VERSION 5.7 ;
  NOWIREEXTENSIONATPIN ON ;
  DIVIDERCHAR "/" ;
  BUSBITCHARS "[]" ;
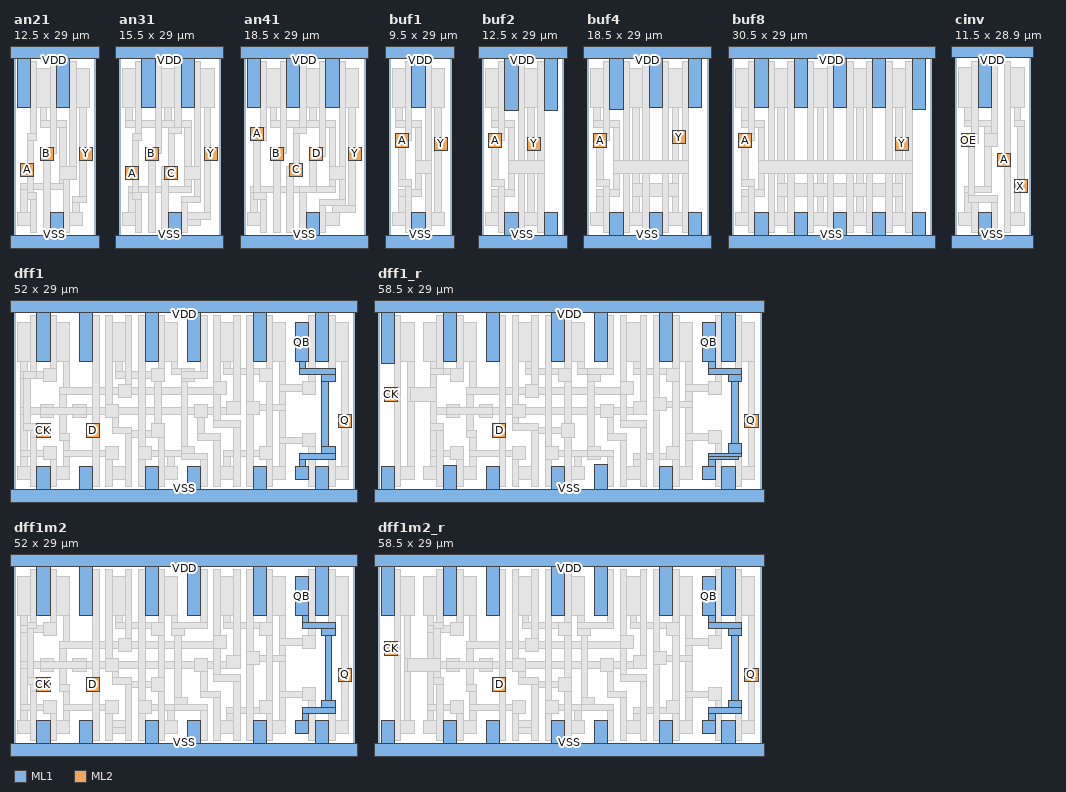
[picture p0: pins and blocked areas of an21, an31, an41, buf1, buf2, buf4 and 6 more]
MACRO an21
  CLASS CORE ;
  FOREIGN an21 ;
  ORIGIN 0.000 0.000 ;
  SIZE 12.500 BY 29.000 ;
  SYMMETRY X Y R90 ;
  SITE core ;
  PIN VSS
    DIRECTION INOUT ;
    USE GROUND ;
    SHAPE ABUTMENT ;
    PORT
      LAYER ML1 ;
        RECT 5.500 1.000 7.500 4.500 ;
        RECT -0.500 -1.000 13.000 1.000 ;
    END
  END VSS
  PIN VDD
    DIRECTION INOUT ;
    USE POWER ;
    SHAPE ABUTMENT ;
    PORT
      LAYER ML1 ;
        RECT -0.500 28.000 13.000 30.000 ;
        RECT 0.500 20.500 2.500 28.000 ;
        RECT 6.500 20.500 8.500 28.000 ;
    END
  END VDD
  PIN A
    DIRECTION INPUT ;
    USE SIGNAL ;
    PORT
      LAYER ML2 ;
        RECT 1.000 10.000 3.000 12.000 ;
    END
  END A
  PIN B
    DIRECTION INPUT ;
    USE SIGNAL ;
    PORT
      LAYER ML2 ;
        RECT 4.000 12.500 6.000 14.500 ;
    END
  END B
  PIN Y
    DIRECTION OUTPUT ;
    USE SIGNAL ;
    PORT
      LAYER ML2 ;
        RECT 10.000 12.500 12.000 14.500 ;
    END
  END Y
  OBS
      LAYER ML1 ;
        RECT 3.500 20.500 5.500 26.500 ;
        RECT 9.500 20.500 11.500 26.500 ;
        RECT 4.000 18.500 5.000 20.500 ;
        RECT 4.000 17.500 8.000 18.500 ;
        RECT 4.000 12.500 6.000 14.500 ;
        RECT 1.000 10.000 3.000 12.000 ;
        RECT 7.000 11.500 8.000 17.500 ;
        RECT 10.000 14.500 11.000 20.500 ;
        RECT 10.000 12.500 12.000 14.500 ;
        RECT 7.000 9.500 9.000 11.500 ;
        RECT 7.000 9.000 8.000 9.500 ;
        RECT 1.000 8.000 8.000 9.000 ;
        RECT 1.000 4.500 2.000 8.000 ;
        RECT 10.000 7.000 11.000 12.500 ;
        RECT 9.000 6.000 11.000 7.000 ;
        RECT 9.000 4.500 10.000 6.000 ;
        RECT 0.500 2.500 2.500 4.500 ;
        RECT 8.500 2.500 10.500 4.500 ;
      LAYER POL ;
        RECT 2.500 16.500 3.500 27.500 ;
        RECT 2.000 15.500 3.500 16.500 ;
        RECT 2.000 12.000 3.000 15.500 ;
        RECT 5.500 14.500 6.500 27.500 ;
        RECT 4.000 13.500 6.500 14.500 ;
        RECT 4.000 12.500 6.000 13.500 ;
        RECT 1.000 10.000 3.000 12.000 ;
        RECT 2.000 7.500 3.000 10.000 ;
        RECT 2.000 6.500 3.500 7.500 ;
        RECT 2.500 1.500 3.500 6.500 ;
        RECT 4.500 1.500 5.500 12.500 ;
        RECT 8.500 11.500 9.500 27.500 ;
        RECT 7.000 9.500 9.500 11.500 ;
        RECT 7.500 1.500 8.500 9.500 ;
  END
END an21

#--------EOF---------

MACRO an31
  CLASS CORE ;
  FOREIGN an31 ;
  ORIGIN 0.000 0.000 ;
  SIZE 15.500 BY 29.000 ;
  SYMMETRY X Y R90 ;
  SITE core ;
  PIN VDD
    DIRECTION INOUT ;
    USE POWER ;
    SHAPE ABUTMENT ;
    PORT
      LAYER ML1 ;
        RECT -0.500 28.000 16.000 30.000 ;
        RECT 3.500 20.500 5.500 28.000 ;
        RECT 9.500 20.500 11.500 28.000 ;
    END
  END VDD
  PIN VSS
    DIRECTION INOUT ;
    USE GROUND ;
    SHAPE ABUTMENT ;
    PORT
      LAYER ML1 ;
        RECT 7.500 1.000 9.500 4.500 ;
        RECT -0.500 -1.000 16.000 1.000 ;
    END
  END VSS
  PIN Y
    DIRECTION OUTPUT ;
    USE SIGNAL ;
    PORT
      LAYER ML2 ;
        RECT 13.000 12.500 15.000 14.500 ;
    END
  END Y
  PIN C
    DIRECTION INPUT ;
    USE SIGNAL ;
    PORT
      LAYER ML2 ;
        RECT 7.000 9.500 9.000 11.500 ;
    END
  END C
  PIN B
    DIRECTION INPUT ;
    USE SIGNAL ;
    PORT
      LAYER ML2 ;
        RECT 4.000 12.500 6.000 14.500 ;
    END
  END B
  PIN A
    DIRECTION INPUT ;
    USE SIGNAL ;
    PORT
      LAYER ML2 ;
        RECT 1.000 9.500 3.000 11.500 ;
    END
  END A
  OBS
      LAYER ML1 ;
        RECT 0.500 20.500 2.500 26.500 ;
        RECT 6.500 20.500 8.500 26.500 ;
        RECT 12.500 20.500 14.500 26.500 ;
        RECT 1.000 18.500 2.000 20.500 ;
        RECT 7.000 18.500 8.000 20.500 ;
        RECT 1.000 17.500 11.000 18.500 ;
        RECT 4.000 12.500 6.000 14.500 ;
        RECT 10.000 11.500 11.000 17.500 ;
        RECT 13.000 14.500 14.000 20.500 ;
        RECT 13.000 12.500 15.000 14.500 ;
        RECT 1.000 9.500 3.000 11.500 ;
        RECT 7.000 9.500 9.000 11.500 ;
        RECT 10.000 9.500 12.000 11.500 ;
        RECT 10.000 8.500 11.000 9.500 ;
        RECT 1.500 7.500 11.000 8.500 ;
        RECT 1.500 4.500 2.500 7.500 ;
        RECT 13.000 4.500 14.000 12.500 ;
        RECT 0.500 2.500 2.500 4.500 ;
        RECT 10.500 3.500 14.000 4.500 ;
        RECT 10.500 2.500 12.500 3.500 ;
      LAYER POL ;
        RECT 2.500 16.500 3.500 27.500 ;
        RECT 2.000 15.500 3.500 16.500 ;
        RECT 2.000 11.500 3.000 15.500 ;
        RECT 5.500 14.500 6.500 27.500 ;
        RECT 8.500 17.500 9.500 27.500 ;
        RECT 4.000 13.500 6.500 14.500 ;
        RECT 7.500 16.500 9.500 17.500 ;
        RECT 4.000 12.500 6.000 13.500 ;
        RECT 1.000 9.500 3.000 11.500 ;
        RECT 2.000 7.500 3.000 9.500 ;
        RECT 2.000 6.500 3.500 7.500 ;
        RECT 2.500 1.500 3.500 6.500 ;
        RECT 4.500 1.500 5.500 12.500 ;
        RECT 7.500 11.500 8.500 16.500 ;
        RECT 11.500 11.500 12.500 27.500 ;
        RECT 6.500 9.500 9.000 11.500 ;
        RECT 10.000 9.500 12.500 11.500 ;
        RECT 6.500 1.500 7.500 9.500 ;
        RECT 11.500 7.000 12.500 9.500 ;
        RECT 9.500 6.000 12.500 7.000 ;
        RECT 9.500 1.500 10.500 6.000 ;
  END
END an31

#--------EOF---------

MACRO an41
  CLASS CORE ;
  FOREIGN an41 ;
  ORIGIN 0.000 0.000 ;
  SIZE 18.500 BY 29.000 ;
  SYMMETRY X Y R90 ;
  SITE core ;
  PIN VSS
    DIRECTION INOUT ;
    USE GROUND ;
    SHAPE ABUTMENT ;
    PORT
      LAYER ML1 ;
        RECT 9.500 1.000 11.500 4.500 ;
        RECT -0.500 -1.000 19.000 1.000 ;
    END
  END VSS
  PIN VDD
    DIRECTION INOUT ;
    USE POWER ;
    SHAPE ABUTMENT ;
    PORT
      LAYER ML1 ;
        RECT -0.500 28.000 19.000 30.000 ;
        RECT 0.500 20.500 2.500 28.000 ;
        RECT 6.500 20.500 8.500 28.000 ;
        RECT 12.500 20.500 14.500 28.000 ;
    END
  END VDD
  PIN Y
    DIRECTION OUTPUT ;
    USE SIGNAL ;
    PORT
      LAYER ML2 ;
        RECT 16.000 12.500 18.000 14.500 ;
    END
  END Y
  PIN D
    DIRECTION INPUT ;
    USE SIGNAL ;
    PORT
      LAYER ML2 ;
        RECT 10.000 12.500 12.000 14.500 ;
    END
  END D
  PIN C
    DIRECTION INPUT ;
    USE SIGNAL ;
    PORT
      LAYER ML2 ;
        RECT 7.000 10.000 9.000 12.000 ;
    END
  END C
  PIN B
    DIRECTION INPUT ;
    USE SIGNAL ;
    PORT
      LAYER ML2 ;
        RECT 4.000 12.500 6.000 14.500 ;
    END
  END B
  PIN A
    DIRECTION INPUT ;
    USE SIGNAL ;
    PORT
      LAYER ML2 ;
        RECT 1.000 15.500 3.000 17.500 ;
    END
  END A
  OBS
      LAYER ML1 ;
        RECT 3.500 20.500 5.500 26.500 ;
        RECT 9.500 20.500 11.500 26.500 ;
        RECT 15.500 20.500 17.500 26.500 ;
        RECT 4.000 18.500 5.000 20.500 ;
        RECT 10.000 18.500 11.000 20.500 ;
        RECT 4.000 17.500 14.000 18.500 ;
        RECT 1.000 15.500 3.000 17.500 ;
        RECT 4.000 12.500 6.000 14.500 ;
        RECT 10.000 12.500 12.000 14.500 ;
        RECT 7.000 10.000 9.000 12.000 ;
        RECT 13.000 11.500 14.000 17.500 ;
        RECT 16.000 14.500 17.000 20.500 ;
        RECT 16.000 12.500 18.000 14.500 ;
        RECT 13.000 9.500 15.000 11.500 ;
        RECT 13.000 8.500 14.000 9.500 ;
        RECT 1.000 7.500 14.000 8.500 ;
        RECT 1.000 4.500 2.000 7.500 ;
        RECT 16.000 5.500 17.000 12.500 ;
        RECT 13.500 4.500 17.000 5.500 ;
        RECT 0.500 2.500 2.500 4.500 ;
        RECT 12.500 2.500 14.500 4.500 ;
      LAYER POL ;
        RECT 2.500 17.500 3.500 27.500 ;
        RECT 1.000 15.500 3.500 17.500 ;
        RECT 1.500 7.500 2.500 15.500 ;
        RECT 5.500 14.500 6.500 27.500 ;
        RECT 8.500 17.500 9.500 27.500 ;
        RECT 4.000 13.500 6.500 14.500 ;
        RECT 7.500 16.500 9.500 17.500 ;
        RECT 4.000 12.500 6.000 13.500 ;
        RECT 1.500 6.500 3.500 7.500 ;
        RECT 2.500 1.500 3.500 6.500 ;
        RECT 4.500 1.500 5.500 12.500 ;
        RECT 7.500 12.000 8.500 16.500 ;
        RECT 11.500 14.500 12.500 27.500 ;
        RECT 10.000 13.000 12.500 14.500 ;
        RECT 10.000 12.500 12.000 13.000 ;
        RECT 7.000 11.500 9.000 12.000 ;
        RECT 6.500 10.000 9.000 11.500 ;
        RECT 6.500 1.500 7.500 10.000 ;
        RECT 10.000 8.500 11.000 12.500 ;
        RECT 14.500 11.500 15.500 27.500 ;
        RECT 13.000 9.500 15.500 11.500 ;
        RECT 8.500 7.500 11.000 8.500 ;
        RECT 8.500 1.500 9.500 7.500 ;
        RECT 14.500 6.500 15.500 9.500 ;
        RECT 11.500 5.500 15.500 6.500 ;
        RECT 11.500 1.500 12.500 5.500 ;
  END
END an41

#--------EOF---------

MACRO buf1
  CLASS CORE ;
  FOREIGN buf1 ;
  ORIGIN 0.000 0.000 ;
  SIZE 9.500 BY 29.000 ;
  SYMMETRY X Y R90 ;
  SITE core ;
  PIN VDD
    DIRECTION INOUT ;
    USE POWER ;
    SHAPE ABUTMENT ;
    PORT
      LAYER ML1 ;
        RECT -0.500 28.000 10.000 30.000 ;
        RECT 3.500 20.500 5.500 28.000 ;
    END
  END VDD
  PIN VSS
    DIRECTION INOUT ;
    USE GROUND ;
    SHAPE ABUTMENT ;
    PORT
      LAYER ML1 ;
        RECT 3.500 1.000 5.500 4.500 ;
        RECT -0.500 -1.000 10.000 1.000 ;
    END
  END VSS
  PIN Y
    DIRECTION OUTPUT ;
    USE SIGNAL ;
    PORT
      LAYER ML2 ;
        RECT 7.000 14.000 9.000 16.000 ;
    END
  END Y
  PIN A
    DIRECTION INPUT ;
    USE SIGNAL ;
    PORT
      LAYER ML2 ;
        RECT 1.000 14.500 3.000 16.500 ;
    END
  END A
  OBS
      LAYER ML1 ;
        RECT 0.500 20.500 2.500 26.500 ;
        RECT 6.500 20.500 8.500 26.500 ;
        RECT 1.000 18.500 2.000 20.500 ;
        RECT 1.000 17.500 5.000 18.500 ;
        RECT 1.000 14.500 3.000 16.500 ;
        RECT 4.000 12.500 5.000 17.500 ;
        RECT 7.000 16.000 8.000 20.500 ;
        RECT 7.000 14.000 9.000 16.000 ;
        RECT 4.000 10.500 6.000 12.500 ;
        RECT 4.000 8.000 5.000 10.500 ;
        RECT 1.500 7.000 5.000 8.000 ;
        RECT 1.500 4.500 2.500 7.000 ;
        RECT 7.000 4.500 8.000 14.000 ;
        RECT 0.500 2.500 2.500 4.500 ;
        RECT 6.500 2.500 8.500 4.500 ;
      LAYER POL ;
        RECT 2.500 16.500 3.500 27.500 ;
        RECT 1.000 15.500 3.500 16.500 ;
        RECT 1.000 14.500 3.000 15.500 ;
        RECT 1.500 9.500 2.500 14.500 ;
        RECT 5.500 12.500 6.500 27.500 ;
        RECT 4.000 10.500 6.500 12.500 ;
        RECT 1.500 8.500 3.500 9.500 ;
        RECT 2.500 1.500 3.500 8.500 ;
        RECT 5.500 1.500 6.500 10.500 ;
  END
END buf1

#--------EOF---------

MACRO buf2
  CLASS CORE ;
  FOREIGN buf2 ;
  ORIGIN 0.000 0.000 ;
  SIZE 12.500 BY 29.000 ;
  SYMMETRY X Y R90 ;
  SITE core ;
  PIN VDD
    DIRECTION INOUT ;
    USE POWER ;
    SHAPE ABUTMENT ;
    PORT
      LAYER ML1 ;
        RECT -0.500 28.000 13.000 30.000 ;
        RECT 3.500 20.000 5.500 28.000 ;
        RECT 9.500 20.000 11.500 28.000 ;
    END
  END VDD
  PIN VSS
    DIRECTION INOUT ;
    USE GROUND ;
    SHAPE ABUTMENT ;
    PORT
      LAYER ML1 ;
        RECT 3.500 1.000 5.500 4.500 ;
        RECT 9.500 1.000 11.500 4.500 ;
        RECT -0.500 -1.000 13.000 1.000 ;
    END
  END VSS
  PIN A
    DIRECTION INPUT ;
    USE SIGNAL ;
    PORT
      LAYER ML2 ;
        RECT 1.000 14.500 3.000 16.500 ;
    END
  END A
  PIN Y
    DIRECTION OUTPUT ;
    USE SIGNAL ;
    PORT
      LAYER ML2 ;
        RECT 7.000 14.000 9.000 16.000 ;
    END
  END Y
  OBS
      LAYER ML1 ;
        RECT 0.500 20.500 2.500 26.500 ;
        RECT 6.500 20.500 8.500 26.500 ;
        RECT 1.500 18.500 2.500 20.500 ;
        RECT 1.500 17.500 5.000 18.500 ;
        RECT 1.000 14.500 3.000 16.500 ;
        RECT 4.000 12.500 5.000 17.500 ;
        RECT 7.000 16.000 8.000 20.500 ;
        RECT 7.000 14.000 9.000 16.000 ;
        RECT 4.000 10.500 6.000 12.500 ;
        RECT 4.000 8.000 5.000 10.500 ;
        RECT 1.500 7.000 5.000 8.000 ;
        RECT 1.500 4.500 2.500 7.000 ;
        RECT 7.000 4.500 8.000 14.000 ;
        RECT 0.500 2.500 2.500 4.500 ;
        RECT 6.500 2.500 8.500 4.500 ;
      LAYER POL ;
        RECT 2.500 16.500 3.500 27.500 ;
        RECT 1.000 15.500 3.500 16.500 ;
        RECT 1.000 14.500 3.000 15.500 ;
        RECT 1.500 9.500 2.500 14.500 ;
        RECT 5.500 12.500 6.500 27.500 ;
        RECT 8.500 12.500 9.500 27.500 ;
        RECT 4.000 10.500 9.500 12.500 ;
        RECT 1.500 8.500 3.500 9.500 ;
        RECT 2.500 1.500 3.500 8.500 ;
        RECT 5.500 1.500 6.500 10.500 ;
        RECT 8.500 1.500 9.500 10.500 ;
  END
END buf2

#--------EOF---------

MACRO buf4
  CLASS CORE ;
  FOREIGN buf4 ;
  ORIGIN 0.000 0.000 ;
  SIZE 18.500 BY 29.000 ;
  SYMMETRY X Y R90 ;
  SITE core ;
  PIN VSS
    DIRECTION INOUT ;
    USE GROUND ;
    SHAPE ABUTMENT ;
    PORT
      LAYER ML1 ;
        RECT 3.500 1.000 5.500 4.500 ;
        RECT 9.500 1.000 11.500 4.500 ;
        RECT 15.500 1.000 17.500 4.500 ;
        RECT -0.500 -1.000 19.000 1.000 ;
    END
  END VSS
  PIN VDD
    DIRECTION INOUT ;
    USE POWER ;
    SHAPE ABUTMENT ;
    PORT
      LAYER ML1 ;
        RECT -0.500 28.000 19.000 30.000 ;
        RECT 3.500 20.200 5.500 28.000 ;
        RECT 9.500 20.500 11.500 28.000 ;
        RECT 15.500 20.500 17.500 28.000 ;
    END
  END VDD
  PIN A
    DIRECTION INPUT ;
    USE SIGNAL ;
    PORT
      LAYER ML2 ;
        RECT 1.000 14.500 3.000 16.500 ;
    END
  END A
  PIN Y
    DIRECTION OUTPUT ;
    USE SIGNAL ;
    PORT
      LAYER ML2 ;
        RECT 13.000 15.000 15.000 17.000 ;
    END
  END Y
  OBS
      LAYER ML1 ;
        RECT 0.500 20.500 2.500 26.500 ;
        RECT 6.500 20.500 8.500 26.500 ;
        RECT 12.500 20.500 14.500 26.500 ;
        RECT 1.000 18.500 2.000 20.500 ;
        RECT 1.000 17.500 5.000 18.500 ;
        RECT 1.000 14.500 3.000 16.500 ;
        RECT 4.000 12.500 5.000 17.500 ;
        RECT 4.000 10.500 6.000 12.500 ;
        RECT 4.000 8.000 5.000 10.500 ;
        RECT 1.500 7.000 5.000 8.000 ;
        RECT 7.000 9.000 8.000 20.500 ;
        RECT 13.000 17.000 14.000 20.500 ;
        RECT 13.000 15.000 15.000 17.000 ;
        RECT 13.000 9.000 14.000 15.000 ;
        RECT 7.000 7.000 14.000 9.000 ;
        RECT 1.500 4.500 2.500 7.000 ;
        RECT 7.000 4.500 8.000 7.000 ;
        RECT 13.000 4.500 14.000 7.000 ;
        RECT 0.500 2.500 2.500 4.500 ;
        RECT 6.500 2.500 8.500 4.500 ;
        RECT 12.500 2.500 14.500 4.500 ;
      LAYER POL ;
        RECT 2.500 16.500 3.500 27.500 ;
        RECT 1.000 15.500 3.500 16.500 ;
        RECT 1.000 14.500 3.000 15.500 ;
        RECT 1.500 9.500 2.500 14.500 ;
        RECT 5.500 12.500 6.500 27.500 ;
        RECT 8.500 12.500 9.500 27.500 ;
        RECT 11.500 12.500 12.500 27.500 ;
        RECT 14.500 12.500 15.500 27.500 ;
        RECT 4.000 10.500 15.500 12.500 ;
        RECT 1.500 8.500 3.500 9.500 ;
        RECT 2.500 1.500 3.500 8.500 ;
        RECT 5.500 1.500 6.500 10.500 ;
        RECT 8.500 1.500 9.500 10.500 ;
        RECT 11.500 1.500 12.500 10.500 ;
        RECT 14.500 1.500 15.500 10.500 ;
  END
END buf4

#--------EOF---------

MACRO buf8
  CLASS CORE ;
  FOREIGN buf8 ;
  ORIGIN 0.000 0.000 ;
  SIZE 30.500 BY 29.000 ;
  SYMMETRY X Y R90 ;
  SITE core ;
  PIN VDD
    DIRECTION INOUT ;
    USE POWER ;
    SHAPE ABUTMENT ;
    PORT
      LAYER ML1 ;
        RECT -0.500 28.000 31.000 30.000 ;
        RECT 3.500 20.500 5.500 28.000 ;
        RECT 9.500 20.500 11.500 28.000 ;
        RECT 15.500 20.500 17.500 28.000 ;
        RECT 21.500 20.500 23.500 28.000 ;
        RECT 27.500 20.300 29.500 28.000 ;
    END
  END VDD
  PIN VSS
    DIRECTION INOUT ;
    USE GROUND ;
    SHAPE ABUTMENT ;
    PORT
      LAYER ML1 ;
        RECT 3.500 1.000 5.500 4.500 ;
        RECT 9.500 1.000 11.500 4.500 ;
        RECT 15.500 1.000 17.500 4.500 ;
        RECT 21.500 1.000 23.500 4.500 ;
        RECT 27.500 1.000 29.500 4.500 ;
        RECT -0.500 -1.000 31.000 1.000 ;
    END
  END VSS
  PIN A
    DIRECTION INPUT ;
    USE SIGNAL ;
    PORT
      LAYER ML2 ;
        RECT 1.000 14.500 3.000 16.500 ;
    END
  END A
  PIN Y
    DIRECTION OUTPUT ;
    USE SIGNAL ;
    PORT
      LAYER ML2 ;
        RECT 25.000 14.000 27.000 16.000 ;
    END
  END Y
  OBS
      LAYER ML1 ;
        RECT 0.500 20.500 2.500 26.500 ;
        RECT 6.500 20.500 8.500 26.500 ;
        RECT 12.500 20.500 14.500 26.500 ;
        RECT 18.500 20.500 20.500 26.500 ;
        RECT 24.500 20.500 26.500 26.500 ;
        RECT 1.500 18.500 2.500 20.500 ;
        RECT 1.500 17.500 5.000 18.500 ;
        RECT 1.000 14.500 3.000 16.500 ;
        RECT 4.000 12.500 5.000 17.500 ;
        RECT 4.000 10.500 6.000 12.500 ;
        RECT 4.000 8.000 5.000 10.500 ;
        RECT 1.500 7.000 5.000 8.000 ;
        RECT 7.000 9.000 8.000 20.500 ;
        RECT 13.000 9.000 14.000 20.500 ;
        RECT 19.000 9.000 20.000 20.500 ;
        RECT 25.000 16.000 26.000 20.500 ;
        RECT 25.000 14.000 27.000 16.000 ;
        RECT 25.000 9.000 26.000 14.000 ;
        RECT 7.000 7.000 26.000 9.000 ;
        RECT 1.500 4.500 2.500 7.000 ;
        RECT 7.000 4.500 8.000 7.000 ;
        RECT 13.000 4.500 14.000 7.000 ;
        RECT 19.000 4.500 20.000 7.000 ;
        RECT 25.000 4.500 26.000 7.000 ;
        RECT 0.500 2.500 2.500 4.500 ;
        RECT 6.500 2.500 8.500 4.500 ;
        RECT 12.500 2.500 14.500 4.500 ;
        RECT 18.500 2.500 20.500 4.500 ;
        RECT 24.500 2.500 26.500 4.500 ;
      LAYER POL ;
        RECT 2.500 16.500 3.500 27.500 ;
        RECT 1.000 15.500 3.500 16.500 ;
        RECT 1.000 14.500 3.000 15.500 ;
        RECT 1.500 9.500 2.500 14.500 ;
        RECT 5.500 12.500 6.500 27.500 ;
        RECT 8.500 12.500 9.500 27.500 ;
        RECT 11.500 12.500 12.500 27.500 ;
        RECT 14.500 12.500 15.500 27.500 ;
        RECT 17.500 12.500 18.500 27.500 ;
        RECT 20.500 12.500 21.500 27.500 ;
        RECT 23.500 12.500 24.500 27.500 ;
        RECT 26.500 12.500 27.500 27.500 ;
        RECT 4.000 10.500 27.500 12.500 ;
        RECT 1.500 8.500 3.500 9.500 ;
        RECT 2.500 1.500 3.500 8.500 ;
        RECT 5.500 1.500 6.500 10.500 ;
        RECT 8.500 1.500 9.500 10.500 ;
        RECT 11.500 1.500 12.500 10.500 ;
        RECT 14.500 1.500 15.500 10.500 ;
        RECT 17.500 1.500 18.500 10.500 ;
        RECT 20.500 1.500 21.500 10.500 ;
        RECT 23.500 1.500 24.500 10.500 ;
        RECT 26.500 1.500 27.500 10.500 ;
  END
END buf8

#--------EOF---------

MACRO cinv
  CLASS CORE ;
  FOREIGN cinv ;
  ORIGIN 0.000 0.000 ;
  SIZE 11.500 BY 28.900 ;
  SYMMETRY X Y R90 ;
  SITE core ;
  PIN VSS
    DIRECTION INOUT ;
    USE GROUND ;
    SHAPE ABUTMENT ;
    PORT
      LAYER ML1 ;
        RECT 3.500 1.000 5.500 4.500 ;
        RECT -0.500 -1.000 12.000 1.000 ;
    END
  END VSS
  PIN VDD
    DIRECTION INOUT ;
    USE POWER ;
    SHAPE ABUTMENT ;
    PORT
      LAYER ML1 ;
        RECT -0.500 28.000 12.000 30.000 ;
        RECT 3.500 20.500 5.500 28.000 ;
    END
  END VDD
  PIN X
    DIRECTION OUTPUT ;
    USE SIGNAL ;
    PORT
      LAYER ML2 ;
        RECT 9.000 7.500 11.000 9.500 ;
    END
  END X
  PIN OE
    DIRECTION INPUT ;
    USE SIGNAL ;
    PORT
      LAYER ML2 ;
        RECT 1.000 14.500 3.000 16.500 ;
    END
  END OE
  PIN A
    DIRECTION INPUT ;
    USE SIGNAL ;
    PORT
      LAYER ML2 ;
        RECT 6.500 11.500 8.500 13.500 ;
    END
  END A
  OBS
      LAYER ML1 ;
        RECT 0.500 20.500 2.500 26.500 ;
        RECT 8.500 20.500 10.500 26.500 ;
        RECT 1.500 18.500 2.500 20.500 ;
        RECT 9.000 18.500 10.000 20.500 ;
        RECT 1.500 17.500 5.500 18.500 ;
        RECT 9.000 17.500 10.500 18.500 ;
        RECT 4.500 16.500 5.500 17.500 ;
        RECT 1.000 14.500 3.000 16.500 ;
        RECT 4.500 14.500 6.500 16.500 ;
        RECT 4.500 8.500 5.500 14.500 ;
        RECT 6.500 11.500 8.500 13.500 ;
        RECT 9.500 9.500 10.500 17.500 ;
        RECT 1.500 7.500 5.500 8.500 ;
        RECT 9.000 7.500 11.000 9.500 ;
        RECT 1.500 4.500 2.500 7.500 ;
        RECT 9.000 4.500 10.000 7.500 ;
        RECT 0.500 2.500 2.500 4.500 ;
        RECT 8.500 2.500 10.500 4.500 ;
      LAYER POL ;
        RECT 2.500 16.500 3.500 27.500 ;
        RECT 5.500 16.500 6.500 27.500 ;
        RECT 1.000 15.000 3.500 16.500 ;
        RECT 1.000 14.500 3.000 15.000 ;
        RECT 4.500 14.500 6.500 16.500 ;
        RECT 2.000 7.000 3.000 14.500 ;
        RECT 7.500 13.500 8.500 27.500 ;
        RECT 6.500 11.500 8.500 13.500 ;
        RECT 2.000 6.000 6.500 7.000 ;
        RECT 2.500 1.500 3.500 6.000 ;
        RECT 5.500 1.500 6.500 6.000 ;
        RECT 7.500 1.500 8.500 11.500 ;
  END
END cinv

#--------EOF---------

MACRO dff1
  CLASS CORE ;
  FOREIGN dff1 ;
  ORIGIN 0.000 0.000 ;
  SIZE 52.000 BY 29.000 ;
  SYMMETRY X Y R90 ;
  SITE core ;
  PIN QB
    DIRECTION INPUT ;
    USE SIGNAL ;
    PORT
      LAYER ML1 ;
        RECT 43.000 20.500 45.000 26.500 ;
        RECT 43.500 19.500 44.500 20.500 ;
        RECT 43.500 18.500 49.000 19.500 ;
        RECT 47.000 17.500 49.000 18.500 ;
        RECT 47.000 7.500 48.000 17.500 ;
        RECT 47.000 6.500 49.000 7.500 ;
        RECT 43.500 5.500 49.000 6.500 ;
        RECT 43.500 4.500 44.500 5.500 ;
        RECT 43.000 2.500 45.000 4.500 ;
    END
  END QB
  PIN VDD
    DIRECTION INOUT ;
    USE POWER ;
    SHAPE ABUTMENT ;
    PORT
      LAYER ML1 ;
        RECT -0.500 28.000 52.500 30.000 ;
        RECT 3.500 20.500 5.500 28.000 ;
        RECT 10.000 20.500 12.000 28.000 ;
        RECT 20.000 20.500 22.000 28.000 ;
        RECT 26.500 20.500 28.500 28.000 ;
        RECT 36.500 20.500 38.500 28.000 ;
        RECT 46.000 20.500 48.000 28.000 ;
    END
  END VDD
  PIN VSS
    DIRECTION INOUT ;
    USE GROUND ;
    SHAPE ABUTMENT ;
    PORT
      LAYER ML1 ;
        RECT 3.500 1.000 5.500 4.500 ;
        RECT 10.000 1.000 12.000 4.500 ;
        RECT 20.000 1.000 22.000 4.500 ;
        RECT 26.500 1.000 28.500 4.500 ;
        RECT 36.500 1.000 38.500 4.500 ;
        RECT 46.000 1.000 48.000 4.500 ;
        RECT -0.500 -1.000 52.500 1.000 ;
    END
  END VSS
  PIN CK
    DIRECTION INPUT ;
    USE SIGNAL ;
    PORT
      LAYER ML2 ;
        RECT 3.500 9.000 5.500 11.000 ;
    END
  END CK
  PIN D
    DIRECTION INPUT ;
    USE SIGNAL ;
    PORT
      LAYER ML2 ;
        RECT 11.000 9.000 13.000 11.000 ;
    END
  END D
  PIN Q
    DIRECTION INPUT ;
    USE SIGNAL ;
    PORT
      LAYER ML2 ;
        RECT 49.500 10.500 51.500 12.500 ;
    END
  END Q
  OBS
      LAYER ML1 ;
        RECT 0.500 20.500 2.500 26.500 ;
        RECT 6.500 20.500 8.500 26.500 ;
        RECT 15.000 20.500 17.000 26.500 ;
        RECT 23.000 20.500 25.000 26.500 ;
        RECT 31.500 20.500 33.500 26.500 ;
        RECT 39.500 20.500 41.500 26.500 ;
        RECT 49.000 20.500 51.000 26.500 ;
        RECT 1.000 19.000 2.000 20.500 ;
        RECT 4.500 19.000 6.500 19.500 ;
        RECT 1.000 18.000 6.500 19.000 ;
        RECT 1.000 13.500 2.000 18.000 ;
        RECT 4.500 17.500 6.500 18.000 ;
        RECT 7.500 16.500 8.500 20.500 ;
        RECT 15.500 19.000 16.500 20.500 ;
        RECT 24.000 19.500 25.000 20.500 ;
        RECT 32.000 19.500 33.000 20.500 ;
        RECT 21.000 19.000 23.000 19.500 ;
        RECT 15.500 18.000 23.000 19.000 ;
        RECT 24.000 18.500 27.500 19.500 ;
        RECT 32.000 18.500 39.500 19.500 ;
        RECT 21.000 17.500 23.000 18.000 ;
        RECT 25.500 17.500 27.500 18.500 ;
        RECT 37.500 17.500 39.500 18.500 ;
        RECT 16.000 16.500 18.000 17.000 ;
        RECT 30.500 16.500 32.500 17.500 ;
        RECT 7.000 15.500 32.500 16.500 ;
        RECT 40.500 17.000 41.500 20.500 ;
        RECT 44.000 17.000 46.000 17.500 ;
        RECT 40.500 16.000 46.000 17.000 ;
        RECT 4.000 13.500 6.000 14.000 ;
        RECT 1.000 12.500 6.000 13.500 ;
        RECT 1.000 7.000 2.000 12.500 ;
        RECT 4.000 12.000 6.000 12.500 ;
        RECT 3.500 9.000 5.500 11.000 ;
        RECT 7.000 9.500 8.000 15.500 ;
        RECT 16.000 15.000 18.000 15.500 ;
        RECT 9.000 13.500 11.000 14.000 ;
        RECT 14.000 13.500 16.000 14.000 ;
        RECT 27.500 13.500 29.500 14.000 ;
        RECT 32.500 13.500 34.500 14.500 ;
        RECT 9.000 12.500 34.500 13.500 ;
        RECT 35.500 14.000 37.500 14.500 ;
        RECT 40.500 14.000 41.500 16.000 ;
        RECT 44.000 15.500 46.000 16.000 ;
        RECT 35.500 13.000 41.500 14.000 ;
        RECT 35.500 12.500 37.500 13.000 ;
        RECT 9.000 12.000 11.000 12.500 ;
        RECT 14.000 12.000 16.000 12.500 ;
        RECT 27.500 12.000 29.500 12.500 ;
        RECT 7.000 8.500 8.500 9.500 ;
        RECT 11.000 9.000 13.000 11.000 ;
        RECT 21.000 10.000 23.000 11.000 ;
        RECT 17.000 9.000 23.000 10.000 ;
        RECT 40.500 9.000 41.500 13.000 ;
        RECT 50.000 12.500 51.000 20.500 ;
        RECT 49.500 10.500 51.500 12.500 ;
        RECT 44.000 9.000 46.000 9.500 ;
        RECT 4.500 7.000 6.500 7.500 ;
        RECT 1.000 6.000 6.500 7.000 ;
        RECT 1.000 4.500 2.000 6.000 ;
        RECT 4.500 5.500 6.500 6.000 ;
        RECT 7.500 7.000 8.500 8.500 ;
        RECT 14.000 7.000 16.000 7.500 ;
        RECT 7.500 6.000 16.000 7.000 ;
        RECT 7.500 4.500 8.500 6.000 ;
        RECT 14.000 5.500 16.000 6.000 ;
        RECT 17.000 4.500 18.000 9.000 ;
        RECT 40.500 8.000 46.000 9.000 ;
        RECT 19.000 7.000 21.000 7.500 ;
        RECT 25.500 7.000 27.500 7.500 ;
        RECT 37.500 7.000 39.500 7.500 ;
        RECT 19.000 6.000 27.500 7.000 ;
        RECT 19.000 5.500 21.000 6.000 ;
        RECT 23.500 4.500 24.500 6.000 ;
        RECT 25.500 5.500 27.500 6.000 ;
        RECT 32.000 6.000 39.500 7.000 ;
        RECT 32.000 4.500 33.000 6.000 ;
        RECT 37.500 5.500 39.500 6.000 ;
        RECT 40.500 4.500 41.500 8.000 ;
        RECT 44.000 7.500 46.000 8.000 ;
        RECT 50.000 4.500 51.000 10.500 ;
        RECT 0.500 2.500 2.500 4.500 ;
        RECT 6.500 2.500 8.500 4.500 ;
        RECT 15.000 2.500 18.000 4.500 ;
        RECT 23.000 2.500 25.000 4.500 ;
        RECT 31.500 2.500 33.500 4.500 ;
        RECT 39.500 2.500 41.500 4.500 ;
        RECT 49.000 2.500 51.000 4.500 ;
      LAYER POL ;
        RECT 2.500 19.000 3.500 27.500 ;
        RECT 5.500 19.500 6.500 27.500 ;
        RECT 1.500 18.000 3.500 19.000 ;
        RECT 1.500 11.000 2.500 18.000 ;
        RECT 4.500 17.500 6.500 19.500 ;
        RECT 4.000 13.500 6.000 14.000 ;
        RECT 9.000 13.500 11.000 14.000 ;
        RECT 4.000 12.500 11.000 13.500 ;
        RECT 4.000 12.000 6.000 12.500 ;
        RECT 9.000 12.000 11.000 12.500 ;
        RECT 12.000 11.000 13.000 27.500 ;
        RECT 14.000 14.000 15.000 27.500 ;
        RECT 17.000 17.000 18.000 27.500 ;
        RECT 16.000 15.000 18.000 17.000 ;
        RECT 14.000 12.000 16.000 14.000 ;
        RECT 1.500 10.000 5.500 11.000 ;
        RECT 2.500 9.000 5.500 10.000 ;
        RECT 11.000 9.000 13.000 11.000 ;
        RECT 15.000 10.500 16.000 12.000 ;
        RECT 15.000 9.500 18.000 10.500 ;
        RECT 2.500 1.500 3.500 9.000 ;
        RECT 4.500 5.500 6.500 7.500 ;
        RECT 5.500 1.500 6.500 5.500 ;
        RECT 12.000 1.500 13.000 9.000 ;
        RECT 14.000 5.500 16.000 7.500 ;
        RECT 14.000 1.500 15.000 5.500 ;
        RECT 17.000 1.500 18.000 9.500 ;
        RECT 19.000 7.500 20.000 27.500 ;
        RECT 22.000 19.500 23.000 27.500 ;
        RECT 21.000 17.500 23.000 19.500 ;
        RECT 25.500 19.000 27.500 19.500 ;
        RECT 28.500 19.000 29.500 27.500 ;
        RECT 25.500 18.000 29.500 19.000 ;
        RECT 25.500 17.500 27.500 18.000 ;
        RECT 30.500 17.500 31.500 27.500 ;
        RECT 21.500 11.000 22.500 17.500 ;
        RECT 21.000 9.000 23.000 11.000 ;
        RECT 19.000 5.500 21.000 7.500 ;
        RECT 19.000 1.500 20.000 5.500 ;
        RECT 22.000 1.500 23.000 9.000 ;
        RECT 25.500 7.500 26.500 17.500 ;
        RECT 30.500 15.500 32.500 17.500 ;
        RECT 27.500 12.000 29.500 14.000 ;
        RECT 28.000 9.500 29.000 12.000 ;
        RECT 30.500 11.500 31.500 15.500 ;
        RECT 33.500 14.500 34.500 27.500 ;
        RECT 32.500 12.500 34.500 14.500 ;
        RECT 35.500 14.500 36.500 27.500 ;
        RECT 38.500 19.500 39.500 27.500 ;
        RECT 37.500 17.500 39.500 19.500 ;
        RECT 45.000 17.500 46.000 27.500 ;
        RECT 48.000 19.500 49.000 27.500 ;
        RECT 47.000 17.500 49.000 19.500 ;
        RECT 35.500 12.500 37.500 14.500 ;
        RECT 30.500 10.500 34.500 11.500 ;
        RECT 28.000 8.500 31.500 9.500 ;
        RECT 25.500 6.500 27.500 7.500 ;
        RECT 25.500 5.500 29.500 6.500 ;
        RECT 28.500 1.500 29.500 5.500 ;
        RECT 30.500 1.500 31.500 8.500 ;
        RECT 33.500 1.500 34.500 10.500 ;
        RECT 35.500 1.500 36.500 12.500 ;
        RECT 38.500 7.500 39.500 17.500 ;
        RECT 44.000 15.500 46.000 17.500 ;
        RECT 44.000 7.500 46.000 9.500 ;
        RECT 37.500 5.500 39.500 7.500 ;
        RECT 38.500 1.500 39.500 5.500 ;
        RECT 45.000 1.500 46.000 7.500 ;
        RECT 47.000 5.500 49.000 7.500 ;
        RECT 48.000 1.500 49.000 5.500 ;
  END
END dff1

#--------EOF---------

MACRO dff1_r
  CLASS CORE ;
  FOREIGN dff1_r ;
  ORIGIN 0.000 0.000 ;
  SIZE 58.500 BY 29.000 ;
  SYMMETRY X Y R90 ;
  SITE core ;
  PIN VSS
    DIRECTION INOUT ;
    USE GROUND ;
    SHAPE ABUTMENT ;
    PORT
      LAYER ML1 ;
        RECT 0.500 1.000 2.500 4.500 ;
        RECT 10.000 1.000 12.000 4.600 ;
        RECT 16.500 1.000 18.500 4.500 ;
        RECT 26.500 1.000 28.500 4.500 ;
        RECT 33.000 1.000 35.000 4.800 ;
        RECT 43.000 1.000 45.000 4.500 ;
        RECT 52.500 1.000 54.500 4.500 ;
        RECT -0.500 -1.000 59.000 1.000 ;
    END
  END VSS
  PIN VDD
    DIRECTION INOUT ;
    USE POWER ;
    SHAPE ABUTMENT ;
    PORT
      LAYER ML1 ;
        RECT -0.500 28.000 59.000 30.000 ;
        RECT 0.500 20.300 2.500 28.000 ;
        RECT 10.000 20.500 12.000 28.000 ;
        RECT 16.500 20.500 18.500 28.000 ;
        RECT 26.500 20.500 28.500 28.000 ;
        RECT 33.000 20.500 35.000 28.000 ;
        RECT 43.000 20.500 45.000 28.000 ;
        RECT 52.500 20.500 54.500 28.000 ;
    END
  END VDD
  PIN QB
    DIRECTION INPUT ;
    USE SIGNAL ;
    PORT
      LAYER ML1 ;
        RECT 49.500 20.500 51.500 26.500 ;
        RECT 50.500 19.500 51.500 20.500 ;
        RECT 50.500 18.500 55.500 19.500 ;
        RECT 53.500 17.500 55.500 18.500 ;
        RECT 54.000 8.000 55.000 17.500 ;
        RECT 53.500 6.500 55.500 8.000 ;
        RECT 50.500 6.000 55.500 6.500 ;
        RECT 50.500 5.500 55.000 6.000 ;
        RECT 50.500 4.500 51.500 5.500 ;
        RECT 49.500 2.500 51.500 4.500 ;
    END
  END QB
  PIN CK
    DIRECTION INPUT ;
    USE SIGNAL ;
    PORT
      LAYER ML2 ;
        RECT 1.000 14.500 3.000 16.500 ;
    END
  END CK
  PIN D
    DIRECTION INPUT ;
    USE SIGNAL ;
    PORT
      LAYER ML2 ;
        RECT 17.500 9.000 19.500 11.000 ;
    END
  END D
  PIN Q
    DIRECTION INPUT ;
    USE SIGNAL ;
    PORT
      LAYER ML2 ;
        RECT 56.000 10.500 58.000 12.500 ;
    END
  END Q
  OBS
      LAYER ML1 ;
        RECT 3.500 20.500 5.500 26.500 ;
        RECT 7.000 20.500 9.000 26.500 ;
        RECT 13.000 20.500 15.000 26.500 ;
        RECT 21.500 20.500 23.500 26.500 ;
        RECT 29.500 20.500 31.500 26.500 ;
        RECT 38.000 20.500 40.000 26.500 ;
        RECT 46.000 20.500 48.000 26.500 ;
        RECT 55.500 20.500 57.500 26.500 ;
        RECT 4.500 16.500 5.500 20.500 ;
        RECT 8.000 19.500 9.000 20.500 ;
        RECT 8.000 18.500 13.000 19.500 ;
        RECT 1.000 14.500 3.000 16.500 ;
        RECT 4.500 14.500 7.000 16.500 ;
        RECT 4.500 4.500 5.500 14.500 ;
        RECT 8.000 13.500 9.000 18.500 ;
        RECT 11.000 17.500 13.000 18.500 ;
        RECT 14.000 16.500 15.000 20.500 ;
        RECT 22.500 19.500 23.500 20.500 ;
        RECT 30.500 19.500 31.500 20.500 ;
        RECT 39.000 19.500 40.000 20.500 ;
        RECT 22.500 18.500 29.500 19.500 ;
        RECT 30.500 18.500 34.000 19.500 ;
        RECT 39.000 18.500 46.000 19.500 ;
        RECT 27.500 17.500 29.500 18.500 ;
        RECT 32.000 17.500 34.000 18.500 ;
        RECT 44.000 17.500 46.000 18.500 ;
        RECT 22.500 16.500 24.500 17.000 ;
        RECT 37.000 16.500 39.000 17.500 ;
        RECT 13.500 15.500 39.000 16.500 ;
        RECT 47.000 17.000 48.000 20.500 ;
        RECT 50.500 17.000 52.500 17.500 ;
        RECT 47.000 16.000 52.500 17.000 ;
        RECT 10.500 13.500 12.500 14.000 ;
        RECT 8.000 12.500 12.500 13.500 ;
        RECT 8.000 7.000 9.000 12.500 ;
        RECT 10.500 12.000 12.500 12.500 ;
        RECT 13.500 10.000 14.500 15.500 ;
        RECT 22.500 15.000 24.500 15.500 ;
        RECT 42.000 14.500 44.000 15.000 ;
        RECT 47.000 14.500 48.000 16.000 ;
        RECT 50.500 15.500 52.500 16.000 ;
        RECT 15.500 13.500 17.500 14.000 ;
        RECT 20.500 13.500 22.500 14.000 ;
        RECT 34.000 13.500 36.000 14.000 ;
        RECT 39.000 13.500 41.000 14.500 ;
        RECT 15.500 12.500 41.000 13.500 ;
        RECT 42.000 13.500 48.000 14.500 ;
        RECT 42.000 13.000 44.000 13.500 ;
        RECT 15.500 12.000 17.500 12.500 ;
        RECT 20.500 12.000 22.500 12.500 ;
        RECT 34.000 12.000 36.000 12.500 ;
        RECT 13.500 9.000 15.000 10.000 ;
        RECT 17.500 9.000 19.500 11.000 ;
        RECT 28.000 10.500 30.000 11.000 ;
        RECT 23.500 9.500 30.000 10.500 ;
        RECT 11.000 7.000 13.000 7.500 ;
        RECT 8.000 6.000 13.000 7.000 ;
        RECT 8.000 4.500 9.000 6.000 ;
        RECT 11.000 5.500 13.000 6.000 ;
        RECT 14.000 7.000 15.000 9.000 ;
        RECT 20.500 7.000 22.500 7.500 ;
        RECT 14.000 6.000 22.500 7.000 ;
        RECT 14.000 4.500 15.000 6.000 ;
        RECT 20.500 5.500 22.500 6.000 ;
        RECT 23.500 4.500 24.500 9.500 ;
        RECT 28.000 9.000 30.000 9.500 ;
        RECT 47.000 9.500 48.000 13.500 ;
        RECT 56.500 12.500 57.500 20.500 ;
        RECT 56.000 10.500 58.000 12.500 ;
        RECT 50.500 9.500 52.500 10.000 ;
        RECT 47.000 8.500 52.500 9.500 ;
        RECT 25.500 7.000 27.500 7.500 ;
        RECT 32.000 7.000 34.000 7.500 ;
        RECT 25.500 6.000 34.000 7.000 ;
        RECT 44.000 6.500 46.000 7.500 ;
        RECT 25.500 5.500 27.500 6.000 ;
        RECT 30.000 4.500 31.000 6.000 ;
        RECT 32.000 5.500 34.000 6.000 ;
        RECT 39.000 5.500 46.000 6.500 ;
        RECT 39.000 4.500 40.000 5.500 ;
        RECT 47.000 4.500 48.000 8.500 ;
        RECT 50.500 8.000 52.500 8.500 ;
        RECT 56.500 4.500 57.500 10.500 ;
        RECT 3.500 2.500 5.500 4.500 ;
        RECT 7.000 2.500 9.000 4.500 ;
        RECT 13.000 2.500 15.000 4.500 ;
        RECT 21.500 2.500 24.500 4.500 ;
        RECT 29.500 2.500 31.500 4.500 ;
        RECT 38.000 2.500 40.000 4.500 ;
        RECT 46.000 2.500 48.000 4.500 ;
        RECT 55.500 2.500 57.500 4.500 ;
      LAYER POL ;
        RECT 2.500 16.500 3.500 27.500 ;
        RECT 9.000 19.500 10.000 27.500 ;
        RECT 12.000 19.500 13.000 27.500 ;
        RECT 8.000 18.500 10.000 19.500 ;
        RECT 8.000 16.500 9.000 18.500 ;
        RECT 11.000 17.500 13.000 19.500 ;
        RECT 1.000 14.500 3.500 16.500 ;
        RECT 5.000 14.500 9.000 16.500 ;
        RECT 2.500 1.500 3.500 14.500 ;
        RECT 8.000 11.000 9.000 14.500 ;
        RECT 10.500 13.500 12.500 14.000 ;
        RECT 15.500 13.500 17.500 14.000 ;
        RECT 10.500 12.500 17.500 13.500 ;
        RECT 10.500 12.000 12.500 12.500 ;
        RECT 15.500 12.000 17.500 12.500 ;
        RECT 18.500 11.000 19.500 27.500 ;
        RECT 8.000 10.000 10.000 11.000 ;
        RECT 9.000 1.500 10.000 10.000 ;
        RECT 17.500 9.000 19.500 11.000 ;
        RECT 20.500 14.000 21.500 27.500 ;
        RECT 23.500 17.000 24.500 27.500 ;
        RECT 22.500 15.000 24.500 17.000 ;
        RECT 20.500 12.000 22.500 14.000 ;
        RECT 20.500 11.000 21.500 12.000 ;
        RECT 20.500 10.000 24.500 11.000 ;
        RECT 11.000 5.500 13.000 7.500 ;
        RECT 12.000 1.500 13.000 5.500 ;
        RECT 18.500 1.500 19.500 9.000 ;
        RECT 20.500 5.500 22.500 7.500 ;
        RECT 20.500 1.500 21.500 5.500 ;
        RECT 23.500 1.500 24.500 10.000 ;
        RECT 25.500 7.500 26.500 27.500 ;
        RECT 28.500 19.500 29.500 27.500 ;
        RECT 35.000 19.500 36.000 27.500 ;
        RECT 27.500 17.500 29.500 19.500 ;
        RECT 28.500 11.000 29.500 17.500 ;
        RECT 32.000 18.500 36.000 19.500 ;
        RECT 32.000 17.500 34.000 18.500 ;
        RECT 37.000 17.500 38.000 27.500 ;
        RECT 28.000 9.000 30.000 11.000 ;
        RECT 25.500 5.500 27.500 7.500 ;
        RECT 25.500 1.500 26.500 5.500 ;
        RECT 28.500 1.500 29.500 9.000 ;
        RECT 32.000 7.500 33.000 17.500 ;
        RECT 37.000 15.500 39.000 17.500 ;
        RECT 34.000 12.000 36.000 14.000 ;
        RECT 35.000 9.500 36.000 12.000 ;
        RECT 37.000 11.500 38.000 15.500 ;
        RECT 40.000 14.500 41.000 27.500 ;
        RECT 39.000 12.500 41.000 14.500 ;
        RECT 42.000 15.000 43.000 27.500 ;
        RECT 45.000 19.500 46.000 27.500 ;
        RECT 44.000 17.500 46.000 19.500 ;
        RECT 51.500 17.500 52.500 27.500 ;
        RECT 54.500 19.500 55.500 27.500 ;
        RECT 53.500 17.500 55.500 19.500 ;
        RECT 42.000 13.000 44.000 15.000 ;
        RECT 37.000 10.500 41.000 11.500 ;
        RECT 35.000 8.500 38.000 9.500 ;
        RECT 32.000 7.000 34.000 7.500 ;
        RECT 32.000 6.000 36.000 7.000 ;
        RECT 32.000 5.500 34.000 6.000 ;
        RECT 35.000 1.500 36.000 6.000 ;
        RECT 37.000 1.500 38.000 8.500 ;
        RECT 40.000 1.500 41.000 10.500 ;
        RECT 42.000 1.500 43.000 13.000 ;
        RECT 45.000 7.500 46.000 17.500 ;
        RECT 50.500 15.500 52.500 17.500 ;
        RECT 50.500 8.000 52.500 10.000 ;
        RECT 44.000 5.500 46.000 7.500 ;
        RECT 45.000 1.500 46.000 5.500 ;
        RECT 51.500 1.500 52.500 8.000 ;
        RECT 53.500 6.000 55.500 8.000 ;
        RECT 54.500 1.500 55.500 6.000 ;
  END
END dff1_r

#--------EOF---------

MACRO dff1m2
  CLASS CORE ;
  FOREIGN dff1m2 ;
  ORIGIN 0.000 0.000 ;
  SIZE 52.000 BY 29.000 ;
  SYMMETRY X Y R90 ;
  SITE core ;
  PIN QB
    DIRECTION INPUT ;
    USE SIGNAL ;
    PORT
      LAYER ML1 ;
        RECT 43.000 20.500 45.000 26.500 ;
        RECT 44.000 19.500 45.000 20.500 ;
        RECT 44.000 18.500 49.000 19.500 ;
        RECT 47.000 17.500 49.000 18.500 ;
        RECT 47.500 7.500 48.500 17.500 ;
        RECT 47.000 6.500 49.000 7.500 ;
        RECT 44.000 5.500 49.000 6.500 ;
        RECT 44.000 4.500 45.000 5.500 ;
        RECT 43.000 2.500 45.000 4.500 ;
    END
  END QB
  PIN VSS
    DIRECTION INOUT ;
    USE GROUND ;
    SHAPE ABUTMENT ;
    PORT
      LAYER ML1 ;
        RECT 3.500 1.000 5.500 4.500 ;
        RECT 10.000 1.000 12.000 4.500 ;
        RECT 20.000 1.000 22.000 4.500 ;
        RECT 26.500 1.000 28.500 4.500 ;
        RECT 36.500 1.000 38.500 4.500 ;
        RECT 46.000 1.000 48.000 4.500 ;
        RECT -0.500 -1.000 52.500 1.000 ;
    END
  END VSS
  PIN VDD
    DIRECTION INOUT ;
    USE POWER ;
    SHAPE ABUTMENT ;
    PORT
      LAYER ML1 ;
        RECT -0.500 28.000 52.500 30.000 ;
        RECT 3.500 20.500 5.500 28.000 ;
        RECT 10.000 20.500 12.000 28.000 ;
        RECT 20.000 20.500 22.000 28.000 ;
        RECT 26.500 20.500 28.500 28.000 ;
        RECT 36.500 20.500 38.500 28.000 ;
        RECT 46.000 20.500 48.000 28.000 ;
    END
  END VDD
  PIN CK
    DIRECTION INPUT ;
    USE SIGNAL ;
    PORT
      LAYER ML2 ;
        RECT 3.500 9.000 5.500 11.000 ;
    END
  END CK
  PIN D
    DIRECTION INPUT ;
    USE SIGNAL ;
    PORT
      LAYER ML2 ;
        RECT 11.000 9.000 13.000 11.000 ;
    END
  END D
  PIN Q
    DIRECTION INPUT ;
    USE SIGNAL ;
    PORT
      LAYER ML2 ;
        RECT 49.500 10.500 51.500 12.500 ;
    END
  END Q
  OBS
      LAYER ML1 ;
        RECT 0.500 20.500 2.500 26.500 ;
        RECT 6.500 20.500 8.500 26.500 ;
        RECT 15.000 20.500 17.000 26.500 ;
        RECT 23.000 20.500 25.000 26.500 ;
        RECT 31.500 20.500 33.500 26.500 ;
        RECT 39.500 20.500 41.500 26.500 ;
        RECT 49.000 20.500 51.000 26.500 ;
        RECT 1.000 19.000 2.000 20.500 ;
        RECT 4.500 19.000 6.500 19.500 ;
        RECT 1.000 18.000 6.500 19.000 ;
        RECT 1.000 13.500 2.000 18.000 ;
        RECT 4.500 17.500 6.500 18.000 ;
        RECT 7.500 16.500 8.500 20.500 ;
        RECT 15.500 19.500 16.500 20.500 ;
        RECT 24.000 19.500 25.000 20.500 ;
        RECT 32.000 19.500 33.000 20.500 ;
        RECT 15.500 18.500 23.000 19.500 ;
        RECT 21.000 17.500 23.000 18.500 ;
        RECT 24.000 17.500 26.000 19.500 ;
        RECT 32.000 18.500 39.500 19.500 ;
        RECT 37.500 17.500 39.500 18.500 ;
        RECT 16.000 16.500 18.000 17.000 ;
        RECT 30.500 16.500 32.500 17.500 ;
        RECT 7.000 15.500 32.500 16.500 ;
        RECT 40.500 17.000 41.500 20.500 ;
        RECT 44.000 17.000 46.000 17.500 ;
        RECT 40.500 16.000 46.000 17.000 ;
        RECT 4.000 13.500 6.000 14.000 ;
        RECT 1.000 12.500 6.000 13.500 ;
        RECT 1.000 7.000 2.000 12.500 ;
        RECT 4.000 12.000 6.000 12.500 ;
        RECT 3.500 9.000 5.500 11.000 ;
        RECT 7.000 10.000 8.000 15.500 ;
        RECT 16.000 15.000 18.000 15.500 ;
        RECT 35.500 14.500 37.500 15.000 ;
        RECT 40.500 14.500 41.500 16.000 ;
        RECT 44.000 15.500 46.000 16.000 ;
        RECT 9.000 13.500 11.000 14.000 ;
        RECT 14.000 13.500 16.000 14.000 ;
        RECT 27.500 13.500 29.500 14.000 ;
        RECT 32.500 13.500 34.500 14.500 ;
        RECT 9.000 12.500 34.500 13.500 ;
        RECT 35.500 13.500 41.500 14.500 ;
        RECT 35.500 13.000 37.500 13.500 ;
        RECT 9.000 12.000 11.000 12.500 ;
        RECT 14.000 12.000 16.000 12.500 ;
        RECT 27.500 12.000 29.500 12.500 ;
        RECT 7.000 9.000 8.500 10.000 ;
        RECT 11.000 9.000 13.000 11.000 ;
        RECT 21.000 10.500 23.000 11.000 ;
        RECT 17.000 9.500 23.000 10.500 ;
        RECT 4.500 7.000 6.500 7.500 ;
        RECT 1.000 6.000 6.500 7.000 ;
        RECT 1.000 4.500 2.000 6.000 ;
        RECT 4.500 5.500 6.500 6.000 ;
        RECT 7.500 7.000 8.500 9.000 ;
        RECT 14.000 7.000 16.000 7.500 ;
        RECT 7.500 6.000 16.000 7.000 ;
        RECT 7.500 4.500 8.500 6.000 ;
        RECT 14.000 5.500 16.000 6.000 ;
        RECT 17.000 4.500 18.000 9.500 ;
        RECT 21.000 9.000 23.000 9.500 ;
        RECT 40.500 9.000 41.500 13.500 ;
        RECT 50.000 12.500 51.000 20.500 ;
        RECT 49.500 10.500 51.500 12.500 ;
        RECT 44.000 9.000 46.000 9.500 ;
        RECT 40.500 8.000 46.000 9.000 ;
        RECT 19.000 7.000 21.000 7.500 ;
        RECT 24.500 7.000 26.500 8.000 ;
        RECT 19.000 6.000 26.500 7.000 ;
        RECT 37.500 6.500 39.500 7.500 ;
        RECT 19.000 5.500 21.000 6.000 ;
        RECT 23.500 4.500 24.500 6.000 ;
        RECT 32.500 5.500 39.500 6.500 ;
        RECT 32.500 4.500 33.500 5.500 ;
        RECT 40.500 4.500 41.500 8.000 ;
        RECT 44.000 7.500 46.000 8.000 ;
        RECT 50.000 4.500 51.000 10.500 ;
        RECT 0.500 2.500 2.500 4.500 ;
        RECT 6.500 2.500 8.500 4.500 ;
        RECT 15.000 3.500 18.000 4.500 ;
        RECT 15.000 2.500 17.000 3.500 ;
        RECT 23.000 2.500 25.000 4.500 ;
        RECT 31.500 2.500 33.500 4.500 ;
        RECT 39.500 2.500 41.500 4.500 ;
        RECT 49.000 2.500 51.000 4.500 ;
      LAYER ML2 ;
        RECT 21.000 17.500 23.000 19.500 ;
        RECT 24.000 17.500 26.000 19.500 ;
        RECT 37.500 17.500 39.500 19.500 ;
        RECT 22.000 11.000 23.000 17.500 ;
        RECT 21.000 9.000 23.000 11.000 ;
        RECT 24.500 8.000 25.500 17.500 ;
        RECT 24.500 6.000 26.500 8.000 ;
        RECT 38.500 7.500 39.500 17.500 ;
        RECT 37.500 5.500 39.500 7.500 ;
      LAYER POL ;
        RECT 2.500 19.500 3.500 27.500 ;
        RECT 5.500 19.500 6.500 27.500 ;
        RECT 2.000 18.500 3.500 19.500 ;
        RECT 2.000 11.000 3.000 18.500 ;
        RECT 4.500 17.500 6.500 19.500 ;
        RECT 4.000 13.500 6.000 14.000 ;
        RECT 9.000 13.500 11.000 14.000 ;
        RECT 4.000 12.500 11.000 13.500 ;
        RECT 4.000 12.000 6.000 12.500 ;
        RECT 9.000 12.000 11.000 12.500 ;
        RECT 12.000 11.000 13.000 27.500 ;
        RECT 14.000 14.000 15.000 27.500 ;
        RECT 17.000 17.000 18.000 27.500 ;
        RECT 16.000 15.000 18.000 17.000 ;
        RECT 14.000 12.000 16.000 14.000 ;
        RECT 2.000 10.000 5.500 11.000 ;
        RECT 2.500 9.000 5.500 10.000 ;
        RECT 11.000 9.000 13.000 11.000 ;
        RECT 15.000 11.000 16.000 12.000 ;
        RECT 15.000 10.000 18.000 11.000 ;
        RECT 2.500 1.500 3.500 9.000 ;
        RECT 4.500 5.500 6.500 7.500 ;
        RECT 5.500 1.500 6.500 5.500 ;
        RECT 12.000 1.500 13.000 9.000 ;
        RECT 14.000 5.500 16.000 7.500 ;
        RECT 14.000 1.500 15.000 5.500 ;
        RECT 17.000 1.500 18.000 10.000 ;
        RECT 19.000 7.500 20.000 27.500 ;
        RECT 22.000 19.500 23.000 27.500 ;
        RECT 28.500 19.500 29.500 27.500 ;
        RECT 21.000 17.500 23.000 19.500 ;
        RECT 24.000 18.500 29.500 19.500 ;
        RECT 24.000 17.500 26.000 18.500 ;
        RECT 30.500 17.500 31.500 27.500 ;
        RECT 30.500 15.500 32.500 17.500 ;
        RECT 27.500 12.000 29.500 14.000 ;
        RECT 21.000 9.000 23.000 11.000 ;
        RECT 19.000 5.500 21.000 7.500 ;
        RECT 19.000 1.500 20.000 5.500 ;
        RECT 22.000 1.500 23.000 9.000 ;
        RECT 28.500 9.000 29.500 12.000 ;
        RECT 30.500 11.500 31.500 15.500 ;
        RECT 33.500 14.500 34.500 27.500 ;
        RECT 32.500 12.500 34.500 14.500 ;
        RECT 35.500 15.000 36.500 27.500 ;
        RECT 38.500 19.500 39.500 27.500 ;
        RECT 37.500 17.500 39.500 19.500 ;
        RECT 45.000 17.500 46.000 27.500 ;
        RECT 48.000 19.500 49.000 27.500 ;
        RECT 47.000 17.500 49.000 19.500 ;
        RECT 44.000 15.500 46.000 17.500 ;
        RECT 35.500 13.000 37.500 15.000 ;
        RECT 30.500 10.500 34.500 11.500 ;
        RECT 28.500 8.000 31.500 9.000 ;
        RECT 24.500 7.000 26.500 8.000 ;
        RECT 24.500 6.000 29.500 7.000 ;
        RECT 28.500 1.500 29.500 6.000 ;
        RECT 30.500 1.500 31.500 8.000 ;
        RECT 33.500 1.500 34.500 10.500 ;
        RECT 35.500 1.500 36.500 13.000 ;
        RECT 44.000 7.500 46.000 9.500 ;
        RECT 37.500 5.500 39.500 7.500 ;
        RECT 38.500 1.500 39.500 5.500 ;
        RECT 45.000 1.500 46.000 7.500 ;
        RECT 47.000 5.500 49.000 7.500 ;
        RECT 48.000 1.500 49.000 5.500 ;
  END
END dff1m2

#--------EOF---------

MACRO dff1m2_r
  CLASS CORE ;
  FOREIGN dff1m2_r ;
  ORIGIN 0.000 0.000 ;
  SIZE 58.500 BY 29.000 ;
  SYMMETRY X Y R90 ;
  SITE core ;
  PIN QB
    DIRECTION INPUT ;
    USE SIGNAL ;
    PORT
      LAYER ML1 ;
        RECT 49.500 20.500 51.500 26.500 ;
        RECT 50.500 19.500 51.500 20.500 ;
        RECT 50.500 18.500 55.500 19.500 ;
        RECT 53.500 17.500 55.500 18.500 ;
        RECT 54.000 7.500 55.000 17.500 ;
        RECT 53.500 6.500 55.500 7.500 ;
        RECT 50.500 5.500 55.500 6.500 ;
        RECT 50.500 4.500 51.500 5.500 ;
        RECT 49.500 2.500 51.500 4.500 ;
    END
  END QB
  PIN VDD
    DIRECTION INOUT ;
    USE POWER ;
    SHAPE ABUTMENT ;
    PORT
      LAYER ML1 ;
        RECT -0.500 28.000 59.000 30.000 ;
        RECT 0.500 20.500 2.500 28.000 ;
        RECT 10.000 20.500 12.000 28.000 ;
        RECT 16.500 20.500 18.500 28.000 ;
        RECT 26.500 20.500 28.500 28.000 ;
        RECT 33.000 20.500 35.000 28.000 ;
        RECT 43.000 20.500 45.000 28.000 ;
        RECT 52.500 20.500 54.500 28.000 ;
    END
  END VDD
  PIN VSS
    DIRECTION INOUT ;
    USE GROUND ;
    SHAPE ABUTMENT ;
    PORT
      LAYER ML1 ;
        RECT 0.500 1.000 2.500 4.500 ;
        RECT 10.000 1.000 12.000 4.500 ;
        RECT 16.500 1.000 18.500 4.500 ;
        RECT 26.500 1.000 28.500 4.500 ;
        RECT 33.000 1.000 35.000 4.500 ;
        RECT 43.000 1.000 45.000 4.500 ;
        RECT 52.500 1.000 54.500 4.500 ;
        RECT -0.500 -1.000 59.000 1.000 ;
    END
  END VSS
  PIN CK
    DIRECTION INPUT ;
    USE SIGNAL ;
    PORT
      LAYER ML2 ;
        RECT 1.000 14.500 3.000 16.500 ;
    END
  END CK
  PIN D
    DIRECTION INPUT ;
    USE SIGNAL ;
    PORT
      LAYER ML2 ;
        RECT 17.500 9.000 19.500 11.000 ;
    END
  END D
  PIN Q
    DIRECTION INPUT ;
    USE SIGNAL ;
    PORT
      LAYER ML2 ;
        RECT 56.000 10.500 58.000 12.500 ;
    END
  END Q
  OBS
      LAYER ML1 ;
        RECT 3.500 20.500 5.500 26.500 ;
        RECT 7.000 20.500 9.000 26.500 ;
        RECT 13.000 20.500 15.000 26.500 ;
        RECT 21.500 20.500 23.500 26.500 ;
        RECT 29.500 20.500 31.500 26.500 ;
        RECT 38.000 20.500 40.000 26.500 ;
        RECT 46.000 20.500 48.000 26.500 ;
        RECT 55.500 20.500 57.500 26.500 ;
        RECT 1.000 14.500 3.000 16.500 ;
        RECT 4.000 14.000 5.000 20.500 ;
        RECT 7.500 19.000 8.500 20.500 ;
        RECT 11.000 19.000 13.000 19.500 ;
        RECT 7.500 18.000 13.000 19.000 ;
        RECT 4.000 12.000 6.500 14.000 ;
        RECT 7.500 13.500 8.500 18.000 ;
        RECT 11.000 17.500 13.000 18.000 ;
        RECT 14.000 16.500 15.000 20.500 ;
        RECT 22.000 19.500 23.000 20.500 ;
        RECT 30.500 19.500 31.500 20.500 ;
        RECT 38.500 19.500 39.500 20.500 ;
        RECT 22.000 18.500 29.500 19.500 ;
        RECT 27.500 17.500 29.500 18.500 ;
        RECT 30.500 17.500 32.500 19.500 ;
        RECT 38.500 18.500 46.000 19.500 ;
        RECT 44.000 17.500 46.000 18.500 ;
        RECT 22.500 16.500 24.500 17.000 ;
        RECT 37.000 16.500 39.000 17.500 ;
        RECT 13.500 15.500 39.000 16.500 ;
        RECT 47.000 17.000 48.000 20.500 ;
        RECT 50.500 17.000 52.500 17.500 ;
        RECT 47.000 16.000 52.500 17.000 ;
        RECT 10.500 13.500 12.500 14.000 ;
        RECT 7.500 12.500 12.500 13.500 ;
        RECT 4.000 4.500 5.000 12.000 ;
        RECT 7.500 7.000 8.500 12.500 ;
        RECT 10.500 12.000 12.500 12.500 ;
        RECT 13.500 10.000 14.500 15.500 ;
        RECT 22.500 15.000 24.500 15.500 ;
        RECT 42.000 14.500 44.000 15.000 ;
        RECT 47.000 14.500 48.000 16.000 ;
        RECT 50.500 15.500 52.500 16.000 ;
        RECT 15.500 13.500 17.500 14.000 ;
        RECT 20.500 13.500 22.500 14.000 ;
        RECT 34.000 13.500 36.000 14.000 ;
        RECT 39.000 13.500 41.000 14.500 ;
        RECT 15.500 12.500 41.000 13.500 ;
        RECT 42.000 13.500 48.000 14.500 ;
        RECT 42.000 13.000 44.000 13.500 ;
        RECT 15.500 12.000 17.500 12.500 ;
        RECT 20.500 12.000 22.500 12.500 ;
        RECT 34.000 12.000 36.000 12.500 ;
        RECT 13.500 9.000 15.000 10.000 ;
        RECT 17.500 9.000 19.500 11.000 ;
        RECT 27.500 10.500 29.500 11.000 ;
        RECT 23.500 9.500 29.500 10.500 ;
        RECT 11.000 7.000 13.000 7.500 ;
        RECT 7.500 6.000 13.000 7.000 ;
        RECT 7.500 4.500 8.500 6.000 ;
        RECT 11.000 5.500 13.000 6.000 ;
        RECT 14.000 7.000 15.000 9.000 ;
        RECT 20.500 7.000 22.500 7.500 ;
        RECT 14.000 6.000 22.500 7.000 ;
        RECT 14.000 4.500 15.000 6.000 ;
        RECT 20.500 5.500 22.500 6.000 ;
        RECT 23.500 4.500 24.500 9.500 ;
        RECT 27.500 9.000 29.500 9.500 ;
        RECT 47.000 9.000 48.000 13.500 ;
        RECT 56.500 12.500 57.500 20.500 ;
        RECT 56.000 10.500 58.000 12.500 ;
        RECT 50.500 9.000 52.500 9.500 ;
        RECT 47.000 8.000 52.500 9.000 ;
        RECT 25.500 7.000 27.500 7.500 ;
        RECT 31.000 7.000 33.000 8.000 ;
        RECT 25.500 6.000 33.000 7.000 ;
        RECT 44.000 6.500 46.000 7.500 ;
        RECT 25.500 5.500 27.500 6.000 ;
        RECT 30.000 4.500 31.000 6.000 ;
        RECT 39.000 5.500 46.000 6.500 ;
        RECT 39.000 4.500 40.000 5.500 ;
        RECT 47.000 4.500 48.000 8.000 ;
        RECT 50.500 7.500 52.500 8.000 ;
        RECT 56.500 4.500 57.500 10.500 ;
        RECT 3.500 2.500 5.500 4.500 ;
        RECT 7.000 2.500 9.000 4.500 ;
        RECT 13.000 2.500 15.000 4.500 ;
        RECT 21.500 3.500 24.500 4.500 ;
        RECT 21.500 2.500 23.500 3.500 ;
        RECT 29.500 2.500 31.500 4.500 ;
        RECT 38.000 2.500 40.000 4.500 ;
        RECT 46.000 2.500 48.000 4.500 ;
        RECT 55.500 2.500 57.500 4.500 ;
      LAYER ML2 ;
        RECT 27.500 17.500 29.500 19.500 ;
        RECT 30.500 17.500 32.500 19.500 ;
        RECT 44.000 17.500 46.000 19.500 ;
        RECT 28.500 11.000 29.500 17.500 ;
        RECT 27.500 9.000 29.500 11.000 ;
        RECT 31.000 8.000 32.000 17.500 ;
        RECT 31.000 6.000 33.000 8.000 ;
        RECT 45.000 7.500 46.000 17.500 ;
        RECT 44.000 5.500 46.000 7.500 ;
      LAYER POL ;
        RECT 2.500 16.500 3.500 27.500 ;
        RECT 9.000 19.500 10.000 27.500 ;
        RECT 12.000 19.500 13.000 27.500 ;
        RECT 1.000 14.500 3.500 16.500 ;
        RECT 2.500 1.500 3.500 14.500 ;
        RECT 8.500 18.500 10.000 19.500 ;
        RECT 8.500 14.000 9.500 18.500 ;
        RECT 11.000 17.500 13.000 19.500 ;
        RECT 4.500 12.000 9.500 14.000 ;
        RECT 10.500 13.500 12.500 14.000 ;
        RECT 15.500 13.500 17.500 14.000 ;
        RECT 10.500 12.500 17.500 13.500 ;
        RECT 10.500 12.000 12.500 12.500 ;
        RECT 15.500 12.000 17.500 12.500 ;
        RECT 8.500 11.000 9.500 12.000 ;
        RECT 18.500 11.000 19.500 27.500 ;
        RECT 20.500 14.000 21.500 27.500 ;
        RECT 23.500 17.000 24.500 27.500 ;
        RECT 22.500 15.000 24.500 17.000 ;
        RECT 20.500 12.000 22.500 14.000 ;
        RECT 8.500 10.000 10.000 11.000 ;
        RECT 9.000 1.500 10.000 10.000 ;
        RECT 17.500 9.000 19.500 11.000 ;
        RECT 21.500 11.000 22.500 12.000 ;
        RECT 21.500 10.000 24.500 11.000 ;
        RECT 11.000 5.500 13.000 7.500 ;
        RECT 12.000 1.500 13.000 5.500 ;
        RECT 18.500 1.500 19.500 9.000 ;
        RECT 20.500 5.500 22.500 7.500 ;
        RECT 20.500 1.500 21.500 5.500 ;
        RECT 23.500 1.500 24.500 10.000 ;
        RECT 25.500 7.500 26.500 27.500 ;
        RECT 28.500 19.500 29.500 27.500 ;
        RECT 35.000 19.500 36.000 27.500 ;
        RECT 27.500 17.500 29.500 19.500 ;
        RECT 30.500 18.500 36.000 19.500 ;
        RECT 30.500 17.500 32.500 18.500 ;
        RECT 37.000 17.500 38.000 27.500 ;
        RECT 37.000 15.500 39.000 17.500 ;
        RECT 34.000 12.000 36.000 14.000 ;
        RECT 27.500 9.000 29.500 11.000 ;
        RECT 25.500 5.500 27.500 7.500 ;
        RECT 25.500 1.500 26.500 5.500 ;
        RECT 28.500 1.500 29.500 9.000 ;
        RECT 35.000 9.000 36.000 12.000 ;
        RECT 37.000 11.500 38.000 15.500 ;
        RECT 40.000 14.500 41.000 27.500 ;
        RECT 39.000 12.500 41.000 14.500 ;
        RECT 42.000 15.000 43.000 27.500 ;
        RECT 45.000 19.500 46.000 27.500 ;
        RECT 44.000 17.500 46.000 19.500 ;
        RECT 51.500 17.500 52.500 27.500 ;
        RECT 54.500 19.500 55.500 27.500 ;
        RECT 53.500 17.500 55.500 19.500 ;
        RECT 50.500 15.500 52.500 17.500 ;
        RECT 42.000 13.000 44.000 15.000 ;
        RECT 37.000 10.500 41.000 11.500 ;
        RECT 35.000 8.000 38.000 9.000 ;
        RECT 31.000 7.000 33.000 8.000 ;
        RECT 31.000 6.000 36.000 7.000 ;
        RECT 35.000 1.500 36.000 6.000 ;
        RECT 37.000 1.500 38.000 8.000 ;
        RECT 40.000 1.500 41.000 10.500 ;
        RECT 42.000 1.500 43.000 13.000 ;
        RECT 50.500 7.500 52.500 9.500 ;
        RECT 44.000 5.500 46.000 7.500 ;
        RECT 45.000 1.500 46.000 5.500 ;
        RECT 51.500 1.500 52.500 7.500 ;
        RECT 53.500 5.500 55.500 7.500 ;
        RECT 54.500 1.500 55.500 5.500 ;
  END
END dff1m2_r

#--------EOF---------

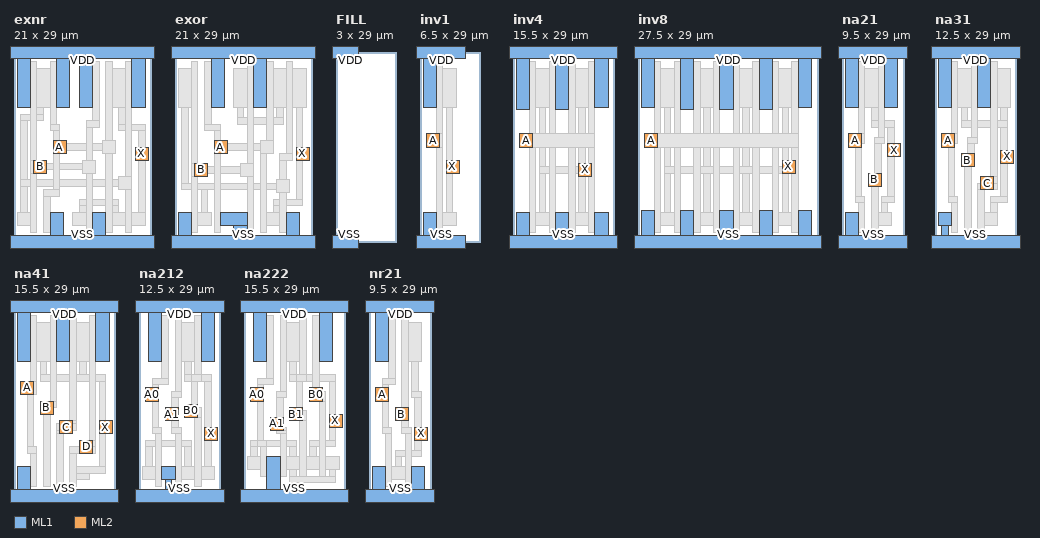
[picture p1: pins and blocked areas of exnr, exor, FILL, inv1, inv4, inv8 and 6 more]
MACRO exnr
  CLASS CORE ;
  FOREIGN exnr ;
  ORIGIN 0.000 0.000 ;
  SIZE 21.000 BY 29.000 ;
  SYMMETRY X Y R90 ;
  SITE core ;
  PIN VSS
    DIRECTION INOUT ;
    USE GROUND ;
    SHAPE ABUTMENT ;
    PORT
      LAYER ML1 ;
        RECT 5.500 1.000 7.500 4.500 ;
        RECT 12.000 1.000 14.000 4.500 ;
        RECT -0.500 -1.000 21.500 1.000 ;
    END
  END VSS
  PIN VDD
    DIRECTION INOUT ;
    USE POWER ;
    SHAPE ABUTMENT ;
    PORT
      LAYER ML1 ;
        RECT -0.500 28.000 21.500 30.000 ;
        RECT 0.500 20.500 2.500 28.000 ;
        RECT 6.500 20.500 8.500 28.000 ;
        RECT 10.000 20.500 12.000 28.000 ;
        RECT 18.000 20.500 20.000 28.000 ;
    END
  END VDD
  PIN X
    DIRECTION OUTPUT ;
    USE SIGNAL ;
    PORT
      LAYER ML2 ;
        RECT 18.500 12.500 20.500 14.500 ;
    END
  END X
  PIN B
    DIRECTION INPUT ;
    USE SIGNAL ;
    PORT
      LAYER ML2 ;
        RECT 3.000 10.500 5.000 12.500 ;
    END
  END B
  PIN A
    DIRECTION INPUT ;
    USE SIGNAL ;
    PORT
      LAYER ML2 ;
        RECT 6.000 13.500 8.000 15.500 ;
    END
  END A
  OBS
      LAYER ML1 ;
        RECT 3.500 20.500 5.500 26.500 ;
        RECT 15.000 20.500 17.000 26.500 ;
        RECT 3.500 19.500 4.500 20.500 ;
        RECT 1.000 18.500 4.500 19.500 ;
        RECT 1.000 9.500 2.000 18.500 ;
        RECT 16.000 18.000 17.000 20.500 ;
        RECT 16.000 17.000 20.000 18.000 ;
        RECT 6.000 15.000 8.000 15.500 ;
        RECT 13.500 15.000 15.500 15.500 ;
        RECT 6.000 14.000 15.500 15.000 ;
        RECT 19.000 14.500 20.000 17.000 ;
        RECT 6.000 13.500 8.000 14.000 ;
        RECT 13.500 13.500 15.500 14.000 ;
        RECT 18.500 12.500 20.500 14.500 ;
        RECT 3.000 12.000 5.000 12.500 ;
        RECT 10.500 12.000 12.500 12.500 ;
        RECT 3.000 11.000 12.500 12.000 ;
        RECT 3.000 10.500 5.000 11.000 ;
        RECT 10.500 10.500 12.500 11.000 ;
        RECT 16.000 9.500 18.000 10.000 ;
        RECT 1.000 8.500 18.000 9.500 ;
        RECT 1.000 4.500 2.000 8.500 ;
        RECT 16.000 8.000 18.000 8.500 ;
        RECT 10.000 5.500 16.000 6.500 ;
        RECT 10.000 4.500 11.000 5.500 ;
        RECT 0.500 2.500 2.500 4.500 ;
        RECT 9.000 2.500 11.000 4.500 ;
        RECT 15.000 4.500 16.000 5.500 ;
        RECT 19.000 4.500 20.000 12.500 ;
        RECT 15.000 2.500 17.000 4.500 ;
        RECT 18.000 2.500 20.000 4.500 ;
      LAYER POL ;
        RECT 2.500 12.500 3.500 27.500 ;
        RECT 5.500 18.000 6.500 27.500 ;
        RECT 12.000 18.500 13.000 27.500 ;
        RECT 5.500 17.000 7.000 18.000 ;
        RECT 6.000 15.500 7.000 17.000 ;
        RECT 11.000 17.500 13.000 18.500 ;
        RECT 6.000 13.500 8.000 15.500 ;
        RECT 2.500 10.500 5.000 12.500 ;
        RECT 2.500 1.500 3.500 10.500 ;
        RECT 6.000 8.000 7.000 13.500 ;
        RECT 11.000 12.500 12.000 17.500 ;
        RECT 14.000 15.500 15.000 27.500 ;
        RECT 13.500 13.500 15.500 15.500 ;
        RECT 10.500 10.500 12.500 12.500 ;
        RECT 4.500 7.000 7.000 8.000 ;
        RECT 4.500 1.500 5.500 7.000 ;
        RECT 11.000 1.500 12.000 10.500 ;
        RECT 14.000 1.500 15.000 13.500 ;
        RECT 17.000 10.000 18.000 27.500 ;
        RECT 16.000 8.000 18.000 10.000 ;
        RECT 17.000 1.500 18.000 8.000 ;
  END
END exnr

#--------EOF---------

MACRO exor
  CLASS CORE ;
  FOREIGN exor ;
  ORIGIN 0.000 0.000 ;
  SIZE 21.000 BY 29.000 ;
  SYMMETRY X Y R90 ;
  SITE core ;
  PIN VSS
    DIRECTION INOUT ;
    USE GROUND ;
    SHAPE ABUTMENT ;
    PORT
      LAYER ML1 ;
        RECT 0.500 1.000 2.500 4.500 ;
        RECT 7.000 2.500 11.000 4.500 ;
        RECT 9.000 1.000 11.000 2.500 ;
        RECT 17.000 1.000 19.000 4.500 ;
        RECT -0.500 -1.000 21.500 1.000 ;
    END
  END VSS
  PIN VDD
    DIRECTION INOUT ;
    USE POWER ;
    SHAPE ABUTMENT ;
    PORT
      LAYER ML1 ;
        RECT -0.500 28.000 21.500 30.000 ;
        RECT 5.500 20.500 7.500 28.000 ;
        RECT 12.000 20.500 14.000 28.000 ;
    END
  END VDD
  PIN X
    DIRECTION OUTPUT ;
    USE SIGNAL ;
    PORT
      LAYER ML2 ;
        RECT 18.500 12.500 20.500 14.500 ;
    END
  END X
  PIN A
    DIRECTION INPUT ;
    USE SIGNAL ;
    PORT
      LAYER ML2 ;
        RECT 6.000 13.500 8.000 15.500 ;
    END
  END A
  PIN B
    DIRECTION INPUT ;
    USE SIGNAL ;
    PORT
      LAYER ML2 ;
        RECT 3.000 10.000 5.000 12.000 ;
    END
  END B
  OBS
      LAYER ML1 ;
        RECT 0.500 20.500 2.500 26.500 ;
        RECT 9.000 20.500 11.000 26.500 ;
        RECT 15.000 20.500 17.000 26.500 ;
        RECT 18.000 20.500 20.000 26.500 ;
        RECT 1.000 9.000 2.000 20.500 ;
        RECT 9.500 19.000 10.500 20.500 ;
        RECT 15.500 19.000 16.500 20.500 ;
        RECT 9.500 18.000 16.500 19.000 ;
        RECT 6.000 15.000 8.000 15.500 ;
        RECT 13.000 15.000 15.000 15.500 ;
        RECT 6.000 14.000 15.000 15.000 ;
        RECT 6.000 13.500 8.000 14.000 ;
        RECT 13.000 13.500 15.000 14.000 ;
        RECT 18.500 14.500 19.500 20.500 ;
        RECT 18.500 12.500 20.500 14.500 ;
        RECT 3.000 11.500 5.000 12.000 ;
        RECT 10.000 11.500 12.000 12.000 ;
        RECT 3.000 10.500 12.000 11.500 ;
        RECT 3.000 10.000 5.000 10.500 ;
        RECT 10.000 10.000 12.000 10.500 ;
        RECT 15.500 9.000 17.500 9.500 ;
        RECT 1.000 8.000 17.500 9.000 ;
        RECT 4.000 4.500 5.000 8.000 ;
        RECT 15.500 7.500 17.500 8.000 ;
        RECT 18.500 6.500 19.500 12.500 ;
        RECT 15.000 5.500 19.500 6.500 ;
        RECT 15.000 4.500 16.000 5.500 ;
        RECT 3.500 2.500 5.500 4.500 ;
        RECT 14.000 2.500 16.000 4.500 ;
      LAYER POL ;
        RECT 2.500 12.000 3.500 27.500 ;
        RECT 4.500 18.000 5.500 27.500 ;
        RECT 4.500 17.000 7.000 18.000 ;
        RECT 6.000 15.500 7.000 17.000 ;
        RECT 6.000 13.500 8.000 15.500 ;
        RECT 2.500 10.000 5.000 12.000 ;
        RECT 2.500 1.500 3.500 10.000 ;
        RECT 6.000 1.500 7.000 13.500 ;
        RECT 11.000 12.000 12.000 27.500 ;
        RECT 14.000 15.500 15.000 27.500 ;
        RECT 10.000 10.000 12.000 12.000 ;
        RECT 11.000 1.500 12.000 10.000 ;
        RECT 13.000 13.500 15.000 15.500 ;
        RECT 17.000 13.500 18.000 27.500 ;
        RECT 13.000 1.500 14.000 13.500 ;
        RECT 16.000 12.500 18.000 13.500 ;
        RECT 16.000 9.500 17.000 12.500 ;
        RECT 15.500 7.500 17.500 9.500 ;
        RECT 16.000 1.500 17.000 7.500 ;
  END
END exor

#--------EOF---------

MACRO FILL
  CLASS CORE ;
  FOREIGN FILL ;
  ORIGIN 0.000 0.000 ;
  SIZE 3.000 BY 29.000 ;
  SYMMETRY X Y R90 ;
  SITE core ;
  PIN VDD
    DIRECTION INOUT ;
    USE POWER ;
    SHAPE ABUTMENT ;
    PORT
      LAYER ML1 ;
        RECT -0.500 28.000 3.500 30.000 ;
    END
  END VDD
  PIN VSS
    DIRECTION INOUT ;
    USE GROUND ;
    SHAPE ABUTMENT ;
    PORT
      LAYER ML1 ;
        RECT -0.500 -1.000 3.500 1.000 ;
    END
  END VSS
END FILL

#--------EOF---------

MACRO inv1
  CLASS CORE ;
  FOREIGN inv1 ;
  ORIGIN 0.000 0.000 ;
  SIZE 6.500 BY 29.000 ;
  SYMMETRY X Y R90 ;
  SITE core ;
  PIN VSS
    DIRECTION INOUT ;
    USE GROUND ;
    SHAPE ABUTMENT ;
    PORT
      LAYER ML1 ;
        RECT 0.500 1.000 2.500 4.500 ;
        RECT -0.500 -1.000 7.000 1.000 ;
    END
  END VSS
  PIN VDD
    DIRECTION INOUT ;
    USE POWER ;
    SHAPE ABUTMENT ;
    PORT
      LAYER ML1 ;
        RECT -0.500 28.000 7.000 30.000 ;
        RECT 0.500 20.500 2.500 28.000 ;
    END
  END VDD
  PIN X
    DIRECTION OUTPUT ;
    USE SIGNAL ;
    PORT
      LAYER ML2 ;
        RECT 4.000 10.500 6.000 12.500 ;
    END
  END X
  PIN A
    DIRECTION INPUT ;
    USE SIGNAL ;
    PORT
      LAYER ML2 ;
        RECT 1.000 14.500 3.000 16.500 ;
    END
  END A
  OBS
      LAYER ML1 ;
        RECT 3.500 20.500 5.500 26.500 ;
        RECT 1.000 14.500 3.000 16.500 ;
        RECT 4.000 12.500 5.000 20.500 ;
        RECT 4.000 10.500 6.000 12.500 ;
        RECT 4.000 4.500 5.000 10.500 ;
        RECT 3.500 2.500 5.500 4.500 ;
      LAYER POL ;
        RECT 2.500 16.500 3.500 27.500 ;
        RECT 1.000 14.500 3.500 16.500 ;
        RECT 2.500 1.500 3.500 14.500 ;
  END
END inv1

#--------EOF---------

MACRO inv4
  CLASS CORE ;
  FOREIGN inv4 ;
  ORIGIN 0.000 0.000 ;
  SIZE 15.500 BY 29.000 ;
  SYMMETRY X Y R90 ;
  SITE core ;
  PIN VDD
    DIRECTION INOUT ;
    USE POWER ;
    SHAPE ABUTMENT ;
    PORT
      LAYER ML1 ;
        RECT -0.500 28.000 16.000 30.000 ;
        RECT 0.500 20.300 2.500 28.000 ;
        RECT 6.500 20.300 8.500 28.000 ;
        RECT 12.500 20.500 14.500 28.000 ;
    END
  END VDD
  PIN VSS
    DIRECTION INOUT ;
    USE GROUND ;
    SHAPE ABUTMENT ;
    PORT
      LAYER ML1 ;
        RECT 0.500 1.000 2.500 4.500 ;
        RECT 6.500 1.000 8.500 4.500 ;
        RECT 12.500 1.000 14.500 4.500 ;
        RECT -0.500 -1.000 16.000 1.000 ;
    END
  END VSS
  PIN A
    DIRECTION INPUT ;
    USE SIGNAL ;
    PORT
      LAYER ML2 ;
        RECT 1.000 14.500 3.000 16.500 ;
    END
  END A
  PIN X
    DIRECTION OUTPUT ;
    USE SIGNAL ;
    PORT
      LAYER ML2 ;
        RECT 10.000 10.000 12.000 12.000 ;
    END
  END X
  OBS
      LAYER ML1 ;
        RECT 3.500 20.500 5.500 26.500 ;
        RECT 9.500 20.500 11.500 26.500 ;
        RECT 1.000 14.500 3.000 16.500 ;
        RECT 4.000 11.500 5.000 20.500 ;
        RECT 10.000 12.000 11.000 20.500 ;
        RECT 10.000 11.500 12.000 12.000 ;
        RECT 4.000 10.500 12.000 11.500 ;
        RECT 4.000 4.500 5.000 10.500 ;
        RECT 10.000 10.000 12.000 10.500 ;
        RECT 10.000 4.500 11.000 10.000 ;
        RECT 3.500 2.500 5.500 4.500 ;
        RECT 9.500 2.500 11.500 4.500 ;
      LAYER POL ;
        RECT 2.500 16.500 3.500 27.500 ;
        RECT 5.500 16.500 6.500 27.500 ;
        RECT 8.500 16.500 9.500 27.500 ;
        RECT 11.500 16.500 12.500 27.500 ;
        RECT 1.000 14.500 12.500 16.500 ;
        RECT 2.500 1.500 3.500 14.500 ;
        RECT 5.500 1.500 6.500 14.500 ;
        RECT 8.500 1.500 9.500 14.500 ;
        RECT 11.500 1.500 12.500 14.500 ;
  END
END inv4

#--------EOF---------

MACRO inv8
  CLASS CORE ;
  FOREIGN inv8 ;
  ORIGIN 0.000 0.000 ;
  SIZE 27.500 BY 29.000 ;
  SYMMETRY X Y R90 ;
  SITE core ;
  PIN VSS
    DIRECTION INOUT ;
    USE GROUND ;
    SHAPE ABUTMENT ;
    PORT
      LAYER ML1 ;
        RECT 0.500 1.000 2.500 4.800 ;
        RECT 6.500 1.000 8.500 4.800 ;
        RECT 12.500 1.000 14.500 4.800 ;
        RECT 18.500 1.000 20.500 4.800 ;
        RECT 24.500 1.000 26.500 4.800 ;
        RECT -0.500 -1.000 28.000 1.000 ;
    END
  END VSS
  PIN VDD
    DIRECTION INOUT ;
    USE POWER ;
    SHAPE ABUTMENT ;
    PORT
      LAYER ML1 ;
        RECT -0.500 28.000 28.000 30.000 ;
        RECT 0.500 20.500 2.500 28.000 ;
        RECT 6.500 20.300 8.500 28.000 ;
        RECT 12.500 20.300 14.500 28.000 ;
        RECT 18.500 20.300 20.500 28.000 ;
        RECT 24.500 20.500 26.500 28.000 ;
    END
  END VDD
  PIN X
    DIRECTION OUTPUT ;
    USE SIGNAL ;
    PORT
      LAYER ML2 ;
        RECT 22.000 10.500 24.000 12.500 ;
    END
  END X
  PIN A
    DIRECTION INPUT ;
    USE SIGNAL ;
    PORT
      LAYER ML2 ;
        RECT 1.000 14.500 3.000 16.500 ;
    END
  END A
  OBS
      LAYER ML1 ;
        RECT 3.500 20.500 5.500 26.500 ;
        RECT 9.500 20.500 11.500 26.500 ;
        RECT 15.500 20.500 17.500 26.500 ;
        RECT 21.500 20.500 23.500 26.500 ;
        RECT 1.000 14.500 3.000 16.500 ;
        RECT 4.000 11.500 5.000 20.500 ;
        RECT 10.000 11.500 11.000 20.500 ;
        RECT 16.000 11.500 17.000 20.500 ;
        RECT 22.000 12.500 23.000 20.500 ;
        RECT 22.000 11.500 24.000 12.500 ;
        RECT 4.000 10.500 24.000 11.500 ;
        RECT 4.000 4.500 5.000 10.500 ;
        RECT 10.000 4.500 11.000 10.500 ;
        RECT 16.000 4.500 17.000 10.500 ;
        RECT 22.000 4.500 23.000 10.500 ;
        RECT 3.500 2.500 5.500 4.500 ;
        RECT 9.500 2.500 11.500 4.500 ;
        RECT 15.500 2.500 17.500 4.500 ;
        RECT 21.500 2.500 23.500 4.500 ;
      LAYER POL ;
        RECT 2.500 16.500 3.500 27.500 ;
        RECT 5.500 16.500 6.500 27.500 ;
        RECT 8.500 16.500 9.500 27.500 ;
        RECT 11.500 16.500 12.500 27.500 ;
        RECT 14.500 16.500 15.500 27.500 ;
        RECT 17.500 16.500 18.500 27.500 ;
        RECT 20.500 16.500 21.500 27.500 ;
        RECT 23.500 16.500 24.500 27.500 ;
        RECT 1.000 14.500 24.500 16.500 ;
        RECT 2.500 1.500 3.500 14.500 ;
        RECT 5.500 1.500 6.500 14.500 ;
        RECT 8.500 1.500 9.500 14.500 ;
        RECT 11.500 1.500 12.500 14.500 ;
        RECT 14.500 1.500 15.500 14.500 ;
        RECT 17.500 1.500 18.500 14.500 ;
        RECT 20.500 1.500 21.500 14.500 ;
        RECT 23.500 1.500 24.500 14.500 ;
  END
END inv8

#--------EOF---------

MACRO na21
  CLASS CORE ;
  FOREIGN na21 ;
  ORIGIN 0.000 0.000 ;
  SIZE 9.500 BY 29.000 ;
  SYMMETRY X Y R90 ;
  SITE core ;
  PIN VSS
    DIRECTION INOUT ;
    USE GROUND ;
    SHAPE ABUTMENT ;
    PORT
      LAYER ML1 ;
        RECT 0.500 1.000 2.500 4.500 ;
        RECT -0.500 -1.000 10.000 1.000 ;
    END
  END VSS
  PIN VDD
    DIRECTION INOUT ;
    USE POWER ;
    SHAPE ABUTMENT ;
    PORT
      LAYER ML1 ;
        RECT -0.500 28.000 10.000 30.000 ;
        RECT 0.500 20.500 2.500 28.000 ;
        RECT 6.500 20.500 8.500 28.000 ;
    END
  END VDD
  PIN A
    DIRECTION INPUT ;
    USE SIGNAL ;
    PORT
      LAYER ML2 ;
        RECT 1.000 14.500 3.000 16.500 ;
    END
  END A
  PIN B
    DIRECTION INPUT ;
    USE SIGNAL ;
    PORT
      LAYER ML2 ;
        RECT 4.000 8.500 6.000 10.500 ;
    END
  END B
  PIN X
    DIRECTION OUTPUT ;
    USE SIGNAL ;
    PORT
      LAYER ML2 ;
        RECT 7.000 13.000 9.000 15.000 ;
    END
  END X
  OBS
      LAYER ML1 ;
        RECT 3.500 20.500 5.500 26.500 ;
        RECT 4.500 18.500 5.500 20.500 ;
        RECT 4.500 17.500 8.000 18.500 ;
        RECT 1.000 14.500 3.000 16.500 ;
        RECT 7.000 15.000 8.000 17.500 ;
        RECT 7.000 13.000 9.000 15.000 ;
        RECT 4.000 8.500 6.000 10.500 ;
        RECT 7.000 7.000 8.000 13.000 ;
        RECT 6.000 6.000 8.000 7.000 ;
        RECT 6.000 4.500 7.000 6.000 ;
        RECT 5.500 2.500 7.500 4.500 ;
      LAYER POL ;
        RECT 2.500 16.500 3.500 27.500 ;
        RECT 1.000 15.000 3.500 16.500 ;
        RECT 5.500 16.000 6.500 27.500 ;
        RECT 5.000 15.000 6.500 16.000 ;
        RECT 1.000 14.500 3.000 15.000 ;
        RECT 2.000 7.000 3.000 14.500 ;
        RECT 5.000 10.500 6.000 15.000 ;
        RECT 4.000 8.500 6.000 10.500 ;
        RECT 2.000 6.000 3.500 7.000 ;
        RECT 2.500 1.500 3.500 6.000 ;
        RECT 4.500 1.500 5.500 8.500 ;
  END
END na21

#--------EOF---------

MACRO na31
  CLASS CORE ;
  FOREIGN na31 ;
  ORIGIN 0.000 0.000 ;
  SIZE 12.500 BY 29.000 ;
  SYMMETRY X Y R90 ;
  SITE core ;
  PIN VDD
    DIRECTION INOUT ;
    USE POWER ;
    SHAPE ABUTMENT ;
    PORT
      LAYER ML1 ;
        RECT -0.500 28.000 13.000 30.000 ;
        RECT 0.500 20.500 2.500 28.000 ;
        RECT 6.500 20.500 8.500 28.000 ;
    END
  END VDD
  PIN VSS
    DIRECTION INOUT ;
    USE GROUND ;
    SHAPE ABUTMENT ;
    PORT
      LAYER ML1 ;
        RECT 0.500 2.500 2.500 4.500 ;
        RECT 1.000 1.000 2.000 2.500 ;
        RECT -0.500 -1.000 13.000 1.000 ;
    END
  END VSS
  PIN X
    DIRECTION OUTPUT ;
    USE SIGNAL ;
    PORT
      LAYER ML2 ;
        RECT 10.000 12.000 12.000 14.000 ;
    END
  END X
  PIN C
    DIRECTION INPUT ;
    USE SIGNAL ;
    PORT
      LAYER ML2 ;
        RECT 7.000 8.000 9.000 10.000 ;
    END
  END C
  PIN B
    DIRECTION INPUT ;
    USE SIGNAL ;
    PORT
      LAYER ML2 ;
        RECT 4.000 11.500 6.000 13.500 ;
    END
  END B
  PIN A
    DIRECTION INPUT ;
    USE SIGNAL ;
    PORT
      LAYER ML2 ;
        RECT 1.000 14.500 3.000 16.500 ;
    END
  END A
  OBS
      LAYER ML1 ;
        RECT 3.500 20.500 5.500 26.500 ;
        RECT 9.500 20.500 11.500 26.500 ;
        RECT 4.000 18.500 5.000 20.500 ;
        RECT 10.000 18.500 11.000 20.500 ;
        RECT 4.000 17.500 11.000 18.500 ;
        RECT 1.000 14.500 3.000 16.500 ;
        RECT 10.000 14.000 11.000 17.500 ;
        RECT 4.000 11.500 6.000 13.500 ;
        RECT 10.000 12.000 12.000 14.000 ;
        RECT 7.000 8.000 9.000 10.000 ;
        RECT 10.000 7.000 11.000 12.000 ;
        RECT 8.500 6.000 11.000 7.000 ;
        RECT 8.500 4.500 9.500 6.000 ;
        RECT 7.500 2.500 9.500 4.500 ;
      LAYER POL ;
        RECT 2.500 16.500 3.500 27.500 ;
        RECT 1.000 15.000 3.500 16.500 ;
        RECT 5.500 16.000 6.500 27.500 ;
        RECT 5.000 15.000 6.500 16.000 ;
        RECT 1.000 14.500 3.000 15.000 ;
        RECT 2.000 7.000 3.000 14.500 ;
        RECT 5.000 13.500 6.000 15.000 ;
        RECT 4.000 11.500 6.000 13.500 ;
        RECT 2.000 6.000 3.500 7.000 ;
        RECT 2.500 1.500 3.500 6.000 ;
        RECT 4.500 1.500 5.500 11.500 ;
        RECT 8.500 10.000 9.500 27.500 ;
        RECT 7.000 9.000 9.500 10.000 ;
        RECT 6.500 8.000 9.500 9.000 ;
        RECT 6.500 1.500 7.500 8.000 ;
  END
END na31

#--------EOF---------

MACRO na41
  CLASS CORE ;
  FOREIGN na41 ;
  ORIGIN 0.000 0.000 ;
  SIZE 15.500 BY 29.000 ;
  SYMMETRY X Y R90 ;
  SITE core ;
  PIN VDD
    DIRECTION INOUT ;
    USE POWER ;
    SHAPE ABUTMENT ;
    PORT
      LAYER ML1 ;
        RECT -0.500 28.000 16.000 30.000 ;
        RECT 0.500 20.500 2.500 28.000 ;
        RECT 6.500 20.500 8.500 28.000 ;
        RECT 12.500 20.500 14.500 28.000 ;
    END
  END VDD
  PIN VSS
    DIRECTION INOUT ;
    USE GROUND ;
    SHAPE ABUTMENT ;
    PORT
      LAYER ML1 ;
        RECT 0.500 1.000 2.500 4.500 ;
        RECT -0.500 -1.000 16.000 1.000 ;
    END
  END VSS
  PIN A
    DIRECTION INPUT ;
    USE SIGNAL ;
    PORT
      LAYER ML2 ;
        RECT 1.000 15.500 3.000 17.500 ;
    END
  END A
  PIN B
    DIRECTION INPUT ;
    USE SIGNAL ;
    PORT
      LAYER ML2 ;
        RECT 4.000 12.500 6.000 14.500 ;
    END
  END B
  PIN C
    DIRECTION INPUT ;
    USE SIGNAL ;
    PORT
      LAYER ML2 ;
        RECT 7.000 9.500 9.000 11.500 ;
    END
  END C
  PIN D
    DIRECTION INPUT ;
    USE SIGNAL ;
    PORT
      LAYER ML2 ;
        RECT 10.000 6.500 12.000 8.500 ;
    END
  END D
  PIN X
    DIRECTION OUTPUT ;
    USE SIGNAL ;
    PORT
      LAYER ML2 ;
        RECT 13.000 9.500 15.000 11.500 ;
    END
  END X
  OBS
      LAYER ML1 ;
        RECT 3.500 20.500 5.500 26.500 ;
        RECT 9.500 20.500 11.500 26.500 ;
        RECT 4.000 18.500 5.000 20.500 ;
        RECT 10.000 18.500 11.000 20.500 ;
        RECT 4.000 17.500 14.000 18.500 ;
        RECT 1.000 15.500 3.000 17.500 ;
        RECT 4.000 12.500 6.000 14.500 ;
        RECT 13.000 11.500 14.000 17.500 ;
        RECT 7.000 9.500 9.000 11.500 ;
        RECT 13.000 9.500 15.000 11.500 ;
        RECT 10.000 6.500 12.000 8.500 ;
        RECT 13.000 4.500 14.000 9.500 ;
        RECT 9.500 3.500 14.000 4.500 ;
        RECT 9.500 2.500 11.500 3.500 ;
      LAYER POL ;
        RECT 2.500 17.500 3.500 27.500 ;
        RECT 1.000 15.500 3.500 17.500 ;
        RECT 2.000 7.500 3.000 15.500 ;
        RECT 5.500 14.500 6.500 27.500 ;
        RECT 4.000 13.500 6.500 14.500 ;
        RECT 4.000 12.500 6.000 13.500 ;
        RECT 2.000 6.500 3.500 7.500 ;
        RECT 2.500 1.500 3.500 6.500 ;
        RECT 4.500 1.500 5.500 12.500 ;
        RECT 8.500 11.500 9.500 27.500 ;
        RECT 7.000 11.000 9.500 11.500 ;
        RECT 6.500 10.000 9.500 11.000 ;
        RECT 6.500 9.500 9.000 10.000 ;
        RECT 6.500 1.500 7.500 9.500 ;
        RECT 11.500 8.500 12.500 27.500 ;
        RECT 10.000 7.500 12.500 8.500 ;
        RECT 8.500 6.500 12.500 7.500 ;
        RECT 8.500 1.500 9.500 6.500 ;
  END
END na41

#--------EOF---------

MACRO na212
  CLASS CORE ;
  FOREIGN na212 ;
  ORIGIN 0.000 0.000 ;
  SIZE 12.500 BY 29.000 ;
  SYMMETRY X Y R90 ;
  SITE core ;
  PIN VDD
    DIRECTION INOUT ;
    USE POWER ;
    SHAPE ABUTMENT ;
    PORT
      LAYER ML1 ;
        RECT -0.500 28.000 13.000 30.000 ;
        RECT 1.500 20.500 3.500 28.000 ;
        RECT 9.500 20.500 11.500 28.000 ;
    END
  END VDD
  PIN VSS
    DIRECTION INOUT ;
    USE GROUND ;
    SHAPE ABUTMENT ;
    PORT
      LAYER ML1 ;
        RECT 3.500 2.500 5.500 4.500 ;
        RECT 4.000 1.000 5.000 2.500 ;
        RECT -0.500 -1.000 13.000 1.000 ;
    END
  END VSS
  PIN A1
    DIRECTION INPUT ;
    USE SIGNAL ;
    PORT
      LAYER ML2 ;
        RECT 4.000 11.500 6.000 13.500 ;
    END
  END A1
  PIN A0
    DIRECTION INPUT ;
    USE SIGNAL ;
    PORT
      LAYER ML2 ;
        RECT 1.000 14.500 3.000 16.500 ;
    END
  END A0
  PIN B0
    DIRECTION INPUT ;
    USE SIGNAL ;
    PORT
      LAYER ML2 ;
        RECT 7.000 12.000 9.000 14.000 ;
    END
  END B0
  PIN X
    DIRECTION OUTPUT ;
    USE SIGNAL ;
    PORT
      LAYER ML2 ;
        RECT 10.000 8.500 12.000 10.500 ;
    END
  END X
  OBS
      LAYER ML1 ;
        RECT 6.500 20.500 8.500 26.500 ;
        RECT 7.000 18.500 8.000 20.500 ;
        RECT 7.000 17.500 11.000 18.500 ;
        RECT 1.000 14.500 3.000 16.500 ;
        RECT 4.000 11.500 6.000 13.500 ;
        RECT 7.000 12.000 9.000 14.000 ;
        RECT 10.000 10.500 11.000 17.500 ;
        RECT 10.000 8.500 12.000 10.500 ;
        RECT 1.000 7.500 8.000 8.500 ;
        RECT 1.000 4.500 2.000 7.500 ;
        RECT 7.000 4.500 8.000 7.500 ;
        RECT 10.000 4.500 11.000 8.500 ;
        RECT 0.500 2.500 2.500 4.500 ;
        RECT 6.500 2.500 8.500 4.500 ;
        RECT 9.500 2.500 11.500 4.500 ;
      LAYER POL ;
        RECT 3.500 18.000 4.500 27.500 ;
        RECT 2.000 17.000 4.500 18.000 ;
        RECT 2.000 16.500 3.000 17.000 ;
        RECT 1.000 14.500 3.000 16.500 ;
        RECT 5.500 16.000 6.500 27.500 ;
        RECT 8.500 18.500 9.500 27.500 ;
        RECT 2.000 10.500 3.000 14.500 ;
        RECT 5.000 15.000 6.500 16.000 ;
        RECT 8.000 17.500 9.500 18.500 ;
        RECT 5.000 13.500 6.000 15.000 ;
        RECT 8.000 14.000 9.000 17.500 ;
        RECT 4.000 11.500 6.000 13.500 ;
        RECT 7.000 13.500 9.000 14.000 ;
        RECT 7.000 12.000 9.500 13.500 ;
        RECT 5.000 10.500 6.000 11.500 ;
        RECT 2.000 9.500 3.500 10.500 ;
        RECT 5.000 9.500 6.500 10.500 ;
        RECT 2.500 1.500 3.500 9.500 ;
        RECT 5.500 1.500 6.500 9.500 ;
        RECT 8.500 1.500 9.500 12.000 ;
  END
END na212

#--------EOF---------

MACRO na222
  CLASS CORE ;
  FOREIGN na222 ;
  ORIGIN 0.000 0.000 ;
  SIZE 15.500 BY 29.000 ;
  SYMMETRY X Y R90 ;
  SITE core ;
  PIN VDD
    DIRECTION INOUT ;
    USE POWER ;
    SHAPE ABUTMENT ;
    PORT
      LAYER ML1 ;
        RECT -0.500 28.000 16.000 30.000 ;
        RECT 1.500 20.500 3.500 28.000 ;
        RECT 11.500 20.500 13.500 28.000 ;
    END
  END VDD
  PIN VSS
    DIRECTION INOUT ;
    USE GROUND ;
    SHAPE ABUTMENT ;
    PORT
      LAYER ML1 ;
        RECT 3.500 1.000 5.500 6.000 ;
        RECT -0.500 -1.000 16.000 1.000 ;
    END
  END VSS
  PIN B0
    DIRECTION INPUT ;
    USE SIGNAL ;
    PORT
      LAYER ML2 ;
        RECT 10.000 14.500 12.000 16.500 ;
    END
  END B0
  PIN X
    DIRECTION OUTPUT ;
    USE SIGNAL ;
    PORT
      LAYER ML2 ;
        RECT 13.000 10.500 15.000 12.500 ;
    END
  END X
  PIN A0
    DIRECTION INPUT ;
    USE SIGNAL ;
    PORT
      LAYER ML2 ;
        RECT 1.000 14.500 3.000 16.500 ;
    END
  END A0
  PIN A1
    DIRECTION INPUT ;
    USE SIGNAL ;
    PORT
      LAYER ML2 ;
        RECT 4.000 10.000 6.000 12.000 ;
    END
  END A1
  PIN B1
    DIRECTION INPUT ;
    USE SIGNAL ;
    PORT
      LAYER ML2 ;
        RECT 7.000 11.500 9.000 13.500 ;
    END
  END B1
  OBS
      LAYER ML1 ;
        RECT 6.500 20.500 8.500 26.500 ;
        RECT 7.000 18.500 8.000 20.500 ;
        RECT 7.000 17.500 14.000 18.500 ;
        RECT 1.000 14.500 3.000 16.500 ;
        RECT 10.000 14.500 12.000 16.500 ;
        RECT 4.000 10.000 6.000 12.000 ;
        RECT 7.000 11.500 9.000 13.500 ;
        RECT 13.000 12.500 14.000 17.500 ;
        RECT 13.000 10.500 15.000 12.500 ;
        RECT 13.000 8.500 14.000 10.500 ;
        RECT 1.000 7.500 8.000 8.500 ;
        RECT 1.000 6.000 2.000 7.500 ;
        RECT 7.000 6.000 8.000 7.500 ;
        RECT 10.000 7.500 14.000 8.500 ;
        RECT 10.000 6.000 11.000 7.500 ;
        RECT 0.500 4.000 2.500 6.000 ;
        RECT 6.500 4.000 8.500 6.000 ;
        RECT 9.500 4.000 11.500 6.000 ;
        RECT 12.500 4.000 14.500 6.000 ;
        RECT 7.000 3.000 8.000 4.000 ;
        RECT 13.000 3.000 14.000 4.000 ;
        RECT 7.000 2.000 14.000 3.000 ;
      LAYER POL ;
        RECT 3.500 18.000 4.500 27.500 ;
        RECT 2.000 17.000 4.500 18.000 ;
        RECT 2.000 16.500 3.000 17.000 ;
        RECT 1.000 14.500 3.000 16.500 ;
        RECT 5.500 16.000 6.500 27.500 ;
        RECT 8.500 18.500 9.500 27.500 ;
        RECT 2.000 8.500 3.000 14.500 ;
        RECT 5.000 15.000 6.500 16.000 ;
        RECT 8.000 17.500 9.500 18.500 ;
        RECT 5.000 12.000 6.000 15.000 ;
        RECT 8.000 13.500 9.000 17.500 ;
        RECT 10.500 16.500 11.500 27.500 ;
        RECT 10.000 16.000 12.000 16.500 ;
        RECT 10.000 14.500 12.500 16.000 ;
        RECT 4.000 10.500 6.000 12.000 ;
        RECT 7.000 13.000 9.000 13.500 ;
        RECT 7.000 11.500 9.500 13.000 ;
        RECT 4.000 10.000 6.500 10.500 ;
        RECT 5.000 9.500 6.500 10.000 ;
        RECT 2.000 7.500 3.500 8.500 ;
        RECT 2.500 3.000 3.500 7.500 ;
        RECT 5.500 3.000 6.500 9.500 ;
        RECT 8.500 3.000 9.500 11.500 ;
        RECT 11.500 3.000 12.500 14.500 ;
  END
END na222

#--------EOF---------

MACRO nr21
  CLASS CORE ;
  FOREIGN nr21 ;
  ORIGIN 0.000 0.000 ;
  SIZE 9.500 BY 29.000 ;
  SYMMETRY X Y R90 ;
  SITE core ;
  PIN VSS
    DIRECTION INOUT ;
    USE GROUND ;
    SHAPE ABUTMENT ;
    PORT
      LAYER ML1 ;
        RECT 0.500 1.000 2.500 4.500 ;
        RECT 6.500 1.000 8.500 4.500 ;
        RECT -0.500 -1.000 10.000 1.000 ;
    END
  END VSS
  PIN VDD
    DIRECTION INOUT ;
    USE POWER ;
    SHAPE ABUTMENT ;
    PORT
      LAYER ML1 ;
        RECT -0.500 28.000 10.000 30.000 ;
        RECT 1.000 20.500 3.000 28.000 ;
    END
  END VDD
  PIN A
    DIRECTION INPUT ;
    USE SIGNAL ;
    PORT
      LAYER ML2 ;
        RECT 1.000 14.500 3.000 16.500 ;
    END
  END A
  PIN B
    DIRECTION INPUT ;
    USE SIGNAL ;
    PORT
      LAYER ML2 ;
        RECT 4.000 11.500 6.000 13.500 ;
    END
  END B
  PIN X
    DIRECTION OUTPUT ;
    USE SIGNAL ;
    PORT
      LAYER ML2 ;
        RECT 7.000 8.500 9.000 10.500 ;
    END
  END X
  OBS
      LAYER ML1 ;
        RECT 6.000 20.500 8.000 26.500 ;
        RECT 1.000 14.500 3.000 16.500 ;
        RECT 6.500 16.000 7.500 20.500 ;
        RECT 6.500 15.000 8.000 16.000 ;
        RECT 4.000 11.500 6.000 13.500 ;
        RECT 7.000 10.500 8.000 15.000 ;
        RECT 7.000 8.500 9.000 10.500 ;
        RECT 7.000 7.000 8.000 8.500 ;
        RECT 4.000 6.000 8.000 7.000 ;
        RECT 4.000 4.500 5.000 6.000 ;
        RECT 3.500 2.500 5.500 4.500 ;
      LAYER POL ;
        RECT 3.000 18.000 4.000 27.500 ;
        RECT 2.000 17.000 4.000 18.000 ;
        RECT 2.000 16.500 3.000 17.000 ;
        RECT 1.000 14.500 3.000 16.500 ;
        RECT 2.000 10.500 3.000 14.500 ;
        RECT 5.000 13.500 6.000 27.500 ;
        RECT 4.000 11.500 6.000 13.500 ;
        RECT 5.000 10.500 6.000 11.500 ;
        RECT 2.000 9.500 3.500 10.500 ;
        RECT 5.000 9.500 6.500 10.500 ;
        RECT 2.500 1.500 3.500 9.500 ;
        RECT 5.500 1.500 6.500 9.500 ;
  END
END nr21

#--------EOF---------

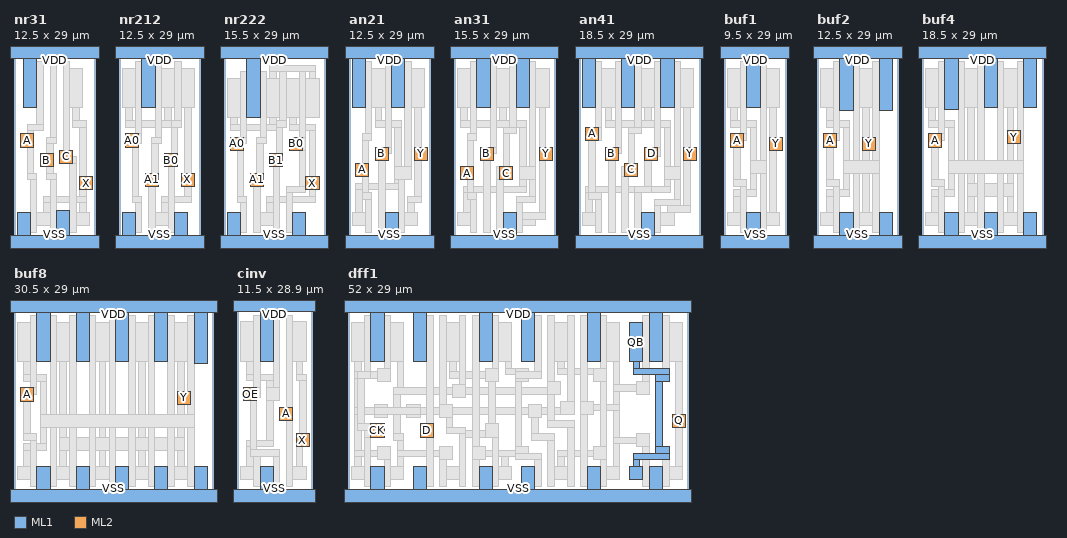
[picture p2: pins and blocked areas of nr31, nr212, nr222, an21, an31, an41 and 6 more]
MACRO nr31
  CLASS CORE ;
  FOREIGN nr31 ;
  ORIGIN 0.000 0.000 ;
  SIZE 12.500 BY 29.000 ;
  SYMMETRY X Y R90 ;
  SITE core ;
  PIN VDD
    DIRECTION INOUT ;
    USE POWER ;
    SHAPE ABUTMENT ;
    PORT
      LAYER ML1 ;
        RECT -0.500 28.000 13.000 30.000 ;
        RECT 1.500 20.500 3.500 28.000 ;
    END
  END VDD
  PIN VSS
    DIRECTION INOUT ;
    USE GROUND ;
    SHAPE ABUTMENT ;
    PORT
      LAYER ML1 ;
        RECT 0.500 1.000 2.500 4.500 ;
        RECT 6.500 1.000 8.500 4.800 ;
        RECT -0.500 -1.000 13.000 1.000 ;
    END
  END VSS
  PIN X
    DIRECTION OUTPUT ;
    USE SIGNAL ;
    PORT
      LAYER ML2 ;
        RECT 10.000 8.000 12.000 10.000 ;
    END
  END X
  PIN C
    DIRECTION INPUT ;
    USE SIGNAL ;
    PORT
      LAYER ML2 ;
        RECT 7.000 12.000 9.000 14.000 ;
    END
  END C
  PIN B
    DIRECTION INPUT ;
    USE SIGNAL ;
    PORT
      LAYER ML2 ;
        RECT 4.000 11.500 6.000 13.500 ;
    END
  END B
  PIN A
    DIRECTION INPUT ;
    USE SIGNAL ;
    PORT
      LAYER ML2 ;
        RECT 1.000 14.500 3.000 16.500 ;
    END
  END A
  OBS
      LAYER ML1 ;
        RECT 8.500 20.500 10.500 26.500 ;
        RECT 9.000 18.500 10.000 20.500 ;
        RECT 9.000 17.500 11.000 18.500 ;
        RECT 1.000 14.500 3.000 16.500 ;
        RECT 4.000 11.500 6.000 13.500 ;
        RECT 7.000 12.000 9.000 14.000 ;
        RECT 10.000 10.000 11.000 17.500 ;
        RECT 10.000 8.000 12.000 10.000 ;
        RECT 10.000 7.000 11.000 8.000 ;
        RECT 4.500 6.000 11.000 7.000 ;
        RECT 4.500 4.500 5.500 6.000 ;
        RECT 10.000 4.500 11.000 6.000 ;
        RECT 3.500 2.500 5.500 4.500 ;
        RECT 9.500 2.500 11.500 4.500 ;
      LAYER POL ;
        RECT 3.500 18.000 4.500 27.500 ;
        RECT 2.000 17.000 4.500 18.000 ;
        RECT 2.000 16.500 3.000 17.000 ;
        RECT 1.000 14.500 3.000 16.500 ;
        RECT 5.500 16.000 6.500 27.500 ;
        RECT 2.000 10.500 3.000 14.500 ;
        RECT 5.000 15.000 6.500 16.000 ;
        RECT 5.000 13.500 6.000 15.000 ;
        RECT 7.500 14.000 8.500 27.500 ;
        RECT 4.000 11.500 6.000 13.500 ;
        RECT 7.000 13.000 9.000 14.000 ;
        RECT 7.000 12.000 9.500 13.000 ;
        RECT 5.000 10.500 6.000 11.500 ;
        RECT 2.000 9.500 3.500 10.500 ;
        RECT 5.000 9.500 6.500 10.500 ;
        RECT 2.500 1.500 3.500 9.500 ;
        RECT 5.500 1.500 6.500 9.500 ;
        RECT 8.500 1.500 9.500 12.000 ;
  END
END nr31

#--------EOF---------

MACRO nr212
  CLASS CORE ;
  FOREIGN nr212 ;
  ORIGIN 0.000 0.000 ;
  SIZE 12.500 BY 29.000 ;
  SYMMETRY X Y R90 ;
  SITE core ;
  PIN VDD
    DIRECTION INOUT ;
    USE POWER ;
    SHAPE ABUTMENT ;
    PORT
      LAYER ML1 ;
        RECT -0.500 28.000 13.000 30.000 ;
        RECT 3.500 20.500 5.500 28.000 ;
    END
  END VDD
  PIN VSS
    DIRECTION INOUT ;
    USE GROUND ;
    SHAPE ABUTMENT ;
    PORT
      LAYER ML1 ;
        RECT 0.500 1.000 2.500 4.500 ;
        RECT 8.500 1.000 10.500 4.500 ;
        RECT -0.500 -1.000 13.000 1.000 ;
    END
  END VSS
  PIN B0
    DIRECTION INPUT ;
    USE SIGNAL ;
    PORT
      LAYER ML2 ;
        RECT 7.000 11.500 9.000 13.500 ;
    END
  END B0
  PIN A1
    DIRECTION INPUT ;
    USE SIGNAL ;
    PORT
      LAYER ML2 ;
        RECT 4.000 8.500 6.000 10.500 ;
    END
  END A1
  PIN A0
    DIRECTION INPUT ;
    USE SIGNAL ;
    PORT
      LAYER ML2 ;
        RECT 1.000 14.500 3.000 16.500 ;
    END
  END A0
  PIN X
    DIRECTION OUTPUT ;
    USE SIGNAL ;
    PORT
      LAYER ML2 ;
        RECT 9.500 8.500 11.500 10.500 ;
    END
  END X
  OBS
      LAYER ML1 ;
        RECT 0.500 20.500 2.500 26.500 ;
        RECT 6.500 20.500 8.500 26.500 ;
        RECT 9.500 20.500 11.500 26.500 ;
        RECT 1.000 18.500 2.000 20.500 ;
        RECT 7.000 18.500 8.000 20.500 ;
        RECT 1.000 17.500 8.000 18.500 ;
        RECT 1.000 14.500 3.000 16.500 ;
        RECT 7.000 11.500 9.000 13.500 ;
        RECT 10.000 10.500 11.000 20.500 ;
        RECT 4.000 8.500 6.000 10.500 ;
        RECT 9.500 8.500 11.500 10.500 ;
        RECT 10.000 7.000 11.000 8.500 ;
        RECT 6.500 6.000 11.000 7.000 ;
        RECT 6.500 4.500 7.500 6.000 ;
        RECT 5.500 2.500 7.500 4.500 ;
      LAYER POL ;
        RECT 2.500 16.500 3.500 27.500 ;
        RECT 1.000 15.000 3.500 16.500 ;
        RECT 5.500 16.000 6.500 27.500 ;
        RECT 8.500 18.500 9.500 27.500 ;
        RECT 5.000 15.000 6.500 16.000 ;
        RECT 8.000 17.500 9.500 18.500 ;
        RECT 1.000 14.500 3.000 15.000 ;
        RECT 2.000 7.000 3.000 14.500 ;
        RECT 5.000 10.500 6.000 15.000 ;
        RECT 8.000 13.500 9.000 17.500 ;
        RECT 7.000 11.500 9.000 13.500 ;
        RECT 4.000 8.500 6.000 10.500 ;
        RECT 2.000 6.000 3.500 7.000 ;
        RECT 2.500 1.500 3.500 6.000 ;
        RECT 4.500 1.500 5.500 8.500 ;
        RECT 7.500 1.500 8.500 11.500 ;
  END
END nr212

#--------EOF---------

MACRO nr222
  CLASS CORE ;
  FOREIGN nr222 ;
  ORIGIN 0.000 0.000 ;
  SIZE 15.500 BY 29.000 ;
  SYMMETRY X Y R90 ;
  SITE core ;
  PIN VDD
    DIRECTION INOUT ;
    USE POWER ;
    SHAPE ABUTMENT ;
    PORT
      LAYER ML1 ;
        RECT -0.500 28.000 16.000 30.000 ;
        RECT 3.500 19.000 5.500 28.000 ;
    END
  END VDD
  PIN VSS
    DIRECTION INOUT ;
    USE GROUND ;
    SHAPE ABUTMENT ;
    PORT
      LAYER ML1 ;
        RECT 0.500 1.000 2.500 4.500 ;
        RECT 10.500 1.000 12.500 4.500 ;
        RECT -0.500 -1.000 16.000 1.000 ;
    END
  END VSS
  PIN A0
    DIRECTION INPUT ;
    USE SIGNAL ;
    PORT
      LAYER ML2 ;
        RECT 1.000 14.000 3.000 16.000 ;
    END
  END A0
  PIN A1
    DIRECTION INPUT ;
    USE SIGNAL ;
    PORT
      LAYER ML2 ;
        RECT 4.000 8.500 6.000 10.500 ;
    END
  END A1
  PIN B1
    DIRECTION INPUT ;
    USE SIGNAL ;
    PORT
      LAYER ML2 ;
        RECT 7.000 11.500 9.000 13.500 ;
    END
  END B1
  PIN X
    DIRECTION OUTPUT ;
    USE SIGNAL ;
    PORT
      LAYER ML2 ;
        RECT 12.500 8.000 14.500 10.000 ;
    END
  END X
  PIN B0
    DIRECTION INPUT ;
    USE SIGNAL ;
    PORT
      LAYER ML2 ;
        RECT 10.000 14.000 12.000 16.000 ;
    END
  END B0
  OBS
      LAYER ML1 ;
        RECT 7.000 26.000 14.000 27.000 ;
        RECT 7.000 25.000 8.000 26.000 ;
        RECT 13.000 25.000 14.000 26.000 ;
        RECT 0.500 19.000 2.500 25.000 ;
        RECT 6.500 19.000 8.500 25.000 ;
        RECT 9.500 19.000 11.500 25.000 ;
        RECT 12.500 19.000 14.500 25.000 ;
        RECT 1.000 18.000 2.000 19.000 ;
        RECT 7.000 18.000 8.000 19.000 ;
        RECT 1.000 17.000 8.000 18.000 ;
        RECT 10.000 18.000 11.000 19.000 ;
        RECT 10.000 17.000 14.000 18.000 ;
        RECT 1.000 14.000 3.000 16.000 ;
        RECT 10.000 14.000 12.000 16.000 ;
        RECT 7.000 11.500 9.000 13.500 ;
        RECT 4.000 8.500 6.000 10.500 ;
        RECT 13.000 10.000 14.000 17.000 ;
        RECT 12.500 8.000 14.500 10.000 ;
        RECT 13.000 7.000 14.000 8.000 ;
        RECT 6.500 6.000 14.000 7.000 ;
        RECT 6.500 4.500 7.500 6.000 ;
        RECT 5.500 2.500 7.500 4.500 ;
      LAYER POL ;
        RECT 2.500 16.000 3.500 26.000 ;
        RECT 5.500 16.000 6.500 26.000 ;
        RECT 8.500 18.500 9.500 26.000 ;
        RECT 1.000 15.000 3.500 16.000 ;
        RECT 5.000 15.000 6.500 16.000 ;
        RECT 8.000 17.500 9.500 18.500 ;
        RECT 1.000 14.000 3.000 15.000 ;
        RECT 2.000 7.000 3.000 14.000 ;
        RECT 5.000 10.500 6.000 15.000 ;
        RECT 8.000 13.500 9.000 17.500 ;
        RECT 11.500 16.000 12.500 26.000 ;
        RECT 10.000 14.000 12.500 16.000 ;
        RECT 7.000 11.500 9.000 13.500 ;
        RECT 4.000 8.500 6.000 10.500 ;
        RECT 2.000 6.000 3.500 7.000 ;
        RECT 2.500 1.500 3.500 6.000 ;
        RECT 4.500 1.500 5.500 8.500 ;
        RECT 7.500 1.500 8.500 11.500 ;
        RECT 11.500 8.500 12.500 14.000 ;
        RECT 9.500 7.500 12.500 8.500 ;
        RECT 9.500 1.500 10.500 7.500 ;
  END
END nr222

#--------EOF---------

MACRO an21
  CLASS CORE ;
  FOREIGN an21 ;
  ORIGIN 0.000 0.000 ;
  SIZE 12.500 BY 29.000 ;
  SYMMETRY X Y R90 ;
  SITE core ;
  PIN VSS
    DIRECTION INOUT ;
    USE GROUND ;
    SHAPE ABUTMENT ;
    PORT
      LAYER ML1 ;
        RECT 5.500 1.000 7.500 4.500 ;
        RECT -0.500 -1.000 13.000 1.000 ;
    END
  END VSS
  PIN VDD
    DIRECTION INOUT ;
    USE POWER ;
    SHAPE ABUTMENT ;
    PORT
      LAYER ML1 ;
        RECT -0.500 28.000 13.000 30.000 ;
        RECT 0.500 20.500 2.500 28.000 ;
        RECT 6.500 20.500 8.500 28.000 ;
    END
  END VDD
  PIN A
    DIRECTION INPUT ;
    USE SIGNAL ;
    PORT
      LAYER ML2 ;
        RECT 1.000 10.000 3.000 12.000 ;
    END
  END A
  PIN B
    DIRECTION INPUT ;
    USE SIGNAL ;
    PORT
      LAYER ML2 ;
        RECT 4.000 12.500 6.000 14.500 ;
    END
  END B
  PIN Y
    DIRECTION OUTPUT ;
    USE SIGNAL ;
    PORT
      LAYER ML2 ;
        RECT 10.000 12.500 12.000 14.500 ;
    END
  END Y
  OBS
      LAYER ML1 ;
        RECT 3.500 20.500 5.500 26.500 ;
        RECT 9.500 20.500 11.500 26.500 ;
        RECT 4.000 18.500 5.000 20.500 ;
        RECT 4.000 17.500 8.000 18.500 ;
        RECT 4.000 12.500 6.000 14.500 ;
        RECT 1.000 10.000 3.000 12.000 ;
        RECT 7.000 11.500 8.000 17.500 ;
        RECT 10.000 14.500 11.000 20.500 ;
        RECT 10.000 12.500 12.000 14.500 ;
        RECT 7.000 9.500 9.000 11.500 ;
        RECT 7.000 9.000 8.000 9.500 ;
        RECT 1.000 8.000 8.000 9.000 ;
        RECT 1.000 4.500 2.000 8.000 ;
        RECT 10.000 7.000 11.000 12.500 ;
        RECT 9.000 6.000 11.000 7.000 ;
        RECT 9.000 4.500 10.000 6.000 ;
        RECT 0.500 2.500 2.500 4.500 ;
        RECT 8.500 2.500 10.500 4.500 ;
      LAYER POL ;
        RECT 2.500 16.500 3.500 27.500 ;
        RECT 2.000 15.500 3.500 16.500 ;
        RECT 2.000 12.000 3.000 15.500 ;
        RECT 5.500 14.500 6.500 27.500 ;
        RECT 4.000 13.500 6.500 14.500 ;
        RECT 4.000 12.500 6.000 13.500 ;
        RECT 1.000 10.000 3.000 12.000 ;
        RECT 2.000 7.500 3.000 10.000 ;
        RECT 2.000 6.500 3.500 7.500 ;
        RECT 2.500 1.500 3.500 6.500 ;
        RECT 4.500 1.500 5.500 12.500 ;
        RECT 8.500 11.500 9.500 27.500 ;
        RECT 7.000 9.500 9.500 11.500 ;
        RECT 7.500 1.500 8.500 9.500 ;
  END
END an21

#--------EOF---------

MACRO an31
  CLASS CORE ;
  FOREIGN an31 ;
  ORIGIN 0.000 0.000 ;
  SIZE 15.500 BY 29.000 ;
  SYMMETRY X Y R90 ;
  SITE core ;
  PIN VDD
    DIRECTION INOUT ;
    USE POWER ;
    SHAPE ABUTMENT ;
    PORT
      LAYER ML1 ;
        RECT -0.500 28.000 16.000 30.000 ;
        RECT 3.500 20.500 5.500 28.000 ;
        RECT 9.500 20.500 11.500 28.000 ;
    END
  END VDD
  PIN VSS
    DIRECTION INOUT ;
    USE GROUND ;
    SHAPE ABUTMENT ;
    PORT
      LAYER ML1 ;
        RECT 7.500 1.000 9.500 4.500 ;
        RECT -0.500 -1.000 16.000 1.000 ;
    END
  END VSS
  PIN Y
    DIRECTION OUTPUT ;
    USE SIGNAL ;
    PORT
      LAYER ML2 ;
        RECT 13.000 12.500 15.000 14.500 ;
    END
  END Y
  PIN C
    DIRECTION INPUT ;
    USE SIGNAL ;
    PORT
      LAYER ML2 ;
        RECT 7.000 9.500 9.000 11.500 ;
    END
  END C
  PIN B
    DIRECTION INPUT ;
    USE SIGNAL ;
    PORT
      LAYER ML2 ;
        RECT 4.000 12.500 6.000 14.500 ;
    END
  END B
  PIN A
    DIRECTION INPUT ;
    USE SIGNAL ;
    PORT
      LAYER ML2 ;
        RECT 1.000 9.500 3.000 11.500 ;
    END
  END A
  OBS
      LAYER ML1 ;
        RECT 0.500 20.500 2.500 26.500 ;
        RECT 6.500 20.500 8.500 26.500 ;
        RECT 12.500 20.500 14.500 26.500 ;
        RECT 1.000 18.500 2.000 20.500 ;
        RECT 7.000 18.500 8.000 20.500 ;
        RECT 1.000 17.500 11.000 18.500 ;
        RECT 4.000 12.500 6.000 14.500 ;
        RECT 10.000 11.500 11.000 17.500 ;
        RECT 13.000 14.500 14.000 20.500 ;
        RECT 13.000 12.500 15.000 14.500 ;
        RECT 1.000 9.500 3.000 11.500 ;
        RECT 7.000 9.500 9.000 11.500 ;
        RECT 10.000 9.500 12.000 11.500 ;
        RECT 10.000 8.500 11.000 9.500 ;
        RECT 1.500 7.500 11.000 8.500 ;
        RECT 1.500 4.500 2.500 7.500 ;
        RECT 13.000 4.500 14.000 12.500 ;
        RECT 0.500 2.500 2.500 4.500 ;
        RECT 10.500 3.500 14.000 4.500 ;
        RECT 10.500 2.500 12.500 3.500 ;
      LAYER POL ;
        RECT 2.500 16.500 3.500 27.500 ;
        RECT 2.000 15.500 3.500 16.500 ;
        RECT 2.000 11.500 3.000 15.500 ;
        RECT 5.500 14.500 6.500 27.500 ;
        RECT 8.500 17.500 9.500 27.500 ;
        RECT 4.000 13.500 6.500 14.500 ;
        RECT 7.500 16.500 9.500 17.500 ;
        RECT 4.000 12.500 6.000 13.500 ;
        RECT 1.000 9.500 3.000 11.500 ;
        RECT 2.000 7.500 3.000 9.500 ;
        RECT 2.000 6.500 3.500 7.500 ;
        RECT 2.500 1.500 3.500 6.500 ;
        RECT 4.500 1.500 5.500 12.500 ;
        RECT 7.500 11.500 8.500 16.500 ;
        RECT 11.500 11.500 12.500 27.500 ;
        RECT 6.500 9.500 9.000 11.500 ;
        RECT 10.000 9.500 12.500 11.500 ;
        RECT 6.500 1.500 7.500 9.500 ;
        RECT 11.500 7.000 12.500 9.500 ;
        RECT 9.500 6.000 12.500 7.000 ;
        RECT 9.500 1.500 10.500 6.000 ;
  END
END an31

#--------EOF---------

MACRO an41
  CLASS CORE ;
  FOREIGN an41 ;
  ORIGIN 0.000 0.000 ;
  SIZE 18.500 BY 29.000 ;
  SYMMETRY X Y R90 ;
  SITE core ;
  PIN VSS
    DIRECTION INOUT ;
    USE GROUND ;
    SHAPE ABUTMENT ;
    PORT
      LAYER ML1 ;
        RECT 9.500 1.000 11.500 4.500 ;
        RECT -0.500 -1.000 19.000 1.000 ;
    END
  END VSS
  PIN VDD
    DIRECTION INOUT ;
    USE POWER ;
    SHAPE ABUTMENT ;
    PORT
      LAYER ML1 ;
        RECT -0.500 28.000 19.000 30.000 ;
        RECT 0.500 20.500 2.500 28.000 ;
        RECT 6.500 20.500 8.500 28.000 ;
        RECT 12.500 20.500 14.500 28.000 ;
    END
  END VDD
  PIN Y
    DIRECTION OUTPUT ;
    USE SIGNAL ;
    PORT
      LAYER ML2 ;
        RECT 16.000 12.500 18.000 14.500 ;
    END
  END Y
  PIN D
    DIRECTION INPUT ;
    USE SIGNAL ;
    PORT
      LAYER ML2 ;
        RECT 10.000 12.500 12.000 14.500 ;
    END
  END D
  PIN C
    DIRECTION INPUT ;
    USE SIGNAL ;
    PORT
      LAYER ML2 ;
        RECT 7.000 10.000 9.000 12.000 ;
    END
  END C
  PIN B
    DIRECTION INPUT ;
    USE SIGNAL ;
    PORT
      LAYER ML2 ;
        RECT 4.000 12.500 6.000 14.500 ;
    END
  END B
  PIN A
    DIRECTION INPUT ;
    USE SIGNAL ;
    PORT
      LAYER ML2 ;
        RECT 1.000 15.500 3.000 17.500 ;
    END
  END A
  OBS
      LAYER ML1 ;
        RECT 3.500 20.500 5.500 26.500 ;
        RECT 9.500 20.500 11.500 26.500 ;
        RECT 15.500 20.500 17.500 26.500 ;
        RECT 4.000 18.500 5.000 20.500 ;
        RECT 10.000 18.500 11.000 20.500 ;
        RECT 4.000 17.500 14.000 18.500 ;
        RECT 1.000 15.500 3.000 17.500 ;
        RECT 4.000 12.500 6.000 14.500 ;
        RECT 10.000 12.500 12.000 14.500 ;
        RECT 7.000 10.000 9.000 12.000 ;
        RECT 13.000 11.500 14.000 17.500 ;
        RECT 16.000 14.500 17.000 20.500 ;
        RECT 16.000 12.500 18.000 14.500 ;
        RECT 13.000 9.500 15.000 11.500 ;
        RECT 13.000 8.500 14.000 9.500 ;
        RECT 1.000 7.500 14.000 8.500 ;
        RECT 1.000 4.500 2.000 7.500 ;
        RECT 16.000 5.500 17.000 12.500 ;
        RECT 13.500 4.500 17.000 5.500 ;
        RECT 0.500 2.500 2.500 4.500 ;
        RECT 12.500 2.500 14.500 4.500 ;
      LAYER POL ;
        RECT 2.500 17.500 3.500 27.500 ;
        RECT 1.000 15.500 3.500 17.500 ;
        RECT 1.500 7.500 2.500 15.500 ;
        RECT 5.500 14.500 6.500 27.500 ;
        RECT 8.500 17.500 9.500 27.500 ;
        RECT 4.000 13.500 6.500 14.500 ;
        RECT 7.500 16.500 9.500 17.500 ;
        RECT 4.000 12.500 6.000 13.500 ;
        RECT 1.500 6.500 3.500 7.500 ;
        RECT 2.500 1.500 3.500 6.500 ;
        RECT 4.500 1.500 5.500 12.500 ;
        RECT 7.500 12.000 8.500 16.500 ;
        RECT 11.500 14.500 12.500 27.500 ;
        RECT 10.000 13.000 12.500 14.500 ;
        RECT 10.000 12.500 12.000 13.000 ;
        RECT 7.000 11.500 9.000 12.000 ;
        RECT 6.500 10.000 9.000 11.500 ;
        RECT 6.500 1.500 7.500 10.000 ;
        RECT 10.000 8.500 11.000 12.500 ;
        RECT 14.500 11.500 15.500 27.500 ;
        RECT 13.000 9.500 15.500 11.500 ;
        RECT 8.500 7.500 11.000 8.500 ;
        RECT 8.500 1.500 9.500 7.500 ;
        RECT 14.500 6.500 15.500 9.500 ;
        RECT 11.500 5.500 15.500 6.500 ;
        RECT 11.500 1.500 12.500 5.500 ;
  END
END an41

#--------EOF---------

MACRO buf1
  CLASS CORE ;
  FOREIGN buf1 ;
  ORIGIN 0.000 0.000 ;
  SIZE 9.500 BY 29.000 ;
  SYMMETRY X Y R90 ;
  SITE core ;
  PIN VDD
    DIRECTION INOUT ;
    USE POWER ;
    SHAPE ABUTMENT ;
    PORT
      LAYER ML1 ;
        RECT -0.500 28.000 10.000 30.000 ;
        RECT 3.500 20.500 5.500 28.000 ;
    END
  END VDD
  PIN VSS
    DIRECTION INOUT ;
    USE GROUND ;
    SHAPE ABUTMENT ;
    PORT
      LAYER ML1 ;
        RECT 3.500 1.000 5.500 4.500 ;
        RECT -0.500 -1.000 10.000 1.000 ;
    END
  END VSS
  PIN Y
    DIRECTION OUTPUT ;
    USE SIGNAL ;
    PORT
      LAYER ML2 ;
        RECT 7.000 14.000 9.000 16.000 ;
    END
  END Y
  PIN A
    DIRECTION INPUT ;
    USE SIGNAL ;
    PORT
      LAYER ML2 ;
        RECT 1.000 14.500 3.000 16.500 ;
    END
  END A
  OBS
      LAYER ML1 ;
        RECT 0.500 20.500 2.500 26.500 ;
        RECT 6.500 20.500 8.500 26.500 ;
        RECT 1.000 18.500 2.000 20.500 ;
        RECT 1.000 17.500 5.000 18.500 ;
        RECT 1.000 14.500 3.000 16.500 ;
        RECT 4.000 12.500 5.000 17.500 ;
        RECT 7.000 16.000 8.000 20.500 ;
        RECT 7.000 14.000 9.000 16.000 ;
        RECT 4.000 10.500 6.000 12.500 ;
        RECT 4.000 8.000 5.000 10.500 ;
        RECT 1.500 7.000 5.000 8.000 ;
        RECT 1.500 4.500 2.500 7.000 ;
        RECT 7.000 4.500 8.000 14.000 ;
        RECT 0.500 2.500 2.500 4.500 ;
        RECT 6.500 2.500 8.500 4.500 ;
      LAYER POL ;
        RECT 2.500 16.500 3.500 27.500 ;
        RECT 1.000 15.500 3.500 16.500 ;
        RECT 1.000 14.500 3.000 15.500 ;
        RECT 1.500 9.500 2.500 14.500 ;
        RECT 5.500 12.500 6.500 27.500 ;
        RECT 4.000 10.500 6.500 12.500 ;
        RECT 1.500 8.500 3.500 9.500 ;
        RECT 2.500 1.500 3.500 8.500 ;
        RECT 5.500 1.500 6.500 10.500 ;
  END
END buf1

#--------EOF---------

MACRO buf2
  CLASS CORE ;
  FOREIGN buf2 ;
  ORIGIN 0.000 0.000 ;
  SIZE 12.500 BY 29.000 ;
  SYMMETRY X Y R90 ;
  SITE core ;
  PIN VDD
    DIRECTION INOUT ;
    USE POWER ;
    SHAPE ABUTMENT ;
    PORT
      LAYER ML1 ;
        RECT -0.500 28.000 13.000 30.000 ;
        RECT 3.500 20.000 5.500 28.000 ;
        RECT 9.500 20.000 11.500 28.000 ;
    END
  END VDD
  PIN VSS
    DIRECTION INOUT ;
    USE GROUND ;
    SHAPE ABUTMENT ;
    PORT
      LAYER ML1 ;
        RECT 3.500 1.000 5.500 4.500 ;
        RECT 9.500 1.000 11.500 4.500 ;
        RECT -0.500 -1.000 13.000 1.000 ;
    END
  END VSS
  PIN A
    DIRECTION INPUT ;
    USE SIGNAL ;
    PORT
      LAYER ML2 ;
        RECT 1.000 14.500 3.000 16.500 ;
    END
  END A
  PIN Y
    DIRECTION OUTPUT ;
    USE SIGNAL ;
    PORT
      LAYER ML2 ;
        RECT 7.000 14.000 9.000 16.000 ;
    END
  END Y
  OBS
      LAYER ML1 ;
        RECT 0.500 20.500 2.500 26.500 ;
        RECT 6.500 20.500 8.500 26.500 ;
        RECT 1.500 18.500 2.500 20.500 ;
        RECT 1.500 17.500 5.000 18.500 ;
        RECT 1.000 14.500 3.000 16.500 ;
        RECT 4.000 12.500 5.000 17.500 ;
        RECT 7.000 16.000 8.000 20.500 ;
        RECT 7.000 14.000 9.000 16.000 ;
        RECT 4.000 10.500 6.000 12.500 ;
        RECT 4.000 8.000 5.000 10.500 ;
        RECT 1.500 7.000 5.000 8.000 ;
        RECT 1.500 4.500 2.500 7.000 ;
        RECT 7.000 4.500 8.000 14.000 ;
        RECT 0.500 2.500 2.500 4.500 ;
        RECT 6.500 2.500 8.500 4.500 ;
      LAYER POL ;
        RECT 2.500 16.500 3.500 27.500 ;
        RECT 1.000 15.500 3.500 16.500 ;
        RECT 1.000 14.500 3.000 15.500 ;
        RECT 1.500 9.500 2.500 14.500 ;
        RECT 5.500 12.500 6.500 27.500 ;
        RECT 8.500 12.500 9.500 27.500 ;
        RECT 4.000 10.500 9.500 12.500 ;
        RECT 1.500 8.500 3.500 9.500 ;
        RECT 2.500 1.500 3.500 8.500 ;
        RECT 5.500 1.500 6.500 10.500 ;
        RECT 8.500 1.500 9.500 10.500 ;
  END
END buf2

#--------EOF---------

MACRO buf4
  CLASS CORE ;
  FOREIGN buf4 ;
  ORIGIN 0.000 0.000 ;
  SIZE 18.500 BY 29.000 ;
  SYMMETRY X Y R90 ;
  SITE core ;
  PIN VSS
    DIRECTION INOUT ;
    USE GROUND ;
    SHAPE ABUTMENT ;
    PORT
      LAYER ML1 ;
        RECT 3.500 1.000 5.500 4.500 ;
        RECT 9.500 1.000 11.500 4.500 ;
        RECT 15.500 1.000 17.500 4.500 ;
        RECT -0.500 -1.000 19.000 1.000 ;
    END
  END VSS
  PIN VDD
    DIRECTION INOUT ;
    USE POWER ;
    SHAPE ABUTMENT ;
    PORT
      LAYER ML1 ;
        RECT -0.500 28.000 19.000 30.000 ;
        RECT 3.500 20.200 5.500 28.000 ;
        RECT 9.500 20.500 11.500 28.000 ;
        RECT 15.500 20.500 17.500 28.000 ;
    END
  END VDD
  PIN A
    DIRECTION INPUT ;
    USE SIGNAL ;
    PORT
      LAYER ML2 ;
        RECT 1.000 14.500 3.000 16.500 ;
    END
  END A
  PIN Y
    DIRECTION OUTPUT ;
    USE SIGNAL ;
    PORT
      LAYER ML2 ;
        RECT 13.000 15.000 15.000 17.000 ;
    END
  END Y
  OBS
      LAYER ML1 ;
        RECT 0.500 20.500 2.500 26.500 ;
        RECT 6.500 20.500 8.500 26.500 ;
        RECT 12.500 20.500 14.500 26.500 ;
        RECT 1.000 18.500 2.000 20.500 ;
        RECT 1.000 17.500 5.000 18.500 ;
        RECT 1.000 14.500 3.000 16.500 ;
        RECT 4.000 12.500 5.000 17.500 ;
        RECT 4.000 10.500 6.000 12.500 ;
        RECT 4.000 8.000 5.000 10.500 ;
        RECT 1.500 7.000 5.000 8.000 ;
        RECT 7.000 9.000 8.000 20.500 ;
        RECT 13.000 17.000 14.000 20.500 ;
        RECT 13.000 15.000 15.000 17.000 ;
        RECT 13.000 9.000 14.000 15.000 ;
        RECT 7.000 7.000 14.000 9.000 ;
        RECT 1.500 4.500 2.500 7.000 ;
        RECT 7.000 4.500 8.000 7.000 ;
        RECT 13.000 4.500 14.000 7.000 ;
        RECT 0.500 2.500 2.500 4.500 ;
        RECT 6.500 2.500 8.500 4.500 ;
        RECT 12.500 2.500 14.500 4.500 ;
      LAYER POL ;
        RECT 2.500 16.500 3.500 27.500 ;
        RECT 1.000 15.500 3.500 16.500 ;
        RECT 1.000 14.500 3.000 15.500 ;
        RECT 1.500 9.500 2.500 14.500 ;
        RECT 5.500 12.500 6.500 27.500 ;
        RECT 8.500 12.500 9.500 27.500 ;
        RECT 11.500 12.500 12.500 27.500 ;
        RECT 14.500 12.500 15.500 27.500 ;
        RECT 4.000 10.500 15.500 12.500 ;
        RECT 1.500 8.500 3.500 9.500 ;
        RECT 2.500 1.500 3.500 8.500 ;
        RECT 5.500 1.500 6.500 10.500 ;
        RECT 8.500 1.500 9.500 10.500 ;
        RECT 11.500 1.500 12.500 10.500 ;
        RECT 14.500 1.500 15.500 10.500 ;
  END
END buf4

#--------EOF---------

MACRO buf8
  CLASS CORE ;
  FOREIGN buf8 ;
  ORIGIN 0.000 0.000 ;
  SIZE 30.500 BY 29.000 ;
  SYMMETRY X Y R90 ;
  SITE core ;
  PIN VDD
    DIRECTION INOUT ;
    USE POWER ;
    SHAPE ABUTMENT ;
    PORT
      LAYER ML1 ;
        RECT -0.500 28.000 31.000 30.000 ;
        RECT 3.500 20.500 5.500 28.000 ;
        RECT 9.500 20.500 11.500 28.000 ;
        RECT 15.500 20.500 17.500 28.000 ;
        RECT 21.500 20.500 23.500 28.000 ;
        RECT 27.500 20.300 29.500 28.000 ;
    END
  END VDD
  PIN VSS
    DIRECTION INOUT ;
    USE GROUND ;
    SHAPE ABUTMENT ;
    PORT
      LAYER ML1 ;
        RECT 3.500 1.000 5.500 4.500 ;
        RECT 9.500 1.000 11.500 4.500 ;
        RECT 15.500 1.000 17.500 4.500 ;
        RECT 21.500 1.000 23.500 4.500 ;
        RECT 27.500 1.000 29.500 4.500 ;
        RECT -0.500 -1.000 31.000 1.000 ;
    END
  END VSS
  PIN A
    DIRECTION INPUT ;
    USE SIGNAL ;
    PORT
      LAYER ML2 ;
        RECT 1.000 14.500 3.000 16.500 ;
    END
  END A
  PIN Y
    DIRECTION OUTPUT ;
    USE SIGNAL ;
    PORT
      LAYER ML2 ;
        RECT 25.000 14.000 27.000 16.000 ;
    END
  END Y
  OBS
      LAYER ML1 ;
        RECT 0.500 20.500 2.500 26.500 ;
        RECT 6.500 20.500 8.500 26.500 ;
        RECT 12.500 20.500 14.500 26.500 ;
        RECT 18.500 20.500 20.500 26.500 ;
        RECT 24.500 20.500 26.500 26.500 ;
        RECT 1.500 18.500 2.500 20.500 ;
        RECT 1.500 17.500 5.000 18.500 ;
        RECT 1.000 14.500 3.000 16.500 ;
        RECT 4.000 12.500 5.000 17.500 ;
        RECT 4.000 10.500 6.000 12.500 ;
        RECT 4.000 8.000 5.000 10.500 ;
        RECT 1.500 7.000 5.000 8.000 ;
        RECT 7.000 9.000 8.000 20.500 ;
        RECT 13.000 9.000 14.000 20.500 ;
        RECT 19.000 9.000 20.000 20.500 ;
        RECT 25.000 16.000 26.000 20.500 ;
        RECT 25.000 14.000 27.000 16.000 ;
        RECT 25.000 9.000 26.000 14.000 ;
        RECT 7.000 7.000 26.000 9.000 ;
        RECT 1.500 4.500 2.500 7.000 ;
        RECT 7.000 4.500 8.000 7.000 ;
        RECT 13.000 4.500 14.000 7.000 ;
        RECT 19.000 4.500 20.000 7.000 ;
        RECT 25.000 4.500 26.000 7.000 ;
        RECT 0.500 2.500 2.500 4.500 ;
        RECT 6.500 2.500 8.500 4.500 ;
        RECT 12.500 2.500 14.500 4.500 ;
        RECT 18.500 2.500 20.500 4.500 ;
        RECT 24.500 2.500 26.500 4.500 ;
      LAYER POL ;
        RECT 2.500 16.500 3.500 27.500 ;
        RECT 1.000 15.500 3.500 16.500 ;
        RECT 1.000 14.500 3.000 15.500 ;
        RECT 1.500 9.500 2.500 14.500 ;
        RECT 5.500 12.500 6.500 27.500 ;
        RECT 8.500 12.500 9.500 27.500 ;
        RECT 11.500 12.500 12.500 27.500 ;
        RECT 14.500 12.500 15.500 27.500 ;
        RECT 17.500 12.500 18.500 27.500 ;
        RECT 20.500 12.500 21.500 27.500 ;
        RECT 23.500 12.500 24.500 27.500 ;
        RECT 26.500 12.500 27.500 27.500 ;
        RECT 4.000 10.500 27.500 12.500 ;
        RECT 1.500 8.500 3.500 9.500 ;
        RECT 2.500 1.500 3.500 8.500 ;
        RECT 5.500 1.500 6.500 10.500 ;
        RECT 8.500 1.500 9.500 10.500 ;
        RECT 11.500 1.500 12.500 10.500 ;
        RECT 14.500 1.500 15.500 10.500 ;
        RECT 17.500 1.500 18.500 10.500 ;
        RECT 20.500 1.500 21.500 10.500 ;
        RECT 23.500 1.500 24.500 10.500 ;
        RECT 26.500 1.500 27.500 10.500 ;
  END
END buf8

#--------EOF---------

MACRO cinv
  CLASS CORE ;
  FOREIGN cinv ;
  ORIGIN 0.000 0.000 ;
  SIZE 11.500 BY 28.900 ;
  SYMMETRY X Y R90 ;
  SITE core ;
  PIN VSS
    DIRECTION INOUT ;
    USE GROUND ;
    SHAPE ABUTMENT ;
    PORT
      LAYER ML1 ;
        RECT 3.500 1.000 5.500 4.500 ;
        RECT -0.500 -1.000 12.000 1.000 ;
    END
  END VSS
  PIN VDD
    DIRECTION INOUT ;
    USE POWER ;
    SHAPE ABUTMENT ;
    PORT
      LAYER ML1 ;
        RECT -0.500 28.000 12.000 30.000 ;
        RECT 3.500 20.500 5.500 28.000 ;
    END
  END VDD
  PIN X
    DIRECTION OUTPUT ;
    USE SIGNAL ;
    PORT
      LAYER ML2 ;
        RECT 9.000 7.500 11.000 9.500 ;
    END
  END X
  PIN OE
    DIRECTION INPUT ;
    USE SIGNAL ;
    PORT
      LAYER ML2 ;
        RECT 1.000 14.500 3.000 16.500 ;
    END
  END OE
  PIN A
    DIRECTION INPUT ;
    USE SIGNAL ;
    PORT
      LAYER ML2 ;
        RECT 6.500 11.500 8.500 13.500 ;
    END
  END A
  OBS
      LAYER ML1 ;
        RECT 0.500 20.500 2.500 26.500 ;
        RECT 8.500 20.500 10.500 26.500 ;
        RECT 1.500 18.500 2.500 20.500 ;
        RECT 9.000 18.500 10.000 20.500 ;
        RECT 1.500 17.500 5.500 18.500 ;
        RECT 9.000 17.500 10.500 18.500 ;
        RECT 4.500 16.500 5.500 17.500 ;
        RECT 1.000 14.500 3.000 16.500 ;
        RECT 4.500 14.500 6.500 16.500 ;
        RECT 4.500 8.500 5.500 14.500 ;
        RECT 6.500 11.500 8.500 13.500 ;
        RECT 9.500 9.500 10.500 17.500 ;
        RECT 1.500 7.500 5.500 8.500 ;
        RECT 9.000 7.500 11.000 9.500 ;
        RECT 1.500 4.500 2.500 7.500 ;
        RECT 9.000 4.500 10.000 7.500 ;
        RECT 0.500 2.500 2.500 4.500 ;
        RECT 8.500 2.500 10.500 4.500 ;
      LAYER POL ;
        RECT 2.500 16.500 3.500 27.500 ;
        RECT 5.500 16.500 6.500 27.500 ;
        RECT 1.000 15.000 3.500 16.500 ;
        RECT 1.000 14.500 3.000 15.000 ;
        RECT 4.500 14.500 6.500 16.500 ;
        RECT 2.000 7.000 3.000 14.500 ;
        RECT 7.500 13.500 8.500 27.500 ;
        RECT 6.500 11.500 8.500 13.500 ;
        RECT 2.000 6.000 6.500 7.000 ;
        RECT 2.500 1.500 3.500 6.000 ;
        RECT 5.500 1.500 6.500 6.000 ;
        RECT 7.500 1.500 8.500 11.500 ;
  END
END cinv

#--------EOF---------

MACRO dff1
  CLASS CORE ;
  FOREIGN dff1 ;
  ORIGIN 0.000 0.000 ;
  SIZE 52.000 BY 29.000 ;
  SYMMETRY X Y R90 ;
  SITE core ;
  PIN QB
    DIRECTION INPUT ;
    USE SIGNAL ;
    PORT
      LAYER ML1 ;
        RECT 43.000 20.500 45.000 26.500 ;
        RECT 43.500 19.500 44.500 20.500 ;
        RECT 43.500 18.500 49.000 19.500 ;
        RECT 47.000 17.500 49.000 18.500 ;
        RECT 47.000 7.500 48.000 17.500 ;
        RECT 47.000 6.500 49.000 7.500 ;
        RECT 43.500 5.500 49.000 6.500 ;
        RECT 43.500 4.500 44.500 5.500 ;
        RECT 43.000 2.500 45.000 4.500 ;
    END
  END QB
  PIN VDD
    DIRECTION INOUT ;
    USE POWER ;
    SHAPE ABUTMENT ;
    PORT
      LAYER ML1 ;
        RECT -0.500 28.000 52.500 30.000 ;
        RECT 3.500 20.500 5.500 28.000 ;
        RECT 10.000 20.500 12.000 28.000 ;
        RECT 20.000 20.500 22.000 28.000 ;
        RECT 26.500 20.500 28.500 28.000 ;
        RECT 36.500 20.500 38.500 28.000 ;
        RECT 46.000 20.500 48.000 28.000 ;
    END
  END VDD
  PIN VSS
    DIRECTION INOUT ;
    USE GROUND ;
    SHAPE ABUTMENT ;
    PORT
      LAYER ML1 ;
        RECT 3.500 1.000 5.500 4.500 ;
        RECT 10.000 1.000 12.000 4.500 ;
        RECT 20.000 1.000 22.000 4.500 ;
        RECT 26.500 1.000 28.500 4.500 ;
        RECT 36.500 1.000 38.500 4.500 ;
        RECT 46.000 1.000 48.000 4.500 ;
        RECT -0.500 -1.000 52.500 1.000 ;
    END
  END VSS
  PIN CK
    DIRECTION INPUT ;
    USE SIGNAL ;
    PORT
      LAYER ML2 ;
        RECT 3.500 9.000 5.500 11.000 ;
    END
  END CK
  PIN D
    DIRECTION INPUT ;
    USE SIGNAL ;
    PORT
      LAYER ML2 ;
        RECT 11.000 9.000 13.000 11.000 ;
    END
  END D
  PIN Q
    DIRECTION INPUT ;
    USE SIGNAL ;
    PORT
      LAYER ML2 ;
        RECT 49.500 10.500 51.500 12.500 ;
    END
  END Q
  OBS
      LAYER ML1 ;
        RECT 0.500 20.500 2.500 26.500 ;
        RECT 6.500 20.500 8.500 26.500 ;
        RECT 15.000 20.500 17.000 26.500 ;
        RECT 23.000 20.500 25.000 26.500 ;
        RECT 31.500 20.500 33.500 26.500 ;
        RECT 39.500 20.500 41.500 26.500 ;
        RECT 49.000 20.500 51.000 26.500 ;
        RECT 1.000 19.000 2.000 20.500 ;
        RECT 4.500 19.000 6.500 19.500 ;
        RECT 1.000 18.000 6.500 19.000 ;
        RECT 1.000 13.500 2.000 18.000 ;
        RECT 4.500 17.500 6.500 18.000 ;
        RECT 7.500 16.500 8.500 20.500 ;
        RECT 15.500 19.000 16.500 20.500 ;
        RECT 24.000 19.500 25.000 20.500 ;
        RECT 32.000 19.500 33.000 20.500 ;
        RECT 21.000 19.000 23.000 19.500 ;
        RECT 15.500 18.000 23.000 19.000 ;
        RECT 24.000 18.500 27.500 19.500 ;
        RECT 32.000 18.500 39.500 19.500 ;
        RECT 21.000 17.500 23.000 18.000 ;
        RECT 25.500 17.500 27.500 18.500 ;
        RECT 37.500 17.500 39.500 18.500 ;
        RECT 16.000 16.500 18.000 17.000 ;
        RECT 30.500 16.500 32.500 17.500 ;
        RECT 7.000 15.500 32.500 16.500 ;
        RECT 40.500 17.000 41.500 20.500 ;
        RECT 44.000 17.000 46.000 17.500 ;
        RECT 40.500 16.000 46.000 17.000 ;
        RECT 4.000 13.500 6.000 14.000 ;
        RECT 1.000 12.500 6.000 13.500 ;
        RECT 1.000 7.000 2.000 12.500 ;
        RECT 4.000 12.000 6.000 12.500 ;
        RECT 3.500 9.000 5.500 11.000 ;
        RECT 7.000 9.500 8.000 15.500 ;
        RECT 16.000 15.000 18.000 15.500 ;
        RECT 9.000 13.500 11.000 14.000 ;
        RECT 14.000 13.500 16.000 14.000 ;
        RECT 27.500 13.500 29.500 14.000 ;
        RECT 32.500 13.500 34.500 14.500 ;
        RECT 9.000 12.500 34.500 13.500 ;
        RECT 35.500 14.000 37.500 14.500 ;
        RECT 40.500 14.000 41.500 16.000 ;
        RECT 44.000 15.500 46.000 16.000 ;
        RECT 35.500 13.000 41.500 14.000 ;
        RECT 35.500 12.500 37.500 13.000 ;
        RECT 9.000 12.000 11.000 12.500 ;
        RECT 14.000 12.000 16.000 12.500 ;
        RECT 27.500 12.000 29.500 12.500 ;
        RECT 7.000 8.500 8.500 9.500 ;
        RECT 11.000 9.000 13.000 11.000 ;
        RECT 21.000 10.000 23.000 11.000 ;
        RECT 17.000 9.000 23.000 10.000 ;
        RECT 40.500 9.000 41.500 13.000 ;
        RECT 50.000 12.500 51.000 20.500 ;
        RECT 49.500 10.500 51.500 12.500 ;
        RECT 44.000 9.000 46.000 9.500 ;
        RECT 4.500 7.000 6.500 7.500 ;
        RECT 1.000 6.000 6.500 7.000 ;
        RECT 1.000 4.500 2.000 6.000 ;
        RECT 4.500 5.500 6.500 6.000 ;
        RECT 7.500 7.000 8.500 8.500 ;
        RECT 14.000 7.000 16.000 7.500 ;
        RECT 7.500 6.000 16.000 7.000 ;
        RECT 7.500 4.500 8.500 6.000 ;
        RECT 14.000 5.500 16.000 6.000 ;
        RECT 17.000 4.500 18.000 9.000 ;
        RECT 40.500 8.000 46.000 9.000 ;
        RECT 19.000 7.000 21.000 7.500 ;
        RECT 25.500 7.000 27.500 7.500 ;
        RECT 37.500 7.000 39.500 7.500 ;
        RECT 19.000 6.000 27.500 7.000 ;
        RECT 19.000 5.500 21.000 6.000 ;
        RECT 23.500 4.500 24.500 6.000 ;
        RECT 25.500 5.500 27.500 6.000 ;
        RECT 32.000 6.000 39.500 7.000 ;
        RECT 32.000 4.500 33.000 6.000 ;
        RECT 37.500 5.500 39.500 6.000 ;
        RECT 40.500 4.500 41.500 8.000 ;
        RECT 44.000 7.500 46.000 8.000 ;
        RECT 50.000 4.500 51.000 10.500 ;
        RECT 0.500 2.500 2.500 4.500 ;
        RECT 6.500 2.500 8.500 4.500 ;
        RECT 15.000 2.500 18.000 4.500 ;
        RECT 23.000 2.500 25.000 4.500 ;
        RECT 31.500 2.500 33.500 4.500 ;
        RECT 39.500 2.500 41.500 4.500 ;
        RECT 49.000 2.500 51.000 4.500 ;
      LAYER POL ;
        RECT 2.500 19.000 3.500 27.500 ;
        RECT 5.500 19.500 6.500 27.500 ;
        RECT 1.500 18.000 3.500 19.000 ;
        RECT 1.500 11.000 2.500 18.000 ;
        RECT 4.500 17.500 6.500 19.500 ;
        RECT 4.000 13.500 6.000 14.000 ;
        RECT 9.000 13.500 11.000 14.000 ;
        RECT 4.000 12.500 11.000 13.500 ;
        RECT 4.000 12.000 6.000 12.500 ;
        RECT 9.000 12.000 11.000 12.500 ;
        RECT 12.000 11.000 13.000 27.500 ;
        RECT 14.000 14.000 15.000 27.500 ;
        RECT 17.000 17.000 18.000 27.500 ;
        RECT 16.000 15.000 18.000 17.000 ;
        RECT 14.000 12.000 16.000 14.000 ;
        RECT 1.500 10.000 5.500 11.000 ;
        RECT 2.500 9.000 5.500 10.000 ;
        RECT 11.000 9.000 13.000 11.000 ;
        RECT 15.000 10.500 16.000 12.000 ;
        RECT 15.000 9.500 18.000 10.500 ;
        RECT 2.500 1.500 3.500 9.000 ;
        RECT 4.500 5.500 6.500 7.500 ;
        RECT 5.500 1.500 6.500 5.500 ;
        RECT 12.000 1.500 13.000 9.000 ;
        RECT 14.000 5.500 16.000 7.500 ;
        RECT 14.000 1.500 15.000 5.500 ;
        RECT 17.000 1.500 18.000 9.500 ;
        RECT 19.000 7.500 20.000 27.500 ;
        RECT 22.000 19.500 23.000 27.500 ;
        RECT 21.000 17.500 23.000 19.500 ;
        RECT 25.500 19.000 27.500 19.500 ;
        RECT 28.500 19.000 29.500 27.500 ;
        RECT 25.500 18.000 29.500 19.000 ;
        RECT 25.500 17.500 27.500 18.000 ;
        RECT 30.500 17.500 31.500 27.500 ;
        RECT 21.500 11.000 22.500 17.500 ;
        RECT 21.000 9.000 23.000 11.000 ;
        RECT 19.000 5.500 21.000 7.500 ;
        RECT 19.000 1.500 20.000 5.500 ;
        RECT 22.000 1.500 23.000 9.000 ;
        RECT 25.500 7.500 26.500 17.500 ;
        RECT 30.500 15.500 32.500 17.500 ;
        RECT 27.500 12.000 29.500 14.000 ;
        RECT 28.000 9.500 29.000 12.000 ;
        RECT 30.500 11.500 31.500 15.500 ;
        RECT 33.500 14.500 34.500 27.500 ;
        RECT 32.500 12.500 34.500 14.500 ;
        RECT 35.500 14.500 36.500 27.500 ;
        RECT 38.500 19.500 39.500 27.500 ;
        RECT 37.500 17.500 39.500 19.500 ;
        RECT 45.000 17.500 46.000 27.500 ;
        RECT 48.000 19.500 49.000 27.500 ;
        RECT 47.000 17.500 49.000 19.500 ;
        RECT 35.500 12.500 37.500 14.500 ;
        RECT 30.500 10.500 34.500 11.500 ;
        RECT 28.000 8.500 31.500 9.500 ;
        RECT 25.500 6.500 27.500 7.500 ;
        RECT 25.500 5.500 29.500 6.500 ;
        RECT 28.500 1.500 29.500 5.500 ;
        RECT 30.500 1.500 31.500 8.500 ;
        RECT 33.500 1.500 34.500 10.500 ;
        RECT 35.500 1.500 36.500 12.500 ;
        RECT 38.500 7.500 39.500 17.500 ;
        RECT 44.000 15.500 46.000 17.500 ;
        RECT 44.000 7.500 46.000 9.500 ;
        RECT 37.500 5.500 39.500 7.500 ;
        RECT 38.500 1.500 39.500 5.500 ;
        RECT 45.000 1.500 46.000 7.500 ;
        RECT 47.000 5.500 49.000 7.500 ;
        RECT 48.000 1.500 49.000 5.500 ;
  END
END dff1

#--------EOF---------

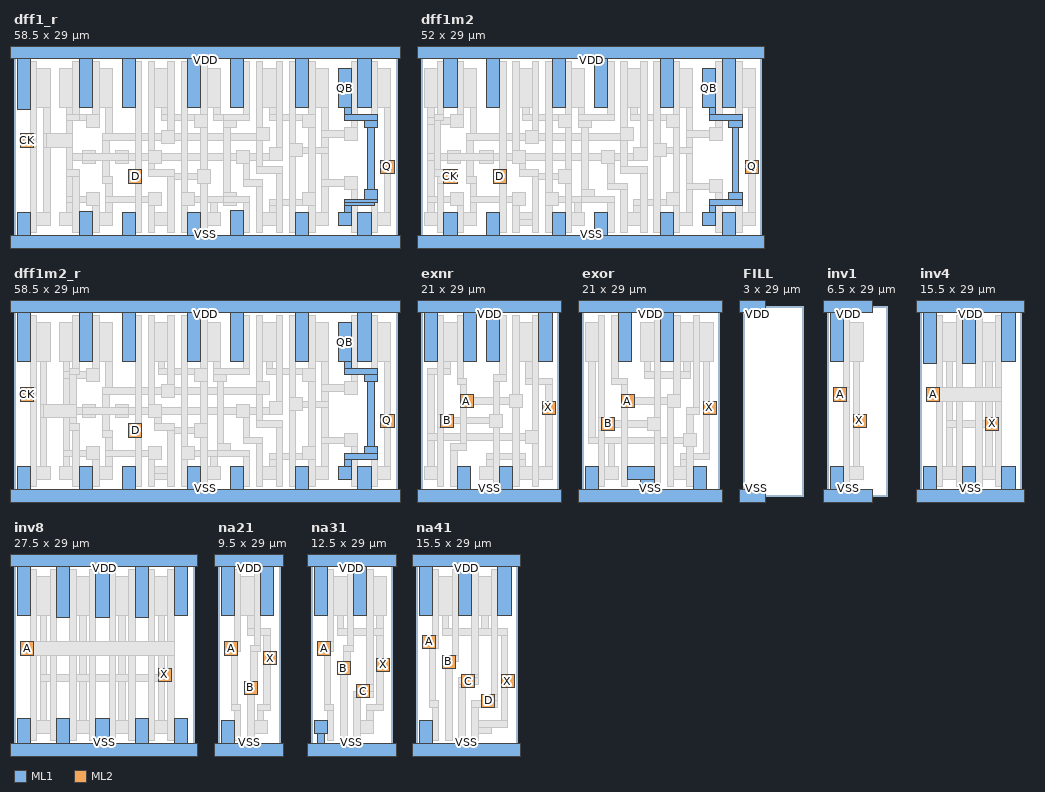
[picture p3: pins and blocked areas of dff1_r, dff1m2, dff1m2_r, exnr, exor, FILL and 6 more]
MACRO dff1_r
  CLASS CORE ;
  FOREIGN dff1_r ;
  ORIGIN 0.000 0.000 ;
  SIZE 58.500 BY 29.000 ;
  SYMMETRY X Y R90 ;
  SITE core ;
  PIN VSS
    DIRECTION INOUT ;
    USE GROUND ;
    SHAPE ABUTMENT ;
    PORT
      LAYER ML1 ;
        RECT 0.500 1.000 2.500 4.500 ;
        RECT 10.000 1.000 12.000 4.600 ;
        RECT 16.500 1.000 18.500 4.500 ;
        RECT 26.500 1.000 28.500 4.500 ;
        RECT 33.000 1.000 35.000 4.800 ;
        RECT 43.000 1.000 45.000 4.500 ;
        RECT 52.500 1.000 54.500 4.500 ;
        RECT -0.500 -1.000 59.000 1.000 ;
    END
  END VSS
  PIN VDD
    DIRECTION INOUT ;
    USE POWER ;
    SHAPE ABUTMENT ;
    PORT
      LAYER ML1 ;
        RECT -0.500 28.000 59.000 30.000 ;
        RECT 0.500 20.300 2.500 28.000 ;
        RECT 10.000 20.500 12.000 28.000 ;
        RECT 16.500 20.500 18.500 28.000 ;
        RECT 26.500 20.500 28.500 28.000 ;
        RECT 33.000 20.500 35.000 28.000 ;
        RECT 43.000 20.500 45.000 28.000 ;
        RECT 52.500 20.500 54.500 28.000 ;
    END
  END VDD
  PIN QB
    DIRECTION INPUT ;
    USE SIGNAL ;
    PORT
      LAYER ML1 ;
        RECT 49.500 20.500 51.500 26.500 ;
        RECT 50.500 19.500 51.500 20.500 ;
        RECT 50.500 18.500 55.500 19.500 ;
        RECT 53.500 17.500 55.500 18.500 ;
        RECT 54.000 8.000 55.000 17.500 ;
        RECT 53.500 6.500 55.500 8.000 ;
        RECT 50.500 6.000 55.500 6.500 ;
        RECT 50.500 5.500 55.000 6.000 ;
        RECT 50.500 4.500 51.500 5.500 ;
        RECT 49.500 2.500 51.500 4.500 ;
    END
  END QB
  PIN CK
    DIRECTION INPUT ;
    USE SIGNAL ;
    PORT
      LAYER ML2 ;
        RECT 1.000 14.500 3.000 16.500 ;
    END
  END CK
  PIN D
    DIRECTION INPUT ;
    USE SIGNAL ;
    PORT
      LAYER ML2 ;
        RECT 17.500 9.000 19.500 11.000 ;
    END
  END D
  PIN Q
    DIRECTION INPUT ;
    USE SIGNAL ;
    PORT
      LAYER ML2 ;
        RECT 56.000 10.500 58.000 12.500 ;
    END
  END Q
  OBS
      LAYER ML1 ;
        RECT 3.500 20.500 5.500 26.500 ;
        RECT 7.000 20.500 9.000 26.500 ;
        RECT 13.000 20.500 15.000 26.500 ;
        RECT 21.500 20.500 23.500 26.500 ;
        RECT 29.500 20.500 31.500 26.500 ;
        RECT 38.000 20.500 40.000 26.500 ;
        RECT 46.000 20.500 48.000 26.500 ;
        RECT 55.500 20.500 57.500 26.500 ;
        RECT 4.500 16.500 5.500 20.500 ;
        RECT 8.000 19.500 9.000 20.500 ;
        RECT 8.000 18.500 13.000 19.500 ;
        RECT 1.000 14.500 3.000 16.500 ;
        RECT 4.500 14.500 7.000 16.500 ;
        RECT 4.500 4.500 5.500 14.500 ;
        RECT 8.000 13.500 9.000 18.500 ;
        RECT 11.000 17.500 13.000 18.500 ;
        RECT 14.000 16.500 15.000 20.500 ;
        RECT 22.500 19.500 23.500 20.500 ;
        RECT 30.500 19.500 31.500 20.500 ;
        RECT 39.000 19.500 40.000 20.500 ;
        RECT 22.500 18.500 29.500 19.500 ;
        RECT 30.500 18.500 34.000 19.500 ;
        RECT 39.000 18.500 46.000 19.500 ;
        RECT 27.500 17.500 29.500 18.500 ;
        RECT 32.000 17.500 34.000 18.500 ;
        RECT 44.000 17.500 46.000 18.500 ;
        RECT 22.500 16.500 24.500 17.000 ;
        RECT 37.000 16.500 39.000 17.500 ;
        RECT 13.500 15.500 39.000 16.500 ;
        RECT 47.000 17.000 48.000 20.500 ;
        RECT 50.500 17.000 52.500 17.500 ;
        RECT 47.000 16.000 52.500 17.000 ;
        RECT 10.500 13.500 12.500 14.000 ;
        RECT 8.000 12.500 12.500 13.500 ;
        RECT 8.000 7.000 9.000 12.500 ;
        RECT 10.500 12.000 12.500 12.500 ;
        RECT 13.500 10.000 14.500 15.500 ;
        RECT 22.500 15.000 24.500 15.500 ;
        RECT 42.000 14.500 44.000 15.000 ;
        RECT 47.000 14.500 48.000 16.000 ;
        RECT 50.500 15.500 52.500 16.000 ;
        RECT 15.500 13.500 17.500 14.000 ;
        RECT 20.500 13.500 22.500 14.000 ;
        RECT 34.000 13.500 36.000 14.000 ;
        RECT 39.000 13.500 41.000 14.500 ;
        RECT 15.500 12.500 41.000 13.500 ;
        RECT 42.000 13.500 48.000 14.500 ;
        RECT 42.000 13.000 44.000 13.500 ;
        RECT 15.500 12.000 17.500 12.500 ;
        RECT 20.500 12.000 22.500 12.500 ;
        RECT 34.000 12.000 36.000 12.500 ;
        RECT 13.500 9.000 15.000 10.000 ;
        RECT 17.500 9.000 19.500 11.000 ;
        RECT 28.000 10.500 30.000 11.000 ;
        RECT 23.500 9.500 30.000 10.500 ;
        RECT 11.000 7.000 13.000 7.500 ;
        RECT 8.000 6.000 13.000 7.000 ;
        RECT 8.000 4.500 9.000 6.000 ;
        RECT 11.000 5.500 13.000 6.000 ;
        RECT 14.000 7.000 15.000 9.000 ;
        RECT 20.500 7.000 22.500 7.500 ;
        RECT 14.000 6.000 22.500 7.000 ;
        RECT 14.000 4.500 15.000 6.000 ;
        RECT 20.500 5.500 22.500 6.000 ;
        RECT 23.500 4.500 24.500 9.500 ;
        RECT 28.000 9.000 30.000 9.500 ;
        RECT 47.000 9.500 48.000 13.500 ;
        RECT 56.500 12.500 57.500 20.500 ;
        RECT 56.000 10.500 58.000 12.500 ;
        RECT 50.500 9.500 52.500 10.000 ;
        RECT 47.000 8.500 52.500 9.500 ;
        RECT 25.500 7.000 27.500 7.500 ;
        RECT 32.000 7.000 34.000 7.500 ;
        RECT 25.500 6.000 34.000 7.000 ;
        RECT 44.000 6.500 46.000 7.500 ;
        RECT 25.500 5.500 27.500 6.000 ;
        RECT 30.000 4.500 31.000 6.000 ;
        RECT 32.000 5.500 34.000 6.000 ;
        RECT 39.000 5.500 46.000 6.500 ;
        RECT 39.000 4.500 40.000 5.500 ;
        RECT 47.000 4.500 48.000 8.500 ;
        RECT 50.500 8.000 52.500 8.500 ;
        RECT 56.500 4.500 57.500 10.500 ;
        RECT 3.500 2.500 5.500 4.500 ;
        RECT 7.000 2.500 9.000 4.500 ;
        RECT 13.000 2.500 15.000 4.500 ;
        RECT 21.500 2.500 24.500 4.500 ;
        RECT 29.500 2.500 31.500 4.500 ;
        RECT 38.000 2.500 40.000 4.500 ;
        RECT 46.000 2.500 48.000 4.500 ;
        RECT 55.500 2.500 57.500 4.500 ;
      LAYER POL ;
        RECT 2.500 16.500 3.500 27.500 ;
        RECT 9.000 19.500 10.000 27.500 ;
        RECT 12.000 19.500 13.000 27.500 ;
        RECT 8.000 18.500 10.000 19.500 ;
        RECT 8.000 16.500 9.000 18.500 ;
        RECT 11.000 17.500 13.000 19.500 ;
        RECT 1.000 14.500 3.500 16.500 ;
        RECT 5.000 14.500 9.000 16.500 ;
        RECT 2.500 1.500 3.500 14.500 ;
        RECT 8.000 11.000 9.000 14.500 ;
        RECT 10.500 13.500 12.500 14.000 ;
        RECT 15.500 13.500 17.500 14.000 ;
        RECT 10.500 12.500 17.500 13.500 ;
        RECT 10.500 12.000 12.500 12.500 ;
        RECT 15.500 12.000 17.500 12.500 ;
        RECT 18.500 11.000 19.500 27.500 ;
        RECT 8.000 10.000 10.000 11.000 ;
        RECT 9.000 1.500 10.000 10.000 ;
        RECT 17.500 9.000 19.500 11.000 ;
        RECT 20.500 14.000 21.500 27.500 ;
        RECT 23.500 17.000 24.500 27.500 ;
        RECT 22.500 15.000 24.500 17.000 ;
        RECT 20.500 12.000 22.500 14.000 ;
        RECT 20.500 11.000 21.500 12.000 ;
        RECT 20.500 10.000 24.500 11.000 ;
        RECT 11.000 5.500 13.000 7.500 ;
        RECT 12.000 1.500 13.000 5.500 ;
        RECT 18.500 1.500 19.500 9.000 ;
        RECT 20.500 5.500 22.500 7.500 ;
        RECT 20.500 1.500 21.500 5.500 ;
        RECT 23.500 1.500 24.500 10.000 ;
        RECT 25.500 7.500 26.500 27.500 ;
        RECT 28.500 19.500 29.500 27.500 ;
        RECT 35.000 19.500 36.000 27.500 ;
        RECT 27.500 17.500 29.500 19.500 ;
        RECT 28.500 11.000 29.500 17.500 ;
        RECT 32.000 18.500 36.000 19.500 ;
        RECT 32.000 17.500 34.000 18.500 ;
        RECT 37.000 17.500 38.000 27.500 ;
        RECT 28.000 9.000 30.000 11.000 ;
        RECT 25.500 5.500 27.500 7.500 ;
        RECT 25.500 1.500 26.500 5.500 ;
        RECT 28.500 1.500 29.500 9.000 ;
        RECT 32.000 7.500 33.000 17.500 ;
        RECT 37.000 15.500 39.000 17.500 ;
        RECT 34.000 12.000 36.000 14.000 ;
        RECT 35.000 9.500 36.000 12.000 ;
        RECT 37.000 11.500 38.000 15.500 ;
        RECT 40.000 14.500 41.000 27.500 ;
        RECT 39.000 12.500 41.000 14.500 ;
        RECT 42.000 15.000 43.000 27.500 ;
        RECT 45.000 19.500 46.000 27.500 ;
        RECT 44.000 17.500 46.000 19.500 ;
        RECT 51.500 17.500 52.500 27.500 ;
        RECT 54.500 19.500 55.500 27.500 ;
        RECT 53.500 17.500 55.500 19.500 ;
        RECT 42.000 13.000 44.000 15.000 ;
        RECT 37.000 10.500 41.000 11.500 ;
        RECT 35.000 8.500 38.000 9.500 ;
        RECT 32.000 7.000 34.000 7.500 ;
        RECT 32.000 6.000 36.000 7.000 ;
        RECT 32.000 5.500 34.000 6.000 ;
        RECT 35.000 1.500 36.000 6.000 ;
        RECT 37.000 1.500 38.000 8.500 ;
        RECT 40.000 1.500 41.000 10.500 ;
        RECT 42.000 1.500 43.000 13.000 ;
        RECT 45.000 7.500 46.000 17.500 ;
        RECT 50.500 15.500 52.500 17.500 ;
        RECT 50.500 8.000 52.500 10.000 ;
        RECT 44.000 5.500 46.000 7.500 ;
        RECT 45.000 1.500 46.000 5.500 ;
        RECT 51.500 1.500 52.500 8.000 ;
        RECT 53.500 6.000 55.500 8.000 ;
        RECT 54.500 1.500 55.500 6.000 ;
  END
END dff1_r

#--------EOF---------

MACRO dff1m2
  CLASS CORE ;
  FOREIGN dff1m2 ;
  ORIGIN 0.000 0.000 ;
  SIZE 52.000 BY 29.000 ;
  SYMMETRY X Y R90 ;
  SITE core ;
  PIN QB
    DIRECTION INPUT ;
    USE SIGNAL ;
    PORT
      LAYER ML1 ;
        RECT 43.000 20.500 45.000 26.500 ;
        RECT 44.000 19.500 45.000 20.500 ;
        RECT 44.000 18.500 49.000 19.500 ;
        RECT 47.000 17.500 49.000 18.500 ;
        RECT 47.500 7.500 48.500 17.500 ;
        RECT 47.000 6.500 49.000 7.500 ;
        RECT 44.000 5.500 49.000 6.500 ;
        RECT 44.000 4.500 45.000 5.500 ;
        RECT 43.000 2.500 45.000 4.500 ;
    END
  END QB
  PIN VSS
    DIRECTION INOUT ;
    USE GROUND ;
    SHAPE ABUTMENT ;
    PORT
      LAYER ML1 ;
        RECT 3.500 1.000 5.500 4.500 ;
        RECT 10.000 1.000 12.000 4.500 ;
        RECT 20.000 1.000 22.000 4.500 ;
        RECT 26.500 1.000 28.500 4.500 ;
        RECT 36.500 1.000 38.500 4.500 ;
        RECT 46.000 1.000 48.000 4.500 ;
        RECT -0.500 -1.000 52.500 1.000 ;
    END
  END VSS
  PIN VDD
    DIRECTION INOUT ;
    USE POWER ;
    SHAPE ABUTMENT ;
    PORT
      LAYER ML1 ;
        RECT -0.500 28.000 52.500 30.000 ;
        RECT 3.500 20.500 5.500 28.000 ;
        RECT 10.000 20.500 12.000 28.000 ;
        RECT 20.000 20.500 22.000 28.000 ;
        RECT 26.500 20.500 28.500 28.000 ;
        RECT 36.500 20.500 38.500 28.000 ;
        RECT 46.000 20.500 48.000 28.000 ;
    END
  END VDD
  PIN CK
    DIRECTION INPUT ;
    USE SIGNAL ;
    PORT
      LAYER ML2 ;
        RECT 3.500 9.000 5.500 11.000 ;
    END
  END CK
  PIN D
    DIRECTION INPUT ;
    USE SIGNAL ;
    PORT
      LAYER ML2 ;
        RECT 11.000 9.000 13.000 11.000 ;
    END
  END D
  PIN Q
    DIRECTION INPUT ;
    USE SIGNAL ;
    PORT
      LAYER ML2 ;
        RECT 49.500 10.500 51.500 12.500 ;
    END
  END Q
  OBS
      LAYER ML1 ;
        RECT 0.500 20.500 2.500 26.500 ;
        RECT 6.500 20.500 8.500 26.500 ;
        RECT 15.000 20.500 17.000 26.500 ;
        RECT 23.000 20.500 25.000 26.500 ;
        RECT 31.500 20.500 33.500 26.500 ;
        RECT 39.500 20.500 41.500 26.500 ;
        RECT 49.000 20.500 51.000 26.500 ;
        RECT 1.000 19.000 2.000 20.500 ;
        RECT 4.500 19.000 6.500 19.500 ;
        RECT 1.000 18.000 6.500 19.000 ;
        RECT 1.000 13.500 2.000 18.000 ;
        RECT 4.500 17.500 6.500 18.000 ;
        RECT 7.500 16.500 8.500 20.500 ;
        RECT 15.500 19.500 16.500 20.500 ;
        RECT 24.000 19.500 25.000 20.500 ;
        RECT 32.000 19.500 33.000 20.500 ;
        RECT 15.500 18.500 23.000 19.500 ;
        RECT 21.000 17.500 23.000 18.500 ;
        RECT 24.000 17.500 26.000 19.500 ;
        RECT 32.000 18.500 39.500 19.500 ;
        RECT 37.500 17.500 39.500 18.500 ;
        RECT 16.000 16.500 18.000 17.000 ;
        RECT 30.500 16.500 32.500 17.500 ;
        RECT 7.000 15.500 32.500 16.500 ;
        RECT 40.500 17.000 41.500 20.500 ;
        RECT 44.000 17.000 46.000 17.500 ;
        RECT 40.500 16.000 46.000 17.000 ;
        RECT 4.000 13.500 6.000 14.000 ;
        RECT 1.000 12.500 6.000 13.500 ;
        RECT 1.000 7.000 2.000 12.500 ;
        RECT 4.000 12.000 6.000 12.500 ;
        RECT 3.500 9.000 5.500 11.000 ;
        RECT 7.000 10.000 8.000 15.500 ;
        RECT 16.000 15.000 18.000 15.500 ;
        RECT 35.500 14.500 37.500 15.000 ;
        RECT 40.500 14.500 41.500 16.000 ;
        RECT 44.000 15.500 46.000 16.000 ;
        RECT 9.000 13.500 11.000 14.000 ;
        RECT 14.000 13.500 16.000 14.000 ;
        RECT 27.500 13.500 29.500 14.000 ;
        RECT 32.500 13.500 34.500 14.500 ;
        RECT 9.000 12.500 34.500 13.500 ;
        RECT 35.500 13.500 41.500 14.500 ;
        RECT 35.500 13.000 37.500 13.500 ;
        RECT 9.000 12.000 11.000 12.500 ;
        RECT 14.000 12.000 16.000 12.500 ;
        RECT 27.500 12.000 29.500 12.500 ;
        RECT 7.000 9.000 8.500 10.000 ;
        RECT 11.000 9.000 13.000 11.000 ;
        RECT 21.000 10.500 23.000 11.000 ;
        RECT 17.000 9.500 23.000 10.500 ;
        RECT 4.500 7.000 6.500 7.500 ;
        RECT 1.000 6.000 6.500 7.000 ;
        RECT 1.000 4.500 2.000 6.000 ;
        RECT 4.500 5.500 6.500 6.000 ;
        RECT 7.500 7.000 8.500 9.000 ;
        RECT 14.000 7.000 16.000 7.500 ;
        RECT 7.500 6.000 16.000 7.000 ;
        RECT 7.500 4.500 8.500 6.000 ;
        RECT 14.000 5.500 16.000 6.000 ;
        RECT 17.000 4.500 18.000 9.500 ;
        RECT 21.000 9.000 23.000 9.500 ;
        RECT 40.500 9.000 41.500 13.500 ;
        RECT 50.000 12.500 51.000 20.500 ;
        RECT 49.500 10.500 51.500 12.500 ;
        RECT 44.000 9.000 46.000 9.500 ;
        RECT 40.500 8.000 46.000 9.000 ;
        RECT 19.000 7.000 21.000 7.500 ;
        RECT 24.500 7.000 26.500 8.000 ;
        RECT 19.000 6.000 26.500 7.000 ;
        RECT 37.500 6.500 39.500 7.500 ;
        RECT 19.000 5.500 21.000 6.000 ;
        RECT 23.500 4.500 24.500 6.000 ;
        RECT 32.500 5.500 39.500 6.500 ;
        RECT 32.500 4.500 33.500 5.500 ;
        RECT 40.500 4.500 41.500 8.000 ;
        RECT 44.000 7.500 46.000 8.000 ;
        RECT 50.000 4.500 51.000 10.500 ;
        RECT 0.500 2.500 2.500 4.500 ;
        RECT 6.500 2.500 8.500 4.500 ;
        RECT 15.000 3.500 18.000 4.500 ;
        RECT 15.000 2.500 17.000 3.500 ;
        RECT 23.000 2.500 25.000 4.500 ;
        RECT 31.500 2.500 33.500 4.500 ;
        RECT 39.500 2.500 41.500 4.500 ;
        RECT 49.000 2.500 51.000 4.500 ;
      LAYER ML2 ;
        RECT 21.000 17.500 23.000 19.500 ;
        RECT 24.000 17.500 26.000 19.500 ;
        RECT 37.500 17.500 39.500 19.500 ;
        RECT 22.000 11.000 23.000 17.500 ;
        RECT 21.000 9.000 23.000 11.000 ;
        RECT 24.500 8.000 25.500 17.500 ;
        RECT 24.500 6.000 26.500 8.000 ;
        RECT 38.500 7.500 39.500 17.500 ;
        RECT 37.500 5.500 39.500 7.500 ;
      LAYER POL ;
        RECT 2.500 19.500 3.500 27.500 ;
        RECT 5.500 19.500 6.500 27.500 ;
        RECT 2.000 18.500 3.500 19.500 ;
        RECT 2.000 11.000 3.000 18.500 ;
        RECT 4.500 17.500 6.500 19.500 ;
        RECT 4.000 13.500 6.000 14.000 ;
        RECT 9.000 13.500 11.000 14.000 ;
        RECT 4.000 12.500 11.000 13.500 ;
        RECT 4.000 12.000 6.000 12.500 ;
        RECT 9.000 12.000 11.000 12.500 ;
        RECT 12.000 11.000 13.000 27.500 ;
        RECT 14.000 14.000 15.000 27.500 ;
        RECT 17.000 17.000 18.000 27.500 ;
        RECT 16.000 15.000 18.000 17.000 ;
        RECT 14.000 12.000 16.000 14.000 ;
        RECT 2.000 10.000 5.500 11.000 ;
        RECT 2.500 9.000 5.500 10.000 ;
        RECT 11.000 9.000 13.000 11.000 ;
        RECT 15.000 11.000 16.000 12.000 ;
        RECT 15.000 10.000 18.000 11.000 ;
        RECT 2.500 1.500 3.500 9.000 ;
        RECT 4.500 5.500 6.500 7.500 ;
        RECT 5.500 1.500 6.500 5.500 ;
        RECT 12.000 1.500 13.000 9.000 ;
        RECT 14.000 5.500 16.000 7.500 ;
        RECT 14.000 1.500 15.000 5.500 ;
        RECT 17.000 1.500 18.000 10.000 ;
        RECT 19.000 7.500 20.000 27.500 ;
        RECT 22.000 19.500 23.000 27.500 ;
        RECT 28.500 19.500 29.500 27.500 ;
        RECT 21.000 17.500 23.000 19.500 ;
        RECT 24.000 18.500 29.500 19.500 ;
        RECT 24.000 17.500 26.000 18.500 ;
        RECT 30.500 17.500 31.500 27.500 ;
        RECT 30.500 15.500 32.500 17.500 ;
        RECT 27.500 12.000 29.500 14.000 ;
        RECT 21.000 9.000 23.000 11.000 ;
        RECT 19.000 5.500 21.000 7.500 ;
        RECT 19.000 1.500 20.000 5.500 ;
        RECT 22.000 1.500 23.000 9.000 ;
        RECT 28.500 9.000 29.500 12.000 ;
        RECT 30.500 11.500 31.500 15.500 ;
        RECT 33.500 14.500 34.500 27.500 ;
        RECT 32.500 12.500 34.500 14.500 ;
        RECT 35.500 15.000 36.500 27.500 ;
        RECT 38.500 19.500 39.500 27.500 ;
        RECT 37.500 17.500 39.500 19.500 ;
        RECT 45.000 17.500 46.000 27.500 ;
        RECT 48.000 19.500 49.000 27.500 ;
        RECT 47.000 17.500 49.000 19.500 ;
        RECT 44.000 15.500 46.000 17.500 ;
        RECT 35.500 13.000 37.500 15.000 ;
        RECT 30.500 10.500 34.500 11.500 ;
        RECT 28.500 8.000 31.500 9.000 ;
        RECT 24.500 7.000 26.500 8.000 ;
        RECT 24.500 6.000 29.500 7.000 ;
        RECT 28.500 1.500 29.500 6.000 ;
        RECT 30.500 1.500 31.500 8.000 ;
        RECT 33.500 1.500 34.500 10.500 ;
        RECT 35.500 1.500 36.500 13.000 ;
        RECT 44.000 7.500 46.000 9.500 ;
        RECT 37.500 5.500 39.500 7.500 ;
        RECT 38.500 1.500 39.500 5.500 ;
        RECT 45.000 1.500 46.000 7.500 ;
        RECT 47.000 5.500 49.000 7.500 ;
        RECT 48.000 1.500 49.000 5.500 ;
  END
END dff1m2

#--------EOF---------

MACRO dff1m2_r
  CLASS CORE ;
  FOREIGN dff1m2_r ;
  ORIGIN 0.000 0.000 ;
  SIZE 58.500 BY 29.000 ;
  SYMMETRY X Y R90 ;
  SITE core ;
  PIN QB
    DIRECTION INPUT ;
    USE SIGNAL ;
    PORT
      LAYER ML1 ;
        RECT 49.500 20.500 51.500 26.500 ;
        RECT 50.500 19.500 51.500 20.500 ;
        RECT 50.500 18.500 55.500 19.500 ;
        RECT 53.500 17.500 55.500 18.500 ;
        RECT 54.000 7.500 55.000 17.500 ;
        RECT 53.500 6.500 55.500 7.500 ;
        RECT 50.500 5.500 55.500 6.500 ;
        RECT 50.500 4.500 51.500 5.500 ;
        RECT 49.500 2.500 51.500 4.500 ;
    END
  END QB
  PIN VDD
    DIRECTION INOUT ;
    USE POWER ;
    SHAPE ABUTMENT ;
    PORT
      LAYER ML1 ;
        RECT -0.500 28.000 59.000 30.000 ;
        RECT 0.500 20.500 2.500 28.000 ;
        RECT 10.000 20.500 12.000 28.000 ;
        RECT 16.500 20.500 18.500 28.000 ;
        RECT 26.500 20.500 28.500 28.000 ;
        RECT 33.000 20.500 35.000 28.000 ;
        RECT 43.000 20.500 45.000 28.000 ;
        RECT 52.500 20.500 54.500 28.000 ;
    END
  END VDD
  PIN VSS
    DIRECTION INOUT ;
    USE GROUND ;
    SHAPE ABUTMENT ;
    PORT
      LAYER ML1 ;
        RECT 0.500 1.000 2.500 4.500 ;
        RECT 10.000 1.000 12.000 4.500 ;
        RECT 16.500 1.000 18.500 4.500 ;
        RECT 26.500 1.000 28.500 4.500 ;
        RECT 33.000 1.000 35.000 4.500 ;
        RECT 43.000 1.000 45.000 4.500 ;
        RECT 52.500 1.000 54.500 4.500 ;
        RECT -0.500 -1.000 59.000 1.000 ;
    END
  END VSS
  PIN CK
    DIRECTION INPUT ;
    USE SIGNAL ;
    PORT
      LAYER ML2 ;
        RECT 1.000 14.500 3.000 16.500 ;
    END
  END CK
  PIN D
    DIRECTION INPUT ;
    USE SIGNAL ;
    PORT
      LAYER ML2 ;
        RECT 17.500 9.000 19.500 11.000 ;
    END
  END D
  PIN Q
    DIRECTION INPUT ;
    USE SIGNAL ;
    PORT
      LAYER ML2 ;
        RECT 56.000 10.500 58.000 12.500 ;
    END
  END Q
  OBS
      LAYER ML1 ;
        RECT 3.500 20.500 5.500 26.500 ;
        RECT 7.000 20.500 9.000 26.500 ;
        RECT 13.000 20.500 15.000 26.500 ;
        RECT 21.500 20.500 23.500 26.500 ;
        RECT 29.500 20.500 31.500 26.500 ;
        RECT 38.000 20.500 40.000 26.500 ;
        RECT 46.000 20.500 48.000 26.500 ;
        RECT 55.500 20.500 57.500 26.500 ;
        RECT 1.000 14.500 3.000 16.500 ;
        RECT 4.000 14.000 5.000 20.500 ;
        RECT 7.500 19.000 8.500 20.500 ;
        RECT 11.000 19.000 13.000 19.500 ;
        RECT 7.500 18.000 13.000 19.000 ;
        RECT 4.000 12.000 6.500 14.000 ;
        RECT 7.500 13.500 8.500 18.000 ;
        RECT 11.000 17.500 13.000 18.000 ;
        RECT 14.000 16.500 15.000 20.500 ;
        RECT 22.000 19.500 23.000 20.500 ;
        RECT 30.500 19.500 31.500 20.500 ;
        RECT 38.500 19.500 39.500 20.500 ;
        RECT 22.000 18.500 29.500 19.500 ;
        RECT 27.500 17.500 29.500 18.500 ;
        RECT 30.500 17.500 32.500 19.500 ;
        RECT 38.500 18.500 46.000 19.500 ;
        RECT 44.000 17.500 46.000 18.500 ;
        RECT 22.500 16.500 24.500 17.000 ;
        RECT 37.000 16.500 39.000 17.500 ;
        RECT 13.500 15.500 39.000 16.500 ;
        RECT 47.000 17.000 48.000 20.500 ;
        RECT 50.500 17.000 52.500 17.500 ;
        RECT 47.000 16.000 52.500 17.000 ;
        RECT 10.500 13.500 12.500 14.000 ;
        RECT 7.500 12.500 12.500 13.500 ;
        RECT 4.000 4.500 5.000 12.000 ;
        RECT 7.500 7.000 8.500 12.500 ;
        RECT 10.500 12.000 12.500 12.500 ;
        RECT 13.500 10.000 14.500 15.500 ;
        RECT 22.500 15.000 24.500 15.500 ;
        RECT 42.000 14.500 44.000 15.000 ;
        RECT 47.000 14.500 48.000 16.000 ;
        RECT 50.500 15.500 52.500 16.000 ;
        RECT 15.500 13.500 17.500 14.000 ;
        RECT 20.500 13.500 22.500 14.000 ;
        RECT 34.000 13.500 36.000 14.000 ;
        RECT 39.000 13.500 41.000 14.500 ;
        RECT 15.500 12.500 41.000 13.500 ;
        RECT 42.000 13.500 48.000 14.500 ;
        RECT 42.000 13.000 44.000 13.500 ;
        RECT 15.500 12.000 17.500 12.500 ;
        RECT 20.500 12.000 22.500 12.500 ;
        RECT 34.000 12.000 36.000 12.500 ;
        RECT 13.500 9.000 15.000 10.000 ;
        RECT 17.500 9.000 19.500 11.000 ;
        RECT 27.500 10.500 29.500 11.000 ;
        RECT 23.500 9.500 29.500 10.500 ;
        RECT 11.000 7.000 13.000 7.500 ;
        RECT 7.500 6.000 13.000 7.000 ;
        RECT 7.500 4.500 8.500 6.000 ;
        RECT 11.000 5.500 13.000 6.000 ;
        RECT 14.000 7.000 15.000 9.000 ;
        RECT 20.500 7.000 22.500 7.500 ;
        RECT 14.000 6.000 22.500 7.000 ;
        RECT 14.000 4.500 15.000 6.000 ;
        RECT 20.500 5.500 22.500 6.000 ;
        RECT 23.500 4.500 24.500 9.500 ;
        RECT 27.500 9.000 29.500 9.500 ;
        RECT 47.000 9.000 48.000 13.500 ;
        RECT 56.500 12.500 57.500 20.500 ;
        RECT 56.000 10.500 58.000 12.500 ;
        RECT 50.500 9.000 52.500 9.500 ;
        RECT 47.000 8.000 52.500 9.000 ;
        RECT 25.500 7.000 27.500 7.500 ;
        RECT 31.000 7.000 33.000 8.000 ;
        RECT 25.500 6.000 33.000 7.000 ;
        RECT 44.000 6.500 46.000 7.500 ;
        RECT 25.500 5.500 27.500 6.000 ;
        RECT 30.000 4.500 31.000 6.000 ;
        RECT 39.000 5.500 46.000 6.500 ;
        RECT 39.000 4.500 40.000 5.500 ;
        RECT 47.000 4.500 48.000 8.000 ;
        RECT 50.500 7.500 52.500 8.000 ;
        RECT 56.500 4.500 57.500 10.500 ;
        RECT 3.500 2.500 5.500 4.500 ;
        RECT 7.000 2.500 9.000 4.500 ;
        RECT 13.000 2.500 15.000 4.500 ;
        RECT 21.500 3.500 24.500 4.500 ;
        RECT 21.500 2.500 23.500 3.500 ;
        RECT 29.500 2.500 31.500 4.500 ;
        RECT 38.000 2.500 40.000 4.500 ;
        RECT 46.000 2.500 48.000 4.500 ;
        RECT 55.500 2.500 57.500 4.500 ;
      LAYER ML2 ;
        RECT 27.500 17.500 29.500 19.500 ;
        RECT 30.500 17.500 32.500 19.500 ;
        RECT 44.000 17.500 46.000 19.500 ;
        RECT 28.500 11.000 29.500 17.500 ;
        RECT 27.500 9.000 29.500 11.000 ;
        RECT 31.000 8.000 32.000 17.500 ;
        RECT 31.000 6.000 33.000 8.000 ;
        RECT 45.000 7.500 46.000 17.500 ;
        RECT 44.000 5.500 46.000 7.500 ;
      LAYER POL ;
        RECT 2.500 16.500 3.500 27.500 ;
        RECT 9.000 19.500 10.000 27.500 ;
        RECT 12.000 19.500 13.000 27.500 ;
        RECT 1.000 14.500 3.500 16.500 ;
        RECT 2.500 1.500 3.500 14.500 ;
        RECT 8.500 18.500 10.000 19.500 ;
        RECT 8.500 14.000 9.500 18.500 ;
        RECT 11.000 17.500 13.000 19.500 ;
        RECT 4.500 12.000 9.500 14.000 ;
        RECT 10.500 13.500 12.500 14.000 ;
        RECT 15.500 13.500 17.500 14.000 ;
        RECT 10.500 12.500 17.500 13.500 ;
        RECT 10.500 12.000 12.500 12.500 ;
        RECT 15.500 12.000 17.500 12.500 ;
        RECT 8.500 11.000 9.500 12.000 ;
        RECT 18.500 11.000 19.500 27.500 ;
        RECT 20.500 14.000 21.500 27.500 ;
        RECT 23.500 17.000 24.500 27.500 ;
        RECT 22.500 15.000 24.500 17.000 ;
        RECT 20.500 12.000 22.500 14.000 ;
        RECT 8.500 10.000 10.000 11.000 ;
        RECT 9.000 1.500 10.000 10.000 ;
        RECT 17.500 9.000 19.500 11.000 ;
        RECT 21.500 11.000 22.500 12.000 ;
        RECT 21.500 10.000 24.500 11.000 ;
        RECT 11.000 5.500 13.000 7.500 ;
        RECT 12.000 1.500 13.000 5.500 ;
        RECT 18.500 1.500 19.500 9.000 ;
        RECT 20.500 5.500 22.500 7.500 ;
        RECT 20.500 1.500 21.500 5.500 ;
        RECT 23.500 1.500 24.500 10.000 ;
        RECT 25.500 7.500 26.500 27.500 ;
        RECT 28.500 19.500 29.500 27.500 ;
        RECT 35.000 19.500 36.000 27.500 ;
        RECT 27.500 17.500 29.500 19.500 ;
        RECT 30.500 18.500 36.000 19.500 ;
        RECT 30.500 17.500 32.500 18.500 ;
        RECT 37.000 17.500 38.000 27.500 ;
        RECT 37.000 15.500 39.000 17.500 ;
        RECT 34.000 12.000 36.000 14.000 ;
        RECT 27.500 9.000 29.500 11.000 ;
        RECT 25.500 5.500 27.500 7.500 ;
        RECT 25.500 1.500 26.500 5.500 ;
        RECT 28.500 1.500 29.500 9.000 ;
        RECT 35.000 9.000 36.000 12.000 ;
        RECT 37.000 11.500 38.000 15.500 ;
        RECT 40.000 14.500 41.000 27.500 ;
        RECT 39.000 12.500 41.000 14.500 ;
        RECT 42.000 15.000 43.000 27.500 ;
        RECT 45.000 19.500 46.000 27.500 ;
        RECT 44.000 17.500 46.000 19.500 ;
        RECT 51.500 17.500 52.500 27.500 ;
        RECT 54.500 19.500 55.500 27.500 ;
        RECT 53.500 17.500 55.500 19.500 ;
        RECT 50.500 15.500 52.500 17.500 ;
        RECT 42.000 13.000 44.000 15.000 ;
        RECT 37.000 10.500 41.000 11.500 ;
        RECT 35.000 8.000 38.000 9.000 ;
        RECT 31.000 7.000 33.000 8.000 ;
        RECT 31.000 6.000 36.000 7.000 ;
        RECT 35.000 1.500 36.000 6.000 ;
        RECT 37.000 1.500 38.000 8.000 ;
        RECT 40.000 1.500 41.000 10.500 ;
        RECT 42.000 1.500 43.000 13.000 ;
        RECT 50.500 7.500 52.500 9.500 ;
        RECT 44.000 5.500 46.000 7.500 ;
        RECT 45.000 1.500 46.000 5.500 ;
        RECT 51.500 1.500 52.500 7.500 ;
        RECT 53.500 5.500 55.500 7.500 ;
        RECT 54.500 1.500 55.500 5.500 ;
  END
END dff1m2_r

#--------EOF---------

MACRO exnr
  CLASS CORE ;
  FOREIGN exnr ;
  ORIGIN 0.000 0.000 ;
  SIZE 21.000 BY 29.000 ;
  SYMMETRY X Y R90 ;
  SITE core ;
  PIN VSS
    DIRECTION INOUT ;
    USE GROUND ;
    SHAPE ABUTMENT ;
    PORT
      LAYER ML1 ;
        RECT 5.500 1.000 7.500 4.500 ;
        RECT 12.000 1.000 14.000 4.500 ;
        RECT -0.500 -1.000 21.500 1.000 ;
    END
  END VSS
  PIN VDD
    DIRECTION INOUT ;
    USE POWER ;
    SHAPE ABUTMENT ;
    PORT
      LAYER ML1 ;
        RECT -0.500 28.000 21.500 30.000 ;
        RECT 0.500 20.500 2.500 28.000 ;
        RECT 6.500 20.500 8.500 28.000 ;
        RECT 10.000 20.500 12.000 28.000 ;
        RECT 18.000 20.500 20.000 28.000 ;
    END
  END VDD
  PIN X
    DIRECTION OUTPUT ;
    USE SIGNAL ;
    PORT
      LAYER ML2 ;
        RECT 18.500 12.500 20.500 14.500 ;
    END
  END X
  PIN B
    DIRECTION INPUT ;
    USE SIGNAL ;
    PORT
      LAYER ML2 ;
        RECT 3.000 10.500 5.000 12.500 ;
    END
  END B
  PIN A
    DIRECTION INPUT ;
    USE SIGNAL ;
    PORT
      LAYER ML2 ;
        RECT 6.000 13.500 8.000 15.500 ;
    END
  END A
  OBS
      LAYER ML1 ;
        RECT 3.500 20.500 5.500 26.500 ;
        RECT 15.000 20.500 17.000 26.500 ;
        RECT 3.500 19.500 4.500 20.500 ;
        RECT 1.000 18.500 4.500 19.500 ;
        RECT 1.000 9.500 2.000 18.500 ;
        RECT 16.000 18.000 17.000 20.500 ;
        RECT 16.000 17.000 20.000 18.000 ;
        RECT 6.000 15.000 8.000 15.500 ;
        RECT 13.500 15.000 15.500 15.500 ;
        RECT 6.000 14.000 15.500 15.000 ;
        RECT 19.000 14.500 20.000 17.000 ;
        RECT 6.000 13.500 8.000 14.000 ;
        RECT 13.500 13.500 15.500 14.000 ;
        RECT 18.500 12.500 20.500 14.500 ;
        RECT 3.000 12.000 5.000 12.500 ;
        RECT 10.500 12.000 12.500 12.500 ;
        RECT 3.000 11.000 12.500 12.000 ;
        RECT 3.000 10.500 5.000 11.000 ;
        RECT 10.500 10.500 12.500 11.000 ;
        RECT 16.000 9.500 18.000 10.000 ;
        RECT 1.000 8.500 18.000 9.500 ;
        RECT 1.000 4.500 2.000 8.500 ;
        RECT 16.000 8.000 18.000 8.500 ;
        RECT 10.000 5.500 16.000 6.500 ;
        RECT 10.000 4.500 11.000 5.500 ;
        RECT 0.500 2.500 2.500 4.500 ;
        RECT 9.000 2.500 11.000 4.500 ;
        RECT 15.000 4.500 16.000 5.500 ;
        RECT 19.000 4.500 20.000 12.500 ;
        RECT 15.000 2.500 17.000 4.500 ;
        RECT 18.000 2.500 20.000 4.500 ;
      LAYER POL ;
        RECT 2.500 12.500 3.500 27.500 ;
        RECT 5.500 18.000 6.500 27.500 ;
        RECT 12.000 18.500 13.000 27.500 ;
        RECT 5.500 17.000 7.000 18.000 ;
        RECT 6.000 15.500 7.000 17.000 ;
        RECT 11.000 17.500 13.000 18.500 ;
        RECT 6.000 13.500 8.000 15.500 ;
        RECT 2.500 10.500 5.000 12.500 ;
        RECT 2.500 1.500 3.500 10.500 ;
        RECT 6.000 8.000 7.000 13.500 ;
        RECT 11.000 12.500 12.000 17.500 ;
        RECT 14.000 15.500 15.000 27.500 ;
        RECT 13.500 13.500 15.500 15.500 ;
        RECT 10.500 10.500 12.500 12.500 ;
        RECT 4.500 7.000 7.000 8.000 ;
        RECT 4.500 1.500 5.500 7.000 ;
        RECT 11.000 1.500 12.000 10.500 ;
        RECT 14.000 1.500 15.000 13.500 ;
        RECT 17.000 10.000 18.000 27.500 ;
        RECT 16.000 8.000 18.000 10.000 ;
        RECT 17.000 1.500 18.000 8.000 ;
  END
END exnr

#--------EOF---------

MACRO exor
  CLASS CORE ;
  FOREIGN exor ;
  ORIGIN 0.000 0.000 ;
  SIZE 21.000 BY 29.000 ;
  SYMMETRY X Y R90 ;
  SITE core ;
  PIN VSS
    DIRECTION INOUT ;
    USE GROUND ;
    SHAPE ABUTMENT ;
    PORT
      LAYER ML1 ;
        RECT 0.500 1.000 2.500 4.500 ;
        RECT 7.000 2.500 11.000 4.500 ;
        RECT 9.000 1.000 11.000 2.500 ;
        RECT 17.000 1.000 19.000 4.500 ;
        RECT -0.500 -1.000 21.500 1.000 ;
    END
  END VSS
  PIN VDD
    DIRECTION INOUT ;
    USE POWER ;
    SHAPE ABUTMENT ;
    PORT
      LAYER ML1 ;
        RECT -0.500 28.000 21.500 30.000 ;
        RECT 5.500 20.500 7.500 28.000 ;
        RECT 12.000 20.500 14.000 28.000 ;
    END
  END VDD
  PIN X
    DIRECTION OUTPUT ;
    USE SIGNAL ;
    PORT
      LAYER ML2 ;
        RECT 18.500 12.500 20.500 14.500 ;
    END
  END X
  PIN A
    DIRECTION INPUT ;
    USE SIGNAL ;
    PORT
      LAYER ML2 ;
        RECT 6.000 13.500 8.000 15.500 ;
    END
  END A
  PIN B
    DIRECTION INPUT ;
    USE SIGNAL ;
    PORT
      LAYER ML2 ;
        RECT 3.000 10.000 5.000 12.000 ;
    END
  END B
  OBS
      LAYER ML1 ;
        RECT 0.500 20.500 2.500 26.500 ;
        RECT 9.000 20.500 11.000 26.500 ;
        RECT 15.000 20.500 17.000 26.500 ;
        RECT 18.000 20.500 20.000 26.500 ;
        RECT 1.000 9.000 2.000 20.500 ;
        RECT 9.500 19.000 10.500 20.500 ;
        RECT 15.500 19.000 16.500 20.500 ;
        RECT 9.500 18.000 16.500 19.000 ;
        RECT 6.000 15.000 8.000 15.500 ;
        RECT 13.000 15.000 15.000 15.500 ;
        RECT 6.000 14.000 15.000 15.000 ;
        RECT 6.000 13.500 8.000 14.000 ;
        RECT 13.000 13.500 15.000 14.000 ;
        RECT 18.500 14.500 19.500 20.500 ;
        RECT 18.500 12.500 20.500 14.500 ;
        RECT 3.000 11.500 5.000 12.000 ;
        RECT 10.000 11.500 12.000 12.000 ;
        RECT 3.000 10.500 12.000 11.500 ;
        RECT 3.000 10.000 5.000 10.500 ;
        RECT 10.000 10.000 12.000 10.500 ;
        RECT 15.500 9.000 17.500 9.500 ;
        RECT 1.000 8.000 17.500 9.000 ;
        RECT 4.000 4.500 5.000 8.000 ;
        RECT 15.500 7.500 17.500 8.000 ;
        RECT 18.500 6.500 19.500 12.500 ;
        RECT 15.000 5.500 19.500 6.500 ;
        RECT 15.000 4.500 16.000 5.500 ;
        RECT 3.500 2.500 5.500 4.500 ;
        RECT 14.000 2.500 16.000 4.500 ;
      LAYER POL ;
        RECT 2.500 12.000 3.500 27.500 ;
        RECT 4.500 18.000 5.500 27.500 ;
        RECT 4.500 17.000 7.000 18.000 ;
        RECT 6.000 15.500 7.000 17.000 ;
        RECT 6.000 13.500 8.000 15.500 ;
        RECT 2.500 10.000 5.000 12.000 ;
        RECT 2.500 1.500 3.500 10.000 ;
        RECT 6.000 1.500 7.000 13.500 ;
        RECT 11.000 12.000 12.000 27.500 ;
        RECT 14.000 15.500 15.000 27.500 ;
        RECT 10.000 10.000 12.000 12.000 ;
        RECT 11.000 1.500 12.000 10.000 ;
        RECT 13.000 13.500 15.000 15.500 ;
        RECT 17.000 13.500 18.000 27.500 ;
        RECT 13.000 1.500 14.000 13.500 ;
        RECT 16.000 12.500 18.000 13.500 ;
        RECT 16.000 9.500 17.000 12.500 ;
        RECT 15.500 7.500 17.500 9.500 ;
        RECT 16.000 1.500 17.000 7.500 ;
  END
END exor

#--------EOF---------

MACRO FILL
  CLASS CORE ;
  FOREIGN FILL ;
  ORIGIN 0.000 0.000 ;
  SIZE 3.000 BY 29.000 ;
  SYMMETRY X Y R90 ;
  SITE core ;
  PIN VDD
    DIRECTION INOUT ;
    USE POWER ;
    SHAPE ABUTMENT ;
    PORT
      LAYER ML1 ;
        RECT -0.500 28.000 3.500 30.000 ;
    END
  END VDD
  PIN VSS
    DIRECTION INOUT ;
    USE GROUND ;
    SHAPE ABUTMENT ;
    PORT
      LAYER ML1 ;
        RECT -0.500 -1.000 3.500 1.000 ;
    END
  END VSS
END FILL

#--------EOF---------

MACRO inv1
  CLASS CORE ;
  FOREIGN inv1 ;
  ORIGIN 0.000 0.000 ;
  SIZE 6.500 BY 29.000 ;
  SYMMETRY X Y R90 ;
  SITE core ;
  PIN VSS
    DIRECTION INOUT ;
    USE GROUND ;
    SHAPE ABUTMENT ;
    PORT
      LAYER ML1 ;
        RECT 0.500 1.000 2.500 4.500 ;
        RECT -0.500 -1.000 7.000 1.000 ;
    END
  END VSS
  PIN VDD
    DIRECTION INOUT ;
    USE POWER ;
    SHAPE ABUTMENT ;
    PORT
      LAYER ML1 ;
        RECT -0.500 28.000 7.000 30.000 ;
        RECT 0.500 20.500 2.500 28.000 ;
    END
  END VDD
  PIN X
    DIRECTION OUTPUT ;
    USE SIGNAL ;
    PORT
      LAYER ML2 ;
        RECT 4.000 10.500 6.000 12.500 ;
    END
  END X
  PIN A
    DIRECTION INPUT ;
    USE SIGNAL ;
    PORT
      LAYER ML2 ;
        RECT 1.000 14.500 3.000 16.500 ;
    END
  END A
  OBS
      LAYER ML1 ;
        RECT 3.500 20.500 5.500 26.500 ;
        RECT 1.000 14.500 3.000 16.500 ;
        RECT 4.000 12.500 5.000 20.500 ;
        RECT 4.000 10.500 6.000 12.500 ;
        RECT 4.000 4.500 5.000 10.500 ;
        RECT 3.500 2.500 5.500 4.500 ;
      LAYER POL ;
        RECT 2.500 16.500 3.500 27.500 ;
        RECT 1.000 14.500 3.500 16.500 ;
        RECT 2.500 1.500 3.500 14.500 ;
  END
END inv1

#--------EOF---------

MACRO inv4
  CLASS CORE ;
  FOREIGN inv4 ;
  ORIGIN 0.000 0.000 ;
  SIZE 15.500 BY 29.000 ;
  SYMMETRY X Y R90 ;
  SITE core ;
  PIN VDD
    DIRECTION INOUT ;
    USE POWER ;
    SHAPE ABUTMENT ;
    PORT
      LAYER ML1 ;
        RECT -0.500 28.000 16.000 30.000 ;
        RECT 0.500 20.300 2.500 28.000 ;
        RECT 6.500 20.300 8.500 28.000 ;
        RECT 12.500 20.500 14.500 28.000 ;
    END
  END VDD
  PIN VSS
    DIRECTION INOUT ;
    USE GROUND ;
    SHAPE ABUTMENT ;
    PORT
      LAYER ML1 ;
        RECT 0.500 1.000 2.500 4.500 ;
        RECT 6.500 1.000 8.500 4.500 ;
        RECT 12.500 1.000 14.500 4.500 ;
        RECT -0.500 -1.000 16.000 1.000 ;
    END
  END VSS
  PIN A
    DIRECTION INPUT ;
    USE SIGNAL ;
    PORT
      LAYER ML2 ;
        RECT 1.000 14.500 3.000 16.500 ;
    END
  END A
  PIN X
    DIRECTION OUTPUT ;
    USE SIGNAL ;
    PORT
      LAYER ML2 ;
        RECT 10.000 10.000 12.000 12.000 ;
    END
  END X
  OBS
      LAYER ML1 ;
        RECT 3.500 20.500 5.500 26.500 ;
        RECT 9.500 20.500 11.500 26.500 ;
        RECT 1.000 14.500 3.000 16.500 ;
        RECT 4.000 11.500 5.000 20.500 ;
        RECT 10.000 12.000 11.000 20.500 ;
        RECT 10.000 11.500 12.000 12.000 ;
        RECT 4.000 10.500 12.000 11.500 ;
        RECT 4.000 4.500 5.000 10.500 ;
        RECT 10.000 10.000 12.000 10.500 ;
        RECT 10.000 4.500 11.000 10.000 ;
        RECT 3.500 2.500 5.500 4.500 ;
        RECT 9.500 2.500 11.500 4.500 ;
      LAYER POL ;
        RECT 2.500 16.500 3.500 27.500 ;
        RECT 5.500 16.500 6.500 27.500 ;
        RECT 8.500 16.500 9.500 27.500 ;
        RECT 11.500 16.500 12.500 27.500 ;
        RECT 1.000 14.500 12.500 16.500 ;
        RECT 2.500 1.500 3.500 14.500 ;
        RECT 5.500 1.500 6.500 14.500 ;
        RECT 8.500 1.500 9.500 14.500 ;
        RECT 11.500 1.500 12.500 14.500 ;
  END
END inv4

#--------EOF---------

MACRO inv8
  CLASS CORE ;
  FOREIGN inv8 ;
  ORIGIN 0.000 0.000 ;
  SIZE 27.500 BY 29.000 ;
  SYMMETRY X Y R90 ;
  SITE core ;
  PIN VSS
    DIRECTION INOUT ;
    USE GROUND ;
    SHAPE ABUTMENT ;
    PORT
      LAYER ML1 ;
        RECT 0.500 1.000 2.500 4.800 ;
        RECT 6.500 1.000 8.500 4.800 ;
        RECT 12.500 1.000 14.500 4.800 ;
        RECT 18.500 1.000 20.500 4.800 ;
        RECT 24.500 1.000 26.500 4.800 ;
        RECT -0.500 -1.000 28.000 1.000 ;
    END
  END VSS
  PIN VDD
    DIRECTION INOUT ;
    USE POWER ;
    SHAPE ABUTMENT ;
    PORT
      LAYER ML1 ;
        RECT -0.500 28.000 28.000 30.000 ;
        RECT 0.500 20.500 2.500 28.000 ;
        RECT 6.500 20.300 8.500 28.000 ;
        RECT 12.500 20.300 14.500 28.000 ;
        RECT 18.500 20.300 20.500 28.000 ;
        RECT 24.500 20.500 26.500 28.000 ;
    END
  END VDD
  PIN X
    DIRECTION OUTPUT ;
    USE SIGNAL ;
    PORT
      LAYER ML2 ;
        RECT 22.000 10.500 24.000 12.500 ;
    END
  END X
  PIN A
    DIRECTION INPUT ;
    USE SIGNAL ;
    PORT
      LAYER ML2 ;
        RECT 1.000 14.500 3.000 16.500 ;
    END
  END A
  OBS
      LAYER ML1 ;
        RECT 3.500 20.500 5.500 26.500 ;
        RECT 9.500 20.500 11.500 26.500 ;
        RECT 15.500 20.500 17.500 26.500 ;
        RECT 21.500 20.500 23.500 26.500 ;
        RECT 1.000 14.500 3.000 16.500 ;
        RECT 4.000 11.500 5.000 20.500 ;
        RECT 10.000 11.500 11.000 20.500 ;
        RECT 16.000 11.500 17.000 20.500 ;
        RECT 22.000 12.500 23.000 20.500 ;
        RECT 22.000 11.500 24.000 12.500 ;
        RECT 4.000 10.500 24.000 11.500 ;
        RECT 4.000 4.500 5.000 10.500 ;
        RECT 10.000 4.500 11.000 10.500 ;
        RECT 16.000 4.500 17.000 10.500 ;
        RECT 22.000 4.500 23.000 10.500 ;
        RECT 3.500 2.500 5.500 4.500 ;
        RECT 9.500 2.500 11.500 4.500 ;
        RECT 15.500 2.500 17.500 4.500 ;
        RECT 21.500 2.500 23.500 4.500 ;
      LAYER POL ;
        RECT 2.500 16.500 3.500 27.500 ;
        RECT 5.500 16.500 6.500 27.500 ;
        RECT 8.500 16.500 9.500 27.500 ;
        RECT 11.500 16.500 12.500 27.500 ;
        RECT 14.500 16.500 15.500 27.500 ;
        RECT 17.500 16.500 18.500 27.500 ;
        RECT 20.500 16.500 21.500 27.500 ;
        RECT 23.500 16.500 24.500 27.500 ;
        RECT 1.000 14.500 24.500 16.500 ;
        RECT 2.500 1.500 3.500 14.500 ;
        RECT 5.500 1.500 6.500 14.500 ;
        RECT 8.500 1.500 9.500 14.500 ;
        RECT 11.500 1.500 12.500 14.500 ;
        RECT 14.500 1.500 15.500 14.500 ;
        RECT 17.500 1.500 18.500 14.500 ;
        RECT 20.500 1.500 21.500 14.500 ;
        RECT 23.500 1.500 24.500 14.500 ;
  END
END inv8

#--------EOF---------

MACRO na21
  CLASS CORE ;
  FOREIGN na21 ;
  ORIGIN 0.000 0.000 ;
  SIZE 9.500 BY 29.000 ;
  SYMMETRY X Y R90 ;
  SITE core ;
  PIN VSS
    DIRECTION INOUT ;
    USE GROUND ;
    SHAPE ABUTMENT ;
    PORT
      LAYER ML1 ;
        RECT 0.500 1.000 2.500 4.500 ;
        RECT -0.500 -1.000 10.000 1.000 ;
    END
  END VSS
  PIN VDD
    DIRECTION INOUT ;
    USE POWER ;
    SHAPE ABUTMENT ;
    PORT
      LAYER ML1 ;
        RECT -0.500 28.000 10.000 30.000 ;
        RECT 0.500 20.500 2.500 28.000 ;
        RECT 6.500 20.500 8.500 28.000 ;
    END
  END VDD
  PIN A
    DIRECTION INPUT ;
    USE SIGNAL ;
    PORT
      LAYER ML2 ;
        RECT 1.000 14.500 3.000 16.500 ;
    END
  END A
  PIN B
    DIRECTION INPUT ;
    USE SIGNAL ;
    PORT
      LAYER ML2 ;
        RECT 4.000 8.500 6.000 10.500 ;
    END
  END B
  PIN X
    DIRECTION OUTPUT ;
    USE SIGNAL ;
    PORT
      LAYER ML2 ;
        RECT 7.000 13.000 9.000 15.000 ;
    END
  END X
  OBS
      LAYER ML1 ;
        RECT 3.500 20.500 5.500 26.500 ;
        RECT 4.500 18.500 5.500 20.500 ;
        RECT 4.500 17.500 8.000 18.500 ;
        RECT 1.000 14.500 3.000 16.500 ;
        RECT 7.000 15.000 8.000 17.500 ;
        RECT 7.000 13.000 9.000 15.000 ;
        RECT 4.000 8.500 6.000 10.500 ;
        RECT 7.000 7.000 8.000 13.000 ;
        RECT 6.000 6.000 8.000 7.000 ;
        RECT 6.000 4.500 7.000 6.000 ;
        RECT 5.500 2.500 7.500 4.500 ;
      LAYER POL ;
        RECT 2.500 16.500 3.500 27.500 ;
        RECT 1.000 15.000 3.500 16.500 ;
        RECT 5.500 16.000 6.500 27.500 ;
        RECT 5.000 15.000 6.500 16.000 ;
        RECT 1.000 14.500 3.000 15.000 ;
        RECT 2.000 7.000 3.000 14.500 ;
        RECT 5.000 10.500 6.000 15.000 ;
        RECT 4.000 8.500 6.000 10.500 ;
        RECT 2.000 6.000 3.500 7.000 ;
        RECT 2.500 1.500 3.500 6.000 ;
        RECT 4.500 1.500 5.500 8.500 ;
  END
END na21

#--------EOF---------

MACRO na31
  CLASS CORE ;
  FOREIGN na31 ;
  ORIGIN 0.000 0.000 ;
  SIZE 12.500 BY 29.000 ;
  SYMMETRY X Y R90 ;
  SITE core ;
  PIN VDD
    DIRECTION INOUT ;
    USE POWER ;
    SHAPE ABUTMENT ;
    PORT
      LAYER ML1 ;
        RECT -0.500 28.000 13.000 30.000 ;
        RECT 0.500 20.500 2.500 28.000 ;
        RECT 6.500 20.500 8.500 28.000 ;
    END
  END VDD
  PIN VSS
    DIRECTION INOUT ;
    USE GROUND ;
    SHAPE ABUTMENT ;
    PORT
      LAYER ML1 ;
        RECT 0.500 2.500 2.500 4.500 ;
        RECT 1.000 1.000 2.000 2.500 ;
        RECT -0.500 -1.000 13.000 1.000 ;
    END
  END VSS
  PIN X
    DIRECTION OUTPUT ;
    USE SIGNAL ;
    PORT
      LAYER ML2 ;
        RECT 10.000 12.000 12.000 14.000 ;
    END
  END X
  PIN C
    DIRECTION INPUT ;
    USE SIGNAL ;
    PORT
      LAYER ML2 ;
        RECT 7.000 8.000 9.000 10.000 ;
    END
  END C
  PIN B
    DIRECTION INPUT ;
    USE SIGNAL ;
    PORT
      LAYER ML2 ;
        RECT 4.000 11.500 6.000 13.500 ;
    END
  END B
  PIN A
    DIRECTION INPUT ;
    USE SIGNAL ;
    PORT
      LAYER ML2 ;
        RECT 1.000 14.500 3.000 16.500 ;
    END
  END A
  OBS
      LAYER ML1 ;
        RECT 3.500 20.500 5.500 26.500 ;
        RECT 9.500 20.500 11.500 26.500 ;
        RECT 4.000 18.500 5.000 20.500 ;
        RECT 10.000 18.500 11.000 20.500 ;
        RECT 4.000 17.500 11.000 18.500 ;
        RECT 1.000 14.500 3.000 16.500 ;
        RECT 10.000 14.000 11.000 17.500 ;
        RECT 4.000 11.500 6.000 13.500 ;
        RECT 10.000 12.000 12.000 14.000 ;
        RECT 7.000 8.000 9.000 10.000 ;
        RECT 10.000 7.000 11.000 12.000 ;
        RECT 8.500 6.000 11.000 7.000 ;
        RECT 8.500 4.500 9.500 6.000 ;
        RECT 7.500 2.500 9.500 4.500 ;
      LAYER POL ;
        RECT 2.500 16.500 3.500 27.500 ;
        RECT 1.000 15.000 3.500 16.500 ;
        RECT 5.500 16.000 6.500 27.500 ;
        RECT 5.000 15.000 6.500 16.000 ;
        RECT 1.000 14.500 3.000 15.000 ;
        RECT 2.000 7.000 3.000 14.500 ;
        RECT 5.000 13.500 6.000 15.000 ;
        RECT 4.000 11.500 6.000 13.500 ;
        RECT 2.000 6.000 3.500 7.000 ;
        RECT 2.500 1.500 3.500 6.000 ;
        RECT 4.500 1.500 5.500 11.500 ;
        RECT 8.500 10.000 9.500 27.500 ;
        RECT 7.000 9.000 9.500 10.000 ;
        RECT 6.500 8.000 9.500 9.000 ;
        RECT 6.500 1.500 7.500 8.000 ;
  END
END na31

#--------EOF---------

MACRO na41
  CLASS CORE ;
  FOREIGN na41 ;
  ORIGIN 0.000 0.000 ;
  SIZE 15.500 BY 29.000 ;
  SYMMETRY X Y R90 ;
  SITE core ;
  PIN VDD
    DIRECTION INOUT ;
    USE POWER ;
    SHAPE ABUTMENT ;
    PORT
      LAYER ML1 ;
        RECT -0.500 28.000 16.000 30.000 ;
        RECT 0.500 20.500 2.500 28.000 ;
        RECT 6.500 20.500 8.500 28.000 ;
        RECT 12.500 20.500 14.500 28.000 ;
    END
  END VDD
  PIN VSS
    DIRECTION INOUT ;
    USE GROUND ;
    SHAPE ABUTMENT ;
    PORT
      LAYER ML1 ;
        RECT 0.500 1.000 2.500 4.500 ;
        RECT -0.500 -1.000 16.000 1.000 ;
    END
  END VSS
  PIN A
    DIRECTION INPUT ;
    USE SIGNAL ;
    PORT
      LAYER ML2 ;
        RECT 1.000 15.500 3.000 17.500 ;
    END
  END A
  PIN B
    DIRECTION INPUT ;
    USE SIGNAL ;
    PORT
      LAYER ML2 ;
        RECT 4.000 12.500 6.000 14.500 ;
    END
  END B
  PIN C
    DIRECTION INPUT ;
    USE SIGNAL ;
    PORT
      LAYER ML2 ;
        RECT 7.000 9.500 9.000 11.500 ;
    END
  END C
  PIN D
    DIRECTION INPUT ;
    USE SIGNAL ;
    PORT
      LAYER ML2 ;
        RECT 10.000 6.500 12.000 8.500 ;
    END
  END D
  PIN X
    DIRECTION OUTPUT ;
    USE SIGNAL ;
    PORT
      LAYER ML2 ;
        RECT 13.000 9.500 15.000 11.500 ;
    END
  END X
  OBS
      LAYER ML1 ;
        RECT 3.500 20.500 5.500 26.500 ;
        RECT 9.500 20.500 11.500 26.500 ;
        RECT 4.000 18.500 5.000 20.500 ;
        RECT 10.000 18.500 11.000 20.500 ;
        RECT 4.000 17.500 14.000 18.500 ;
        RECT 1.000 15.500 3.000 17.500 ;
        RECT 4.000 12.500 6.000 14.500 ;
        RECT 13.000 11.500 14.000 17.500 ;
        RECT 7.000 9.500 9.000 11.500 ;
        RECT 13.000 9.500 15.000 11.500 ;
        RECT 10.000 6.500 12.000 8.500 ;
        RECT 13.000 4.500 14.000 9.500 ;
        RECT 9.500 3.500 14.000 4.500 ;
        RECT 9.500 2.500 11.500 3.500 ;
      LAYER POL ;
        RECT 2.500 17.500 3.500 27.500 ;
        RECT 1.000 15.500 3.500 17.500 ;
        RECT 2.000 7.500 3.000 15.500 ;
        RECT 5.500 14.500 6.500 27.500 ;
        RECT 4.000 13.500 6.500 14.500 ;
        RECT 4.000 12.500 6.000 13.500 ;
        RECT 2.000 6.500 3.500 7.500 ;
        RECT 2.500 1.500 3.500 6.500 ;
        RECT 4.500 1.500 5.500 12.500 ;
        RECT 8.500 11.500 9.500 27.500 ;
        RECT 7.000 11.000 9.500 11.500 ;
        RECT 6.500 10.000 9.500 11.000 ;
        RECT 6.500 9.500 9.000 10.000 ;
        RECT 6.500 1.500 7.500 9.500 ;
        RECT 11.500 8.500 12.500 27.500 ;
        RECT 10.000 7.500 12.500 8.500 ;
        RECT 8.500 6.500 12.500 7.500 ;
        RECT 8.500 1.500 9.500 6.500 ;
  END
END na41

#--------EOF---------

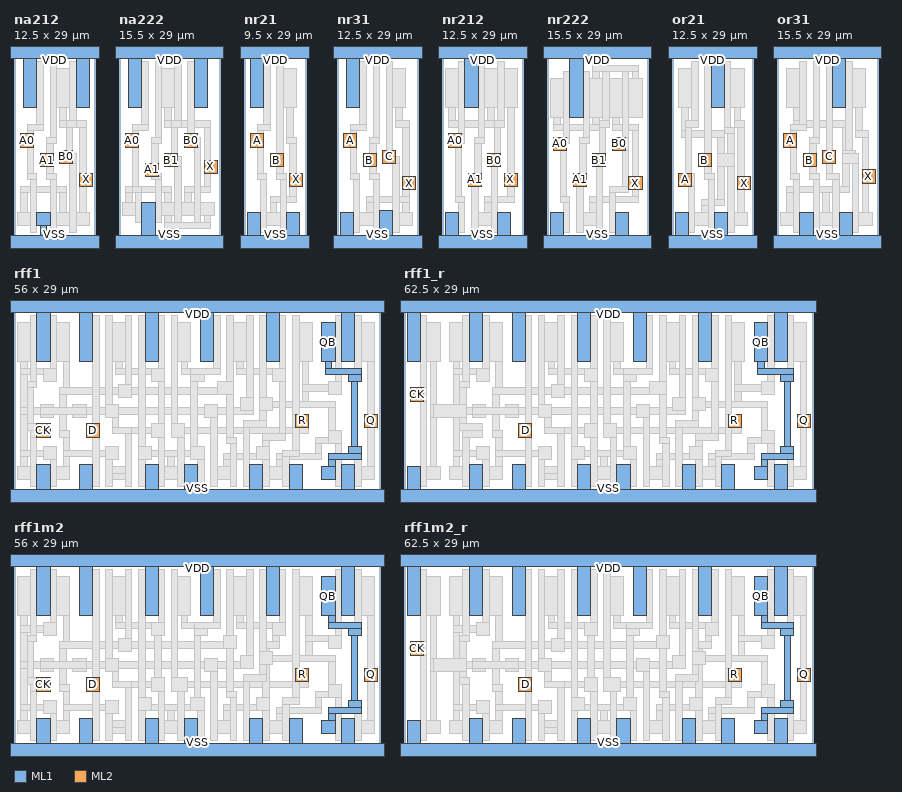
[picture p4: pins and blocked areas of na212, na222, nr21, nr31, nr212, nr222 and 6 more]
MACRO na212
  CLASS CORE ;
  FOREIGN na212 ;
  ORIGIN 0.000 0.000 ;
  SIZE 12.500 BY 29.000 ;
  SYMMETRY X Y R90 ;
  SITE core ;
  PIN VDD
    DIRECTION INOUT ;
    USE POWER ;
    SHAPE ABUTMENT ;
    PORT
      LAYER ML1 ;
        RECT -0.500 28.000 13.000 30.000 ;
        RECT 1.500 20.500 3.500 28.000 ;
        RECT 9.500 20.500 11.500 28.000 ;
    END
  END VDD
  PIN VSS
    DIRECTION INOUT ;
    USE GROUND ;
    SHAPE ABUTMENT ;
    PORT
      LAYER ML1 ;
        RECT 3.500 2.500 5.500 4.500 ;
        RECT 4.000 1.000 5.000 2.500 ;
        RECT -0.500 -1.000 13.000 1.000 ;
    END
  END VSS
  PIN A1
    DIRECTION INPUT ;
    USE SIGNAL ;
    PORT
      LAYER ML2 ;
        RECT 4.000 11.500 6.000 13.500 ;
    END
  END A1
  PIN A0
    DIRECTION INPUT ;
    USE SIGNAL ;
    PORT
      LAYER ML2 ;
        RECT 1.000 14.500 3.000 16.500 ;
    END
  END A0
  PIN B0
    DIRECTION INPUT ;
    USE SIGNAL ;
    PORT
      LAYER ML2 ;
        RECT 7.000 12.000 9.000 14.000 ;
    END
  END B0
  PIN X
    DIRECTION OUTPUT ;
    USE SIGNAL ;
    PORT
      LAYER ML2 ;
        RECT 10.000 8.500 12.000 10.500 ;
    END
  END X
  OBS
      LAYER ML1 ;
        RECT 6.500 20.500 8.500 26.500 ;
        RECT 7.000 18.500 8.000 20.500 ;
        RECT 7.000 17.500 11.000 18.500 ;
        RECT 1.000 14.500 3.000 16.500 ;
        RECT 4.000 11.500 6.000 13.500 ;
        RECT 7.000 12.000 9.000 14.000 ;
        RECT 10.000 10.500 11.000 17.500 ;
        RECT 10.000 8.500 12.000 10.500 ;
        RECT 1.000 7.500 8.000 8.500 ;
        RECT 1.000 4.500 2.000 7.500 ;
        RECT 7.000 4.500 8.000 7.500 ;
        RECT 10.000 4.500 11.000 8.500 ;
        RECT 0.500 2.500 2.500 4.500 ;
        RECT 6.500 2.500 8.500 4.500 ;
        RECT 9.500 2.500 11.500 4.500 ;
      LAYER POL ;
        RECT 3.500 18.000 4.500 27.500 ;
        RECT 2.000 17.000 4.500 18.000 ;
        RECT 2.000 16.500 3.000 17.000 ;
        RECT 1.000 14.500 3.000 16.500 ;
        RECT 5.500 16.000 6.500 27.500 ;
        RECT 8.500 18.500 9.500 27.500 ;
        RECT 2.000 10.500 3.000 14.500 ;
        RECT 5.000 15.000 6.500 16.000 ;
        RECT 8.000 17.500 9.500 18.500 ;
        RECT 5.000 13.500 6.000 15.000 ;
        RECT 8.000 14.000 9.000 17.500 ;
        RECT 4.000 11.500 6.000 13.500 ;
        RECT 7.000 13.500 9.000 14.000 ;
        RECT 7.000 12.000 9.500 13.500 ;
        RECT 5.000 10.500 6.000 11.500 ;
        RECT 2.000 9.500 3.500 10.500 ;
        RECT 5.000 9.500 6.500 10.500 ;
        RECT 2.500 1.500 3.500 9.500 ;
        RECT 5.500 1.500 6.500 9.500 ;
        RECT 8.500 1.500 9.500 12.000 ;
  END
END na212

#--------EOF---------

MACRO na222
  CLASS CORE ;
  FOREIGN na222 ;
  ORIGIN 0.000 0.000 ;
  SIZE 15.500 BY 29.000 ;
  SYMMETRY X Y R90 ;
  SITE core ;
  PIN VDD
    DIRECTION INOUT ;
    USE POWER ;
    SHAPE ABUTMENT ;
    PORT
      LAYER ML1 ;
        RECT -0.500 28.000 16.000 30.000 ;
        RECT 1.500 20.500 3.500 28.000 ;
        RECT 11.500 20.500 13.500 28.000 ;
    END
  END VDD
  PIN VSS
    DIRECTION INOUT ;
    USE GROUND ;
    SHAPE ABUTMENT ;
    PORT
      LAYER ML1 ;
        RECT 3.500 1.000 5.500 6.000 ;
        RECT -0.500 -1.000 16.000 1.000 ;
    END
  END VSS
  PIN B0
    DIRECTION INPUT ;
    USE SIGNAL ;
    PORT
      LAYER ML2 ;
        RECT 10.000 14.500 12.000 16.500 ;
    END
  END B0
  PIN X
    DIRECTION OUTPUT ;
    USE SIGNAL ;
    PORT
      LAYER ML2 ;
        RECT 13.000 10.500 15.000 12.500 ;
    END
  END X
  PIN A0
    DIRECTION INPUT ;
    USE SIGNAL ;
    PORT
      LAYER ML2 ;
        RECT 1.000 14.500 3.000 16.500 ;
    END
  END A0
  PIN A1
    DIRECTION INPUT ;
    USE SIGNAL ;
    PORT
      LAYER ML2 ;
        RECT 4.000 10.000 6.000 12.000 ;
    END
  END A1
  PIN B1
    DIRECTION INPUT ;
    USE SIGNAL ;
    PORT
      LAYER ML2 ;
        RECT 7.000 11.500 9.000 13.500 ;
    END
  END B1
  OBS
      LAYER ML1 ;
        RECT 6.500 20.500 8.500 26.500 ;
        RECT 7.000 18.500 8.000 20.500 ;
        RECT 7.000 17.500 14.000 18.500 ;
        RECT 1.000 14.500 3.000 16.500 ;
        RECT 10.000 14.500 12.000 16.500 ;
        RECT 4.000 10.000 6.000 12.000 ;
        RECT 7.000 11.500 9.000 13.500 ;
        RECT 13.000 12.500 14.000 17.500 ;
        RECT 13.000 10.500 15.000 12.500 ;
        RECT 13.000 8.500 14.000 10.500 ;
        RECT 1.000 7.500 8.000 8.500 ;
        RECT 1.000 6.000 2.000 7.500 ;
        RECT 7.000 6.000 8.000 7.500 ;
        RECT 10.000 7.500 14.000 8.500 ;
        RECT 10.000 6.000 11.000 7.500 ;
        RECT 0.500 4.000 2.500 6.000 ;
        RECT 6.500 4.000 8.500 6.000 ;
        RECT 9.500 4.000 11.500 6.000 ;
        RECT 12.500 4.000 14.500 6.000 ;
        RECT 7.000 3.000 8.000 4.000 ;
        RECT 13.000 3.000 14.000 4.000 ;
        RECT 7.000 2.000 14.000 3.000 ;
      LAYER POL ;
        RECT 3.500 18.000 4.500 27.500 ;
        RECT 2.000 17.000 4.500 18.000 ;
        RECT 2.000 16.500 3.000 17.000 ;
        RECT 1.000 14.500 3.000 16.500 ;
        RECT 5.500 16.000 6.500 27.500 ;
        RECT 8.500 18.500 9.500 27.500 ;
        RECT 2.000 8.500 3.000 14.500 ;
        RECT 5.000 15.000 6.500 16.000 ;
        RECT 8.000 17.500 9.500 18.500 ;
        RECT 5.000 12.000 6.000 15.000 ;
        RECT 8.000 13.500 9.000 17.500 ;
        RECT 10.500 16.500 11.500 27.500 ;
        RECT 10.000 16.000 12.000 16.500 ;
        RECT 10.000 14.500 12.500 16.000 ;
        RECT 4.000 10.500 6.000 12.000 ;
        RECT 7.000 13.000 9.000 13.500 ;
        RECT 7.000 11.500 9.500 13.000 ;
        RECT 4.000 10.000 6.500 10.500 ;
        RECT 5.000 9.500 6.500 10.000 ;
        RECT 2.000 7.500 3.500 8.500 ;
        RECT 2.500 3.000 3.500 7.500 ;
        RECT 5.500 3.000 6.500 9.500 ;
        RECT 8.500 3.000 9.500 11.500 ;
        RECT 11.500 3.000 12.500 14.500 ;
  END
END na222

#--------EOF---------

MACRO nr21
  CLASS CORE ;
  FOREIGN nr21 ;
  ORIGIN 0.000 0.000 ;
  SIZE 9.500 BY 29.000 ;
  SYMMETRY X Y R90 ;
  SITE core ;
  PIN VSS
    DIRECTION INOUT ;
    USE GROUND ;
    SHAPE ABUTMENT ;
    PORT
      LAYER ML1 ;
        RECT 0.500 1.000 2.500 4.500 ;
        RECT 6.500 1.000 8.500 4.500 ;
        RECT -0.500 -1.000 10.000 1.000 ;
    END
  END VSS
  PIN VDD
    DIRECTION INOUT ;
    USE POWER ;
    SHAPE ABUTMENT ;
    PORT
      LAYER ML1 ;
        RECT -0.500 28.000 10.000 30.000 ;
        RECT 1.000 20.500 3.000 28.000 ;
    END
  END VDD
  PIN A
    DIRECTION INPUT ;
    USE SIGNAL ;
    PORT
      LAYER ML2 ;
        RECT 1.000 14.500 3.000 16.500 ;
    END
  END A
  PIN B
    DIRECTION INPUT ;
    USE SIGNAL ;
    PORT
      LAYER ML2 ;
        RECT 4.000 11.500 6.000 13.500 ;
    END
  END B
  PIN X
    DIRECTION OUTPUT ;
    USE SIGNAL ;
    PORT
      LAYER ML2 ;
        RECT 7.000 8.500 9.000 10.500 ;
    END
  END X
  OBS
      LAYER ML1 ;
        RECT 6.000 20.500 8.000 26.500 ;
        RECT 1.000 14.500 3.000 16.500 ;
        RECT 6.500 16.000 7.500 20.500 ;
        RECT 6.500 15.000 8.000 16.000 ;
        RECT 4.000 11.500 6.000 13.500 ;
        RECT 7.000 10.500 8.000 15.000 ;
        RECT 7.000 8.500 9.000 10.500 ;
        RECT 7.000 7.000 8.000 8.500 ;
        RECT 4.000 6.000 8.000 7.000 ;
        RECT 4.000 4.500 5.000 6.000 ;
        RECT 3.500 2.500 5.500 4.500 ;
      LAYER POL ;
        RECT 3.000 18.000 4.000 27.500 ;
        RECT 2.000 17.000 4.000 18.000 ;
        RECT 2.000 16.500 3.000 17.000 ;
        RECT 1.000 14.500 3.000 16.500 ;
        RECT 2.000 10.500 3.000 14.500 ;
        RECT 5.000 13.500 6.000 27.500 ;
        RECT 4.000 11.500 6.000 13.500 ;
        RECT 5.000 10.500 6.000 11.500 ;
        RECT 2.000 9.500 3.500 10.500 ;
        RECT 5.000 9.500 6.500 10.500 ;
        RECT 2.500 1.500 3.500 9.500 ;
        RECT 5.500 1.500 6.500 9.500 ;
  END
END nr21

#--------EOF---------

MACRO nr31
  CLASS CORE ;
  FOREIGN nr31 ;
  ORIGIN 0.000 0.000 ;
  SIZE 12.500 BY 29.000 ;
  SYMMETRY X Y R90 ;
  SITE core ;
  PIN VDD
    DIRECTION INOUT ;
    USE POWER ;
    SHAPE ABUTMENT ;
    PORT
      LAYER ML1 ;
        RECT -0.500 28.000 13.000 30.000 ;
        RECT 1.500 20.500 3.500 28.000 ;
    END
  END VDD
  PIN VSS
    DIRECTION INOUT ;
    USE GROUND ;
    SHAPE ABUTMENT ;
    PORT
      LAYER ML1 ;
        RECT 0.500 1.000 2.500 4.500 ;
        RECT 6.500 1.000 8.500 4.800 ;
        RECT -0.500 -1.000 13.000 1.000 ;
    END
  END VSS
  PIN X
    DIRECTION OUTPUT ;
    USE SIGNAL ;
    PORT
      LAYER ML2 ;
        RECT 10.000 8.000 12.000 10.000 ;
    END
  END X
  PIN C
    DIRECTION INPUT ;
    USE SIGNAL ;
    PORT
      LAYER ML2 ;
        RECT 7.000 12.000 9.000 14.000 ;
    END
  END C
  PIN B
    DIRECTION INPUT ;
    USE SIGNAL ;
    PORT
      LAYER ML2 ;
        RECT 4.000 11.500 6.000 13.500 ;
    END
  END B
  PIN A
    DIRECTION INPUT ;
    USE SIGNAL ;
    PORT
      LAYER ML2 ;
        RECT 1.000 14.500 3.000 16.500 ;
    END
  END A
  OBS
      LAYER ML1 ;
        RECT 8.500 20.500 10.500 26.500 ;
        RECT 9.000 18.500 10.000 20.500 ;
        RECT 9.000 17.500 11.000 18.500 ;
        RECT 1.000 14.500 3.000 16.500 ;
        RECT 4.000 11.500 6.000 13.500 ;
        RECT 7.000 12.000 9.000 14.000 ;
        RECT 10.000 10.000 11.000 17.500 ;
        RECT 10.000 8.000 12.000 10.000 ;
        RECT 10.000 7.000 11.000 8.000 ;
        RECT 4.500 6.000 11.000 7.000 ;
        RECT 4.500 4.500 5.500 6.000 ;
        RECT 10.000 4.500 11.000 6.000 ;
        RECT 3.500 2.500 5.500 4.500 ;
        RECT 9.500 2.500 11.500 4.500 ;
      LAYER POL ;
        RECT 3.500 18.000 4.500 27.500 ;
        RECT 2.000 17.000 4.500 18.000 ;
        RECT 2.000 16.500 3.000 17.000 ;
        RECT 1.000 14.500 3.000 16.500 ;
        RECT 5.500 16.000 6.500 27.500 ;
        RECT 2.000 10.500 3.000 14.500 ;
        RECT 5.000 15.000 6.500 16.000 ;
        RECT 5.000 13.500 6.000 15.000 ;
        RECT 7.500 14.000 8.500 27.500 ;
        RECT 4.000 11.500 6.000 13.500 ;
        RECT 7.000 13.000 9.000 14.000 ;
        RECT 7.000 12.000 9.500 13.000 ;
        RECT 5.000 10.500 6.000 11.500 ;
        RECT 2.000 9.500 3.500 10.500 ;
        RECT 5.000 9.500 6.500 10.500 ;
        RECT 2.500 1.500 3.500 9.500 ;
        RECT 5.500 1.500 6.500 9.500 ;
        RECT 8.500 1.500 9.500 12.000 ;
  END
END nr31

#--------EOF---------

MACRO nr212
  CLASS CORE ;
  FOREIGN nr212 ;
  ORIGIN 0.000 0.000 ;
  SIZE 12.500 BY 29.000 ;
  SYMMETRY X Y R90 ;
  SITE core ;
  PIN VDD
    DIRECTION INOUT ;
    USE POWER ;
    SHAPE ABUTMENT ;
    PORT
      LAYER ML1 ;
        RECT -0.500 28.000 13.000 30.000 ;
        RECT 3.500 20.500 5.500 28.000 ;
    END
  END VDD
  PIN VSS
    DIRECTION INOUT ;
    USE GROUND ;
    SHAPE ABUTMENT ;
    PORT
      LAYER ML1 ;
        RECT 0.500 1.000 2.500 4.500 ;
        RECT 8.500 1.000 10.500 4.500 ;
        RECT -0.500 -1.000 13.000 1.000 ;
    END
  END VSS
  PIN B0
    DIRECTION INPUT ;
    USE SIGNAL ;
    PORT
      LAYER ML2 ;
        RECT 7.000 11.500 9.000 13.500 ;
    END
  END B0
  PIN A1
    DIRECTION INPUT ;
    USE SIGNAL ;
    PORT
      LAYER ML2 ;
        RECT 4.000 8.500 6.000 10.500 ;
    END
  END A1
  PIN A0
    DIRECTION INPUT ;
    USE SIGNAL ;
    PORT
      LAYER ML2 ;
        RECT 1.000 14.500 3.000 16.500 ;
    END
  END A0
  PIN X
    DIRECTION OUTPUT ;
    USE SIGNAL ;
    PORT
      LAYER ML2 ;
        RECT 9.500 8.500 11.500 10.500 ;
    END
  END X
  OBS
      LAYER ML1 ;
        RECT 0.500 20.500 2.500 26.500 ;
        RECT 6.500 20.500 8.500 26.500 ;
        RECT 9.500 20.500 11.500 26.500 ;
        RECT 1.000 18.500 2.000 20.500 ;
        RECT 7.000 18.500 8.000 20.500 ;
        RECT 1.000 17.500 8.000 18.500 ;
        RECT 1.000 14.500 3.000 16.500 ;
        RECT 7.000 11.500 9.000 13.500 ;
        RECT 10.000 10.500 11.000 20.500 ;
        RECT 4.000 8.500 6.000 10.500 ;
        RECT 9.500 8.500 11.500 10.500 ;
        RECT 10.000 7.000 11.000 8.500 ;
        RECT 6.500 6.000 11.000 7.000 ;
        RECT 6.500 4.500 7.500 6.000 ;
        RECT 5.500 2.500 7.500 4.500 ;
      LAYER POL ;
        RECT 2.500 16.500 3.500 27.500 ;
        RECT 1.000 15.000 3.500 16.500 ;
        RECT 5.500 16.000 6.500 27.500 ;
        RECT 8.500 18.500 9.500 27.500 ;
        RECT 5.000 15.000 6.500 16.000 ;
        RECT 8.000 17.500 9.500 18.500 ;
        RECT 1.000 14.500 3.000 15.000 ;
        RECT 2.000 7.000 3.000 14.500 ;
        RECT 5.000 10.500 6.000 15.000 ;
        RECT 8.000 13.500 9.000 17.500 ;
        RECT 7.000 11.500 9.000 13.500 ;
        RECT 4.000 8.500 6.000 10.500 ;
        RECT 2.000 6.000 3.500 7.000 ;
        RECT 2.500 1.500 3.500 6.000 ;
        RECT 4.500 1.500 5.500 8.500 ;
        RECT 7.500 1.500 8.500 11.500 ;
  END
END nr212

#--------EOF---------

MACRO nr222
  CLASS CORE ;
  FOREIGN nr222 ;
  ORIGIN 0.000 0.000 ;
  SIZE 15.500 BY 29.000 ;
  SYMMETRY X Y R90 ;
  SITE core ;
  PIN VDD
    DIRECTION INOUT ;
    USE POWER ;
    SHAPE ABUTMENT ;
    PORT
      LAYER ML1 ;
        RECT -0.500 28.000 16.000 30.000 ;
        RECT 3.500 19.000 5.500 28.000 ;
    END
  END VDD
  PIN VSS
    DIRECTION INOUT ;
    USE GROUND ;
    SHAPE ABUTMENT ;
    PORT
      LAYER ML1 ;
        RECT 0.500 1.000 2.500 4.500 ;
        RECT 10.500 1.000 12.500 4.500 ;
        RECT -0.500 -1.000 16.000 1.000 ;
    END
  END VSS
  PIN A0
    DIRECTION INPUT ;
    USE SIGNAL ;
    PORT
      LAYER ML2 ;
        RECT 1.000 14.000 3.000 16.000 ;
    END
  END A0
  PIN A1
    DIRECTION INPUT ;
    USE SIGNAL ;
    PORT
      LAYER ML2 ;
        RECT 4.000 8.500 6.000 10.500 ;
    END
  END A1
  PIN B1
    DIRECTION INPUT ;
    USE SIGNAL ;
    PORT
      LAYER ML2 ;
        RECT 7.000 11.500 9.000 13.500 ;
    END
  END B1
  PIN X
    DIRECTION OUTPUT ;
    USE SIGNAL ;
    PORT
      LAYER ML2 ;
        RECT 12.500 8.000 14.500 10.000 ;
    END
  END X
  PIN B0
    DIRECTION INPUT ;
    USE SIGNAL ;
    PORT
      LAYER ML2 ;
        RECT 10.000 14.000 12.000 16.000 ;
    END
  END B0
  OBS
      LAYER ML1 ;
        RECT 7.000 26.000 14.000 27.000 ;
        RECT 7.000 25.000 8.000 26.000 ;
        RECT 13.000 25.000 14.000 26.000 ;
        RECT 0.500 19.000 2.500 25.000 ;
        RECT 6.500 19.000 8.500 25.000 ;
        RECT 9.500 19.000 11.500 25.000 ;
        RECT 12.500 19.000 14.500 25.000 ;
        RECT 1.000 18.000 2.000 19.000 ;
        RECT 7.000 18.000 8.000 19.000 ;
        RECT 1.000 17.000 8.000 18.000 ;
        RECT 10.000 18.000 11.000 19.000 ;
        RECT 10.000 17.000 14.000 18.000 ;
        RECT 1.000 14.000 3.000 16.000 ;
        RECT 10.000 14.000 12.000 16.000 ;
        RECT 7.000 11.500 9.000 13.500 ;
        RECT 4.000 8.500 6.000 10.500 ;
        RECT 13.000 10.000 14.000 17.000 ;
        RECT 12.500 8.000 14.500 10.000 ;
        RECT 13.000 7.000 14.000 8.000 ;
        RECT 6.500 6.000 14.000 7.000 ;
        RECT 6.500 4.500 7.500 6.000 ;
        RECT 5.500 2.500 7.500 4.500 ;
      LAYER POL ;
        RECT 2.500 16.000 3.500 26.000 ;
        RECT 5.500 16.000 6.500 26.000 ;
        RECT 8.500 18.500 9.500 26.000 ;
        RECT 1.000 15.000 3.500 16.000 ;
        RECT 5.000 15.000 6.500 16.000 ;
        RECT 8.000 17.500 9.500 18.500 ;
        RECT 1.000 14.000 3.000 15.000 ;
        RECT 2.000 7.000 3.000 14.000 ;
        RECT 5.000 10.500 6.000 15.000 ;
        RECT 8.000 13.500 9.000 17.500 ;
        RECT 11.500 16.000 12.500 26.000 ;
        RECT 10.000 14.000 12.500 16.000 ;
        RECT 7.000 11.500 9.000 13.500 ;
        RECT 4.000 8.500 6.000 10.500 ;
        RECT 2.000 6.000 3.500 7.000 ;
        RECT 2.500 1.500 3.500 6.000 ;
        RECT 4.500 1.500 5.500 8.500 ;
        RECT 7.500 1.500 8.500 11.500 ;
        RECT 11.500 8.500 12.500 14.000 ;
        RECT 9.500 7.500 12.500 8.500 ;
        RECT 9.500 1.500 10.500 7.500 ;
  END
END nr222

#--------EOF---------

MACRO or21
  CLASS CORE ;
  FOREIGN or21 ;
  ORIGIN 0.000 0.000 ;
  SIZE 12.500 BY 29.000 ;
  SYMMETRY X Y R90 ;
  SITE core ;
  PIN VSS
    DIRECTION INOUT ;
    USE GROUND ;
    SHAPE ABUTMENT ;
    PORT
      LAYER ML1 ;
        RECT 0.500 1.000 2.500 4.500 ;
        RECT 6.500 1.000 8.500 4.500 ;
        RECT -0.500 -1.000 13.000 1.000 ;
    END
  END VSS
  PIN VDD
    DIRECTION INOUT ;
    USE POWER ;
    SHAPE ABUTMENT ;
    PORT
      LAYER ML1 ;
        RECT -0.500 28.000 13.000 30.000 ;
        RECT 6.000 20.500 8.000 28.000 ;
    END
  END VDD
  PIN A
    DIRECTION INPUT ;
    USE SIGNAL ;
    PORT
      LAYER ML2 ;
        RECT 1.000 8.500 3.000 10.500 ;
    END
  END A
  PIN B
    DIRECTION INPUT ;
    USE SIGNAL ;
    PORT
      LAYER ML2 ;
        RECT 4.000 11.500 6.000 13.500 ;
    END
  END B
  PIN X
    DIRECTION OUTPUT ;
    USE SIGNAL ;
    PORT
      LAYER ML2 ;
        RECT 10.000 8.000 12.000 10.000 ;
    END
  END X
  OBS
      LAYER ML1 ;
        RECT 1.000 20.500 3.000 26.500 ;
        RECT 9.000 20.500 11.000 26.500 ;
        RECT 1.500 17.000 2.500 20.500 ;
        RECT 9.500 18.500 10.500 20.500 ;
        RECT 9.500 17.500 11.000 18.500 ;
        RECT 1.500 16.000 8.000 17.000 ;
        RECT 7.000 13.500 8.000 16.000 ;
        RECT 4.000 11.500 6.000 13.500 ;
        RECT 7.000 11.500 9.000 13.500 ;
        RECT 1.000 8.500 3.000 10.500 ;
        RECT 7.000 6.500 8.000 11.500 ;
        RECT 4.500 5.500 8.000 6.500 ;
        RECT 10.000 10.000 11.000 17.500 ;
        RECT 10.000 8.000 12.000 10.000 ;
        RECT 4.500 4.500 5.500 5.500 ;
        RECT 10.000 4.500 11.000 8.000 ;
        RECT 3.500 2.500 5.500 4.500 ;
        RECT 9.500 2.500 11.500 4.500 ;
      LAYER POL ;
        RECT 3.000 18.500 4.000 27.500 ;
        RECT 2.000 17.500 4.000 18.500 ;
        RECT 2.000 10.500 3.000 17.500 ;
        RECT 5.000 13.500 6.000 27.500 ;
        RECT 8.000 17.500 9.000 27.500 ;
        RECT 8.000 16.500 9.500 17.500 ;
        RECT 8.500 13.500 9.500 16.500 ;
        RECT 4.000 11.500 6.000 13.500 ;
        RECT 7.000 11.500 9.500 13.500 ;
        RECT 5.000 10.500 6.000 11.500 ;
        RECT 1.000 8.500 3.500 10.500 ;
        RECT 5.000 9.500 6.500 10.500 ;
        RECT 2.500 1.500 3.500 8.500 ;
        RECT 5.500 1.500 6.500 9.500 ;
        RECT 8.500 1.500 9.500 11.500 ;
  END
END or21

#--------EOF---------

MACRO or31
  CLASS CORE ;
  FOREIGN or31 ;
  ORIGIN 0.000 0.000 ;
  SIZE 15.500 BY 29.000 ;
  SYMMETRY X Y R90 ;
  SITE core ;
  PIN VSS
    DIRECTION INOUT ;
    USE GROUND ;
    SHAPE ABUTMENT ;
    PORT
      LAYER ML1 ;
        RECT 3.500 1.000 5.500 4.500 ;
        RECT 9.500 1.000 11.500 4.500 ;
        RECT -0.500 -1.000 16.000 1.000 ;
    END
  END VSS
  PIN VDD
    DIRECTION INOUT ;
    USE POWER ;
    SHAPE ABUTMENT ;
    PORT
      LAYER ML1 ;
        RECT -0.500 28.000 16.000 30.000 ;
        RECT 8.500 20.500 10.500 28.000 ;
    END
  END VDD
  PIN B
    DIRECTION INPUT ;
    USE SIGNAL ;
    PORT
      LAYER ML2 ;
        RECT 4.000 11.500 6.000 13.500 ;
    END
  END B
  PIN C
    DIRECTION INPUT ;
    USE SIGNAL ;
    PORT
      LAYER ML2 ;
        RECT 7.000 12.000 9.000 14.000 ;
    END
  END C
  PIN A
    DIRECTION INPUT ;
    USE SIGNAL ;
    PORT
      LAYER ML2 ;
        RECT 1.000 14.500 3.000 16.500 ;
    END
  END A
  PIN X
    DIRECTION OUTPUT ;
    USE SIGNAL ;
    PORT
      LAYER ML2 ;
        RECT 13.000 9.000 15.000 11.000 ;
    END
  END X
  OBS
      LAYER ML1 ;
        RECT 1.500 20.500 3.500 26.500 ;
        RECT 11.500 20.500 13.500 26.500 ;
        RECT 2.500 18.500 3.500 20.500 ;
        RECT 2.500 17.500 11.000 18.500 ;
        RECT 1.000 14.500 3.000 16.500 ;
        RECT 10.000 14.000 11.000 17.500 ;
        RECT 12.000 17.000 13.000 20.500 ;
        RECT 12.000 16.000 14.000 17.000 ;
        RECT 4.000 11.500 6.000 13.500 ;
        RECT 7.000 12.000 9.000 14.000 ;
        RECT 10.000 12.000 12.000 14.000 ;
        RECT 10.000 8.500 11.000 12.000 ;
        RECT 1.500 7.500 11.000 8.500 ;
        RECT 13.000 11.000 14.000 16.000 ;
        RECT 13.000 9.000 15.000 11.000 ;
        RECT 1.500 4.500 2.500 7.500 ;
        RECT 7.000 4.500 8.000 7.500 ;
        RECT 13.000 4.500 14.000 9.000 ;
        RECT 0.500 2.500 2.500 4.500 ;
        RECT 6.500 2.500 8.500 4.500 ;
        RECT 12.500 2.500 14.500 4.500 ;
      LAYER POL ;
        RECT 3.500 18.000 4.500 27.500 ;
        RECT 2.000 17.000 4.500 18.000 ;
        RECT 2.000 16.500 3.000 17.000 ;
        RECT 1.000 14.500 3.000 16.500 ;
        RECT 5.500 16.000 6.500 27.500 ;
        RECT 2.000 10.500 3.000 14.500 ;
        RECT 5.000 15.000 6.500 16.000 ;
        RECT 5.000 13.500 6.000 15.000 ;
        RECT 7.500 14.000 8.500 27.500 ;
        RECT 10.500 14.000 11.500 27.500 ;
        RECT 4.000 11.500 6.000 13.500 ;
        RECT 7.000 12.000 9.000 14.000 ;
        RECT 10.000 13.500 12.000 14.000 ;
        RECT 10.000 12.000 12.500 13.500 ;
        RECT 5.000 10.500 6.000 11.500 ;
        RECT 7.500 10.500 8.500 12.000 ;
        RECT 2.000 9.500 3.500 10.500 ;
        RECT 5.000 9.500 6.500 10.500 ;
        RECT 7.500 9.500 9.500 10.500 ;
        RECT 2.500 1.500 3.500 9.500 ;
        RECT 5.500 1.500 6.500 9.500 ;
        RECT 8.500 1.500 9.500 9.500 ;
        RECT 11.500 1.500 12.500 12.000 ;
  END
END or31

#--------EOF---------

MACRO rff1
  CLASS CORE ;
  FOREIGN rff1 ;
  ORIGIN 0.000 0.000 ;
  SIZE 56.000 BY 29.000 ;
  SYMMETRY X Y R90 ;
  SITE core ;
  PIN VDD
    DIRECTION INOUT ;
    USE POWER ;
    SHAPE ABUTMENT ;
    PORT
      LAYER ML1 ;
        RECT -0.500 28.000 56.500 30.000 ;
        RECT 3.500 20.500 5.500 28.000 ;
        RECT 10.000 20.500 12.000 28.000 ;
        RECT 20.000 20.500 22.000 28.000 ;
        RECT 28.500 20.500 30.500 28.000 ;
        RECT 38.500 20.500 40.500 28.000 ;
        RECT 50.000 20.500 52.000 28.000 ;
    END
  END VDD
  PIN VSS
    DIRECTION INOUT ;
    USE GROUND ;
    SHAPE ABUTMENT ;
    PORT
      LAYER ML1 ;
        RECT 3.500 1.000 5.500 4.800 ;
        RECT 10.000 1.000 12.000 4.800 ;
        RECT 20.000 1.000 22.000 4.800 ;
        RECT 26.000 1.000 28.000 4.800 ;
        RECT 36.000 1.000 38.000 4.800 ;
        RECT 42.000 1.000 44.000 4.800 ;
        RECT 50.000 1.000 52.000 4.800 ;
        RECT -0.500 -1.000 56.500 1.000 ;
    END
  END VSS
  PIN QB
    DIRECTION INPUT ;
    USE SIGNAL ;
    PORT
      LAYER ML1 ;
        RECT 47.000 20.500 49.000 26.500 ;
        RECT 47.500 19.500 48.500 20.500 ;
        RECT 47.500 18.500 53.000 19.500 ;
        RECT 51.000 17.500 53.000 18.500 ;
        RECT 51.500 7.500 52.500 17.500 ;
        RECT 51.000 6.500 53.000 7.500 ;
        RECT 48.000 5.500 53.000 6.500 ;
        RECT 48.000 4.500 49.000 5.500 ;
        RECT 47.000 2.500 49.000 4.500 ;
    END
  END QB
  PIN Q
    DIRECTION INPUT ;
    USE SIGNAL ;
    PORT
      LAYER ML2 ;
        RECT 53.500 10.500 55.500 12.500 ;
    END
  END Q
  PIN R
    DIRECTION INPUT ;
    USE SIGNAL ;
    PORT
      LAYER ML2 ;
        RECT 43.000 10.500 45.000 12.500 ;
    END
  END R
  PIN D
    DIRECTION INPUT ;
    USE SIGNAL ;
    PORT
      LAYER ML2 ;
        RECT 11.000 9.000 13.000 11.000 ;
    END
  END D
  PIN CK
    DIRECTION INPUT ;
    USE SIGNAL ;
    PORT
      LAYER ML2 ;
        RECT 3.500 9.000 5.500 11.000 ;
    END
  END CK
  OBS
      LAYER ML1 ;
        RECT 0.500 20.500 2.500 26.500 ;
        RECT 6.500 20.500 8.500 26.500 ;
        RECT 15.000 20.500 17.000 26.500 ;
        RECT 25.000 20.500 27.000 26.500 ;
        RECT 33.500 20.500 35.500 26.500 ;
        RECT 43.500 20.500 45.500 26.500 ;
        RECT 53.000 20.500 55.000 26.500 ;
        RECT 1.000 19.500 2.000 20.500 ;
        RECT 1.000 18.500 6.500 19.500 ;
        RECT 1.000 13.500 2.000 18.500 ;
        RECT 4.500 17.500 6.500 18.500 ;
        RECT 7.500 16.500 8.500 20.500 ;
        RECT 15.500 19.500 16.500 20.500 ;
        RECT 25.500 19.500 26.500 20.500 ;
        RECT 34.000 19.500 35.000 20.500 ;
        RECT 15.500 18.500 23.000 19.500 ;
        RECT 25.500 18.500 29.000 19.500 ;
        RECT 34.000 18.500 41.500 19.500 ;
        RECT 21.000 17.500 23.000 18.500 ;
        RECT 27.000 17.500 29.000 18.500 ;
        RECT 39.500 17.500 41.500 18.500 ;
        RECT 16.000 16.500 18.000 17.000 ;
        RECT 31.000 16.500 33.000 17.500 ;
        RECT 7.000 15.500 33.000 16.500 ;
        RECT 44.000 17.000 45.000 20.500 ;
        RECT 48.000 17.000 50.000 17.500 ;
        RECT 44.000 16.000 50.000 17.000 ;
        RECT 4.000 13.500 6.000 14.000 ;
        RECT 1.000 12.500 6.000 13.500 ;
        RECT 1.000 7.000 2.000 12.500 ;
        RECT 4.000 12.000 6.000 12.500 ;
        RECT 3.500 9.000 5.500 11.000 ;
        RECT 7.000 10.000 8.000 15.500 ;
        RECT 16.000 15.000 18.000 15.500 ;
        RECT 9.000 13.500 11.000 14.000 ;
        RECT 14.000 13.500 16.000 14.000 ;
        RECT 29.000 13.500 31.000 14.000 ;
        RECT 34.500 13.500 36.500 15.000 ;
        RECT 9.000 12.500 36.500 13.500 ;
        RECT 37.500 14.500 39.500 15.000 ;
        RECT 44.000 14.500 45.000 16.000 ;
        RECT 48.000 15.500 50.000 16.000 ;
        RECT 37.500 13.500 49.000 14.500 ;
        RECT 37.500 13.000 39.500 13.500 ;
        RECT 9.000 12.000 11.000 12.500 ;
        RECT 14.000 12.000 16.000 12.500 ;
        RECT 29.000 12.000 31.000 12.500 ;
        RECT 7.000 9.000 8.500 10.000 ;
        RECT 11.000 9.000 13.000 11.000 ;
        RECT 21.000 10.500 23.000 11.000 ;
        RECT 17.000 9.500 23.000 10.500 ;
        RECT 4.500 7.000 6.500 7.500 ;
        RECT 1.000 6.000 6.500 7.000 ;
        RECT 1.000 4.500 2.000 6.000 ;
        RECT 4.500 5.500 6.500 6.000 ;
        RECT 7.500 7.000 8.500 9.000 ;
        RECT 14.000 7.000 16.000 7.500 ;
        RECT 7.500 6.000 16.000 7.000 ;
        RECT 7.500 4.500 8.500 6.000 ;
        RECT 14.000 5.500 16.000 6.000 ;
        RECT 17.000 4.500 18.000 9.500 ;
        RECT 21.000 9.000 23.000 9.500 ;
        RECT 24.000 10.500 26.000 11.000 ;
        RECT 43.000 10.500 45.000 12.500 ;
        RECT 24.000 9.500 45.000 10.500 ;
        RECT 48.000 10.000 49.000 13.500 ;
        RECT 54.000 12.500 55.000 20.500 ;
        RECT 53.500 10.500 55.500 12.500 ;
        RECT 24.000 9.000 26.000 9.500 ;
        RECT 48.000 9.000 50.000 10.000 ;
        RECT 46.000 8.000 50.000 9.000 ;
        RECT 19.000 7.000 21.000 7.500 ;
        RECT 27.000 7.000 29.000 7.500 ;
        RECT 19.000 6.000 29.000 7.000 ;
        RECT 37.000 6.500 39.000 7.500 ;
        RECT 46.000 6.500 47.000 8.000 ;
        RECT 19.000 5.500 21.000 6.000 ;
        RECT 23.500 4.500 24.500 6.000 ;
        RECT 27.000 5.500 29.000 6.000 ;
        RECT 32.000 5.500 39.000 6.500 ;
        RECT 40.000 5.500 47.000 6.500 ;
        RECT 32.000 4.500 33.000 5.500 ;
        RECT 40.000 4.500 41.000 5.500 ;
        RECT 54.000 4.500 55.000 10.500 ;
        RECT 0.500 2.500 2.500 4.500 ;
        RECT 6.500 2.500 8.500 4.500 ;
        RECT 15.000 3.500 18.000 4.500 ;
        RECT 15.000 2.500 17.000 3.500 ;
        RECT 23.000 2.500 25.000 4.500 ;
        RECT 31.000 2.500 33.000 4.500 ;
        RECT 39.000 2.500 41.000 4.500 ;
        RECT 53.000 2.500 55.000 4.500 ;
      LAYER POL ;
        RECT 2.500 17.500 3.500 27.500 ;
        RECT 5.500 19.500 6.500 27.500 ;
        RECT 4.500 17.500 6.500 19.500 ;
        RECT 2.000 16.500 3.500 17.500 ;
        RECT 2.000 11.000 3.000 16.500 ;
        RECT 4.000 13.500 6.000 14.000 ;
        RECT 9.000 13.500 11.000 14.000 ;
        RECT 4.000 12.500 11.000 13.500 ;
        RECT 4.000 12.000 6.000 12.500 ;
        RECT 9.000 12.000 11.000 12.500 ;
        RECT 12.000 11.000 13.000 27.500 ;
        RECT 14.000 14.000 15.000 27.500 ;
        RECT 17.000 17.000 18.000 27.500 ;
        RECT 16.000 15.000 18.000 17.000 ;
        RECT 14.000 12.000 16.000 14.000 ;
        RECT 2.000 10.000 5.500 11.000 ;
        RECT 2.500 9.000 5.500 10.000 ;
        RECT 11.000 9.000 13.000 11.000 ;
        RECT 15.000 10.500 16.000 12.000 ;
        RECT 15.000 9.500 18.000 10.500 ;
        RECT 2.500 1.500 3.500 9.000 ;
        RECT 4.500 5.500 6.500 7.500 ;
        RECT 5.500 1.500 6.500 5.500 ;
        RECT 12.000 1.500 13.000 9.000 ;
        RECT 14.000 5.500 16.000 7.500 ;
        RECT 14.000 1.500 15.000 5.500 ;
        RECT 17.000 1.500 18.000 9.500 ;
        RECT 19.000 7.500 20.000 27.500 ;
        RECT 22.000 19.500 23.000 27.500 ;
        RECT 21.000 17.500 23.000 19.500 ;
        RECT 22.000 11.000 23.000 17.500 ;
        RECT 21.000 9.000 23.000 11.000 ;
        RECT 24.000 11.000 25.000 27.500 ;
        RECT 30.500 19.500 31.500 27.500 ;
        RECT 27.000 18.500 31.500 19.500 ;
        RECT 27.000 17.500 29.000 18.500 ;
        RECT 32.500 17.500 33.500 27.500 ;
        RECT 24.000 9.000 26.000 11.000 ;
        RECT 19.000 5.500 21.000 7.500 ;
        RECT 19.000 1.500 20.000 5.500 ;
        RECT 22.000 1.500 23.000 9.000 ;
        RECT 25.000 1.500 26.000 9.000 ;
        RECT 27.000 7.500 28.000 17.500 ;
        RECT 31.000 15.500 33.500 17.500 ;
        RECT 29.000 12.000 31.000 14.000 ;
        RECT 27.000 5.500 29.000 7.500 ;
        RECT 28.000 1.500 29.000 5.500 ;
        RECT 30.000 1.500 31.000 12.000 ;
        RECT 32.500 9.000 33.500 15.500 ;
        RECT 35.500 15.000 36.500 27.500 ;
        RECT 34.500 13.000 36.500 15.000 ;
        RECT 37.500 15.000 38.500 27.500 ;
        RECT 40.500 19.500 41.500 27.500 ;
        RECT 39.500 17.500 41.500 19.500 ;
        RECT 37.500 13.000 39.500 15.000 ;
        RECT 37.500 11.500 38.500 13.000 ;
        RECT 35.000 10.500 38.500 11.500 ;
        RECT 32.500 8.000 34.000 9.000 ;
        RECT 33.000 1.500 34.000 8.000 ;
        RECT 35.000 1.500 36.000 10.500 ;
        RECT 40.500 9.500 41.500 17.500 ;
        RECT 38.000 8.500 41.500 9.500 ;
        RECT 42.500 12.500 43.500 27.500 ;
        RECT 49.000 17.500 50.000 27.500 ;
        RECT 52.000 19.500 53.000 27.500 ;
        RECT 51.000 17.500 53.000 19.500 ;
        RECT 48.000 15.500 50.000 17.500 ;
        RECT 42.500 10.500 45.000 12.500 ;
        RECT 38.000 7.500 39.000 8.500 ;
        RECT 37.000 5.500 39.000 7.500 ;
        RECT 42.500 7.000 43.500 10.500 ;
        RECT 48.000 8.000 50.000 10.000 ;
        RECT 38.000 1.500 39.000 5.500 ;
        RECT 41.000 6.000 43.500 7.000 ;
        RECT 41.000 1.500 42.000 6.000 ;
        RECT 49.000 1.500 50.000 8.000 ;
        RECT 51.000 5.500 53.000 7.500 ;
        RECT 52.000 1.500 53.000 5.500 ;
  END
END rff1

#--------EOF---------

MACRO rff1_r
  CLASS CORE ;
  FOREIGN rff1_r ;
  ORIGIN 0.000 0.000 ;
  SIZE 62.500 BY 29.000 ;
  SYMMETRY X Y R90 ;
  SITE core ;
  PIN VDD
    DIRECTION INOUT ;
    USE POWER ;
    SHAPE ABUTMENT ;
    PORT
      LAYER ML1 ;
        RECT -0.500 28.000 63.000 30.000 ;
        RECT 0.500 20.500 2.500 28.000 ;
        RECT 10.000 20.500 12.000 28.000 ;
        RECT 16.500 20.500 18.500 28.000 ;
        RECT 26.500 20.500 28.500 28.000 ;
        RECT 35.000 20.500 37.000 28.000 ;
        RECT 45.000 20.500 47.000 28.000 ;
        RECT 56.500 20.500 58.500 28.000 ;
    END
  END VDD
  PIN VSS
    DIRECTION INOUT ;
    USE GROUND ;
    SHAPE ABUTMENT ;
    PORT
      LAYER ML1 ;
        RECT 0.500 1.000 2.500 4.500 ;
        RECT 10.000 1.000 12.000 4.800 ;
        RECT 16.500 1.000 18.500 4.800 ;
        RECT 26.500 1.000 28.500 4.800 ;
        RECT 32.500 1.000 34.500 4.800 ;
        RECT 42.500 1.000 44.500 4.800 ;
        RECT 48.500 1.000 50.500 4.800 ;
        RECT 56.500 1.000 58.500 4.800 ;
        RECT -0.500 -1.000 63.000 1.000 ;
    END
  END VSS
  PIN QB
    DIRECTION INPUT ;
    USE SIGNAL ;
    PORT
      LAYER ML1 ;
        RECT 53.500 20.500 55.500 26.500 ;
        RECT 54.000 19.500 55.000 20.500 ;
        RECT 54.000 18.500 59.500 19.500 ;
        RECT 57.500 17.500 59.500 18.500 ;
        RECT 58.000 7.500 59.000 17.500 ;
        RECT 57.500 6.500 59.500 7.500 ;
        RECT 54.500 5.500 59.500 6.500 ;
        RECT 54.500 4.500 55.500 5.500 ;
        RECT 53.500 2.500 55.500 4.500 ;
    END
  END QB
  PIN CK
    DIRECTION INPUT ;
    USE SIGNAL ;
    PORT
      LAYER ML2 ;
        RECT 1.000 14.500 3.000 16.500 ;
    END
  END CK
  PIN Q
    DIRECTION INPUT ;
    USE SIGNAL ;
    PORT
      LAYER ML2 ;
        RECT 60.000 10.500 62.000 12.500 ;
    END
  END Q
  PIN R
    DIRECTION INPUT ;
    USE SIGNAL ;
    PORT
      LAYER ML2 ;
        RECT 49.500 10.500 51.500 12.500 ;
    END
  END R
  PIN D
    DIRECTION INPUT ;
    USE SIGNAL ;
    PORT
      LAYER ML2 ;
        RECT 17.500 9.000 19.500 11.000 ;
    END
  END D
  OBS
      LAYER ML1 ;
        RECT 3.500 20.500 5.500 26.500 ;
        RECT 7.000 20.500 9.000 26.500 ;
        RECT 13.000 20.500 15.000 26.500 ;
        RECT 21.500 20.500 23.500 26.500 ;
        RECT 31.500 20.500 33.500 26.500 ;
        RECT 40.000 20.500 42.000 26.500 ;
        RECT 50.000 20.500 52.000 26.500 ;
        RECT 59.500 20.500 61.500 26.500 ;
        RECT 1.000 14.500 3.000 16.500 ;
        RECT 4.000 14.000 5.000 20.500 ;
        RECT 7.500 19.500 8.500 20.500 ;
        RECT 7.500 18.500 13.000 19.500 ;
        RECT 4.000 12.000 6.500 14.000 ;
        RECT 7.500 13.500 8.500 18.500 ;
        RECT 11.000 17.500 13.000 18.500 ;
        RECT 14.000 16.500 15.000 20.500 ;
        RECT 22.000 19.500 23.000 20.500 ;
        RECT 32.000 19.500 33.000 20.500 ;
        RECT 40.500 19.500 41.500 20.500 ;
        RECT 22.000 18.500 29.500 19.500 ;
        RECT 32.000 18.500 35.500 19.500 ;
        RECT 40.500 18.500 48.000 19.500 ;
        RECT 27.500 17.500 29.500 18.500 ;
        RECT 33.500 17.500 35.500 18.500 ;
        RECT 46.000 17.500 48.000 18.500 ;
        RECT 22.500 16.500 24.500 17.000 ;
        RECT 37.500 16.500 39.500 17.500 ;
        RECT 13.500 15.500 39.500 16.500 ;
        RECT 50.500 17.000 51.500 20.500 ;
        RECT 54.500 17.000 56.500 17.500 ;
        RECT 50.500 16.000 56.500 17.000 ;
        RECT 10.500 13.500 12.500 14.000 ;
        RECT 7.500 12.500 12.500 13.500 ;
        RECT 4.000 4.500 5.000 12.000 ;
        RECT 7.500 7.000 8.500 12.500 ;
        RECT 10.500 12.000 12.500 12.500 ;
        RECT 10.000 9.000 12.000 11.000 ;
        RECT 13.500 10.000 14.500 15.500 ;
        RECT 22.500 15.000 24.500 15.500 ;
        RECT 15.500 13.500 17.500 14.000 ;
        RECT 20.500 13.500 22.500 14.000 ;
        RECT 35.500 13.500 37.500 14.000 ;
        RECT 41.000 13.500 43.000 15.000 ;
        RECT 15.500 12.500 43.000 13.500 ;
        RECT 44.000 14.500 46.000 15.000 ;
        RECT 50.500 14.500 51.500 16.000 ;
        RECT 54.500 15.500 56.500 16.000 ;
        RECT 44.000 13.500 55.500 14.500 ;
        RECT 44.000 13.000 46.000 13.500 ;
        RECT 15.500 12.000 17.500 12.500 ;
        RECT 20.500 12.000 22.500 12.500 ;
        RECT 35.500 12.000 37.500 12.500 ;
        RECT 13.500 9.000 15.000 10.000 ;
        RECT 17.500 9.000 19.500 11.000 ;
        RECT 27.500 10.500 29.500 11.000 ;
        RECT 23.500 9.500 29.500 10.500 ;
        RECT 11.000 7.000 13.000 7.500 ;
        RECT 7.500 6.000 13.000 7.000 ;
        RECT 7.500 4.500 8.500 6.000 ;
        RECT 11.000 5.500 13.000 6.000 ;
        RECT 14.000 7.000 15.000 9.000 ;
        RECT 20.500 7.000 22.500 7.500 ;
        RECT 14.000 6.000 22.500 7.000 ;
        RECT 14.000 4.500 15.000 6.000 ;
        RECT 20.500 5.500 22.500 6.000 ;
        RECT 23.500 4.500 24.500 9.500 ;
        RECT 27.500 9.000 29.500 9.500 ;
        RECT 30.500 10.500 32.500 11.000 ;
        RECT 49.500 10.500 51.500 12.500 ;
        RECT 30.500 9.500 51.500 10.500 ;
        RECT 54.500 10.000 55.500 13.500 ;
        RECT 60.500 12.500 61.500 20.500 ;
        RECT 60.000 10.500 62.000 12.500 ;
        RECT 30.500 9.000 32.500 9.500 ;
        RECT 54.500 9.000 56.500 10.000 ;
        RECT 52.500 8.000 56.500 9.000 ;
        RECT 25.500 7.000 27.500 7.500 ;
        RECT 33.500 7.000 35.500 7.500 ;
        RECT 25.500 6.000 35.500 7.000 ;
        RECT 43.500 6.500 45.500 7.500 ;
        RECT 52.500 6.500 53.500 8.000 ;
        RECT 25.500 5.500 27.500 6.000 ;
        RECT 30.000 4.500 31.000 6.000 ;
        RECT 33.500 5.500 35.500 6.000 ;
        RECT 38.500 5.500 45.500 6.500 ;
        RECT 46.500 5.500 53.500 6.500 ;
        RECT 38.500 4.500 39.500 5.500 ;
        RECT 46.500 4.500 47.500 5.500 ;
        RECT 60.500 4.500 61.500 10.500 ;
        RECT 3.500 2.500 5.500 4.500 ;
        RECT 7.000 2.500 9.000 4.500 ;
        RECT 13.000 2.500 15.000 4.500 ;
        RECT 21.500 3.500 24.500 4.500 ;
        RECT 21.500 2.500 23.500 3.500 ;
        RECT 29.500 2.500 31.500 4.500 ;
        RECT 37.500 2.500 39.500 4.500 ;
        RECT 45.500 2.500 47.500 4.500 ;
        RECT 59.500 2.500 61.500 4.500 ;
      LAYER ML2 ;
        RECT 10.000 9.000 12.000 11.000 ;
      LAYER POL ;
        RECT 2.500 16.500 3.500 27.500 ;
        RECT 9.000 17.500 10.000 27.500 ;
        RECT 12.000 19.500 13.000 27.500 ;
        RECT 11.000 17.500 13.000 19.500 ;
        RECT 1.000 14.500 3.500 16.500 ;
        RECT 2.500 1.500 3.500 14.500 ;
        RECT 8.500 16.500 10.000 17.500 ;
        RECT 8.500 14.000 9.500 16.500 ;
        RECT 4.500 12.000 9.500 14.000 ;
        RECT 10.500 13.500 12.500 14.000 ;
        RECT 15.500 13.500 17.500 14.000 ;
        RECT 10.500 12.500 17.500 13.500 ;
        RECT 10.500 12.000 12.500 12.500 ;
        RECT 15.500 12.000 17.500 12.500 ;
        RECT 8.500 11.000 9.500 12.000 ;
        RECT 18.500 11.000 19.500 27.500 ;
        RECT 20.500 14.000 21.500 27.500 ;
        RECT 23.500 17.000 24.500 27.500 ;
        RECT 22.500 15.000 24.500 17.000 ;
        RECT 20.500 12.000 22.500 14.000 ;
        RECT 8.500 10.000 12.000 11.000 ;
        RECT 9.000 9.000 12.000 10.000 ;
        RECT 17.500 9.000 19.500 11.000 ;
        RECT 21.500 10.500 22.500 12.000 ;
        RECT 21.500 9.500 24.500 10.500 ;
        RECT 9.000 1.500 10.000 9.000 ;
        RECT 11.000 5.500 13.000 7.500 ;
        RECT 12.000 1.500 13.000 5.500 ;
        RECT 18.500 1.500 19.500 9.000 ;
        RECT 20.500 5.500 22.500 7.500 ;
        RECT 20.500 1.500 21.500 5.500 ;
        RECT 23.500 1.500 24.500 9.500 ;
        RECT 25.500 7.500 26.500 27.500 ;
        RECT 28.500 19.500 29.500 27.500 ;
        RECT 27.500 17.500 29.500 19.500 ;
        RECT 28.500 11.000 29.500 17.500 ;
        RECT 27.500 9.000 29.500 11.000 ;
        RECT 30.500 11.000 31.500 27.500 ;
        RECT 37.000 19.500 38.000 27.500 ;
        RECT 33.500 18.500 38.000 19.500 ;
        RECT 33.500 17.500 35.500 18.500 ;
        RECT 39.000 17.500 40.000 27.500 ;
        RECT 30.500 9.000 32.500 11.000 ;
        RECT 25.500 5.500 27.500 7.500 ;
        RECT 25.500 1.500 26.500 5.500 ;
        RECT 28.500 1.500 29.500 9.000 ;
        RECT 31.500 1.500 32.500 9.000 ;
        RECT 33.500 7.500 34.500 17.500 ;
        RECT 37.500 15.500 40.000 17.500 ;
        RECT 35.500 12.000 37.500 14.000 ;
        RECT 33.500 5.500 35.500 7.500 ;
        RECT 34.500 1.500 35.500 5.500 ;
        RECT 36.500 1.500 37.500 12.000 ;
        RECT 39.000 9.000 40.000 15.500 ;
        RECT 42.000 15.000 43.000 27.500 ;
        RECT 41.000 13.000 43.000 15.000 ;
        RECT 44.000 15.000 45.000 27.500 ;
        RECT 47.000 19.500 48.000 27.500 ;
        RECT 46.000 17.500 48.000 19.500 ;
        RECT 44.000 13.000 46.000 15.000 ;
        RECT 44.000 11.500 45.000 13.000 ;
        RECT 41.500 10.500 45.000 11.500 ;
        RECT 39.000 8.000 40.500 9.000 ;
        RECT 39.500 1.500 40.500 8.000 ;
        RECT 41.500 1.500 42.500 10.500 ;
        RECT 47.000 9.500 48.000 17.500 ;
        RECT 44.500 8.500 48.000 9.500 ;
        RECT 49.000 12.500 50.000 27.500 ;
        RECT 55.500 17.500 56.500 27.500 ;
        RECT 58.500 19.500 59.500 27.500 ;
        RECT 57.500 17.500 59.500 19.500 ;
        RECT 54.500 15.500 56.500 17.500 ;
        RECT 49.000 10.500 51.500 12.500 ;
        RECT 44.500 7.500 45.500 8.500 ;
        RECT 43.500 5.500 45.500 7.500 ;
        RECT 49.000 7.000 50.000 10.500 ;
        RECT 54.500 8.000 56.500 10.000 ;
        RECT 44.500 1.500 45.500 5.500 ;
        RECT 47.500 6.000 50.000 7.000 ;
        RECT 47.500 1.500 48.500 6.000 ;
        RECT 55.500 1.500 56.500 8.000 ;
        RECT 57.500 5.500 59.500 7.500 ;
        RECT 58.500 1.500 59.500 5.500 ;
  END
END rff1_r

#--------EOF---------

MACRO rff1m2
  CLASS CORE ;
  FOREIGN rff1m2 ;
  ORIGIN 0.000 0.000 ;
  SIZE 56.000 BY 29.000 ;
  SYMMETRY X Y R90 ;
  SITE core ;
  PIN VDD
    DIRECTION INOUT ;
    USE POWER ;
    SHAPE ABUTMENT ;
    PORT
      LAYER ML1 ;
        RECT -0.500 28.000 56.500 30.000 ;
        RECT 3.500 20.500 5.500 28.000 ;
        RECT 10.000 20.500 12.000 28.000 ;
        RECT 20.000 20.500 22.000 28.000 ;
        RECT 28.500 20.500 30.500 28.000 ;
        RECT 38.500 20.500 40.500 28.000 ;
        RECT 50.000 20.500 52.000 28.000 ;
    END
  END VDD
  PIN VSS
    DIRECTION INOUT ;
    USE GROUND ;
    SHAPE ABUTMENT ;
    PORT
      LAYER ML1 ;
        RECT 3.500 1.000 5.500 4.800 ;
        RECT 10.000 1.000 12.000 4.800 ;
        RECT 20.000 1.000 22.000 4.800 ;
        RECT 26.000 1.000 28.000 4.800 ;
        RECT 36.000 1.000 38.000 4.800 ;
        RECT 42.000 1.000 44.000 4.800 ;
        RECT 50.000 1.000 52.000 4.800 ;
        RECT -0.500 -1.000 56.500 1.000 ;
    END
  END VSS
  PIN QB
    DIRECTION INPUT ;
    USE SIGNAL ;
    PORT
      LAYER ML1 ;
        RECT 47.000 20.500 49.000 26.500 ;
        RECT 48.000 19.500 49.000 20.500 ;
        RECT 48.000 18.500 53.000 19.500 ;
        RECT 51.000 17.500 53.000 18.500 ;
        RECT 51.500 7.500 52.500 17.500 ;
        RECT 51.000 6.500 53.000 7.500 ;
        RECT 48.000 5.500 53.000 6.500 ;
        RECT 48.000 4.500 49.000 5.500 ;
        RECT 47.000 2.500 49.000 4.500 ;
    END
  END QB
  PIN Q
    DIRECTION INPUT ;
    USE SIGNAL ;
    PORT
      LAYER ML2 ;
        RECT 53.500 10.500 55.500 12.500 ;
    END
  END Q
  PIN R
    DIRECTION INPUT ;
    USE SIGNAL ;
    PORT
      LAYER ML2 ;
        RECT 43.000 10.500 45.000 12.500 ;
    END
  END R
  PIN D
    DIRECTION INPUT ;
    USE SIGNAL ;
    PORT
      LAYER ML2 ;
        RECT 11.000 9.000 13.000 11.000 ;
    END
  END D
  PIN CK
    DIRECTION INPUT ;
    USE SIGNAL ;
    PORT
      LAYER ML2 ;
        RECT 3.500 9.000 5.500 11.000 ;
    END
  END CK
  OBS
      LAYER ML1 ;
        RECT 0.500 20.500 2.500 26.500 ;
        RECT 6.500 20.500 8.500 26.500 ;
        RECT 15.000 20.500 17.000 26.500 ;
        RECT 25.000 20.500 27.000 26.500 ;
        RECT 33.500 20.500 35.500 26.500 ;
        RECT 43.500 20.500 45.500 26.500 ;
        RECT 53.000 20.500 55.000 26.500 ;
        RECT 1.000 19.000 2.000 20.500 ;
        RECT 4.500 19.000 6.500 19.500 ;
        RECT 1.000 18.000 6.500 19.000 ;
        RECT 1.000 13.500 2.000 18.000 ;
        RECT 4.500 17.500 6.500 18.000 ;
        RECT 7.500 16.500 8.500 20.500 ;
        RECT 15.500 19.500 16.500 20.500 ;
        RECT 25.500 19.500 26.500 20.500 ;
        RECT 34.000 19.500 35.000 20.500 ;
        RECT 15.500 18.500 23.000 19.500 ;
        RECT 25.500 18.500 29.500 19.500 ;
        RECT 34.000 18.500 41.500 19.500 ;
        RECT 21.000 17.500 23.000 18.500 ;
        RECT 27.500 17.500 29.500 18.500 ;
        RECT 39.500 17.500 41.500 18.500 ;
        RECT 44.500 17.500 45.500 20.500 ;
        RECT 16.000 16.500 18.000 17.000 ;
        RECT 32.000 16.500 34.000 17.500 ;
        RECT 7.000 15.500 34.000 16.500 ;
        RECT 44.500 16.500 50.000 17.500 ;
        RECT 4.000 13.500 6.000 14.000 ;
        RECT 1.000 12.500 6.000 13.500 ;
        RECT 1.000 7.000 2.000 12.500 ;
        RECT 4.000 12.000 6.000 12.500 ;
        RECT 3.500 9.000 5.500 11.000 ;
        RECT 7.000 10.000 8.000 15.500 ;
        RECT 16.000 15.000 18.000 15.500 ;
        RECT 37.500 14.500 39.500 15.000 ;
        RECT 44.500 14.500 45.500 16.500 ;
        RECT 48.000 15.500 50.000 16.500 ;
        RECT 9.000 13.500 11.000 14.000 ;
        RECT 14.000 13.500 16.000 14.000 ;
        RECT 29.000 13.500 31.000 14.000 ;
        RECT 34.500 13.500 36.500 14.500 ;
        RECT 9.000 12.500 36.500 13.500 ;
        RECT 37.500 13.500 49.000 14.500 ;
        RECT 37.500 13.000 39.500 13.500 ;
        RECT 9.000 12.000 11.000 12.500 ;
        RECT 14.000 12.000 16.000 12.500 ;
        RECT 29.000 12.000 31.000 12.500 ;
        RECT 7.000 9.000 8.500 10.000 ;
        RECT 11.000 9.000 13.000 11.000 ;
        RECT 21.000 10.500 23.000 11.000 ;
        RECT 17.000 9.500 23.000 10.500 ;
        RECT 4.500 7.000 6.500 7.500 ;
        RECT 1.000 6.000 6.500 7.000 ;
        RECT 1.000 4.500 2.000 6.000 ;
        RECT 4.500 5.500 6.500 6.000 ;
        RECT 7.500 7.000 8.500 9.000 ;
        RECT 14.000 7.000 16.000 7.500 ;
        RECT 7.500 6.000 16.000 7.000 ;
        RECT 7.500 4.500 8.500 6.000 ;
        RECT 14.000 5.500 16.000 6.000 ;
        RECT 17.000 4.500 18.000 9.500 ;
        RECT 21.000 9.000 23.000 9.500 ;
        RECT 24.500 10.500 26.500 11.000 ;
        RECT 43.000 10.500 45.000 12.500 ;
        RECT 24.500 9.500 45.000 10.500 ;
        RECT 48.000 10.000 49.000 13.500 ;
        RECT 54.000 12.500 55.000 20.500 ;
        RECT 53.500 10.500 55.500 12.500 ;
        RECT 24.500 9.000 26.500 9.500 ;
        RECT 48.000 9.000 50.000 10.000 ;
        RECT 46.000 8.000 50.000 9.000 ;
        RECT 19.000 7.000 21.000 8.000 ;
        RECT 27.000 7.000 29.000 8.000 ;
        RECT 37.000 7.000 39.000 8.000 ;
        RECT 19.000 6.000 29.000 7.000 ;
        RECT 32.000 6.000 39.000 7.000 ;
        RECT 46.000 6.500 47.000 8.000 ;
        RECT 23.500 4.500 24.500 6.000 ;
        RECT 32.000 4.500 33.000 6.000 ;
        RECT 40.000 5.500 47.000 6.500 ;
        RECT 40.000 4.500 41.000 5.500 ;
        RECT 54.000 4.500 55.000 10.500 ;
        RECT 0.500 2.500 2.500 4.500 ;
        RECT 6.500 2.500 8.500 4.500 ;
        RECT 15.000 3.500 18.000 4.500 ;
        RECT 15.000 2.500 17.000 3.500 ;
        RECT 23.000 2.500 25.000 4.500 ;
        RECT 31.000 2.500 33.000 4.500 ;
        RECT 39.000 2.500 41.000 4.500 ;
        RECT 53.000 2.500 55.000 4.500 ;
      LAYER ML2 ;
        RECT 21.000 17.500 23.000 19.500 ;
        RECT 27.500 17.500 29.500 19.500 ;
        RECT 39.500 17.500 41.500 19.500 ;
        RECT 21.500 11.000 22.500 17.500 ;
        RECT 21.000 9.000 23.000 11.000 ;
        RECT 27.500 8.000 28.500 17.500 ;
        RECT 39.500 16.500 40.500 17.500 ;
        RECT 38.000 15.500 40.500 16.500 ;
        RECT 38.000 8.000 39.000 15.500 ;
        RECT 27.000 6.000 29.000 8.000 ;
        RECT 37.000 6.000 39.000 8.000 ;
      LAYER POL ;
        RECT 2.500 17.500 3.500 27.500 ;
        RECT 5.500 19.500 6.500 27.500 ;
        RECT 4.500 17.500 6.500 19.500 ;
        RECT 2.000 16.500 3.500 17.500 ;
        RECT 2.000 11.000 3.000 16.500 ;
        RECT 4.000 13.500 6.000 14.000 ;
        RECT 9.000 13.500 11.000 14.000 ;
        RECT 4.000 12.500 11.000 13.500 ;
        RECT 4.000 12.000 6.000 12.500 ;
        RECT 9.000 12.000 11.000 12.500 ;
        RECT 12.000 11.000 13.000 27.500 ;
        RECT 14.000 14.000 15.000 27.500 ;
        RECT 17.000 17.000 18.000 27.500 ;
        RECT 16.000 15.000 18.000 17.000 ;
        RECT 14.000 12.000 16.000 14.000 ;
        RECT 2.000 10.000 5.500 11.000 ;
        RECT 2.500 9.000 5.500 10.000 ;
        RECT 11.000 9.000 13.000 11.000 ;
        RECT 15.000 10.500 16.000 12.000 ;
        RECT 15.000 9.500 18.000 10.500 ;
        RECT 2.500 1.500 3.500 9.000 ;
        RECT 4.500 5.500 6.500 7.500 ;
        RECT 5.500 1.500 6.500 5.500 ;
        RECT 12.000 1.500 13.000 9.000 ;
        RECT 14.000 5.500 16.000 7.500 ;
        RECT 14.000 1.500 15.000 5.500 ;
        RECT 17.000 1.500 18.000 9.500 ;
        RECT 19.000 8.000 20.000 27.500 ;
        RECT 22.000 19.500 23.000 27.500 ;
        RECT 21.000 17.500 23.000 19.500 ;
        RECT 24.000 11.000 25.000 27.500 ;
        RECT 30.500 19.500 31.500 27.500 ;
        RECT 27.500 18.500 31.500 19.500 ;
        RECT 27.500 17.500 29.500 18.500 ;
        RECT 32.500 17.500 33.500 27.500 ;
        RECT 32.000 15.500 34.000 17.500 ;
        RECT 29.000 12.000 31.000 14.000 ;
        RECT 21.000 9.000 23.000 11.000 ;
        RECT 24.000 9.000 26.500 11.000 ;
        RECT 19.000 6.000 21.000 8.000 ;
        RECT 19.000 1.500 20.000 6.000 ;
        RECT 22.000 1.500 23.000 9.000 ;
        RECT 25.000 1.500 26.000 9.000 ;
        RECT 27.000 6.000 29.000 8.000 ;
        RECT 28.000 1.500 29.000 6.000 ;
        RECT 30.000 1.500 31.000 12.000 ;
        RECT 32.500 9.000 33.500 15.500 ;
        RECT 35.500 14.500 36.500 27.500 ;
        RECT 34.500 12.500 36.500 14.500 ;
        RECT 37.500 15.000 38.500 27.500 ;
        RECT 40.500 19.500 41.500 27.500 ;
        RECT 39.500 17.500 41.500 19.500 ;
        RECT 37.500 13.000 39.500 15.000 ;
        RECT 37.500 11.500 38.500 13.000 ;
        RECT 35.000 10.500 38.500 11.500 ;
        RECT 42.500 12.500 43.500 27.500 ;
        RECT 49.000 17.500 50.000 27.500 ;
        RECT 52.000 19.500 53.000 27.500 ;
        RECT 51.000 17.500 53.000 19.500 ;
        RECT 48.000 15.500 50.000 17.500 ;
        RECT 42.500 10.500 45.000 12.500 ;
        RECT 32.500 8.000 34.000 9.000 ;
        RECT 33.000 1.500 34.000 8.000 ;
        RECT 35.000 1.500 36.000 10.500 ;
        RECT 42.500 8.000 43.500 10.500 ;
        RECT 48.000 8.000 50.000 10.000 ;
        RECT 37.000 6.000 39.000 8.000 ;
        RECT 38.000 1.500 39.000 6.000 ;
        RECT 41.000 7.000 43.500 8.000 ;
        RECT 41.000 1.500 42.000 7.000 ;
        RECT 49.000 1.500 50.000 8.000 ;
        RECT 51.000 5.500 53.000 7.500 ;
        RECT 52.000 1.500 53.000 5.500 ;
  END
END rff1m2

#--------EOF---------

MACRO rff1m2_r
  CLASS CORE ;
  FOREIGN rff1m2_r ;
  ORIGIN 0.000 0.000 ;
  SIZE 62.500 BY 29.000 ;
  SYMMETRY X Y R90 ;
  SITE core ;
  PIN VDD
    DIRECTION INOUT ;
    USE POWER ;
    SHAPE ABUTMENT ;
    PORT
      LAYER ML1 ;
        RECT -0.500 28.000 63.000 30.000 ;
        RECT 0.500 20.500 2.500 28.000 ;
        RECT 10.000 20.500 12.000 28.000 ;
        RECT 16.500 20.500 18.500 28.000 ;
        RECT 26.500 20.500 28.500 28.000 ;
        RECT 35.000 20.500 37.000 28.000 ;
        RECT 45.000 20.500 47.000 28.000 ;
        RECT 56.500 20.500 58.500 28.000 ;
    END
  END VDD
  PIN VSS
    DIRECTION INOUT ;
    USE GROUND ;
    SHAPE ABUTMENT ;
    PORT
      LAYER ML1 ;
        RECT 0.500 1.000 2.500 4.500 ;
        RECT 10.000 1.000 12.000 4.800 ;
        RECT 16.500 1.000 18.500 4.800 ;
        RECT 26.500 1.000 28.500 4.800 ;
        RECT 32.500 1.000 34.500 4.800 ;
        RECT 42.500 1.000 44.500 4.800 ;
        RECT 48.500 1.000 50.500 4.800 ;
        RECT 56.500 1.000 58.500 4.800 ;
        RECT -0.500 -1.000 63.000 1.000 ;
    END
  END VSS
  PIN QB
    DIRECTION INPUT ;
    USE SIGNAL ;
    PORT
      LAYER ML1 ;
        RECT 53.500 20.500 55.500 26.500 ;
        RECT 54.500 19.500 55.500 20.500 ;
        RECT 54.500 18.500 59.500 19.500 ;
        RECT 57.500 17.500 59.500 18.500 ;
        RECT 58.000 7.500 59.000 17.500 ;
        RECT 57.500 6.500 59.500 7.500 ;
        RECT 54.500 5.500 59.500 6.500 ;
        RECT 54.500 4.500 55.500 5.500 ;
        RECT 53.500 2.500 55.500 4.500 ;
    END
  END QB
  PIN CK
    DIRECTION INPUT ;
    USE SIGNAL ;
    PORT
      LAYER ML2 ;
        RECT 1.000 14.500 3.000 16.500 ;
    END
  END CK
  PIN D
    DIRECTION INPUT ;
    USE SIGNAL ;
    PORT
      LAYER ML2 ;
        RECT 17.500 9.000 19.500 11.000 ;
    END
  END D
  PIN R
    DIRECTION INPUT ;
    USE SIGNAL ;
    PORT
      LAYER ML2 ;
        RECT 49.500 10.500 51.500 12.500 ;
    END
  END R
  PIN Q
    DIRECTION INPUT ;
    USE SIGNAL ;
    PORT
      LAYER ML2 ;
        RECT 60.000 10.500 62.000 12.500 ;
    END
  END Q
  OBS
      LAYER ML1 ;
        RECT 3.500 20.500 5.500 26.500 ;
        RECT 7.000 20.500 9.000 26.500 ;
        RECT 13.000 20.500 15.000 26.500 ;
        RECT 21.500 20.500 23.500 26.500 ;
        RECT 31.500 20.500 33.500 26.500 ;
        RECT 40.000 20.500 42.000 26.500 ;
        RECT 50.000 20.500 52.000 26.500 ;
        RECT 59.500 20.500 61.500 26.500 ;
        RECT 1.000 14.500 3.000 16.500 ;
        RECT 4.000 14.000 5.000 20.500 ;
        RECT 7.500 19.000 8.500 20.500 ;
        RECT 11.000 19.000 13.000 19.500 ;
        RECT 7.500 18.000 13.000 19.000 ;
        RECT 4.000 12.000 6.500 14.000 ;
        RECT 7.500 13.500 8.500 18.000 ;
        RECT 11.000 17.500 13.000 18.000 ;
        RECT 14.000 16.500 15.000 20.500 ;
        RECT 22.000 19.500 23.000 20.500 ;
        RECT 32.000 19.500 33.000 20.500 ;
        RECT 40.500 19.500 41.500 20.500 ;
        RECT 22.000 18.500 29.500 19.500 ;
        RECT 32.000 18.500 36.000 19.500 ;
        RECT 40.500 18.500 48.000 19.500 ;
        RECT 27.500 17.500 29.500 18.500 ;
        RECT 34.000 17.500 36.000 18.500 ;
        RECT 46.000 17.500 48.000 18.500 ;
        RECT 51.000 17.500 52.000 20.500 ;
        RECT 22.500 16.500 24.500 17.000 ;
        RECT 38.500 16.500 40.500 17.500 ;
        RECT 13.500 15.500 40.500 16.500 ;
        RECT 51.000 16.500 56.500 17.500 ;
        RECT 10.500 13.500 12.500 14.000 ;
        RECT 7.500 12.500 12.500 13.500 ;
        RECT 4.000 4.500 5.000 12.000 ;
        RECT 7.500 7.000 8.500 12.500 ;
        RECT 10.500 12.000 12.500 12.500 ;
        RECT 13.500 10.000 14.500 15.500 ;
        RECT 22.500 15.000 24.500 15.500 ;
        RECT 44.000 14.500 46.000 15.000 ;
        RECT 51.000 14.500 52.000 16.500 ;
        RECT 54.500 15.500 56.500 16.500 ;
        RECT 15.500 13.500 17.500 14.000 ;
        RECT 20.500 13.500 22.500 14.000 ;
        RECT 35.500 13.500 37.500 14.000 ;
        RECT 41.000 13.500 43.000 14.500 ;
        RECT 15.500 12.500 43.000 13.500 ;
        RECT 44.000 13.500 55.500 14.500 ;
        RECT 44.000 13.000 46.000 13.500 ;
        RECT 15.500 12.000 17.500 12.500 ;
        RECT 20.500 12.000 22.500 12.500 ;
        RECT 35.500 12.000 37.500 12.500 ;
        RECT 13.500 9.000 15.000 10.000 ;
        RECT 17.500 9.000 19.500 11.000 ;
        RECT 27.500 10.500 29.500 11.000 ;
        RECT 23.500 9.500 29.500 10.500 ;
        RECT 11.000 7.000 13.000 7.500 ;
        RECT 7.500 6.000 13.000 7.000 ;
        RECT 7.500 4.500 8.500 6.000 ;
        RECT 11.000 5.500 13.000 6.000 ;
        RECT 14.000 7.000 15.000 9.000 ;
        RECT 20.500 7.000 22.500 7.500 ;
        RECT 14.000 6.000 22.500 7.000 ;
        RECT 14.000 4.500 15.000 6.000 ;
        RECT 20.500 5.500 22.500 6.000 ;
        RECT 23.500 4.500 24.500 9.500 ;
        RECT 27.500 9.000 29.500 9.500 ;
        RECT 31.000 10.500 33.000 11.000 ;
        RECT 49.500 10.500 51.500 12.500 ;
        RECT 31.000 9.500 51.500 10.500 ;
        RECT 54.500 10.000 55.500 13.500 ;
        RECT 60.500 12.500 61.500 20.500 ;
        RECT 60.000 10.500 62.000 12.500 ;
        RECT 31.000 9.000 33.000 9.500 ;
        RECT 54.500 9.000 56.500 10.000 ;
        RECT 52.500 8.000 56.500 9.000 ;
        RECT 25.500 7.000 27.500 8.000 ;
        RECT 33.500 7.000 35.500 8.000 ;
        RECT 43.500 7.000 45.500 8.000 ;
        RECT 25.500 6.000 35.500 7.000 ;
        RECT 38.500 6.000 45.500 7.000 ;
        RECT 52.500 6.500 53.500 8.000 ;
        RECT 30.000 4.500 31.000 6.000 ;
        RECT 38.500 4.500 39.500 6.000 ;
        RECT 46.500 5.500 53.500 6.500 ;
        RECT 46.500 4.500 47.500 5.500 ;
        RECT 60.500 4.500 61.500 10.500 ;
        RECT 3.500 2.500 5.500 4.500 ;
        RECT 7.000 2.500 9.000 4.500 ;
        RECT 13.000 2.500 15.000 4.500 ;
        RECT 21.500 3.500 24.500 4.500 ;
        RECT 21.500 2.500 23.500 3.500 ;
        RECT 29.500 2.500 31.500 4.500 ;
        RECT 37.500 2.500 39.500 4.500 ;
        RECT 45.500 2.500 47.500 4.500 ;
        RECT 59.500 2.500 61.500 4.500 ;
      LAYER ML2 ;
        RECT 27.500 17.500 29.500 19.500 ;
        RECT 34.000 17.500 36.000 19.500 ;
        RECT 46.000 17.500 48.000 19.500 ;
        RECT 28.000 11.000 29.000 17.500 ;
        RECT 27.500 9.000 29.500 11.000 ;
        RECT 34.000 8.000 35.000 17.500 ;
        RECT 46.000 16.500 47.000 17.500 ;
        RECT 44.500 15.500 47.000 16.500 ;
        RECT 44.500 8.000 45.500 15.500 ;
        RECT 33.500 6.000 35.500 8.000 ;
        RECT 43.500 6.000 45.500 8.000 ;
      LAYER POL ;
        RECT 2.500 16.500 3.500 27.500 ;
        RECT 9.000 17.500 10.000 27.500 ;
        RECT 12.000 19.500 13.000 27.500 ;
        RECT 11.000 17.500 13.000 19.500 ;
        RECT 1.000 14.500 3.500 16.500 ;
        RECT 2.500 1.500 3.500 14.500 ;
        RECT 8.500 16.500 10.000 17.500 ;
        RECT 8.500 14.000 9.500 16.500 ;
        RECT 4.500 12.000 9.500 14.000 ;
        RECT 10.500 13.500 12.500 14.000 ;
        RECT 15.500 13.500 17.500 14.000 ;
        RECT 10.500 12.500 17.500 13.500 ;
        RECT 10.500 12.000 12.500 12.500 ;
        RECT 15.500 12.000 17.500 12.500 ;
        RECT 8.500 11.000 9.500 12.000 ;
        RECT 18.500 11.000 19.500 27.500 ;
        RECT 20.500 14.000 21.500 27.500 ;
        RECT 23.500 17.000 24.500 27.500 ;
        RECT 22.500 15.000 24.500 17.000 ;
        RECT 20.500 12.000 22.500 14.000 ;
        RECT 8.500 10.000 10.000 11.000 ;
        RECT 9.000 1.500 10.000 10.000 ;
        RECT 17.500 9.000 19.500 11.000 ;
        RECT 21.500 10.500 22.500 12.000 ;
        RECT 21.500 9.500 24.500 10.500 ;
        RECT 11.000 5.500 13.000 7.500 ;
        RECT 12.000 1.500 13.000 5.500 ;
        RECT 18.500 1.500 19.500 9.000 ;
        RECT 20.500 5.500 22.500 7.500 ;
        RECT 20.500 1.500 21.500 5.500 ;
        RECT 23.500 1.500 24.500 9.500 ;
        RECT 25.500 8.000 26.500 27.500 ;
        RECT 28.500 19.500 29.500 27.500 ;
        RECT 27.500 17.500 29.500 19.500 ;
        RECT 30.500 11.000 31.500 27.500 ;
        RECT 37.000 19.500 38.000 27.500 ;
        RECT 34.000 18.500 38.000 19.500 ;
        RECT 34.000 17.500 36.000 18.500 ;
        RECT 39.000 17.500 40.000 27.500 ;
        RECT 38.500 15.500 40.500 17.500 ;
        RECT 35.500 12.000 37.500 14.000 ;
        RECT 27.500 9.000 29.500 11.000 ;
        RECT 30.500 9.000 33.000 11.000 ;
        RECT 25.500 6.000 27.500 8.000 ;
        RECT 25.500 1.500 26.500 6.000 ;
        RECT 28.500 1.500 29.500 9.000 ;
        RECT 31.500 1.500 32.500 9.000 ;
        RECT 33.500 6.000 35.500 8.000 ;
        RECT 34.500 1.500 35.500 6.000 ;
        RECT 36.500 1.500 37.500 12.000 ;
        RECT 39.000 9.000 40.000 15.500 ;
        RECT 42.000 14.500 43.000 27.500 ;
        RECT 41.000 12.500 43.000 14.500 ;
        RECT 44.000 15.000 45.000 27.500 ;
        RECT 47.000 19.500 48.000 27.500 ;
        RECT 46.000 17.500 48.000 19.500 ;
        RECT 44.000 13.000 46.000 15.000 ;
        RECT 44.000 11.500 45.000 13.000 ;
        RECT 41.500 10.500 45.000 11.500 ;
        RECT 49.000 12.500 50.000 27.500 ;
        RECT 55.500 17.500 56.500 27.500 ;
        RECT 58.500 19.500 59.500 27.500 ;
        RECT 57.500 17.500 59.500 19.500 ;
        RECT 54.500 15.500 56.500 17.500 ;
        RECT 49.000 10.500 51.500 12.500 ;
        RECT 39.000 8.000 40.500 9.000 ;
        RECT 39.500 1.500 40.500 8.000 ;
        RECT 41.500 1.500 42.500 10.500 ;
        RECT 49.000 8.000 50.000 10.500 ;
        RECT 54.500 8.000 56.500 10.000 ;
        RECT 43.500 6.000 45.500 8.000 ;
        RECT 44.500 1.500 45.500 6.000 ;
        RECT 47.500 7.000 50.000 8.000 ;
        RECT 47.500 1.500 48.500 7.000 ;
        RECT 55.500 1.500 56.500 8.000 ;
        RECT 57.500 5.500 59.500 7.500 ;
        RECT 58.500 1.500 59.500 5.500 ;
  END
END rff1m2_r

#--------EOF---------

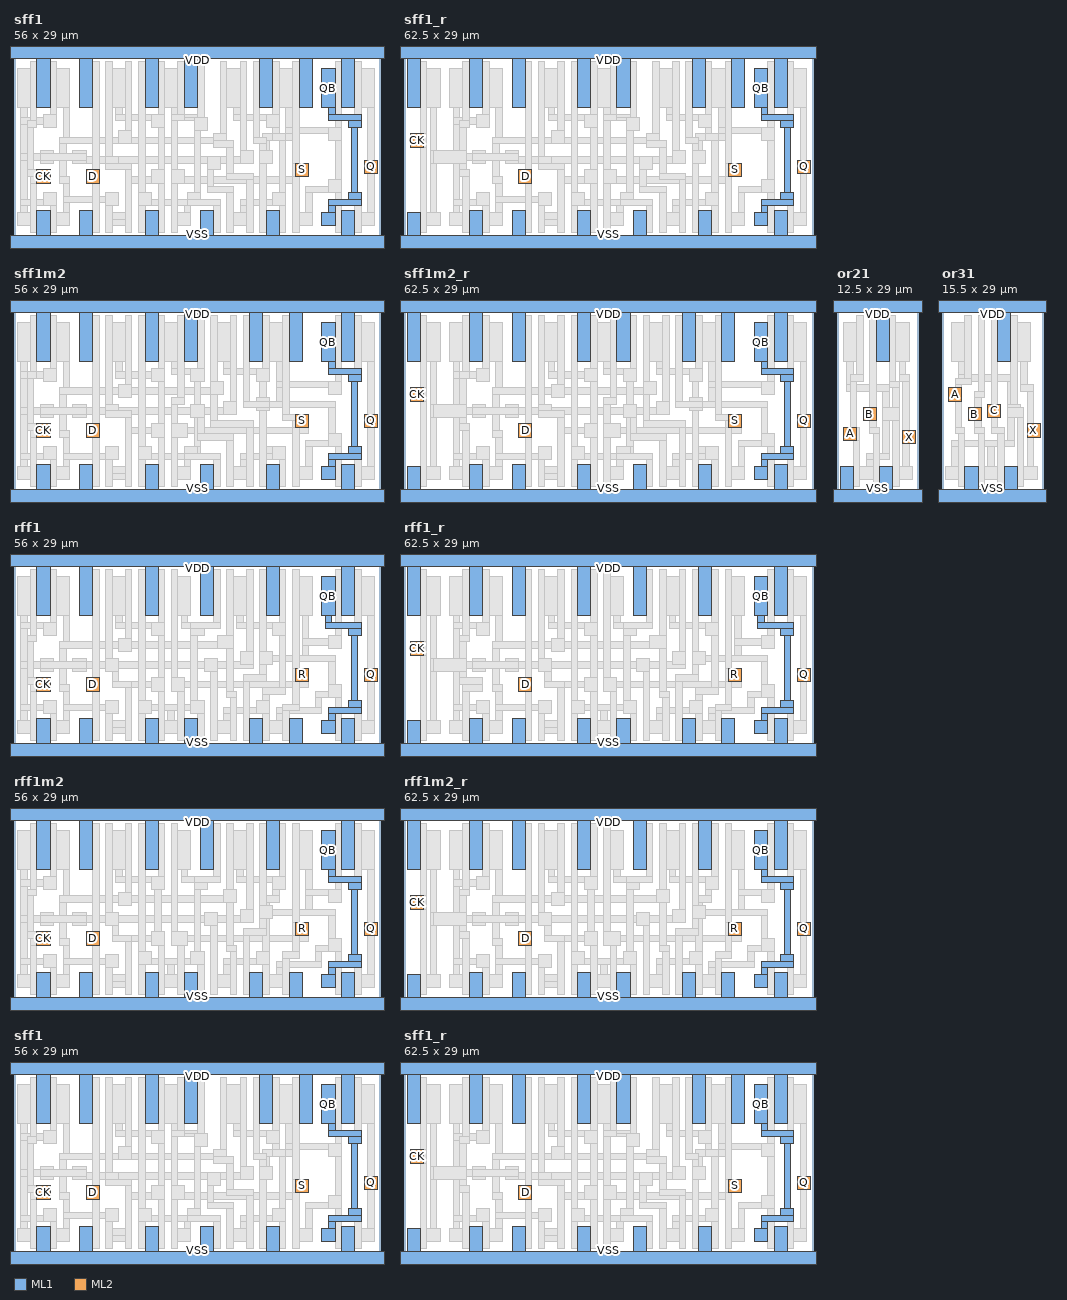
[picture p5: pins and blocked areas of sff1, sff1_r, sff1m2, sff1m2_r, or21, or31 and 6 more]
MACRO sff1
  CLASS CORE ;
  FOREIGN sff1 ;
  ORIGIN 0.000 0.000 ;
  SIZE 56.000 BY 29.000 ;
  SYMMETRY X Y R90 ;
  SITE core ;
  PIN VDD
    DIRECTION INOUT ;
    USE POWER ;
    SHAPE ABUTMENT ;
    PORT
      LAYER ML1 ;
        RECT -0.500 28.000 56.500 30.000 ;
        RECT 3.500 20.500 5.500 28.000 ;
        RECT 10.000 20.500 12.000 28.000 ;
        RECT 20.000 20.500 22.000 28.000 ;
        RECT 26.000 20.500 28.000 28.000 ;
        RECT 37.500 20.500 39.500 28.000 ;
        RECT 43.500 20.500 45.500 28.000 ;
        RECT 50.000 20.500 52.000 28.000 ;
    END
  END VDD
  PIN VSS
    DIRECTION INOUT ;
    USE GROUND ;
    SHAPE ABUTMENT ;
    PORT
      LAYER ML1 ;
        RECT 3.500 1.000 5.500 4.800 ;
        RECT 10.000 1.000 12.000 4.800 ;
        RECT 20.000 1.000 22.000 4.800 ;
        RECT 28.500 1.000 30.500 4.800 ;
        RECT 38.500 1.000 40.500 4.800 ;
        RECT 50.000 1.000 52.000 4.800 ;
        RECT -0.500 -1.000 56.500 1.000 ;
    END
  END VSS
  PIN QB
    DIRECTION INPUT ;
    USE SIGNAL ;
    PORT
      LAYER ML1 ;
        RECT 47.000 20.500 49.000 26.500 ;
        RECT 48.000 19.500 49.000 20.500 ;
        RECT 48.000 18.500 53.000 19.500 ;
        RECT 51.000 17.500 53.000 18.500 ;
        RECT 51.500 7.500 52.500 17.500 ;
        RECT 51.000 6.500 53.000 7.500 ;
        RECT 48.000 5.500 53.000 6.500 ;
        RECT 48.000 4.500 49.000 5.500 ;
        RECT 47.000 2.500 49.000 4.500 ;
    END
  END QB
  PIN CK
    DIRECTION INPUT ;
    USE SIGNAL ;
    PORT
      LAYER ML2 ;
        RECT 3.500 9.000 5.500 11.000 ;
    END
  END CK
  PIN D
    DIRECTION INPUT ;
    USE SIGNAL ;
    PORT
      LAYER ML2 ;
        RECT 11.000 9.000 13.000 11.000 ;
    END
  END D
  PIN S
    DIRECTION INPUT ;
    USE SIGNAL ;
    PORT
      LAYER ML2 ;
        RECT 43.000 10.000 45.000 12.000 ;
    END
  END S
  PIN Q
    DIRECTION INPUT ;
    USE SIGNAL ;
    PORT
      LAYER ML2 ;
        RECT 53.500 10.500 55.500 12.500 ;
    END
  END Q
  OBS
      LAYER ML1 ;
        RECT 0.500 20.500 2.500 26.500 ;
        RECT 6.500 20.500 8.500 26.500 ;
        RECT 15.000 20.500 17.000 26.500 ;
        RECT 23.000 20.500 25.000 26.500 ;
        RECT 32.500 20.500 34.500 26.500 ;
        RECT 40.500 20.500 42.500 26.500 ;
        RECT 53.000 20.500 55.000 26.500 ;
        RECT 1.000 19.000 2.000 20.500 ;
        RECT 4.500 19.000 6.500 19.500 ;
        RECT 1.000 18.000 6.500 19.000 ;
        RECT 1.000 13.500 2.000 18.000 ;
        RECT 4.500 17.500 6.500 18.000 ;
        RECT 7.500 16.000 8.500 20.500 ;
        RECT 15.500 19.500 16.500 20.500 ;
        RECT 24.000 19.500 25.000 20.500 ;
        RECT 33.500 19.500 34.500 20.500 ;
        RECT 15.500 18.500 23.000 19.500 ;
        RECT 24.000 19.000 29.000 19.500 ;
        RECT 24.000 18.500 29.500 19.000 ;
        RECT 33.500 18.500 40.500 19.500 ;
        RECT 21.000 17.500 23.000 18.500 ;
        RECT 27.500 17.000 29.500 18.500 ;
        RECT 38.500 17.500 40.500 18.500 ;
        RECT 41.500 17.500 42.500 20.500 ;
        RECT 16.000 16.000 18.000 17.000 ;
        RECT 41.500 16.500 50.000 17.500 ;
        RECT 30.500 16.000 32.500 16.500 ;
        RECT 7.000 15.000 32.500 16.000 ;
        RECT 4.000 13.500 6.000 14.000 ;
        RECT 1.000 12.500 6.000 13.500 ;
        RECT 1.000 6.500 2.000 12.500 ;
        RECT 4.000 12.000 6.000 12.500 ;
        RECT 3.500 9.000 5.500 11.000 ;
        RECT 7.000 10.000 8.000 15.000 ;
        RECT 30.500 14.500 32.500 15.000 ;
        RECT 38.000 15.500 42.500 16.500 ;
        RECT 48.000 15.500 50.000 16.500 ;
        RECT 38.000 14.000 39.000 15.500 ;
        RECT 9.000 13.000 11.000 14.000 ;
        RECT 34.500 13.000 36.500 14.000 ;
        RECT 9.000 12.000 36.500 13.000 ;
        RECT 37.500 12.000 39.500 14.000 ;
        RECT 14.000 11.000 16.000 12.000 ;
        RECT 29.500 11.000 31.500 12.000 ;
        RECT 7.000 9.000 8.500 10.000 ;
        RECT 11.000 9.000 13.000 11.000 ;
        RECT 21.000 10.000 23.000 11.000 ;
        RECT 17.000 9.000 23.000 10.000 ;
        RECT 24.000 10.000 26.000 11.000 ;
        RECT 42.500 10.000 45.000 12.000 ;
        RECT 24.000 9.000 43.500 10.000 ;
        RECT 49.000 9.500 50.000 15.500 ;
        RECT 54.000 12.500 55.000 20.500 ;
        RECT 53.500 10.500 55.500 12.500 ;
        RECT 4.500 6.500 6.500 7.500 ;
        RECT 1.000 5.500 6.500 6.500 ;
        RECT 7.500 7.000 8.500 9.000 ;
        RECT 14.000 7.000 16.000 7.500 ;
        RECT 7.500 6.000 16.000 7.000 ;
        RECT 1.000 4.500 2.000 5.500 ;
        RECT 7.500 4.500 8.500 6.000 ;
        RECT 14.000 5.500 16.000 6.000 ;
        RECT 17.000 4.500 18.000 9.000 ;
        RECT 48.000 8.500 50.000 9.500 ;
        RECT 44.500 7.500 50.000 8.500 ;
        RECT 19.000 6.500 21.000 7.500 ;
        RECT 26.500 6.500 28.500 7.500 ;
        RECT 39.500 6.500 41.500 7.500 ;
        RECT 19.000 5.500 28.500 6.500 ;
        RECT 34.500 5.500 41.500 6.500 ;
        RECT 26.000 4.500 27.000 5.500 ;
        RECT 34.500 4.500 35.500 5.500 ;
        RECT 44.500 4.500 45.500 7.500 ;
        RECT 54.000 4.500 55.000 10.500 ;
        RECT 0.500 2.500 2.500 4.500 ;
        RECT 6.500 2.500 8.500 4.500 ;
        RECT 15.000 3.500 18.000 4.500 ;
        RECT 15.000 2.500 17.000 3.500 ;
        RECT 25.000 2.500 27.000 4.500 ;
        RECT 33.500 2.500 35.500 4.500 ;
        RECT 43.500 2.500 45.500 4.500 ;
        RECT 53.000 2.500 55.000 4.500 ;
      LAYER POL ;
        RECT 2.500 18.500 3.500 27.500 ;
        RECT 5.500 19.500 6.500 27.500 ;
        RECT 2.000 17.500 3.500 18.500 ;
        RECT 4.500 17.500 6.500 19.500 ;
        RECT 2.000 11.000 3.000 17.500 ;
        RECT 4.000 13.500 6.000 14.000 ;
        RECT 9.000 13.500 11.000 14.000 ;
        RECT 4.000 12.500 11.000 13.500 ;
        RECT 4.000 12.000 6.000 12.500 ;
        RECT 9.000 12.000 11.000 12.500 ;
        RECT 12.000 11.000 13.000 27.500 ;
        RECT 14.000 13.000 15.000 27.500 ;
        RECT 17.000 17.000 18.000 27.500 ;
        RECT 16.000 15.000 18.000 17.000 ;
        RECT 14.000 12.000 16.000 13.000 ;
        RECT 14.000 11.000 18.000 12.000 ;
        RECT 2.000 10.000 5.500 11.000 ;
        RECT 2.500 9.000 5.500 10.000 ;
        RECT 11.000 9.000 13.000 11.000 ;
        RECT 2.500 1.500 3.500 9.000 ;
        RECT 4.500 5.500 6.500 7.500 ;
        RECT 5.500 1.500 6.500 5.500 ;
        RECT 12.000 1.500 13.000 9.000 ;
        RECT 14.000 5.500 16.000 7.500 ;
        RECT 14.000 1.500 15.000 5.500 ;
        RECT 17.000 1.500 18.000 11.000 ;
        RECT 19.000 7.500 20.000 27.500 ;
        RECT 22.000 19.500 23.000 27.500 ;
        RECT 25.000 19.500 26.000 27.500 ;
        RECT 21.000 17.500 23.000 19.500 ;
        RECT 22.000 11.000 23.000 17.500 ;
        RECT 21.000 9.000 23.000 11.000 ;
        RECT 19.000 5.500 21.000 7.500 ;
        RECT 19.000 1.500 20.000 5.500 ;
        RECT 22.000 1.500 23.000 9.000 ;
        RECT 24.000 18.500 26.000 19.500 ;
        RECT 28.000 19.000 29.000 27.500 ;
        RECT 24.000 11.000 25.000 18.500 ;
        RECT 27.500 17.000 29.500 19.000 ;
        RECT 24.000 9.000 26.000 11.000 ;
        RECT 24.000 1.500 25.000 9.000 ;
        RECT 27.500 7.500 28.500 17.000 ;
        RECT 31.500 16.500 32.500 27.500 ;
        RECT 30.500 15.500 32.500 16.500 ;
        RECT 30.500 14.500 33.500 15.500 ;
        RECT 29.500 11.000 31.500 13.000 ;
        RECT 29.500 8.500 30.500 11.000 ;
        RECT 32.500 10.500 33.500 14.500 ;
        RECT 34.500 14.000 35.500 27.500 ;
        RECT 36.500 16.000 37.500 27.500 ;
        RECT 39.500 19.500 40.500 27.500 ;
        RECT 38.500 17.500 40.500 19.500 ;
        RECT 39.500 16.500 40.500 17.500 ;
        RECT 36.500 15.000 38.500 16.000 ;
        RECT 39.500 15.500 41.500 16.500 ;
        RECT 37.500 14.000 38.500 15.000 ;
        RECT 34.500 12.000 36.500 14.000 ;
        RECT 37.500 12.000 39.500 14.000 ;
        RECT 32.500 9.500 36.500 10.500 ;
        RECT 29.500 7.500 33.500 8.500 ;
        RECT 26.500 6.500 28.500 7.500 ;
        RECT 26.500 5.500 31.500 6.500 ;
        RECT 30.500 1.500 31.500 5.500 ;
        RECT 32.500 1.500 33.500 7.500 ;
        RECT 35.500 1.500 36.500 9.500 ;
        RECT 37.500 1.500 38.500 12.000 ;
        RECT 40.500 7.500 41.500 15.500 ;
        RECT 39.500 5.500 41.500 7.500 ;
        RECT 40.500 1.500 41.500 5.500 ;
        RECT 42.500 12.000 43.500 27.500 ;
        RECT 49.000 17.500 50.000 27.500 ;
        RECT 52.000 19.500 53.000 27.500 ;
        RECT 51.000 17.500 53.000 19.500 ;
        RECT 48.000 15.500 50.000 17.500 ;
        RECT 42.500 10.000 45.000 12.000 ;
        RECT 42.500 1.500 43.500 10.000 ;
        RECT 48.000 7.500 50.000 9.500 ;
        RECT 49.000 1.500 50.000 7.500 ;
        RECT 51.000 5.500 53.000 7.500 ;
        RECT 52.000 1.500 53.000 5.500 ;
  END
END sff1

#--------EOF---------

MACRO sff1_r
  CLASS CORE ;
  FOREIGN sff1_r ;
  ORIGIN 0.000 0.000 ;
  SIZE 62.500 BY 29.000 ;
  SYMMETRY X Y R90 ;
  SITE core ;
  PIN QB
    DIRECTION INPUT ;
    USE SIGNAL ;
    PORT
      LAYER ML1 ;
        RECT 53.500 20.500 55.500 26.500 ;
        RECT 54.500 19.500 55.500 20.500 ;
        RECT 54.500 18.500 59.500 19.500 ;
        RECT 57.500 17.500 59.500 18.500 ;
        RECT 58.000 7.500 59.000 17.500 ;
        RECT 57.500 6.500 59.500 7.500 ;
        RECT 54.500 5.500 59.500 6.500 ;
        RECT 54.500 4.500 55.500 5.500 ;
        RECT 53.500 2.500 55.500 4.500 ;
    END
  END QB
  PIN VDD
    DIRECTION INOUT ;
    USE POWER ;
    SHAPE ABUTMENT ;
    PORT
      LAYER ML1 ;
        RECT -0.500 28.000 63.000 30.000 ;
        RECT 0.500 20.500 2.500 28.000 ;
        RECT 10.000 20.500 12.000 28.000 ;
        RECT 16.500 20.500 18.500 28.000 ;
        RECT 26.500 20.500 28.500 28.000 ;
        RECT 32.500 20.500 34.500 28.000 ;
        RECT 44.000 20.500 46.000 28.000 ;
        RECT 50.000 20.500 52.000 28.000 ;
        RECT 56.500 20.500 58.500 28.000 ;
    END
  END VDD
  PIN VSS
    DIRECTION INOUT ;
    USE GROUND ;
    SHAPE ABUTMENT ;
    PORT
      LAYER ML1 ;
        RECT 0.500 1.000 2.500 4.500 ;
        RECT 10.000 1.000 12.000 4.800 ;
        RECT 16.500 1.000 18.500 4.800 ;
        RECT 26.500 1.000 28.500 4.800 ;
        RECT 35.000 1.000 37.000 4.800 ;
        RECT 45.000 1.000 47.000 4.800 ;
        RECT 56.500 1.000 58.500 4.800 ;
        RECT -0.500 -1.000 63.000 1.000 ;
    END
  END VSS
  PIN D
    DIRECTION INPUT ;
    USE SIGNAL ;
    PORT
      LAYER ML2 ;
        RECT 17.500 9.000 19.500 11.000 ;
    END
  END D
  PIN S
    DIRECTION INPUT ;
    USE SIGNAL ;
    PORT
      LAYER ML2 ;
        RECT 49.500 10.000 51.500 12.000 ;
    END
  END S
  PIN Q
    DIRECTION INPUT ;
    USE SIGNAL ;
    PORT
      LAYER ML2 ;
        RECT 60.000 10.500 62.000 12.500 ;
    END
  END Q
  PIN CK
    DIRECTION INPUT ;
    USE SIGNAL ;
    PORT
      LAYER ML2 ;
        RECT 1.000 14.500 3.000 16.500 ;
    END
  END CK
  OBS
      LAYER ML1 ;
        RECT 3.500 20.500 5.500 26.500 ;
        RECT 7.000 20.500 9.000 26.500 ;
        RECT 13.000 20.500 15.000 26.500 ;
        RECT 21.500 20.500 23.500 26.500 ;
        RECT 29.500 20.500 31.500 26.500 ;
        RECT 39.000 20.500 41.000 26.500 ;
        RECT 47.000 20.500 49.000 26.500 ;
        RECT 59.500 20.500 61.500 26.500 ;
        RECT 1.000 14.500 3.000 16.500 ;
        RECT 4.000 14.000 5.000 20.500 ;
        RECT 7.500 19.000 8.500 20.500 ;
        RECT 11.000 19.000 13.000 19.500 ;
        RECT 7.500 18.000 13.000 19.000 ;
        RECT 4.000 12.000 6.500 14.000 ;
        RECT 7.500 13.500 8.500 18.000 ;
        RECT 11.000 17.500 13.000 18.000 ;
        RECT 14.000 16.000 15.000 20.500 ;
        RECT 22.000 19.500 23.000 20.500 ;
        RECT 30.500 19.500 31.500 20.500 ;
        RECT 40.000 19.500 41.000 20.500 ;
        RECT 22.000 18.500 29.500 19.500 ;
        RECT 30.500 19.000 35.500 19.500 ;
        RECT 30.500 18.500 36.000 19.000 ;
        RECT 40.000 18.500 47.000 19.500 ;
        RECT 27.500 17.500 29.500 18.500 ;
        RECT 34.000 17.000 36.000 18.500 ;
        RECT 45.000 17.500 47.000 18.500 ;
        RECT 48.000 17.500 49.000 20.500 ;
        RECT 22.500 16.000 24.500 17.000 ;
        RECT 48.000 16.500 56.500 17.500 ;
        RECT 37.000 16.000 39.000 16.500 ;
        RECT 13.500 15.000 39.000 16.000 ;
        RECT 10.500 13.500 12.500 14.000 ;
        RECT 7.500 12.500 12.500 13.500 ;
        RECT 4.000 4.500 5.000 12.000 ;
        RECT 7.500 6.500 8.500 12.500 ;
        RECT 10.500 12.000 12.500 12.500 ;
        RECT 13.500 10.000 14.500 15.000 ;
        RECT 37.000 14.500 39.000 15.000 ;
        RECT 44.500 15.500 49.000 16.500 ;
        RECT 54.500 15.500 56.500 16.500 ;
        RECT 44.500 14.000 45.500 15.500 ;
        RECT 15.500 13.000 17.500 14.000 ;
        RECT 41.000 13.000 43.000 14.000 ;
        RECT 15.500 12.000 43.000 13.000 ;
        RECT 44.000 12.000 46.000 14.000 ;
        RECT 20.500 11.000 22.500 12.000 ;
        RECT 36.000 11.000 38.000 12.000 ;
        RECT 13.500 9.000 15.000 10.000 ;
        RECT 17.500 9.000 19.500 11.000 ;
        RECT 27.500 10.000 29.500 11.000 ;
        RECT 23.500 9.000 29.500 10.000 ;
        RECT 30.500 10.000 32.500 11.000 ;
        RECT 49.000 10.000 51.500 12.000 ;
        RECT 30.500 9.000 50.000 10.000 ;
        RECT 55.500 9.500 56.500 15.500 ;
        RECT 60.500 12.500 61.500 20.500 ;
        RECT 60.000 10.500 62.000 12.500 ;
        RECT 11.000 6.500 13.000 7.500 ;
        RECT 7.500 5.500 13.000 6.500 ;
        RECT 14.000 7.000 15.000 9.000 ;
        RECT 20.500 7.000 22.500 7.500 ;
        RECT 14.000 6.000 22.500 7.000 ;
        RECT 7.500 4.500 8.500 5.500 ;
        RECT 14.000 4.500 15.000 6.000 ;
        RECT 20.500 5.500 22.500 6.000 ;
        RECT 23.500 4.500 24.500 9.000 ;
        RECT 54.500 8.500 56.500 9.500 ;
        RECT 51.000 7.500 56.500 8.500 ;
        RECT 25.500 6.500 27.500 7.500 ;
        RECT 33.000 6.500 35.000 7.500 ;
        RECT 46.000 6.500 48.000 7.500 ;
        RECT 25.500 5.500 35.000 6.500 ;
        RECT 41.000 5.500 48.000 6.500 ;
        RECT 32.500 4.500 33.500 5.500 ;
        RECT 41.000 4.500 42.000 5.500 ;
        RECT 51.000 4.500 52.000 7.500 ;
        RECT 60.500 4.500 61.500 10.500 ;
        RECT 3.500 2.500 5.500 4.500 ;
        RECT 7.000 2.500 9.000 4.500 ;
        RECT 13.000 2.500 15.000 4.500 ;
        RECT 21.500 3.500 24.500 4.500 ;
        RECT 21.500 2.500 23.500 3.500 ;
        RECT 31.500 2.500 33.500 4.500 ;
        RECT 40.000 2.500 42.000 4.500 ;
        RECT 50.000 2.500 52.000 4.500 ;
        RECT 59.500 2.500 61.500 4.500 ;
      LAYER POL ;
        RECT 2.500 16.500 3.500 27.500 ;
        RECT 9.000 18.500 10.000 27.500 ;
        RECT 12.000 19.500 13.000 27.500 ;
        RECT 1.000 14.500 3.500 16.500 ;
        RECT 2.500 1.500 3.500 14.500 ;
        RECT 8.500 17.500 10.000 18.500 ;
        RECT 11.000 17.500 13.000 19.500 ;
        RECT 8.500 14.000 9.500 17.500 ;
        RECT 4.500 12.000 9.500 14.000 ;
        RECT 10.500 13.500 12.500 14.000 ;
        RECT 15.500 13.500 17.500 14.000 ;
        RECT 10.500 12.500 17.500 13.500 ;
        RECT 10.500 12.000 12.500 12.500 ;
        RECT 15.500 12.000 17.500 12.500 ;
        RECT 8.500 11.000 9.500 12.000 ;
        RECT 18.500 11.000 19.500 27.500 ;
        RECT 20.500 13.000 21.500 27.500 ;
        RECT 23.500 17.000 24.500 27.500 ;
        RECT 22.500 15.000 24.500 17.000 ;
        RECT 20.500 12.000 22.500 13.000 ;
        RECT 20.500 11.000 24.500 12.000 ;
        RECT 8.500 10.000 10.000 11.000 ;
        RECT 9.000 1.500 10.000 10.000 ;
        RECT 17.500 9.000 19.500 11.000 ;
        RECT 11.000 5.500 13.000 7.500 ;
        RECT 12.000 1.500 13.000 5.500 ;
        RECT 18.500 1.500 19.500 9.000 ;
        RECT 20.500 5.500 22.500 7.500 ;
        RECT 20.500 1.500 21.500 5.500 ;
        RECT 23.500 1.500 24.500 11.000 ;
        RECT 25.500 7.500 26.500 27.500 ;
        RECT 28.500 19.500 29.500 27.500 ;
        RECT 31.500 19.500 32.500 27.500 ;
        RECT 27.500 17.500 29.500 19.500 ;
        RECT 28.500 11.000 29.500 17.500 ;
        RECT 27.500 9.000 29.500 11.000 ;
        RECT 25.500 5.500 27.500 7.500 ;
        RECT 25.500 1.500 26.500 5.500 ;
        RECT 28.500 1.500 29.500 9.000 ;
        RECT 30.500 18.500 32.500 19.500 ;
        RECT 34.500 19.000 35.500 27.500 ;
        RECT 30.500 11.000 31.500 18.500 ;
        RECT 34.000 17.000 36.000 19.000 ;
        RECT 30.500 9.000 32.500 11.000 ;
        RECT 30.500 1.500 31.500 9.000 ;
        RECT 34.000 7.500 35.000 17.000 ;
        RECT 38.000 16.500 39.000 27.500 ;
        RECT 37.000 15.500 39.000 16.500 ;
        RECT 37.000 14.500 40.000 15.500 ;
        RECT 36.000 11.000 38.000 13.000 ;
        RECT 36.000 8.500 37.000 11.000 ;
        RECT 39.000 10.500 40.000 14.500 ;
        RECT 41.000 14.000 42.000 27.500 ;
        RECT 43.000 16.000 44.000 27.500 ;
        RECT 46.000 19.500 47.000 27.500 ;
        RECT 45.000 17.500 47.000 19.500 ;
        RECT 46.000 16.500 47.000 17.500 ;
        RECT 43.000 15.000 45.000 16.000 ;
        RECT 46.000 15.500 48.000 16.500 ;
        RECT 44.000 14.000 45.000 15.000 ;
        RECT 41.000 12.000 43.000 14.000 ;
        RECT 44.000 12.000 46.000 14.000 ;
        RECT 39.000 9.500 43.000 10.500 ;
        RECT 36.000 7.500 40.000 8.500 ;
        RECT 33.000 6.500 35.000 7.500 ;
        RECT 33.000 5.500 38.000 6.500 ;
        RECT 37.000 1.500 38.000 5.500 ;
        RECT 39.000 1.500 40.000 7.500 ;
        RECT 42.000 1.500 43.000 9.500 ;
        RECT 44.000 1.500 45.000 12.000 ;
        RECT 47.000 7.500 48.000 15.500 ;
        RECT 46.000 5.500 48.000 7.500 ;
        RECT 47.000 1.500 48.000 5.500 ;
        RECT 49.000 12.000 50.000 27.500 ;
        RECT 55.500 17.500 56.500 27.500 ;
        RECT 58.500 19.500 59.500 27.500 ;
        RECT 57.500 17.500 59.500 19.500 ;
        RECT 54.500 15.500 56.500 17.500 ;
        RECT 49.000 10.000 51.500 12.000 ;
        RECT 49.000 1.500 50.000 10.000 ;
        RECT 54.500 7.500 56.500 9.500 ;
        RECT 55.500 1.500 56.500 7.500 ;
        RECT 57.500 5.500 59.500 7.500 ;
        RECT 58.500 1.500 59.500 5.500 ;
  END
END sff1_r

#--------EOF---------

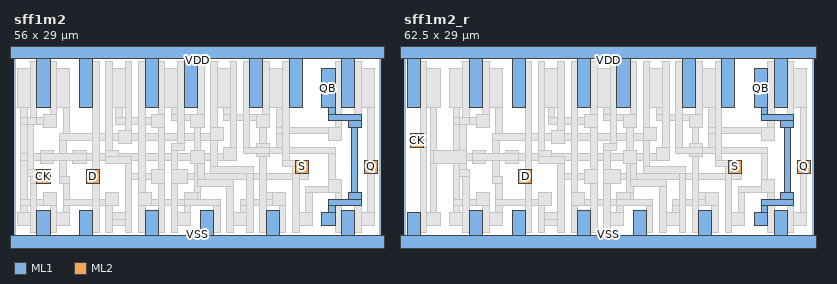
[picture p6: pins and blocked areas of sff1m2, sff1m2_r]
MACRO sff1m2
  CLASS CORE ;
  FOREIGN sff1m2 ;
  ORIGIN 0.000 0.000 ;
  SIZE 56.000 BY 29.000 ;
  SYMMETRY X Y R90 ;
  SITE core ;
  PIN VDD
    DIRECTION INOUT ;
    USE POWER ;
    SHAPE ABUTMENT ;
    PORT
      LAYER ML1 ;
        RECT -0.500 28.000 56.500 30.000 ;
        RECT 3.500 20.500 5.500 28.000 ;
        RECT 10.000 20.500 12.000 28.000 ;
        RECT 20.000 20.500 22.000 28.000 ;
        RECT 26.000 20.500 28.000 28.000 ;
        RECT 36.000 20.500 38.000 28.000 ;
        RECT 42.000 20.500 44.000 28.000 ;
        RECT 50.000 20.500 52.000 28.000 ;
    END
  END VDD
  PIN VSS
    DIRECTION INOUT ;
    USE GROUND ;
    SHAPE ABUTMENT ;
    PORT
      LAYER ML1 ;
        RECT 3.500 1.000 5.500 4.800 ;
        RECT 10.000 1.000 12.000 4.800 ;
        RECT 20.000 1.000 22.000 4.800 ;
        RECT 28.500 1.000 30.500 4.800 ;
        RECT 38.500 1.000 40.500 4.800 ;
        RECT 50.000 1.000 52.000 4.800 ;
        RECT -0.500 -1.000 56.500 1.000 ;
    END
  END VSS
  PIN QB
    DIRECTION INPUT ;
    USE SIGNAL ;
    PORT
      LAYER ML1 ;
        RECT 47.000 20.500 49.000 26.500 ;
        RECT 48.000 19.500 49.000 20.500 ;
        RECT 48.000 18.500 53.000 19.500 ;
        RECT 51.000 17.500 53.000 18.500 ;
        RECT 51.500 7.500 52.500 17.500 ;
        RECT 51.000 6.500 53.000 7.500 ;
        RECT 48.000 5.500 53.000 6.500 ;
        RECT 48.000 4.500 49.000 5.500 ;
        RECT 47.000 2.500 49.000 4.500 ;
    END
  END QB
  PIN Q
    DIRECTION INPUT ;
    USE SIGNAL ;
    PORT
      LAYER ML2 ;
        RECT 53.500 10.500 55.500 12.500 ;
    END
  END Q
  PIN S
    DIRECTION INPUT ;
    USE SIGNAL ;
    PORT
      LAYER ML2 ;
        RECT 43.000 10.500 45.000 12.500 ;
    END
  END S
  PIN D
    DIRECTION INPUT ;
    USE SIGNAL ;
    PORT
      LAYER ML2 ;
        RECT 11.000 9.000 13.000 11.000 ;
    END
  END D
  PIN CK
    DIRECTION INPUT ;
    USE SIGNAL ;
    PORT
      LAYER ML2 ;
        RECT 3.500 9.000 5.500 11.000 ;
    END
  END CK
  OBS
      LAYER ML1 ;
        RECT 0.500 20.500 2.500 26.500 ;
        RECT 6.500 20.500 8.500 26.500 ;
        RECT 15.000 20.500 17.000 26.500 ;
        RECT 23.000 20.500 25.000 26.500 ;
        RECT 31.000 20.500 33.000 26.500 ;
        RECT 39.000 20.500 41.000 26.500 ;
        RECT 53.000 20.500 55.000 26.500 ;
        RECT 1.000 19.000 2.000 20.500 ;
        RECT 4.500 19.000 6.500 19.500 ;
        RECT 1.000 18.000 6.500 19.000 ;
        RECT 1.000 13.500 2.000 18.000 ;
        RECT 4.500 17.500 6.500 18.000 ;
        RECT 7.500 16.500 8.500 20.500 ;
        RECT 15.500 19.000 16.500 20.500 ;
        RECT 24.000 19.500 25.000 20.500 ;
        RECT 32.000 19.500 33.000 20.500 ;
        RECT 21.000 19.000 23.000 19.500 ;
        RECT 15.500 18.000 23.000 19.000 ;
        RECT 24.000 18.500 29.000 19.500 ;
        RECT 32.000 18.500 39.000 19.500 ;
        RECT 21.000 17.500 23.000 18.000 ;
        RECT 27.000 17.500 29.000 18.500 ;
        RECT 37.000 17.500 39.000 18.500 ;
        RECT 40.000 17.500 41.000 20.500 ;
        RECT 16.000 16.500 18.000 17.000 ;
        RECT 30.000 16.500 32.000 17.500 ;
        RECT 7.000 15.500 32.000 16.500 ;
        RECT 40.000 16.500 50.000 17.500 ;
        RECT 4.000 13.500 6.000 14.000 ;
        RECT 1.000 12.500 6.000 13.500 ;
        RECT 1.000 6.500 2.000 12.500 ;
        RECT 4.000 12.000 6.000 12.500 ;
        RECT 3.500 9.000 5.500 11.000 ;
        RECT 7.000 10.000 8.000 15.500 ;
        RECT 16.000 15.000 18.000 15.500 ;
        RECT 37.000 14.500 39.000 15.000 ;
        RECT 40.000 14.500 41.000 16.500 ;
        RECT 48.000 15.500 50.000 16.500 ;
        RECT 9.000 13.500 11.000 14.000 ;
        RECT 14.000 13.500 16.000 14.000 ;
        RECT 27.000 13.500 29.000 14.000 ;
        RECT 32.000 13.500 34.000 14.500 ;
        RECT 9.000 12.500 34.000 13.500 ;
        RECT 37.000 13.500 49.000 14.500 ;
        RECT 37.000 13.000 39.000 13.500 ;
        RECT 9.000 12.000 11.000 12.500 ;
        RECT 14.000 12.000 16.000 12.500 ;
        RECT 27.000 12.000 29.000 12.500 ;
        RECT 7.000 9.000 8.500 10.000 ;
        RECT 11.000 9.000 13.000 11.000 ;
        RECT 21.000 10.500 23.000 11.000 ;
        RECT 17.000 9.500 23.000 10.500 ;
        RECT 4.500 6.500 6.500 7.500 ;
        RECT 1.000 5.500 6.500 6.500 ;
        RECT 7.500 6.500 8.500 9.000 ;
        RECT 14.000 6.500 16.000 7.500 ;
        RECT 7.500 5.500 16.000 6.500 ;
        RECT 1.000 4.500 2.000 5.500 ;
        RECT 7.500 4.500 8.500 5.500 ;
        RECT 17.000 4.500 18.000 9.500 ;
        RECT 21.000 9.000 23.000 9.500 ;
        RECT 24.500 10.500 26.500 11.000 ;
        RECT 43.000 10.500 45.000 12.500 ;
        RECT 24.500 9.500 45.000 10.500 ;
        RECT 48.000 9.500 49.000 13.500 ;
        RECT 54.000 12.500 55.000 20.500 ;
        RECT 53.500 10.500 55.500 12.500 ;
        RECT 24.500 9.000 26.500 9.500 ;
        RECT 48.000 8.500 50.000 9.500 ;
        RECT 44.500 7.500 50.000 8.500 ;
        RECT 19.000 6.500 21.000 7.500 ;
        RECT 26.000 6.500 28.000 7.500 ;
        RECT 39.500 6.500 41.500 7.500 ;
        RECT 19.000 5.500 28.000 6.500 ;
        RECT 34.500 5.500 41.500 6.500 ;
        RECT 26.000 4.500 27.000 5.500 ;
        RECT 34.500 4.500 35.500 5.500 ;
        RECT 44.500 4.500 45.500 7.500 ;
        RECT 54.000 4.500 55.000 10.500 ;
        RECT 0.500 2.500 2.500 4.500 ;
        RECT 6.500 2.500 8.500 4.500 ;
        RECT 15.000 3.500 18.000 4.500 ;
        RECT 15.000 2.500 17.000 3.500 ;
        RECT 25.000 2.500 27.000 4.500 ;
        RECT 33.500 2.500 35.500 4.500 ;
        RECT 43.500 2.500 45.500 4.500 ;
        RECT 53.000 2.500 55.000 4.500 ;
      LAYER ML2 ;
        RECT 21.000 17.500 23.000 19.500 ;
        RECT 27.000 17.500 29.000 19.500 ;
        RECT 37.000 17.500 39.000 19.500 ;
        RECT 22.000 11.000 23.000 17.500 ;
        RECT 21.000 9.000 23.000 11.000 ;
        RECT 27.500 7.500 28.500 17.500 ;
        RECT 26.000 5.500 28.500 7.500 ;
        RECT 37.500 7.500 38.500 17.500 ;
        RECT 37.500 6.500 41.500 7.500 ;
        RECT 39.500 5.500 41.500 6.500 ;
      LAYER POL ;
        RECT 2.500 19.000 3.500 27.500 ;
        RECT 5.500 19.500 6.500 27.500 ;
        RECT 2.000 18.000 3.500 19.000 ;
        RECT 2.000 11.000 3.000 18.000 ;
        RECT 4.500 17.500 6.500 19.500 ;
        RECT 4.000 13.500 6.000 14.000 ;
        RECT 9.000 13.500 11.000 14.000 ;
        RECT 4.000 12.500 11.000 13.500 ;
        RECT 4.000 12.000 6.000 12.500 ;
        RECT 9.000 12.000 11.000 12.500 ;
        RECT 12.000 11.000 13.000 27.500 ;
        RECT 14.000 14.000 15.000 27.500 ;
        RECT 17.000 17.000 18.000 27.500 ;
        RECT 16.000 15.000 18.000 17.000 ;
        RECT 14.000 13.000 16.000 14.000 ;
        RECT 14.000 12.000 18.000 13.000 ;
        RECT 2.000 10.000 5.500 11.000 ;
        RECT 2.500 9.000 5.500 10.000 ;
        RECT 11.000 9.000 13.000 11.000 ;
        RECT 2.500 1.500 3.500 9.000 ;
        RECT 4.500 5.500 6.500 7.500 ;
        RECT 5.500 1.500 6.500 5.500 ;
        RECT 12.000 1.500 13.000 9.000 ;
        RECT 14.000 5.500 16.000 7.500 ;
        RECT 14.000 1.500 15.000 5.500 ;
        RECT 17.000 1.500 18.000 12.000 ;
        RECT 19.000 7.500 20.000 27.500 ;
        RECT 22.000 19.500 23.000 27.500 ;
        RECT 21.000 17.500 23.000 19.500 ;
        RECT 25.000 15.000 26.000 27.500 ;
        RECT 28.000 19.500 29.000 27.500 ;
        RECT 27.000 17.500 29.000 19.500 ;
        RECT 30.000 17.500 31.000 27.500 ;
        RECT 24.000 14.000 26.000 15.000 ;
        RECT 30.000 15.500 32.000 17.500 ;
        RECT 24.000 11.000 25.000 14.000 ;
        RECT 27.000 12.000 29.000 14.000 ;
        RECT 21.000 9.000 23.000 11.000 ;
        RECT 19.000 5.500 21.000 7.500 ;
        RECT 19.000 1.500 20.000 5.500 ;
        RECT 22.000 1.500 23.000 9.000 ;
        RECT 24.000 9.000 26.500 11.000 ;
        RECT 28.000 9.500 29.000 12.000 ;
        RECT 30.000 11.500 31.000 15.500 ;
        RECT 33.000 14.500 34.000 27.500 ;
        RECT 32.000 12.500 34.000 14.500 ;
        RECT 35.000 14.500 36.000 27.500 ;
        RECT 38.000 19.500 39.000 27.500 ;
        RECT 37.000 17.500 39.000 19.500 ;
        RECT 37.000 14.500 39.000 15.000 ;
        RECT 35.000 13.500 39.000 14.500 ;
        RECT 37.000 13.000 39.000 13.500 ;
        RECT 30.000 10.500 36.500 11.500 ;
        RECT 24.000 1.500 25.000 9.000 ;
        RECT 28.000 8.500 33.500 9.500 ;
        RECT 26.000 6.500 28.000 7.500 ;
        RECT 26.000 5.500 31.500 6.500 ;
        RECT 30.500 1.500 31.500 5.500 ;
        RECT 32.500 1.500 33.500 8.500 ;
        RECT 35.500 1.500 36.500 10.500 ;
        RECT 37.500 1.500 38.500 13.000 ;
        RECT 41.000 12.500 42.000 27.500 ;
        RECT 49.000 17.500 50.000 27.500 ;
        RECT 52.000 19.500 53.000 27.500 ;
        RECT 51.000 17.500 53.000 19.500 ;
        RECT 48.000 15.500 50.000 17.500 ;
        RECT 41.000 11.500 45.000 12.500 ;
        RECT 42.500 10.500 45.000 11.500 ;
        RECT 39.500 5.500 41.500 7.500 ;
        RECT 40.500 1.500 41.500 5.500 ;
        RECT 42.500 1.500 43.500 10.500 ;
        RECT 48.000 7.500 50.000 9.500 ;
        RECT 49.000 1.500 50.000 7.500 ;
        RECT 51.000 5.500 53.000 7.500 ;
        RECT 52.000 1.500 53.000 5.500 ;
  END
END sff1m2

#--------EOF---------

MACRO sff1m2_r
  CLASS CORE ;
  FOREIGN sff1m2_r ;
  ORIGIN 0.000 0.000 ;
  SIZE 62.500 BY 29.000 ;
  SYMMETRY X Y R90 ;
  SITE core ;
  PIN VSS
    DIRECTION INOUT ;
    USE GROUND ;
    SHAPE ABUTMENT ;
    PORT
      LAYER ML1 ;
        RECT 0.500 1.000 2.500 4.500 ;
        RECT 10.000 1.000 12.000 4.800 ;
        RECT 16.500 1.000 18.500 4.800 ;
        RECT 26.500 1.000 28.500 4.800 ;
        RECT 35.000 1.000 37.000 4.800 ;
        RECT 45.000 1.000 47.000 4.800 ;
        RECT 56.500 1.000 58.500 4.800 ;
        RECT -0.500 -1.000 63.000 1.000 ;
    END
  END VSS
  PIN VDD
    DIRECTION INOUT ;
    USE POWER ;
    SHAPE ABUTMENT ;
    PORT
      LAYER ML1 ;
        RECT -0.500 28.000 63.000 30.000 ;
        RECT 0.500 20.500 2.500 28.000 ;
        RECT 10.000 20.500 12.000 28.000 ;
        RECT 16.500 20.500 18.500 28.000 ;
        RECT 26.500 20.500 28.500 28.000 ;
        RECT 32.500 20.500 34.500 28.000 ;
        RECT 42.500 20.500 44.500 28.000 ;
        RECT 48.500 20.500 50.500 28.000 ;
        RECT 56.500 20.500 58.500 28.000 ;
    END
  END VDD
  PIN QB
    DIRECTION INPUT ;
    USE SIGNAL ;
    PORT
      LAYER ML1 ;
        RECT 53.500 20.500 55.500 26.500 ;
        RECT 54.500 19.500 55.500 20.500 ;
        RECT 54.500 18.500 59.500 19.500 ;
        RECT 57.500 17.500 59.500 18.500 ;
        RECT 58.000 7.500 59.000 17.500 ;
        RECT 57.500 6.500 59.500 7.500 ;
        RECT 54.500 5.500 59.500 6.500 ;
        RECT 54.500 4.500 55.500 5.500 ;
        RECT 53.500 2.500 55.500 4.500 ;
    END
  END QB
  PIN CK
    DIRECTION INPUT ;
    USE SIGNAL ;
    PORT
      LAYER ML2 ;
        RECT 1.000 14.500 3.000 16.500 ;
    END
  END CK
  PIN D
    DIRECTION INPUT ;
    USE SIGNAL ;
    PORT
      LAYER ML2 ;
        RECT 17.500 9.000 19.500 11.000 ;
    END
  END D
  PIN S
    DIRECTION INPUT ;
    USE SIGNAL ;
    PORT
      LAYER ML2 ;
        RECT 49.500 10.500 51.500 12.500 ;
    END
  END S
  PIN Q
    DIRECTION INPUT ;
    USE SIGNAL ;
    PORT
      LAYER ML2 ;
        RECT 60.000 10.500 62.000 12.500 ;
    END
  END Q
  OBS
      LAYER ML1 ;
        RECT 3.500 20.500 5.500 26.500 ;
        RECT 7.000 20.500 9.000 26.500 ;
        RECT 13.000 20.500 15.000 26.500 ;
        RECT 21.500 20.500 23.500 26.500 ;
        RECT 29.500 20.500 31.500 26.500 ;
        RECT 37.500 20.500 39.500 26.500 ;
        RECT 45.500 20.500 47.500 26.500 ;
        RECT 59.500 20.500 61.500 26.500 ;
        RECT 1.000 14.500 3.000 16.500 ;
        RECT 4.000 14.000 5.000 20.500 ;
        RECT 7.500 19.000 8.500 20.500 ;
        RECT 11.000 19.000 13.000 19.500 ;
        RECT 7.500 18.000 13.000 19.000 ;
        RECT 4.000 12.000 6.500 14.000 ;
        RECT 7.500 13.500 8.500 18.000 ;
        RECT 11.000 17.500 13.000 18.000 ;
        RECT 14.000 16.500 15.000 20.500 ;
        RECT 22.000 19.000 23.000 20.500 ;
        RECT 30.500 19.500 31.500 20.500 ;
        RECT 38.500 19.500 39.500 20.500 ;
        RECT 27.500 19.000 29.500 19.500 ;
        RECT 22.000 18.000 29.500 19.000 ;
        RECT 30.500 18.500 35.500 19.500 ;
        RECT 38.500 18.500 45.500 19.500 ;
        RECT 27.500 17.500 29.500 18.000 ;
        RECT 33.500 17.500 35.500 18.500 ;
        RECT 43.500 17.500 45.500 18.500 ;
        RECT 46.500 17.500 47.500 20.500 ;
        RECT 22.500 16.500 24.500 17.000 ;
        RECT 36.500 16.500 38.500 17.500 ;
        RECT 13.500 15.500 38.500 16.500 ;
        RECT 46.500 16.500 56.500 17.500 ;
        RECT 10.500 13.500 12.500 14.000 ;
        RECT 7.500 12.500 12.500 13.500 ;
        RECT 4.000 4.500 5.000 12.000 ;
        RECT 7.500 6.500 8.500 12.500 ;
        RECT 10.500 12.000 12.500 12.500 ;
        RECT 13.500 10.000 14.500 15.500 ;
        RECT 22.500 15.000 24.500 15.500 ;
        RECT 43.500 14.500 45.500 15.000 ;
        RECT 46.500 14.500 47.500 16.500 ;
        RECT 54.500 15.500 56.500 16.500 ;
        RECT 15.500 13.500 17.500 14.000 ;
        RECT 20.500 13.500 22.500 14.000 ;
        RECT 33.500 13.500 35.500 14.000 ;
        RECT 38.500 13.500 40.500 14.500 ;
        RECT 15.500 12.500 40.500 13.500 ;
        RECT 43.500 13.500 55.500 14.500 ;
        RECT 43.500 13.000 45.500 13.500 ;
        RECT 15.500 12.000 17.500 12.500 ;
        RECT 20.500 12.000 22.500 12.500 ;
        RECT 33.500 12.000 35.500 12.500 ;
        RECT 13.500 9.000 15.000 10.000 ;
        RECT 17.500 9.000 19.500 11.000 ;
        RECT 27.500 10.500 29.500 11.000 ;
        RECT 23.500 9.500 29.500 10.500 ;
        RECT 11.000 6.500 13.000 7.500 ;
        RECT 7.500 5.500 13.000 6.500 ;
        RECT 14.000 6.500 15.000 9.000 ;
        RECT 20.500 6.500 22.500 7.500 ;
        RECT 14.000 5.500 22.500 6.500 ;
        RECT 7.500 4.500 8.500 5.500 ;
        RECT 14.000 4.500 15.000 5.500 ;
        RECT 23.500 4.500 24.500 9.500 ;
        RECT 27.500 9.000 29.500 9.500 ;
        RECT 31.000 10.500 33.000 11.000 ;
        RECT 49.500 10.500 51.500 12.500 ;
        RECT 31.000 9.500 51.500 10.500 ;
        RECT 54.500 9.500 55.500 13.500 ;
        RECT 60.500 12.500 61.500 20.500 ;
        RECT 60.000 10.500 62.000 12.500 ;
        RECT 31.000 9.000 33.000 9.500 ;
        RECT 54.500 8.500 56.500 9.500 ;
        RECT 51.000 7.500 56.500 8.500 ;
        RECT 25.500 6.500 27.500 7.500 ;
        RECT 32.500 6.500 34.500 7.500 ;
        RECT 46.000 6.500 48.000 7.500 ;
        RECT 25.500 5.500 34.500 6.500 ;
        RECT 41.000 5.500 48.000 6.500 ;
        RECT 32.500 4.500 33.500 5.500 ;
        RECT 41.000 4.500 42.000 5.500 ;
        RECT 51.000 4.500 52.000 7.500 ;
        RECT 60.500 4.500 61.500 10.500 ;
        RECT 3.500 2.500 5.500 4.500 ;
        RECT 7.000 2.500 9.000 4.500 ;
        RECT 13.000 2.500 15.000 4.500 ;
        RECT 21.500 3.500 24.500 4.500 ;
        RECT 21.500 2.500 23.500 3.500 ;
        RECT 31.500 2.500 33.500 4.500 ;
        RECT 40.000 2.500 42.000 4.500 ;
        RECT 50.000 2.500 52.000 4.500 ;
        RECT 59.500 2.500 61.500 4.500 ;
      LAYER ML2 ;
        RECT 27.500 17.500 29.500 19.500 ;
        RECT 33.500 17.500 35.500 19.500 ;
        RECT 43.500 17.500 45.500 19.500 ;
        RECT 28.500 11.000 29.500 17.500 ;
        RECT 27.500 9.000 29.500 11.000 ;
        RECT 34.000 7.500 35.000 17.500 ;
        RECT 32.500 5.500 35.000 7.500 ;
        RECT 44.000 7.500 45.000 17.500 ;
        RECT 44.000 6.500 48.000 7.500 ;
        RECT 46.000 5.500 48.000 6.500 ;
      LAYER POL ;
        RECT 2.500 16.500 3.500 27.500 ;
        RECT 9.000 19.000 10.000 27.500 ;
        RECT 12.000 19.500 13.000 27.500 ;
        RECT 1.000 14.500 3.500 16.500 ;
        RECT 2.500 1.500 3.500 14.500 ;
        RECT 8.500 18.000 10.000 19.000 ;
        RECT 8.500 14.000 9.500 18.000 ;
        RECT 11.000 17.500 13.000 19.500 ;
        RECT 4.500 12.000 9.500 14.000 ;
        RECT 10.500 13.500 12.500 14.000 ;
        RECT 15.500 13.500 17.500 14.000 ;
        RECT 10.500 12.500 17.500 13.500 ;
        RECT 10.500 12.000 12.500 12.500 ;
        RECT 15.500 12.000 17.500 12.500 ;
        RECT 8.500 11.000 9.500 12.000 ;
        RECT 18.500 11.000 19.500 27.500 ;
        RECT 20.500 14.000 21.500 27.500 ;
        RECT 23.500 17.000 24.500 27.500 ;
        RECT 22.500 15.000 24.500 17.000 ;
        RECT 20.500 13.000 22.500 14.000 ;
        RECT 20.500 12.000 24.500 13.000 ;
        RECT 8.500 10.000 10.000 11.000 ;
        RECT 9.000 1.500 10.000 10.000 ;
        RECT 17.500 9.000 19.500 11.000 ;
        RECT 11.000 5.500 13.000 7.500 ;
        RECT 12.000 1.500 13.000 5.500 ;
        RECT 18.500 1.500 19.500 9.000 ;
        RECT 20.500 5.500 22.500 7.500 ;
        RECT 20.500 1.500 21.500 5.500 ;
        RECT 23.500 1.500 24.500 12.000 ;
        RECT 25.500 7.500 26.500 27.500 ;
        RECT 28.500 19.500 29.500 27.500 ;
        RECT 27.500 17.500 29.500 19.500 ;
        RECT 31.500 15.000 32.500 27.500 ;
        RECT 34.500 19.500 35.500 27.500 ;
        RECT 33.500 17.500 35.500 19.500 ;
        RECT 36.500 17.500 37.500 27.500 ;
        RECT 30.500 14.000 32.500 15.000 ;
        RECT 36.500 15.500 38.500 17.500 ;
        RECT 30.500 11.000 31.500 14.000 ;
        RECT 33.500 12.000 35.500 14.000 ;
        RECT 27.500 9.000 29.500 11.000 ;
        RECT 25.500 5.500 27.500 7.500 ;
        RECT 25.500 1.500 26.500 5.500 ;
        RECT 28.500 1.500 29.500 9.000 ;
        RECT 30.500 9.000 33.000 11.000 ;
        RECT 34.500 9.500 35.500 12.000 ;
        RECT 36.500 11.500 37.500 15.500 ;
        RECT 39.500 14.500 40.500 27.500 ;
        RECT 38.500 12.500 40.500 14.500 ;
        RECT 41.500 14.500 42.500 27.500 ;
        RECT 44.500 19.500 45.500 27.500 ;
        RECT 43.500 17.500 45.500 19.500 ;
        RECT 43.500 14.500 45.500 15.000 ;
        RECT 41.500 13.500 45.500 14.500 ;
        RECT 43.500 13.000 45.500 13.500 ;
        RECT 36.500 10.500 43.000 11.500 ;
        RECT 30.500 1.500 31.500 9.000 ;
        RECT 34.500 8.500 40.000 9.500 ;
        RECT 32.500 6.500 34.500 7.500 ;
        RECT 32.500 5.500 38.000 6.500 ;
        RECT 37.000 1.500 38.000 5.500 ;
        RECT 39.000 1.500 40.000 8.500 ;
        RECT 42.000 1.500 43.000 10.500 ;
        RECT 44.000 1.500 45.000 13.000 ;
        RECT 47.500 12.500 48.500 27.500 ;
        RECT 55.500 17.500 56.500 27.500 ;
        RECT 58.500 19.500 59.500 27.500 ;
        RECT 57.500 17.500 59.500 19.500 ;
        RECT 54.500 15.500 56.500 17.500 ;
        RECT 47.500 11.500 51.500 12.500 ;
        RECT 49.000 10.500 51.500 11.500 ;
        RECT 46.000 5.500 48.000 7.500 ;
        RECT 47.000 1.500 48.000 5.500 ;
        RECT 49.000 1.500 50.000 10.500 ;
        RECT 54.500 7.500 56.500 9.500 ;
        RECT 55.500 1.500 56.500 7.500 ;
        RECT 57.500 5.500 59.500 7.500 ;
        RECT 58.500 1.500 59.500 5.500 ;
  END
END sff1m2_r

#--------EOF---------


#--------EOF---------

MACRO or21
  CLASS CORE ;
  FOREIGN or21 ;
  ORIGIN 0.000 0.000 ;
  SIZE 12.500 BY 29.000 ;
  SYMMETRY X Y R90 ;
  SITE core ;
  PIN VSS
    DIRECTION INOUT ;
    USE GROUND ;
    SHAPE ABUTMENT ;
    PORT
      LAYER ML1 ;
        RECT 0.500 1.000 2.500 4.500 ;
        RECT 6.500 1.000 8.500 4.500 ;
        RECT -0.500 -1.000 13.000 1.000 ;
    END
  END VSS
  PIN VDD
    DIRECTION INOUT ;
    USE POWER ;
    SHAPE ABUTMENT ;
    PORT
      LAYER ML1 ;
        RECT -0.500 28.000 13.000 30.000 ;
        RECT 6.000 20.500 8.000 28.000 ;
    END
  END VDD
  PIN A
    DIRECTION INPUT ;
    USE SIGNAL ;
    PORT
      LAYER ML2 ;
        RECT 1.000 8.500 3.000 10.500 ;
    END
  END A
  PIN B
    DIRECTION INPUT ;
    USE SIGNAL ;
    PORT
      LAYER ML2 ;
        RECT 4.000 11.500 6.000 13.500 ;
    END
  END B
  PIN X
    DIRECTION OUTPUT ;
    USE SIGNAL ;
    PORT
      LAYER ML2 ;
        RECT 10.000 8.000 12.000 10.000 ;
    END
  END X
  OBS
      LAYER ML1 ;
        RECT 1.000 20.500 3.000 26.500 ;
        RECT 9.000 20.500 11.000 26.500 ;
        RECT 1.500 17.000 2.500 20.500 ;
        RECT 9.500 18.500 10.500 20.500 ;
        RECT 9.500 17.500 11.000 18.500 ;
        RECT 1.500 16.000 8.000 17.000 ;
        RECT 7.000 13.500 8.000 16.000 ;
        RECT 4.000 11.500 6.000 13.500 ;
        RECT 7.000 11.500 9.000 13.500 ;
        RECT 1.000 8.500 3.000 10.500 ;
        RECT 7.000 6.500 8.000 11.500 ;
        RECT 4.500 5.500 8.000 6.500 ;
        RECT 10.000 10.000 11.000 17.500 ;
        RECT 10.000 8.000 12.000 10.000 ;
        RECT 4.500 4.500 5.500 5.500 ;
        RECT 10.000 4.500 11.000 8.000 ;
        RECT 3.500 2.500 5.500 4.500 ;
        RECT 9.500 2.500 11.500 4.500 ;
      LAYER POL ;
        RECT 3.000 18.500 4.000 27.500 ;
        RECT 2.000 17.500 4.000 18.500 ;
        RECT 2.000 10.500 3.000 17.500 ;
        RECT 5.000 13.500 6.000 27.500 ;
        RECT 8.000 17.500 9.000 27.500 ;
        RECT 8.000 16.500 9.500 17.500 ;
        RECT 8.500 13.500 9.500 16.500 ;
        RECT 4.000 11.500 6.000 13.500 ;
        RECT 7.000 11.500 9.500 13.500 ;
        RECT 5.000 10.500 6.000 11.500 ;
        RECT 1.000 8.500 3.500 10.500 ;
        RECT 5.000 9.500 6.500 10.500 ;
        RECT 2.500 1.500 3.500 8.500 ;
        RECT 5.500 1.500 6.500 9.500 ;
        RECT 8.500 1.500 9.500 11.500 ;
  END
END or21

#--------EOF---------

MACRO or31
  CLASS CORE ;
  FOREIGN or31 ;
  ORIGIN 0.000 0.000 ;
  SIZE 15.500 BY 29.000 ;
  SYMMETRY X Y R90 ;
  SITE core ;
  PIN VSS
    DIRECTION INOUT ;
    USE GROUND ;
    SHAPE ABUTMENT ;
    PORT
      LAYER ML1 ;
        RECT 3.500 1.000 5.500 4.500 ;
        RECT 9.500 1.000 11.500 4.500 ;
        RECT -0.500 -1.000 16.000 1.000 ;
    END
  END VSS
  PIN VDD
    DIRECTION INOUT ;
    USE POWER ;
    SHAPE ABUTMENT ;
    PORT
      LAYER ML1 ;
        RECT -0.500 28.000 16.000 30.000 ;
        RECT 8.500 20.500 10.500 28.000 ;
    END
  END VDD
  PIN B
    DIRECTION INPUT ;
    USE SIGNAL ;
    PORT
      LAYER ML2 ;
        RECT 4.000 11.500 6.000 13.500 ;
    END
  END B
  PIN C
    DIRECTION INPUT ;
    USE SIGNAL ;
    PORT
      LAYER ML2 ;
        RECT 7.000 12.000 9.000 14.000 ;
    END
  END C
  PIN A
    DIRECTION INPUT ;
    USE SIGNAL ;
    PORT
      LAYER ML2 ;
        RECT 1.000 14.500 3.000 16.500 ;
    END
  END A
  PIN X
    DIRECTION OUTPUT ;
    USE SIGNAL ;
    PORT
      LAYER ML2 ;
        RECT 13.000 9.000 15.000 11.000 ;
    END
  END X
  OBS
      LAYER ML1 ;
        RECT 1.500 20.500 3.500 26.500 ;
        RECT 11.500 20.500 13.500 26.500 ;
        RECT 2.500 18.500 3.500 20.500 ;
        RECT 2.500 17.500 11.000 18.500 ;
        RECT 1.000 14.500 3.000 16.500 ;
        RECT 10.000 14.000 11.000 17.500 ;
        RECT 12.000 17.000 13.000 20.500 ;
        RECT 12.000 16.000 14.000 17.000 ;
        RECT 4.000 11.500 6.000 13.500 ;
        RECT 7.000 12.000 9.000 14.000 ;
        RECT 10.000 12.000 12.000 14.000 ;
        RECT 10.000 8.500 11.000 12.000 ;
        RECT 1.500 7.500 11.000 8.500 ;
        RECT 13.000 11.000 14.000 16.000 ;
        RECT 13.000 9.000 15.000 11.000 ;
        RECT 1.500 4.500 2.500 7.500 ;
        RECT 7.000 4.500 8.000 7.500 ;
        RECT 13.000 4.500 14.000 9.000 ;
        RECT 0.500 2.500 2.500 4.500 ;
        RECT 6.500 2.500 8.500 4.500 ;
        RECT 12.500 2.500 14.500 4.500 ;
      LAYER POL ;
        RECT 3.500 18.000 4.500 27.500 ;
        RECT 2.000 17.000 4.500 18.000 ;
        RECT 2.000 16.500 3.000 17.000 ;
        RECT 1.000 14.500 3.000 16.500 ;
        RECT 5.500 16.000 6.500 27.500 ;
        RECT 2.000 10.500 3.000 14.500 ;
        RECT 5.000 15.000 6.500 16.000 ;
        RECT 5.000 13.500 6.000 15.000 ;
        RECT 7.500 14.000 8.500 27.500 ;
        RECT 10.500 14.000 11.500 27.500 ;
        RECT 4.000 11.500 6.000 13.500 ;
        RECT 7.000 12.000 9.000 14.000 ;
        RECT 10.000 13.500 12.000 14.000 ;
        RECT 10.000 12.000 12.500 13.500 ;
        RECT 5.000 10.500 6.000 11.500 ;
        RECT 7.500 10.500 8.500 12.000 ;
        RECT 2.000 9.500 3.500 10.500 ;
        RECT 5.000 9.500 6.500 10.500 ;
        RECT 7.500 9.500 9.500 10.500 ;
        RECT 2.500 1.500 3.500 9.500 ;
        RECT 5.500 1.500 6.500 9.500 ;
        RECT 8.500 1.500 9.500 9.500 ;
        RECT 11.500 1.500 12.500 12.000 ;
  END
END or31

#--------EOF---------

MACRO rff1
  CLASS CORE ;
  FOREIGN rff1 ;
  ORIGIN 0.000 0.000 ;
  SIZE 56.000 BY 29.000 ;
  SYMMETRY X Y R90 ;
  SITE core ;
  PIN VDD
    DIRECTION INOUT ;
    USE POWER ;
    SHAPE ABUTMENT ;
    PORT
      LAYER ML1 ;
        RECT -0.500 28.000 56.500 30.000 ;
        RECT 3.500 20.500 5.500 28.000 ;
        RECT 10.000 20.500 12.000 28.000 ;
        RECT 20.000 20.500 22.000 28.000 ;
        RECT 28.500 20.500 30.500 28.000 ;
        RECT 38.500 20.500 40.500 28.000 ;
        RECT 50.000 20.500 52.000 28.000 ;
    END
  END VDD
  PIN VSS
    DIRECTION INOUT ;
    USE GROUND ;
    SHAPE ABUTMENT ;
    PORT
      LAYER ML1 ;
        RECT 3.500 1.000 5.500 4.800 ;
        RECT 10.000 1.000 12.000 4.800 ;
        RECT 20.000 1.000 22.000 4.800 ;
        RECT 26.000 1.000 28.000 4.800 ;
        RECT 36.000 1.000 38.000 4.800 ;
        RECT 42.000 1.000 44.000 4.800 ;
        RECT 50.000 1.000 52.000 4.800 ;
        RECT -0.500 -1.000 56.500 1.000 ;
    END
  END VSS
  PIN QB
    DIRECTION INPUT ;
    USE SIGNAL ;
    PORT
      LAYER ML1 ;
        RECT 47.000 20.500 49.000 26.500 ;
        RECT 47.500 19.500 48.500 20.500 ;
        RECT 47.500 18.500 53.000 19.500 ;
        RECT 51.000 17.500 53.000 18.500 ;
        RECT 51.500 7.500 52.500 17.500 ;
        RECT 51.000 6.500 53.000 7.500 ;
        RECT 48.000 5.500 53.000 6.500 ;
        RECT 48.000 4.500 49.000 5.500 ;
        RECT 47.000 2.500 49.000 4.500 ;
    END
  END QB
  PIN Q
    DIRECTION INPUT ;
    USE SIGNAL ;
    PORT
      LAYER ML2 ;
        RECT 53.500 10.500 55.500 12.500 ;
    END
  END Q
  PIN R
    DIRECTION INPUT ;
    USE SIGNAL ;
    PORT
      LAYER ML2 ;
        RECT 43.000 10.500 45.000 12.500 ;
    END
  END R
  PIN D
    DIRECTION INPUT ;
    USE SIGNAL ;
    PORT
      LAYER ML2 ;
        RECT 11.000 9.000 13.000 11.000 ;
    END
  END D
  PIN CK
    DIRECTION INPUT ;
    USE SIGNAL ;
    PORT
      LAYER ML2 ;
        RECT 3.500 9.000 5.500 11.000 ;
    END
  END CK
  OBS
      LAYER ML1 ;
        RECT 0.500 20.500 2.500 26.500 ;
        RECT 6.500 20.500 8.500 26.500 ;
        RECT 15.000 20.500 17.000 26.500 ;
        RECT 25.000 20.500 27.000 26.500 ;
        RECT 33.500 20.500 35.500 26.500 ;
        RECT 43.500 20.500 45.500 26.500 ;
        RECT 53.000 20.500 55.000 26.500 ;
        RECT 1.000 19.500 2.000 20.500 ;
        RECT 1.000 18.500 6.500 19.500 ;
        RECT 1.000 13.500 2.000 18.500 ;
        RECT 4.500 17.500 6.500 18.500 ;
        RECT 7.500 16.500 8.500 20.500 ;
        RECT 15.500 19.500 16.500 20.500 ;
        RECT 25.500 19.500 26.500 20.500 ;
        RECT 34.000 19.500 35.000 20.500 ;
        RECT 15.500 18.500 23.000 19.500 ;
        RECT 25.500 18.500 29.000 19.500 ;
        RECT 34.000 18.500 41.500 19.500 ;
        RECT 21.000 17.500 23.000 18.500 ;
        RECT 27.000 17.500 29.000 18.500 ;
        RECT 39.500 17.500 41.500 18.500 ;
        RECT 16.000 16.500 18.000 17.000 ;
        RECT 31.000 16.500 33.000 17.500 ;
        RECT 7.000 15.500 33.000 16.500 ;
        RECT 44.000 17.000 45.000 20.500 ;
        RECT 48.000 17.000 50.000 17.500 ;
        RECT 44.000 16.000 50.000 17.000 ;
        RECT 4.000 13.500 6.000 14.000 ;
        RECT 1.000 12.500 6.000 13.500 ;
        RECT 1.000 7.000 2.000 12.500 ;
        RECT 4.000 12.000 6.000 12.500 ;
        RECT 3.500 9.000 5.500 11.000 ;
        RECT 7.000 10.000 8.000 15.500 ;
        RECT 16.000 15.000 18.000 15.500 ;
        RECT 9.000 13.500 11.000 14.000 ;
        RECT 14.000 13.500 16.000 14.000 ;
        RECT 29.000 13.500 31.000 14.000 ;
        RECT 34.500 13.500 36.500 15.000 ;
        RECT 9.000 12.500 36.500 13.500 ;
        RECT 37.500 14.500 39.500 15.000 ;
        RECT 44.000 14.500 45.000 16.000 ;
        RECT 48.000 15.500 50.000 16.000 ;
        RECT 37.500 13.500 49.000 14.500 ;
        RECT 37.500 13.000 39.500 13.500 ;
        RECT 9.000 12.000 11.000 12.500 ;
        RECT 14.000 12.000 16.000 12.500 ;
        RECT 29.000 12.000 31.000 12.500 ;
        RECT 7.000 9.000 8.500 10.000 ;
        RECT 11.000 9.000 13.000 11.000 ;
        RECT 21.000 10.500 23.000 11.000 ;
        RECT 17.000 9.500 23.000 10.500 ;
        RECT 4.500 7.000 6.500 7.500 ;
        RECT 1.000 6.000 6.500 7.000 ;
        RECT 1.000 4.500 2.000 6.000 ;
        RECT 4.500 5.500 6.500 6.000 ;
        RECT 7.500 7.000 8.500 9.000 ;
        RECT 14.000 7.000 16.000 7.500 ;
        RECT 7.500 6.000 16.000 7.000 ;
        RECT 7.500 4.500 8.500 6.000 ;
        RECT 14.000 5.500 16.000 6.000 ;
        RECT 17.000 4.500 18.000 9.500 ;
        RECT 21.000 9.000 23.000 9.500 ;
        RECT 24.000 10.500 26.000 11.000 ;
        RECT 43.000 10.500 45.000 12.500 ;
        RECT 24.000 9.500 45.000 10.500 ;
        RECT 48.000 10.000 49.000 13.500 ;
        RECT 54.000 12.500 55.000 20.500 ;
        RECT 53.500 10.500 55.500 12.500 ;
        RECT 24.000 9.000 26.000 9.500 ;
        RECT 48.000 9.000 50.000 10.000 ;
        RECT 46.000 8.000 50.000 9.000 ;
        RECT 19.000 7.000 21.000 7.500 ;
        RECT 27.000 7.000 29.000 7.500 ;
        RECT 19.000 6.000 29.000 7.000 ;
        RECT 37.000 6.500 39.000 7.500 ;
        RECT 46.000 6.500 47.000 8.000 ;
        RECT 19.000 5.500 21.000 6.000 ;
        RECT 23.500 4.500 24.500 6.000 ;
        RECT 27.000 5.500 29.000 6.000 ;
        RECT 32.000 5.500 39.000 6.500 ;
        RECT 40.000 5.500 47.000 6.500 ;
        RECT 32.000 4.500 33.000 5.500 ;
        RECT 40.000 4.500 41.000 5.500 ;
        RECT 54.000 4.500 55.000 10.500 ;
        RECT 0.500 2.500 2.500 4.500 ;
        RECT 6.500 2.500 8.500 4.500 ;
        RECT 15.000 3.500 18.000 4.500 ;
        RECT 15.000 2.500 17.000 3.500 ;
        RECT 23.000 2.500 25.000 4.500 ;
        RECT 31.000 2.500 33.000 4.500 ;
        RECT 39.000 2.500 41.000 4.500 ;
        RECT 53.000 2.500 55.000 4.500 ;
      LAYER POL ;
        RECT 2.500 17.500 3.500 27.500 ;
        RECT 5.500 19.500 6.500 27.500 ;
        RECT 4.500 17.500 6.500 19.500 ;
        RECT 2.000 16.500 3.500 17.500 ;
        RECT 2.000 11.000 3.000 16.500 ;
        RECT 4.000 13.500 6.000 14.000 ;
        RECT 9.000 13.500 11.000 14.000 ;
        RECT 4.000 12.500 11.000 13.500 ;
        RECT 4.000 12.000 6.000 12.500 ;
        RECT 9.000 12.000 11.000 12.500 ;
        RECT 12.000 11.000 13.000 27.500 ;
        RECT 14.000 14.000 15.000 27.500 ;
        RECT 17.000 17.000 18.000 27.500 ;
        RECT 16.000 15.000 18.000 17.000 ;
        RECT 14.000 12.000 16.000 14.000 ;
        RECT 2.000 10.000 5.500 11.000 ;
        RECT 2.500 9.000 5.500 10.000 ;
        RECT 11.000 9.000 13.000 11.000 ;
        RECT 15.000 10.500 16.000 12.000 ;
        RECT 15.000 9.500 18.000 10.500 ;
        RECT 2.500 1.500 3.500 9.000 ;
        RECT 4.500 5.500 6.500 7.500 ;
        RECT 5.500 1.500 6.500 5.500 ;
        RECT 12.000 1.500 13.000 9.000 ;
        RECT 14.000 5.500 16.000 7.500 ;
        RECT 14.000 1.500 15.000 5.500 ;
        RECT 17.000 1.500 18.000 9.500 ;
        RECT 19.000 7.500 20.000 27.500 ;
        RECT 22.000 19.500 23.000 27.500 ;
        RECT 21.000 17.500 23.000 19.500 ;
        RECT 22.000 11.000 23.000 17.500 ;
        RECT 21.000 9.000 23.000 11.000 ;
        RECT 24.000 11.000 25.000 27.500 ;
        RECT 30.500 19.500 31.500 27.500 ;
        RECT 27.000 18.500 31.500 19.500 ;
        RECT 27.000 17.500 29.000 18.500 ;
        RECT 32.500 17.500 33.500 27.500 ;
        RECT 24.000 9.000 26.000 11.000 ;
        RECT 19.000 5.500 21.000 7.500 ;
        RECT 19.000 1.500 20.000 5.500 ;
        RECT 22.000 1.500 23.000 9.000 ;
        RECT 25.000 1.500 26.000 9.000 ;
        RECT 27.000 7.500 28.000 17.500 ;
        RECT 31.000 15.500 33.500 17.500 ;
        RECT 29.000 12.000 31.000 14.000 ;
        RECT 27.000 5.500 29.000 7.500 ;
        RECT 28.000 1.500 29.000 5.500 ;
        RECT 30.000 1.500 31.000 12.000 ;
        RECT 32.500 9.000 33.500 15.500 ;
        RECT 35.500 15.000 36.500 27.500 ;
        RECT 34.500 13.000 36.500 15.000 ;
        RECT 37.500 15.000 38.500 27.500 ;
        RECT 40.500 19.500 41.500 27.500 ;
        RECT 39.500 17.500 41.500 19.500 ;
        RECT 37.500 13.000 39.500 15.000 ;
        RECT 37.500 11.500 38.500 13.000 ;
        RECT 35.000 10.500 38.500 11.500 ;
        RECT 32.500 8.000 34.000 9.000 ;
        RECT 33.000 1.500 34.000 8.000 ;
        RECT 35.000 1.500 36.000 10.500 ;
        RECT 40.500 9.500 41.500 17.500 ;
        RECT 38.000 8.500 41.500 9.500 ;
        RECT 42.500 12.500 43.500 27.500 ;
        RECT 49.000 17.500 50.000 27.500 ;
        RECT 52.000 19.500 53.000 27.500 ;
        RECT 51.000 17.500 53.000 19.500 ;
        RECT 48.000 15.500 50.000 17.500 ;
        RECT 42.500 10.500 45.000 12.500 ;
        RECT 38.000 7.500 39.000 8.500 ;
        RECT 37.000 5.500 39.000 7.500 ;
        RECT 42.500 7.000 43.500 10.500 ;
        RECT 48.000 8.000 50.000 10.000 ;
        RECT 38.000 1.500 39.000 5.500 ;
        RECT 41.000 6.000 43.500 7.000 ;
        RECT 41.000 1.500 42.000 6.000 ;
        RECT 49.000 1.500 50.000 8.000 ;
        RECT 51.000 5.500 53.000 7.500 ;
        RECT 52.000 1.500 53.000 5.500 ;
  END
END rff1

#--------EOF---------

MACRO rff1_r
  CLASS CORE ;
  FOREIGN rff1_r ;
  ORIGIN 0.000 0.000 ;
  SIZE 62.500 BY 29.000 ;
  SYMMETRY X Y R90 ;
  SITE core ;
  PIN VDD
    DIRECTION INOUT ;
    USE POWER ;
    SHAPE ABUTMENT ;
    PORT
      LAYER ML1 ;
        RECT -0.500 28.000 63.000 30.000 ;
        RECT 0.500 20.500 2.500 28.000 ;
        RECT 10.000 20.500 12.000 28.000 ;
        RECT 16.500 20.500 18.500 28.000 ;
        RECT 26.500 20.500 28.500 28.000 ;
        RECT 35.000 20.500 37.000 28.000 ;
        RECT 45.000 20.500 47.000 28.000 ;
        RECT 56.500 20.500 58.500 28.000 ;
    END
  END VDD
  PIN VSS
    DIRECTION INOUT ;
    USE GROUND ;
    SHAPE ABUTMENT ;
    PORT
      LAYER ML1 ;
        RECT 0.500 1.000 2.500 4.500 ;
        RECT 10.000 1.000 12.000 4.800 ;
        RECT 16.500 1.000 18.500 4.800 ;
        RECT 26.500 1.000 28.500 4.800 ;
        RECT 32.500 1.000 34.500 4.800 ;
        RECT 42.500 1.000 44.500 4.800 ;
        RECT 48.500 1.000 50.500 4.800 ;
        RECT 56.500 1.000 58.500 4.800 ;
        RECT -0.500 -1.000 63.000 1.000 ;
    END
  END VSS
  PIN QB
    DIRECTION INPUT ;
    USE SIGNAL ;
    PORT
      LAYER ML1 ;
        RECT 53.500 20.500 55.500 26.500 ;
        RECT 54.000 19.500 55.000 20.500 ;
        RECT 54.000 18.500 59.500 19.500 ;
        RECT 57.500 17.500 59.500 18.500 ;
        RECT 58.000 7.500 59.000 17.500 ;
        RECT 57.500 6.500 59.500 7.500 ;
        RECT 54.500 5.500 59.500 6.500 ;
        RECT 54.500 4.500 55.500 5.500 ;
        RECT 53.500 2.500 55.500 4.500 ;
    END
  END QB
  PIN CK
    DIRECTION INPUT ;
    USE SIGNAL ;
    PORT
      LAYER ML2 ;
        RECT 1.000 14.500 3.000 16.500 ;
    END
  END CK
  PIN Q
    DIRECTION INPUT ;
    USE SIGNAL ;
    PORT
      LAYER ML2 ;
        RECT 60.000 10.500 62.000 12.500 ;
    END
  END Q
  PIN R
    DIRECTION INPUT ;
    USE SIGNAL ;
    PORT
      LAYER ML2 ;
        RECT 49.500 10.500 51.500 12.500 ;
    END
  END R
  PIN D
    DIRECTION INPUT ;
    USE SIGNAL ;
    PORT
      LAYER ML2 ;
        RECT 17.500 9.000 19.500 11.000 ;
    END
  END D
  OBS
      LAYER ML1 ;
        RECT 3.500 20.500 5.500 26.500 ;
        RECT 7.000 20.500 9.000 26.500 ;
        RECT 13.000 20.500 15.000 26.500 ;
        RECT 21.500 20.500 23.500 26.500 ;
        RECT 31.500 20.500 33.500 26.500 ;
        RECT 40.000 20.500 42.000 26.500 ;
        RECT 50.000 20.500 52.000 26.500 ;
        RECT 59.500 20.500 61.500 26.500 ;
        RECT 1.000 14.500 3.000 16.500 ;
        RECT 4.000 14.000 5.000 20.500 ;
        RECT 7.500 19.500 8.500 20.500 ;
        RECT 7.500 18.500 13.000 19.500 ;
        RECT 4.000 12.000 6.500 14.000 ;
        RECT 7.500 13.500 8.500 18.500 ;
        RECT 11.000 17.500 13.000 18.500 ;
        RECT 14.000 16.500 15.000 20.500 ;
        RECT 22.000 19.500 23.000 20.500 ;
        RECT 32.000 19.500 33.000 20.500 ;
        RECT 40.500 19.500 41.500 20.500 ;
        RECT 22.000 18.500 29.500 19.500 ;
        RECT 32.000 18.500 35.500 19.500 ;
        RECT 40.500 18.500 48.000 19.500 ;
        RECT 27.500 17.500 29.500 18.500 ;
        RECT 33.500 17.500 35.500 18.500 ;
        RECT 46.000 17.500 48.000 18.500 ;
        RECT 22.500 16.500 24.500 17.000 ;
        RECT 37.500 16.500 39.500 17.500 ;
        RECT 13.500 15.500 39.500 16.500 ;
        RECT 50.500 17.000 51.500 20.500 ;
        RECT 54.500 17.000 56.500 17.500 ;
        RECT 50.500 16.000 56.500 17.000 ;
        RECT 10.500 13.500 12.500 14.000 ;
        RECT 7.500 12.500 12.500 13.500 ;
        RECT 4.000 4.500 5.000 12.000 ;
        RECT 7.500 7.000 8.500 12.500 ;
        RECT 10.500 12.000 12.500 12.500 ;
        RECT 10.000 9.000 12.000 11.000 ;
        RECT 13.500 10.000 14.500 15.500 ;
        RECT 22.500 15.000 24.500 15.500 ;
        RECT 15.500 13.500 17.500 14.000 ;
        RECT 20.500 13.500 22.500 14.000 ;
        RECT 35.500 13.500 37.500 14.000 ;
        RECT 41.000 13.500 43.000 15.000 ;
        RECT 15.500 12.500 43.000 13.500 ;
        RECT 44.000 14.500 46.000 15.000 ;
        RECT 50.500 14.500 51.500 16.000 ;
        RECT 54.500 15.500 56.500 16.000 ;
        RECT 44.000 13.500 55.500 14.500 ;
        RECT 44.000 13.000 46.000 13.500 ;
        RECT 15.500 12.000 17.500 12.500 ;
        RECT 20.500 12.000 22.500 12.500 ;
        RECT 35.500 12.000 37.500 12.500 ;
        RECT 13.500 9.000 15.000 10.000 ;
        RECT 17.500 9.000 19.500 11.000 ;
        RECT 27.500 10.500 29.500 11.000 ;
        RECT 23.500 9.500 29.500 10.500 ;
        RECT 11.000 7.000 13.000 7.500 ;
        RECT 7.500 6.000 13.000 7.000 ;
        RECT 7.500 4.500 8.500 6.000 ;
        RECT 11.000 5.500 13.000 6.000 ;
        RECT 14.000 7.000 15.000 9.000 ;
        RECT 20.500 7.000 22.500 7.500 ;
        RECT 14.000 6.000 22.500 7.000 ;
        RECT 14.000 4.500 15.000 6.000 ;
        RECT 20.500 5.500 22.500 6.000 ;
        RECT 23.500 4.500 24.500 9.500 ;
        RECT 27.500 9.000 29.500 9.500 ;
        RECT 30.500 10.500 32.500 11.000 ;
        RECT 49.500 10.500 51.500 12.500 ;
        RECT 30.500 9.500 51.500 10.500 ;
        RECT 54.500 10.000 55.500 13.500 ;
        RECT 60.500 12.500 61.500 20.500 ;
        RECT 60.000 10.500 62.000 12.500 ;
        RECT 30.500 9.000 32.500 9.500 ;
        RECT 54.500 9.000 56.500 10.000 ;
        RECT 52.500 8.000 56.500 9.000 ;
        RECT 25.500 7.000 27.500 7.500 ;
        RECT 33.500 7.000 35.500 7.500 ;
        RECT 25.500 6.000 35.500 7.000 ;
        RECT 43.500 6.500 45.500 7.500 ;
        RECT 52.500 6.500 53.500 8.000 ;
        RECT 25.500 5.500 27.500 6.000 ;
        RECT 30.000 4.500 31.000 6.000 ;
        RECT 33.500 5.500 35.500 6.000 ;
        RECT 38.500 5.500 45.500 6.500 ;
        RECT 46.500 5.500 53.500 6.500 ;
        RECT 38.500 4.500 39.500 5.500 ;
        RECT 46.500 4.500 47.500 5.500 ;
        RECT 60.500 4.500 61.500 10.500 ;
        RECT 3.500 2.500 5.500 4.500 ;
        RECT 7.000 2.500 9.000 4.500 ;
        RECT 13.000 2.500 15.000 4.500 ;
        RECT 21.500 3.500 24.500 4.500 ;
        RECT 21.500 2.500 23.500 3.500 ;
        RECT 29.500 2.500 31.500 4.500 ;
        RECT 37.500 2.500 39.500 4.500 ;
        RECT 45.500 2.500 47.500 4.500 ;
        RECT 59.500 2.500 61.500 4.500 ;
      LAYER ML2 ;
        RECT 10.000 9.000 12.000 11.000 ;
      LAYER POL ;
        RECT 2.500 16.500 3.500 27.500 ;
        RECT 9.000 17.500 10.000 27.500 ;
        RECT 12.000 19.500 13.000 27.500 ;
        RECT 11.000 17.500 13.000 19.500 ;
        RECT 1.000 14.500 3.500 16.500 ;
        RECT 2.500 1.500 3.500 14.500 ;
        RECT 8.500 16.500 10.000 17.500 ;
        RECT 8.500 14.000 9.500 16.500 ;
        RECT 4.500 12.000 9.500 14.000 ;
        RECT 10.500 13.500 12.500 14.000 ;
        RECT 15.500 13.500 17.500 14.000 ;
        RECT 10.500 12.500 17.500 13.500 ;
        RECT 10.500 12.000 12.500 12.500 ;
        RECT 15.500 12.000 17.500 12.500 ;
        RECT 8.500 11.000 9.500 12.000 ;
        RECT 18.500 11.000 19.500 27.500 ;
        RECT 20.500 14.000 21.500 27.500 ;
        RECT 23.500 17.000 24.500 27.500 ;
        RECT 22.500 15.000 24.500 17.000 ;
        RECT 20.500 12.000 22.500 14.000 ;
        RECT 8.500 10.000 12.000 11.000 ;
        RECT 9.000 9.000 12.000 10.000 ;
        RECT 17.500 9.000 19.500 11.000 ;
        RECT 21.500 10.500 22.500 12.000 ;
        RECT 21.500 9.500 24.500 10.500 ;
        RECT 9.000 1.500 10.000 9.000 ;
        RECT 11.000 5.500 13.000 7.500 ;
        RECT 12.000 1.500 13.000 5.500 ;
        RECT 18.500 1.500 19.500 9.000 ;
        RECT 20.500 5.500 22.500 7.500 ;
        RECT 20.500 1.500 21.500 5.500 ;
        RECT 23.500 1.500 24.500 9.500 ;
        RECT 25.500 7.500 26.500 27.500 ;
        RECT 28.500 19.500 29.500 27.500 ;
        RECT 27.500 17.500 29.500 19.500 ;
        RECT 28.500 11.000 29.500 17.500 ;
        RECT 27.500 9.000 29.500 11.000 ;
        RECT 30.500 11.000 31.500 27.500 ;
        RECT 37.000 19.500 38.000 27.500 ;
        RECT 33.500 18.500 38.000 19.500 ;
        RECT 33.500 17.500 35.500 18.500 ;
        RECT 39.000 17.500 40.000 27.500 ;
        RECT 30.500 9.000 32.500 11.000 ;
        RECT 25.500 5.500 27.500 7.500 ;
        RECT 25.500 1.500 26.500 5.500 ;
        RECT 28.500 1.500 29.500 9.000 ;
        RECT 31.500 1.500 32.500 9.000 ;
        RECT 33.500 7.500 34.500 17.500 ;
        RECT 37.500 15.500 40.000 17.500 ;
        RECT 35.500 12.000 37.500 14.000 ;
        RECT 33.500 5.500 35.500 7.500 ;
        RECT 34.500 1.500 35.500 5.500 ;
        RECT 36.500 1.500 37.500 12.000 ;
        RECT 39.000 9.000 40.000 15.500 ;
        RECT 42.000 15.000 43.000 27.500 ;
        RECT 41.000 13.000 43.000 15.000 ;
        RECT 44.000 15.000 45.000 27.500 ;
        RECT 47.000 19.500 48.000 27.500 ;
        RECT 46.000 17.500 48.000 19.500 ;
        RECT 44.000 13.000 46.000 15.000 ;
        RECT 44.000 11.500 45.000 13.000 ;
        RECT 41.500 10.500 45.000 11.500 ;
        RECT 39.000 8.000 40.500 9.000 ;
        RECT 39.500 1.500 40.500 8.000 ;
        RECT 41.500 1.500 42.500 10.500 ;
        RECT 47.000 9.500 48.000 17.500 ;
        RECT 44.500 8.500 48.000 9.500 ;
        RECT 49.000 12.500 50.000 27.500 ;
        RECT 55.500 17.500 56.500 27.500 ;
        RECT 58.500 19.500 59.500 27.500 ;
        RECT 57.500 17.500 59.500 19.500 ;
        RECT 54.500 15.500 56.500 17.500 ;
        RECT 49.000 10.500 51.500 12.500 ;
        RECT 44.500 7.500 45.500 8.500 ;
        RECT 43.500 5.500 45.500 7.500 ;
        RECT 49.000 7.000 50.000 10.500 ;
        RECT 54.500 8.000 56.500 10.000 ;
        RECT 44.500 1.500 45.500 5.500 ;
        RECT 47.500 6.000 50.000 7.000 ;
        RECT 47.500 1.500 48.500 6.000 ;
        RECT 55.500 1.500 56.500 8.000 ;
        RECT 57.500 5.500 59.500 7.500 ;
        RECT 58.500 1.500 59.500 5.500 ;
  END
END rff1_r

#--------EOF---------

MACRO rff1m2
  CLASS CORE ;
  FOREIGN rff1m2 ;
  ORIGIN 0.000 0.000 ;
  SIZE 56.000 BY 29.000 ;
  SYMMETRY X Y R90 ;
  SITE core ;
  PIN VDD
    DIRECTION INOUT ;
    USE POWER ;
    SHAPE ABUTMENT ;
    PORT
      LAYER ML1 ;
        RECT -0.500 28.000 56.500 30.000 ;
        RECT 3.500 20.500 5.500 28.000 ;
        RECT 10.000 20.500 12.000 28.000 ;
        RECT 20.000 20.500 22.000 28.000 ;
        RECT 28.500 20.500 30.500 28.000 ;
        RECT 38.500 20.500 40.500 28.000 ;
        RECT 50.000 20.500 52.000 28.000 ;
    END
  END VDD
  PIN VSS
    DIRECTION INOUT ;
    USE GROUND ;
    SHAPE ABUTMENT ;
    PORT
      LAYER ML1 ;
        RECT 3.500 1.000 5.500 4.800 ;
        RECT 10.000 1.000 12.000 4.800 ;
        RECT 20.000 1.000 22.000 4.800 ;
        RECT 26.000 1.000 28.000 4.800 ;
        RECT 36.000 1.000 38.000 4.800 ;
        RECT 42.000 1.000 44.000 4.800 ;
        RECT 50.000 1.000 52.000 4.800 ;
        RECT -0.500 -1.000 56.500 1.000 ;
    END
  END VSS
  PIN QB
    DIRECTION INPUT ;
    USE SIGNAL ;
    PORT
      LAYER ML1 ;
        RECT 47.000 20.500 49.000 26.500 ;
        RECT 48.000 19.500 49.000 20.500 ;
        RECT 48.000 18.500 53.000 19.500 ;
        RECT 51.000 17.500 53.000 18.500 ;
        RECT 51.500 7.500 52.500 17.500 ;
        RECT 51.000 6.500 53.000 7.500 ;
        RECT 48.000 5.500 53.000 6.500 ;
        RECT 48.000 4.500 49.000 5.500 ;
        RECT 47.000 2.500 49.000 4.500 ;
    END
  END QB
  PIN Q
    DIRECTION INPUT ;
    USE SIGNAL ;
    PORT
      LAYER ML2 ;
        RECT 53.500 10.500 55.500 12.500 ;
    END
  END Q
  PIN R
    DIRECTION INPUT ;
    USE SIGNAL ;
    PORT
      LAYER ML2 ;
        RECT 43.000 10.500 45.000 12.500 ;
    END
  END R
  PIN D
    DIRECTION INPUT ;
    USE SIGNAL ;
    PORT
      LAYER ML2 ;
        RECT 11.000 9.000 13.000 11.000 ;
    END
  END D
  PIN CK
    DIRECTION INPUT ;
    USE SIGNAL ;
    PORT
      LAYER ML2 ;
        RECT 3.500 9.000 5.500 11.000 ;
    END
  END CK
  OBS
      LAYER ML1 ;
        RECT 0.500 20.500 2.500 26.500 ;
        RECT 6.500 20.500 8.500 26.500 ;
        RECT 15.000 20.500 17.000 26.500 ;
        RECT 25.000 20.500 27.000 26.500 ;
        RECT 33.500 20.500 35.500 26.500 ;
        RECT 43.500 20.500 45.500 26.500 ;
        RECT 53.000 20.500 55.000 26.500 ;
        RECT 1.000 19.000 2.000 20.500 ;
        RECT 4.500 19.000 6.500 19.500 ;
        RECT 1.000 18.000 6.500 19.000 ;
        RECT 1.000 13.500 2.000 18.000 ;
        RECT 4.500 17.500 6.500 18.000 ;
        RECT 7.500 16.500 8.500 20.500 ;
        RECT 15.500 19.500 16.500 20.500 ;
        RECT 25.500 19.500 26.500 20.500 ;
        RECT 34.000 19.500 35.000 20.500 ;
        RECT 15.500 18.500 23.000 19.500 ;
        RECT 25.500 18.500 29.500 19.500 ;
        RECT 34.000 18.500 41.500 19.500 ;
        RECT 21.000 17.500 23.000 18.500 ;
        RECT 27.500 17.500 29.500 18.500 ;
        RECT 39.500 17.500 41.500 18.500 ;
        RECT 44.500 17.500 45.500 20.500 ;
        RECT 16.000 16.500 18.000 17.000 ;
        RECT 32.000 16.500 34.000 17.500 ;
        RECT 7.000 15.500 34.000 16.500 ;
        RECT 44.500 16.500 50.000 17.500 ;
        RECT 4.000 13.500 6.000 14.000 ;
        RECT 1.000 12.500 6.000 13.500 ;
        RECT 1.000 7.000 2.000 12.500 ;
        RECT 4.000 12.000 6.000 12.500 ;
        RECT 3.500 9.000 5.500 11.000 ;
        RECT 7.000 10.000 8.000 15.500 ;
        RECT 16.000 15.000 18.000 15.500 ;
        RECT 37.500 14.500 39.500 15.000 ;
        RECT 44.500 14.500 45.500 16.500 ;
        RECT 48.000 15.500 50.000 16.500 ;
        RECT 9.000 13.500 11.000 14.000 ;
        RECT 14.000 13.500 16.000 14.000 ;
        RECT 29.000 13.500 31.000 14.000 ;
        RECT 34.500 13.500 36.500 14.500 ;
        RECT 9.000 12.500 36.500 13.500 ;
        RECT 37.500 13.500 49.000 14.500 ;
        RECT 37.500 13.000 39.500 13.500 ;
        RECT 9.000 12.000 11.000 12.500 ;
        RECT 14.000 12.000 16.000 12.500 ;
        RECT 29.000 12.000 31.000 12.500 ;
        RECT 7.000 9.000 8.500 10.000 ;
        RECT 11.000 9.000 13.000 11.000 ;
        RECT 21.000 10.500 23.000 11.000 ;
        RECT 17.000 9.500 23.000 10.500 ;
        RECT 4.500 7.000 6.500 7.500 ;
        RECT 1.000 6.000 6.500 7.000 ;
        RECT 1.000 4.500 2.000 6.000 ;
        RECT 4.500 5.500 6.500 6.000 ;
        RECT 7.500 7.000 8.500 9.000 ;
        RECT 14.000 7.000 16.000 7.500 ;
        RECT 7.500 6.000 16.000 7.000 ;
        RECT 7.500 4.500 8.500 6.000 ;
        RECT 14.000 5.500 16.000 6.000 ;
        RECT 17.000 4.500 18.000 9.500 ;
        RECT 21.000 9.000 23.000 9.500 ;
        RECT 24.500 10.500 26.500 11.000 ;
        RECT 43.000 10.500 45.000 12.500 ;
        RECT 24.500 9.500 45.000 10.500 ;
        RECT 48.000 10.000 49.000 13.500 ;
        RECT 54.000 12.500 55.000 20.500 ;
        RECT 53.500 10.500 55.500 12.500 ;
        RECT 24.500 9.000 26.500 9.500 ;
        RECT 48.000 9.000 50.000 10.000 ;
        RECT 46.000 8.000 50.000 9.000 ;
        RECT 19.000 7.000 21.000 8.000 ;
        RECT 27.000 7.000 29.000 8.000 ;
        RECT 37.000 7.000 39.000 8.000 ;
        RECT 19.000 6.000 29.000 7.000 ;
        RECT 32.000 6.000 39.000 7.000 ;
        RECT 46.000 6.500 47.000 8.000 ;
        RECT 23.500 4.500 24.500 6.000 ;
        RECT 32.000 4.500 33.000 6.000 ;
        RECT 40.000 5.500 47.000 6.500 ;
        RECT 40.000 4.500 41.000 5.500 ;
        RECT 54.000 4.500 55.000 10.500 ;
        RECT 0.500 2.500 2.500 4.500 ;
        RECT 6.500 2.500 8.500 4.500 ;
        RECT 15.000 3.500 18.000 4.500 ;
        RECT 15.000 2.500 17.000 3.500 ;
        RECT 23.000 2.500 25.000 4.500 ;
        RECT 31.000 2.500 33.000 4.500 ;
        RECT 39.000 2.500 41.000 4.500 ;
        RECT 53.000 2.500 55.000 4.500 ;
      LAYER ML2 ;
        RECT 21.000 17.500 23.000 19.500 ;
        RECT 27.500 17.500 29.500 19.500 ;
        RECT 39.500 17.500 41.500 19.500 ;
        RECT 21.500 11.000 22.500 17.500 ;
        RECT 21.000 9.000 23.000 11.000 ;
        RECT 27.500 8.000 28.500 17.500 ;
        RECT 39.500 16.500 40.500 17.500 ;
        RECT 38.000 15.500 40.500 16.500 ;
        RECT 38.000 8.000 39.000 15.500 ;
        RECT 27.000 6.000 29.000 8.000 ;
        RECT 37.000 6.000 39.000 8.000 ;
      LAYER POL ;
        RECT 2.500 17.500 3.500 27.500 ;
        RECT 5.500 19.500 6.500 27.500 ;
        RECT 4.500 17.500 6.500 19.500 ;
        RECT 2.000 16.500 3.500 17.500 ;
        RECT 2.000 11.000 3.000 16.500 ;
        RECT 4.000 13.500 6.000 14.000 ;
        RECT 9.000 13.500 11.000 14.000 ;
        RECT 4.000 12.500 11.000 13.500 ;
        RECT 4.000 12.000 6.000 12.500 ;
        RECT 9.000 12.000 11.000 12.500 ;
        RECT 12.000 11.000 13.000 27.500 ;
        RECT 14.000 14.000 15.000 27.500 ;
        RECT 17.000 17.000 18.000 27.500 ;
        RECT 16.000 15.000 18.000 17.000 ;
        RECT 14.000 12.000 16.000 14.000 ;
        RECT 2.000 10.000 5.500 11.000 ;
        RECT 2.500 9.000 5.500 10.000 ;
        RECT 11.000 9.000 13.000 11.000 ;
        RECT 15.000 10.500 16.000 12.000 ;
        RECT 15.000 9.500 18.000 10.500 ;
        RECT 2.500 1.500 3.500 9.000 ;
        RECT 4.500 5.500 6.500 7.500 ;
        RECT 5.500 1.500 6.500 5.500 ;
        RECT 12.000 1.500 13.000 9.000 ;
        RECT 14.000 5.500 16.000 7.500 ;
        RECT 14.000 1.500 15.000 5.500 ;
        RECT 17.000 1.500 18.000 9.500 ;
        RECT 19.000 8.000 20.000 27.500 ;
        RECT 22.000 19.500 23.000 27.500 ;
        RECT 21.000 17.500 23.000 19.500 ;
        RECT 24.000 11.000 25.000 27.500 ;
        RECT 30.500 19.500 31.500 27.500 ;
        RECT 27.500 18.500 31.500 19.500 ;
        RECT 27.500 17.500 29.500 18.500 ;
        RECT 32.500 17.500 33.500 27.500 ;
        RECT 32.000 15.500 34.000 17.500 ;
        RECT 29.000 12.000 31.000 14.000 ;
        RECT 21.000 9.000 23.000 11.000 ;
        RECT 24.000 9.000 26.500 11.000 ;
        RECT 19.000 6.000 21.000 8.000 ;
        RECT 19.000 1.500 20.000 6.000 ;
        RECT 22.000 1.500 23.000 9.000 ;
        RECT 25.000 1.500 26.000 9.000 ;
        RECT 27.000 6.000 29.000 8.000 ;
        RECT 28.000 1.500 29.000 6.000 ;
        RECT 30.000 1.500 31.000 12.000 ;
        RECT 32.500 9.000 33.500 15.500 ;
        RECT 35.500 14.500 36.500 27.500 ;
        RECT 34.500 12.500 36.500 14.500 ;
        RECT 37.500 15.000 38.500 27.500 ;
        RECT 40.500 19.500 41.500 27.500 ;
        RECT 39.500 17.500 41.500 19.500 ;
        RECT 37.500 13.000 39.500 15.000 ;
        RECT 37.500 11.500 38.500 13.000 ;
        RECT 35.000 10.500 38.500 11.500 ;
        RECT 42.500 12.500 43.500 27.500 ;
        RECT 49.000 17.500 50.000 27.500 ;
        RECT 52.000 19.500 53.000 27.500 ;
        RECT 51.000 17.500 53.000 19.500 ;
        RECT 48.000 15.500 50.000 17.500 ;
        RECT 42.500 10.500 45.000 12.500 ;
        RECT 32.500 8.000 34.000 9.000 ;
        RECT 33.000 1.500 34.000 8.000 ;
        RECT 35.000 1.500 36.000 10.500 ;
        RECT 42.500 8.000 43.500 10.500 ;
        RECT 48.000 8.000 50.000 10.000 ;
        RECT 37.000 6.000 39.000 8.000 ;
        RECT 38.000 1.500 39.000 6.000 ;
        RECT 41.000 7.000 43.500 8.000 ;
        RECT 41.000 1.500 42.000 7.000 ;
        RECT 49.000 1.500 50.000 8.000 ;
        RECT 51.000 5.500 53.000 7.500 ;
        RECT 52.000 1.500 53.000 5.500 ;
  END
END rff1m2

#--------EOF---------

MACRO rff1m2_r
  CLASS CORE ;
  FOREIGN rff1m2_r ;
  ORIGIN 0.000 0.000 ;
  SIZE 62.500 BY 29.000 ;
  SYMMETRY X Y R90 ;
  SITE core ;
  PIN VDD
    DIRECTION INOUT ;
    USE POWER ;
    SHAPE ABUTMENT ;
    PORT
      LAYER ML1 ;
        RECT -0.500 28.000 63.000 30.000 ;
        RECT 0.500 20.500 2.500 28.000 ;
        RECT 10.000 20.500 12.000 28.000 ;
        RECT 16.500 20.500 18.500 28.000 ;
        RECT 26.500 20.500 28.500 28.000 ;
        RECT 35.000 20.500 37.000 28.000 ;
        RECT 45.000 20.500 47.000 28.000 ;
        RECT 56.500 20.500 58.500 28.000 ;
    END
  END VDD
  PIN VSS
    DIRECTION INOUT ;
    USE GROUND ;
    SHAPE ABUTMENT ;
    PORT
      LAYER ML1 ;
        RECT 0.500 1.000 2.500 4.500 ;
        RECT 10.000 1.000 12.000 4.800 ;
        RECT 16.500 1.000 18.500 4.800 ;
        RECT 26.500 1.000 28.500 4.800 ;
        RECT 32.500 1.000 34.500 4.800 ;
        RECT 42.500 1.000 44.500 4.800 ;
        RECT 48.500 1.000 50.500 4.800 ;
        RECT 56.500 1.000 58.500 4.800 ;
        RECT -0.500 -1.000 63.000 1.000 ;
    END
  END VSS
  PIN QB
    DIRECTION INPUT ;
    USE SIGNAL ;
    PORT
      LAYER ML1 ;
        RECT 53.500 20.500 55.500 26.500 ;
        RECT 54.500 19.500 55.500 20.500 ;
        RECT 54.500 18.500 59.500 19.500 ;
        RECT 57.500 17.500 59.500 18.500 ;
        RECT 58.000 7.500 59.000 17.500 ;
        RECT 57.500 6.500 59.500 7.500 ;
        RECT 54.500 5.500 59.500 6.500 ;
        RECT 54.500 4.500 55.500 5.500 ;
        RECT 53.500 2.500 55.500 4.500 ;
    END
  END QB
  PIN CK
    DIRECTION INPUT ;
    USE SIGNAL ;
    PORT
      LAYER ML2 ;
        RECT 1.000 14.500 3.000 16.500 ;
    END
  END CK
  PIN D
    DIRECTION INPUT ;
    USE SIGNAL ;
    PORT
      LAYER ML2 ;
        RECT 17.500 9.000 19.500 11.000 ;
    END
  END D
  PIN R
    DIRECTION INPUT ;
    USE SIGNAL ;
    PORT
      LAYER ML2 ;
        RECT 49.500 10.500 51.500 12.500 ;
    END
  END R
  PIN Q
    DIRECTION INPUT ;
    USE SIGNAL ;
    PORT
      LAYER ML2 ;
        RECT 60.000 10.500 62.000 12.500 ;
    END
  END Q
  OBS
      LAYER ML1 ;
        RECT 3.500 20.500 5.500 26.500 ;
        RECT 7.000 20.500 9.000 26.500 ;
        RECT 13.000 20.500 15.000 26.500 ;
        RECT 21.500 20.500 23.500 26.500 ;
        RECT 31.500 20.500 33.500 26.500 ;
        RECT 40.000 20.500 42.000 26.500 ;
        RECT 50.000 20.500 52.000 26.500 ;
        RECT 59.500 20.500 61.500 26.500 ;
        RECT 1.000 14.500 3.000 16.500 ;
        RECT 4.000 14.000 5.000 20.500 ;
        RECT 7.500 19.000 8.500 20.500 ;
        RECT 11.000 19.000 13.000 19.500 ;
        RECT 7.500 18.000 13.000 19.000 ;
        RECT 4.000 12.000 6.500 14.000 ;
        RECT 7.500 13.500 8.500 18.000 ;
        RECT 11.000 17.500 13.000 18.000 ;
        RECT 14.000 16.500 15.000 20.500 ;
        RECT 22.000 19.500 23.000 20.500 ;
        RECT 32.000 19.500 33.000 20.500 ;
        RECT 40.500 19.500 41.500 20.500 ;
        RECT 22.000 18.500 29.500 19.500 ;
        RECT 32.000 18.500 36.000 19.500 ;
        RECT 40.500 18.500 48.000 19.500 ;
        RECT 27.500 17.500 29.500 18.500 ;
        RECT 34.000 17.500 36.000 18.500 ;
        RECT 46.000 17.500 48.000 18.500 ;
        RECT 51.000 17.500 52.000 20.500 ;
        RECT 22.500 16.500 24.500 17.000 ;
        RECT 38.500 16.500 40.500 17.500 ;
        RECT 13.500 15.500 40.500 16.500 ;
        RECT 51.000 16.500 56.500 17.500 ;
        RECT 10.500 13.500 12.500 14.000 ;
        RECT 7.500 12.500 12.500 13.500 ;
        RECT 4.000 4.500 5.000 12.000 ;
        RECT 7.500 7.000 8.500 12.500 ;
        RECT 10.500 12.000 12.500 12.500 ;
        RECT 13.500 10.000 14.500 15.500 ;
        RECT 22.500 15.000 24.500 15.500 ;
        RECT 44.000 14.500 46.000 15.000 ;
        RECT 51.000 14.500 52.000 16.500 ;
        RECT 54.500 15.500 56.500 16.500 ;
        RECT 15.500 13.500 17.500 14.000 ;
        RECT 20.500 13.500 22.500 14.000 ;
        RECT 35.500 13.500 37.500 14.000 ;
        RECT 41.000 13.500 43.000 14.500 ;
        RECT 15.500 12.500 43.000 13.500 ;
        RECT 44.000 13.500 55.500 14.500 ;
        RECT 44.000 13.000 46.000 13.500 ;
        RECT 15.500 12.000 17.500 12.500 ;
        RECT 20.500 12.000 22.500 12.500 ;
        RECT 35.500 12.000 37.500 12.500 ;
        RECT 13.500 9.000 15.000 10.000 ;
        RECT 17.500 9.000 19.500 11.000 ;
        RECT 27.500 10.500 29.500 11.000 ;
        RECT 23.500 9.500 29.500 10.500 ;
        RECT 11.000 7.000 13.000 7.500 ;
        RECT 7.500 6.000 13.000 7.000 ;
        RECT 7.500 4.500 8.500 6.000 ;
        RECT 11.000 5.500 13.000 6.000 ;
        RECT 14.000 7.000 15.000 9.000 ;
        RECT 20.500 7.000 22.500 7.500 ;
        RECT 14.000 6.000 22.500 7.000 ;
        RECT 14.000 4.500 15.000 6.000 ;
        RECT 20.500 5.500 22.500 6.000 ;
        RECT 23.500 4.500 24.500 9.500 ;
        RECT 27.500 9.000 29.500 9.500 ;
        RECT 31.000 10.500 33.000 11.000 ;
        RECT 49.500 10.500 51.500 12.500 ;
        RECT 31.000 9.500 51.500 10.500 ;
        RECT 54.500 10.000 55.500 13.500 ;
        RECT 60.500 12.500 61.500 20.500 ;
        RECT 60.000 10.500 62.000 12.500 ;
        RECT 31.000 9.000 33.000 9.500 ;
        RECT 54.500 9.000 56.500 10.000 ;
        RECT 52.500 8.000 56.500 9.000 ;
        RECT 25.500 7.000 27.500 8.000 ;
        RECT 33.500 7.000 35.500 8.000 ;
        RECT 43.500 7.000 45.500 8.000 ;
        RECT 25.500 6.000 35.500 7.000 ;
        RECT 38.500 6.000 45.500 7.000 ;
        RECT 52.500 6.500 53.500 8.000 ;
        RECT 30.000 4.500 31.000 6.000 ;
        RECT 38.500 4.500 39.500 6.000 ;
        RECT 46.500 5.500 53.500 6.500 ;
        RECT 46.500 4.500 47.500 5.500 ;
        RECT 60.500 4.500 61.500 10.500 ;
        RECT 3.500 2.500 5.500 4.500 ;
        RECT 7.000 2.500 9.000 4.500 ;
        RECT 13.000 2.500 15.000 4.500 ;
        RECT 21.500 3.500 24.500 4.500 ;
        RECT 21.500 2.500 23.500 3.500 ;
        RECT 29.500 2.500 31.500 4.500 ;
        RECT 37.500 2.500 39.500 4.500 ;
        RECT 45.500 2.500 47.500 4.500 ;
        RECT 59.500 2.500 61.500 4.500 ;
      LAYER ML2 ;
        RECT 27.500 17.500 29.500 19.500 ;
        RECT 34.000 17.500 36.000 19.500 ;
        RECT 46.000 17.500 48.000 19.500 ;
        RECT 28.000 11.000 29.000 17.500 ;
        RECT 27.500 9.000 29.500 11.000 ;
        RECT 34.000 8.000 35.000 17.500 ;
        RECT 46.000 16.500 47.000 17.500 ;
        RECT 44.500 15.500 47.000 16.500 ;
        RECT 44.500 8.000 45.500 15.500 ;
        RECT 33.500 6.000 35.500 8.000 ;
        RECT 43.500 6.000 45.500 8.000 ;
      LAYER POL ;
        RECT 2.500 16.500 3.500 27.500 ;
        RECT 9.000 17.500 10.000 27.500 ;
        RECT 12.000 19.500 13.000 27.500 ;
        RECT 11.000 17.500 13.000 19.500 ;
        RECT 1.000 14.500 3.500 16.500 ;
        RECT 2.500 1.500 3.500 14.500 ;
        RECT 8.500 16.500 10.000 17.500 ;
        RECT 8.500 14.000 9.500 16.500 ;
        RECT 4.500 12.000 9.500 14.000 ;
        RECT 10.500 13.500 12.500 14.000 ;
        RECT 15.500 13.500 17.500 14.000 ;
        RECT 10.500 12.500 17.500 13.500 ;
        RECT 10.500 12.000 12.500 12.500 ;
        RECT 15.500 12.000 17.500 12.500 ;
        RECT 8.500 11.000 9.500 12.000 ;
        RECT 18.500 11.000 19.500 27.500 ;
        RECT 20.500 14.000 21.500 27.500 ;
        RECT 23.500 17.000 24.500 27.500 ;
        RECT 22.500 15.000 24.500 17.000 ;
        RECT 20.500 12.000 22.500 14.000 ;
        RECT 8.500 10.000 10.000 11.000 ;
        RECT 9.000 1.500 10.000 10.000 ;
        RECT 17.500 9.000 19.500 11.000 ;
        RECT 21.500 10.500 22.500 12.000 ;
        RECT 21.500 9.500 24.500 10.500 ;
        RECT 11.000 5.500 13.000 7.500 ;
        RECT 12.000 1.500 13.000 5.500 ;
        RECT 18.500 1.500 19.500 9.000 ;
        RECT 20.500 5.500 22.500 7.500 ;
        RECT 20.500 1.500 21.500 5.500 ;
        RECT 23.500 1.500 24.500 9.500 ;
        RECT 25.500 8.000 26.500 27.500 ;
        RECT 28.500 19.500 29.500 27.500 ;
        RECT 27.500 17.500 29.500 19.500 ;
        RECT 30.500 11.000 31.500 27.500 ;
        RECT 37.000 19.500 38.000 27.500 ;
        RECT 34.000 18.500 38.000 19.500 ;
        RECT 34.000 17.500 36.000 18.500 ;
        RECT 39.000 17.500 40.000 27.500 ;
        RECT 38.500 15.500 40.500 17.500 ;
        RECT 35.500 12.000 37.500 14.000 ;
        RECT 27.500 9.000 29.500 11.000 ;
        RECT 30.500 9.000 33.000 11.000 ;
        RECT 25.500 6.000 27.500 8.000 ;
        RECT 25.500 1.500 26.500 6.000 ;
        RECT 28.500 1.500 29.500 9.000 ;
        RECT 31.500 1.500 32.500 9.000 ;
        RECT 33.500 6.000 35.500 8.000 ;
        RECT 34.500 1.500 35.500 6.000 ;
        RECT 36.500 1.500 37.500 12.000 ;
        RECT 39.000 9.000 40.000 15.500 ;
        RECT 42.000 14.500 43.000 27.500 ;
        RECT 41.000 12.500 43.000 14.500 ;
        RECT 44.000 15.000 45.000 27.500 ;
        RECT 47.000 19.500 48.000 27.500 ;
        RECT 46.000 17.500 48.000 19.500 ;
        RECT 44.000 13.000 46.000 15.000 ;
        RECT 44.000 11.500 45.000 13.000 ;
        RECT 41.500 10.500 45.000 11.500 ;
        RECT 49.000 12.500 50.000 27.500 ;
        RECT 55.500 17.500 56.500 27.500 ;
        RECT 58.500 19.500 59.500 27.500 ;
        RECT 57.500 17.500 59.500 19.500 ;
        RECT 54.500 15.500 56.500 17.500 ;
        RECT 49.000 10.500 51.500 12.500 ;
        RECT 39.000 8.000 40.500 9.000 ;
        RECT 39.500 1.500 40.500 8.000 ;
        RECT 41.500 1.500 42.500 10.500 ;
        RECT 49.000 8.000 50.000 10.500 ;
        RECT 54.500 8.000 56.500 10.000 ;
        RECT 43.500 6.000 45.500 8.000 ;
        RECT 44.500 1.500 45.500 6.000 ;
        RECT 47.500 7.000 50.000 8.000 ;
        RECT 47.500 1.500 48.500 7.000 ;
        RECT 55.500 1.500 56.500 8.000 ;
        RECT 57.500 5.500 59.500 7.500 ;
        RECT 58.500 1.500 59.500 5.500 ;
  END
END rff1m2_r

#--------EOF---------

MACRO sff1
  CLASS CORE ;
  FOREIGN sff1 ;
  ORIGIN 0.000 0.000 ;
  SIZE 56.000 BY 29.000 ;
  SYMMETRY X Y R90 ;
  SITE core ;
  PIN VDD
    DIRECTION INOUT ;
    USE POWER ;
    SHAPE ABUTMENT ;
    PORT
      LAYER ML1 ;
        RECT -0.500 28.000 56.500 30.000 ;
        RECT 3.500 20.500 5.500 28.000 ;
        RECT 10.000 20.500 12.000 28.000 ;
        RECT 20.000 20.500 22.000 28.000 ;
        RECT 26.000 20.500 28.000 28.000 ;
        RECT 37.500 20.500 39.500 28.000 ;
        RECT 43.500 20.500 45.500 28.000 ;
        RECT 50.000 20.500 52.000 28.000 ;
    END
  END VDD
  PIN VSS
    DIRECTION INOUT ;
    USE GROUND ;
    SHAPE ABUTMENT ;
    PORT
      LAYER ML1 ;
        RECT 3.500 1.000 5.500 4.800 ;
        RECT 10.000 1.000 12.000 4.800 ;
        RECT 20.000 1.000 22.000 4.800 ;
        RECT 28.500 1.000 30.500 4.800 ;
        RECT 38.500 1.000 40.500 4.800 ;
        RECT 50.000 1.000 52.000 4.800 ;
        RECT -0.500 -1.000 56.500 1.000 ;
    END
  END VSS
  PIN QB
    DIRECTION INPUT ;
    USE SIGNAL ;
    PORT
      LAYER ML1 ;
        RECT 47.000 20.500 49.000 26.500 ;
        RECT 48.000 19.500 49.000 20.500 ;
        RECT 48.000 18.500 53.000 19.500 ;
        RECT 51.000 17.500 53.000 18.500 ;
        RECT 51.500 7.500 52.500 17.500 ;
        RECT 51.000 6.500 53.000 7.500 ;
        RECT 48.000 5.500 53.000 6.500 ;
        RECT 48.000 4.500 49.000 5.500 ;
        RECT 47.000 2.500 49.000 4.500 ;
    END
  END QB
  PIN CK
    DIRECTION INPUT ;
    USE SIGNAL ;
    PORT
      LAYER ML2 ;
        RECT 3.500 9.000 5.500 11.000 ;
    END
  END CK
  PIN D
    DIRECTION INPUT ;
    USE SIGNAL ;
    PORT
      LAYER ML2 ;
        RECT 11.000 9.000 13.000 11.000 ;
    END
  END D
  PIN S
    DIRECTION INPUT ;
    USE SIGNAL ;
    PORT
      LAYER ML2 ;
        RECT 43.000 10.000 45.000 12.000 ;
    END
  END S
  PIN Q
    DIRECTION INPUT ;
    USE SIGNAL ;
    PORT
      LAYER ML2 ;
        RECT 53.500 10.500 55.500 12.500 ;
    END
  END Q
  OBS
      LAYER ML1 ;
        RECT 0.500 20.500 2.500 26.500 ;
        RECT 6.500 20.500 8.500 26.500 ;
        RECT 15.000 20.500 17.000 26.500 ;
        RECT 23.000 20.500 25.000 26.500 ;
        RECT 32.500 20.500 34.500 26.500 ;
        RECT 40.500 20.500 42.500 26.500 ;
        RECT 53.000 20.500 55.000 26.500 ;
        RECT 1.000 19.000 2.000 20.500 ;
        RECT 4.500 19.000 6.500 19.500 ;
        RECT 1.000 18.000 6.500 19.000 ;
        RECT 1.000 13.500 2.000 18.000 ;
        RECT 4.500 17.500 6.500 18.000 ;
        RECT 7.500 16.000 8.500 20.500 ;
        RECT 15.500 19.500 16.500 20.500 ;
        RECT 24.000 19.500 25.000 20.500 ;
        RECT 33.500 19.500 34.500 20.500 ;
        RECT 15.500 18.500 23.000 19.500 ;
        RECT 24.000 19.000 29.000 19.500 ;
        RECT 24.000 18.500 29.500 19.000 ;
        RECT 33.500 18.500 40.500 19.500 ;
        RECT 21.000 17.500 23.000 18.500 ;
        RECT 27.500 17.000 29.500 18.500 ;
        RECT 38.500 17.500 40.500 18.500 ;
        RECT 41.500 17.500 42.500 20.500 ;
        RECT 16.000 16.000 18.000 17.000 ;
        RECT 41.500 16.500 50.000 17.500 ;
        RECT 30.500 16.000 32.500 16.500 ;
        RECT 7.000 15.000 32.500 16.000 ;
        RECT 4.000 13.500 6.000 14.000 ;
        RECT 1.000 12.500 6.000 13.500 ;
        RECT 1.000 6.500 2.000 12.500 ;
        RECT 4.000 12.000 6.000 12.500 ;
        RECT 3.500 9.000 5.500 11.000 ;
        RECT 7.000 10.000 8.000 15.000 ;
        RECT 30.500 14.500 32.500 15.000 ;
        RECT 38.000 15.500 42.500 16.500 ;
        RECT 48.000 15.500 50.000 16.500 ;
        RECT 38.000 14.000 39.000 15.500 ;
        RECT 9.000 13.000 11.000 14.000 ;
        RECT 34.500 13.000 36.500 14.000 ;
        RECT 9.000 12.000 36.500 13.000 ;
        RECT 37.500 12.000 39.500 14.000 ;
        RECT 14.000 11.000 16.000 12.000 ;
        RECT 29.500 11.000 31.500 12.000 ;
        RECT 7.000 9.000 8.500 10.000 ;
        RECT 11.000 9.000 13.000 11.000 ;
        RECT 21.000 10.000 23.000 11.000 ;
        RECT 17.000 9.000 23.000 10.000 ;
        RECT 24.000 10.000 26.000 11.000 ;
        RECT 42.500 10.000 45.000 12.000 ;
        RECT 24.000 9.000 43.500 10.000 ;
        RECT 49.000 9.500 50.000 15.500 ;
        RECT 54.000 12.500 55.000 20.500 ;
        RECT 53.500 10.500 55.500 12.500 ;
        RECT 4.500 6.500 6.500 7.500 ;
        RECT 1.000 5.500 6.500 6.500 ;
        RECT 7.500 7.000 8.500 9.000 ;
        RECT 14.000 7.000 16.000 7.500 ;
        RECT 7.500 6.000 16.000 7.000 ;
        RECT 1.000 4.500 2.000 5.500 ;
        RECT 7.500 4.500 8.500 6.000 ;
        RECT 14.000 5.500 16.000 6.000 ;
        RECT 17.000 4.500 18.000 9.000 ;
        RECT 48.000 8.500 50.000 9.500 ;
        RECT 44.500 7.500 50.000 8.500 ;
        RECT 19.000 6.500 21.000 7.500 ;
        RECT 26.500 6.500 28.500 7.500 ;
        RECT 39.500 6.500 41.500 7.500 ;
        RECT 19.000 5.500 28.500 6.500 ;
        RECT 34.500 5.500 41.500 6.500 ;
        RECT 26.000 4.500 27.000 5.500 ;
        RECT 34.500 4.500 35.500 5.500 ;
        RECT 44.500 4.500 45.500 7.500 ;
        RECT 54.000 4.500 55.000 10.500 ;
        RECT 0.500 2.500 2.500 4.500 ;
        RECT 6.500 2.500 8.500 4.500 ;
        RECT 15.000 3.500 18.000 4.500 ;
        RECT 15.000 2.500 17.000 3.500 ;
        RECT 25.000 2.500 27.000 4.500 ;
        RECT 33.500 2.500 35.500 4.500 ;
        RECT 43.500 2.500 45.500 4.500 ;
        RECT 53.000 2.500 55.000 4.500 ;
      LAYER POL ;
        RECT 2.500 18.500 3.500 27.500 ;
        RECT 5.500 19.500 6.500 27.500 ;
        RECT 2.000 17.500 3.500 18.500 ;
        RECT 4.500 17.500 6.500 19.500 ;
        RECT 2.000 11.000 3.000 17.500 ;
        RECT 4.000 13.500 6.000 14.000 ;
        RECT 9.000 13.500 11.000 14.000 ;
        RECT 4.000 12.500 11.000 13.500 ;
        RECT 4.000 12.000 6.000 12.500 ;
        RECT 9.000 12.000 11.000 12.500 ;
        RECT 12.000 11.000 13.000 27.500 ;
        RECT 14.000 13.000 15.000 27.500 ;
        RECT 17.000 17.000 18.000 27.500 ;
        RECT 16.000 15.000 18.000 17.000 ;
        RECT 14.000 12.000 16.000 13.000 ;
        RECT 14.000 11.000 18.000 12.000 ;
        RECT 2.000 10.000 5.500 11.000 ;
        RECT 2.500 9.000 5.500 10.000 ;
        RECT 11.000 9.000 13.000 11.000 ;
        RECT 2.500 1.500 3.500 9.000 ;
        RECT 4.500 5.500 6.500 7.500 ;
        RECT 5.500 1.500 6.500 5.500 ;
        RECT 12.000 1.500 13.000 9.000 ;
        RECT 14.000 5.500 16.000 7.500 ;
        RECT 14.000 1.500 15.000 5.500 ;
        RECT 17.000 1.500 18.000 11.000 ;
        RECT 19.000 7.500 20.000 27.500 ;
        RECT 22.000 19.500 23.000 27.500 ;
        RECT 25.000 19.500 26.000 27.500 ;
        RECT 21.000 17.500 23.000 19.500 ;
        RECT 22.000 11.000 23.000 17.500 ;
        RECT 21.000 9.000 23.000 11.000 ;
        RECT 19.000 5.500 21.000 7.500 ;
        RECT 19.000 1.500 20.000 5.500 ;
        RECT 22.000 1.500 23.000 9.000 ;
        RECT 24.000 18.500 26.000 19.500 ;
        RECT 28.000 19.000 29.000 27.500 ;
        RECT 24.000 11.000 25.000 18.500 ;
        RECT 27.500 17.000 29.500 19.000 ;
        RECT 24.000 9.000 26.000 11.000 ;
        RECT 24.000 1.500 25.000 9.000 ;
        RECT 27.500 7.500 28.500 17.000 ;
        RECT 31.500 16.500 32.500 27.500 ;
        RECT 30.500 15.500 32.500 16.500 ;
        RECT 30.500 14.500 33.500 15.500 ;
        RECT 29.500 11.000 31.500 13.000 ;
        RECT 29.500 8.500 30.500 11.000 ;
        RECT 32.500 10.500 33.500 14.500 ;
        RECT 34.500 14.000 35.500 27.500 ;
        RECT 36.500 16.000 37.500 27.500 ;
        RECT 39.500 19.500 40.500 27.500 ;
        RECT 38.500 17.500 40.500 19.500 ;
        RECT 39.500 16.500 40.500 17.500 ;
        RECT 36.500 15.000 38.500 16.000 ;
        RECT 39.500 15.500 41.500 16.500 ;
        RECT 37.500 14.000 38.500 15.000 ;
        RECT 34.500 12.000 36.500 14.000 ;
        RECT 37.500 12.000 39.500 14.000 ;
        RECT 32.500 9.500 36.500 10.500 ;
        RECT 29.500 7.500 33.500 8.500 ;
        RECT 26.500 6.500 28.500 7.500 ;
        RECT 26.500 5.500 31.500 6.500 ;
        RECT 30.500 1.500 31.500 5.500 ;
        RECT 32.500 1.500 33.500 7.500 ;
        RECT 35.500 1.500 36.500 9.500 ;
        RECT 37.500 1.500 38.500 12.000 ;
        RECT 40.500 7.500 41.500 15.500 ;
        RECT 39.500 5.500 41.500 7.500 ;
        RECT 40.500 1.500 41.500 5.500 ;
        RECT 42.500 12.000 43.500 27.500 ;
        RECT 49.000 17.500 50.000 27.500 ;
        RECT 52.000 19.500 53.000 27.500 ;
        RECT 51.000 17.500 53.000 19.500 ;
        RECT 48.000 15.500 50.000 17.500 ;
        RECT 42.500 10.000 45.000 12.000 ;
        RECT 42.500 1.500 43.500 10.000 ;
        RECT 48.000 7.500 50.000 9.500 ;
        RECT 49.000 1.500 50.000 7.500 ;
        RECT 51.000 5.500 53.000 7.500 ;
        RECT 52.000 1.500 53.000 5.500 ;
  END
END sff1

#--------EOF---------

MACRO sff1_r
  CLASS CORE ;
  FOREIGN sff1_r ;
  ORIGIN 0.000 0.000 ;
  SIZE 62.500 BY 29.000 ;
  SYMMETRY X Y R90 ;
  SITE core ;
  PIN QB
    DIRECTION INPUT ;
    USE SIGNAL ;
    PORT
      LAYER ML1 ;
        RECT 53.500 20.500 55.500 26.500 ;
        RECT 54.500 19.500 55.500 20.500 ;
        RECT 54.500 18.500 59.500 19.500 ;
        RECT 57.500 17.500 59.500 18.500 ;
        RECT 58.000 7.500 59.000 17.500 ;
        RECT 57.500 6.500 59.500 7.500 ;
        RECT 54.500 5.500 59.500 6.500 ;
        RECT 54.500 4.500 55.500 5.500 ;
        RECT 53.500 2.500 55.500 4.500 ;
    END
  END QB
  PIN VDD
    DIRECTION INOUT ;
    USE POWER ;
    SHAPE ABUTMENT ;
    PORT
      LAYER ML1 ;
        RECT -0.500 28.000 63.000 30.000 ;
        RECT 0.500 20.500 2.500 28.000 ;
        RECT 10.000 20.500 12.000 28.000 ;
        RECT 16.500 20.500 18.500 28.000 ;
        RECT 26.500 20.500 28.500 28.000 ;
        RECT 32.500 20.500 34.500 28.000 ;
        RECT 44.000 20.500 46.000 28.000 ;
        RECT 50.000 20.500 52.000 28.000 ;
        RECT 56.500 20.500 58.500 28.000 ;
    END
  END VDD
  PIN VSS
    DIRECTION INOUT ;
    USE GROUND ;
    SHAPE ABUTMENT ;
    PORT
      LAYER ML1 ;
        RECT 0.500 1.000 2.500 4.500 ;
        RECT 10.000 1.000 12.000 4.800 ;
        RECT 16.500 1.000 18.500 4.800 ;
        RECT 26.500 1.000 28.500 4.800 ;
        RECT 35.000 1.000 37.000 4.800 ;
        RECT 45.000 1.000 47.000 4.800 ;
        RECT 56.500 1.000 58.500 4.800 ;
        RECT -0.500 -1.000 63.000 1.000 ;
    END
  END VSS
  PIN D
    DIRECTION INPUT ;
    USE SIGNAL ;
    PORT
      LAYER ML2 ;
        RECT 17.500 9.000 19.500 11.000 ;
    END
  END D
  PIN S
    DIRECTION INPUT ;
    USE SIGNAL ;
    PORT
      LAYER ML2 ;
        RECT 49.500 10.000 51.500 12.000 ;
    END
  END S
  PIN Q
    DIRECTION INPUT ;
    USE SIGNAL ;
    PORT
      LAYER ML2 ;
        RECT 60.000 10.500 62.000 12.500 ;
    END
  END Q
  PIN CK
    DIRECTION INPUT ;
    USE SIGNAL ;
    PORT
      LAYER ML2 ;
        RECT 1.000 14.500 3.000 16.500 ;
    END
  END CK
  OBS
      LAYER ML1 ;
        RECT 3.500 20.500 5.500 26.500 ;
        RECT 7.000 20.500 9.000 26.500 ;
        RECT 13.000 20.500 15.000 26.500 ;
        RECT 21.500 20.500 23.500 26.500 ;
        RECT 29.500 20.500 31.500 26.500 ;
        RECT 39.000 20.500 41.000 26.500 ;
        RECT 47.000 20.500 49.000 26.500 ;
        RECT 59.500 20.500 61.500 26.500 ;
        RECT 1.000 14.500 3.000 16.500 ;
        RECT 4.000 14.000 5.000 20.500 ;
        RECT 7.500 19.000 8.500 20.500 ;
        RECT 11.000 19.000 13.000 19.500 ;
        RECT 7.500 18.000 13.000 19.000 ;
        RECT 4.000 12.000 6.500 14.000 ;
        RECT 7.500 13.500 8.500 18.000 ;
        RECT 11.000 17.500 13.000 18.000 ;
        RECT 14.000 16.000 15.000 20.500 ;
        RECT 22.000 19.500 23.000 20.500 ;
        RECT 30.500 19.500 31.500 20.500 ;
        RECT 40.000 19.500 41.000 20.500 ;
        RECT 22.000 18.500 29.500 19.500 ;
        RECT 30.500 19.000 35.500 19.500 ;
        RECT 30.500 18.500 36.000 19.000 ;
        RECT 40.000 18.500 47.000 19.500 ;
        RECT 27.500 17.500 29.500 18.500 ;
        RECT 34.000 17.000 36.000 18.500 ;
        RECT 45.000 17.500 47.000 18.500 ;
        RECT 48.000 17.500 49.000 20.500 ;
        RECT 22.500 16.000 24.500 17.000 ;
        RECT 48.000 16.500 56.500 17.500 ;
        RECT 37.000 16.000 39.000 16.500 ;
        RECT 13.500 15.000 39.000 16.000 ;
        RECT 10.500 13.500 12.500 14.000 ;
        RECT 7.500 12.500 12.500 13.500 ;
        RECT 4.000 4.500 5.000 12.000 ;
        RECT 7.500 6.500 8.500 12.500 ;
        RECT 10.500 12.000 12.500 12.500 ;
        RECT 13.500 10.000 14.500 15.000 ;
        RECT 37.000 14.500 39.000 15.000 ;
        RECT 44.500 15.500 49.000 16.500 ;
        RECT 54.500 15.500 56.500 16.500 ;
        RECT 44.500 14.000 45.500 15.500 ;
        RECT 15.500 13.000 17.500 14.000 ;
        RECT 41.000 13.000 43.000 14.000 ;
        RECT 15.500 12.000 43.000 13.000 ;
        RECT 44.000 12.000 46.000 14.000 ;
        RECT 20.500 11.000 22.500 12.000 ;
        RECT 36.000 11.000 38.000 12.000 ;
        RECT 13.500 9.000 15.000 10.000 ;
        RECT 17.500 9.000 19.500 11.000 ;
        RECT 27.500 10.000 29.500 11.000 ;
        RECT 23.500 9.000 29.500 10.000 ;
        RECT 30.500 10.000 32.500 11.000 ;
        RECT 49.000 10.000 51.500 12.000 ;
        RECT 30.500 9.000 50.000 10.000 ;
        RECT 55.500 9.500 56.500 15.500 ;
        RECT 60.500 12.500 61.500 20.500 ;
        RECT 60.000 10.500 62.000 12.500 ;
        RECT 11.000 6.500 13.000 7.500 ;
        RECT 7.500 5.500 13.000 6.500 ;
        RECT 14.000 7.000 15.000 9.000 ;
        RECT 20.500 7.000 22.500 7.500 ;
        RECT 14.000 6.000 22.500 7.000 ;
        RECT 7.500 4.500 8.500 5.500 ;
        RECT 14.000 4.500 15.000 6.000 ;
        RECT 20.500 5.500 22.500 6.000 ;
        RECT 23.500 4.500 24.500 9.000 ;
        RECT 54.500 8.500 56.500 9.500 ;
        RECT 51.000 7.500 56.500 8.500 ;
        RECT 25.500 6.500 27.500 7.500 ;
        RECT 33.000 6.500 35.000 7.500 ;
        RECT 46.000 6.500 48.000 7.500 ;
        RECT 25.500 5.500 35.000 6.500 ;
        RECT 41.000 5.500 48.000 6.500 ;
        RECT 32.500 4.500 33.500 5.500 ;
        RECT 41.000 4.500 42.000 5.500 ;
        RECT 51.000 4.500 52.000 7.500 ;
        RECT 60.500 4.500 61.500 10.500 ;
        RECT 3.500 2.500 5.500 4.500 ;
        RECT 7.000 2.500 9.000 4.500 ;
        RECT 13.000 2.500 15.000 4.500 ;
        RECT 21.500 3.500 24.500 4.500 ;
        RECT 21.500 2.500 23.500 3.500 ;
        RECT 31.500 2.500 33.500 4.500 ;
        RECT 40.000 2.500 42.000 4.500 ;
        RECT 50.000 2.500 52.000 4.500 ;
        RECT 59.500 2.500 61.500 4.500 ;
      LAYER POL ;
        RECT 2.500 16.500 3.500 27.500 ;
        RECT 9.000 18.500 10.000 27.500 ;
        RECT 12.000 19.500 13.000 27.500 ;
        RECT 1.000 14.500 3.500 16.500 ;
        RECT 2.500 1.500 3.500 14.500 ;
        RECT 8.500 17.500 10.000 18.500 ;
        RECT 11.000 17.500 13.000 19.500 ;
        RECT 8.500 14.000 9.500 17.500 ;
        RECT 4.500 12.000 9.500 14.000 ;
        RECT 10.500 13.500 12.500 14.000 ;
        RECT 15.500 13.500 17.500 14.000 ;
        RECT 10.500 12.500 17.500 13.500 ;
        RECT 10.500 12.000 12.500 12.500 ;
        RECT 15.500 12.000 17.500 12.500 ;
        RECT 8.500 11.000 9.500 12.000 ;
        RECT 18.500 11.000 19.500 27.500 ;
        RECT 20.500 13.000 21.500 27.500 ;
        RECT 23.500 17.000 24.500 27.500 ;
        RECT 22.500 15.000 24.500 17.000 ;
        RECT 20.500 12.000 22.500 13.000 ;
        RECT 20.500 11.000 24.500 12.000 ;
        RECT 8.500 10.000 10.000 11.000 ;
        RECT 9.000 1.500 10.000 10.000 ;
        RECT 17.500 9.000 19.500 11.000 ;
        RECT 11.000 5.500 13.000 7.500 ;
        RECT 12.000 1.500 13.000 5.500 ;
        RECT 18.500 1.500 19.500 9.000 ;
        RECT 20.500 5.500 22.500 7.500 ;
        RECT 20.500 1.500 21.500 5.500 ;
        RECT 23.500 1.500 24.500 11.000 ;
        RECT 25.500 7.500 26.500 27.500 ;
        RECT 28.500 19.500 29.500 27.500 ;
        RECT 31.500 19.500 32.500 27.500 ;
        RECT 27.500 17.500 29.500 19.500 ;
        RECT 28.500 11.000 29.500 17.500 ;
        RECT 27.500 9.000 29.500 11.000 ;
        RECT 25.500 5.500 27.500 7.500 ;
        RECT 25.500 1.500 26.500 5.500 ;
        RECT 28.500 1.500 29.500 9.000 ;
        RECT 30.500 18.500 32.500 19.500 ;
        RECT 34.500 19.000 35.500 27.500 ;
        RECT 30.500 11.000 31.500 18.500 ;
        RECT 34.000 17.000 36.000 19.000 ;
        RECT 30.500 9.000 32.500 11.000 ;
        RECT 30.500 1.500 31.500 9.000 ;
        RECT 34.000 7.500 35.000 17.000 ;
        RECT 38.000 16.500 39.000 27.500 ;
        RECT 37.000 15.500 39.000 16.500 ;
        RECT 37.000 14.500 40.000 15.500 ;
        RECT 36.000 11.000 38.000 13.000 ;
        RECT 36.000 8.500 37.000 11.000 ;
        RECT 39.000 10.500 40.000 14.500 ;
        RECT 41.000 14.000 42.000 27.500 ;
        RECT 43.000 16.000 44.000 27.500 ;
        RECT 46.000 19.500 47.000 27.500 ;
        RECT 45.000 17.500 47.000 19.500 ;
        RECT 46.000 16.500 47.000 17.500 ;
        RECT 43.000 15.000 45.000 16.000 ;
        RECT 46.000 15.500 48.000 16.500 ;
        RECT 44.000 14.000 45.000 15.000 ;
        RECT 41.000 12.000 43.000 14.000 ;
        RECT 44.000 12.000 46.000 14.000 ;
        RECT 39.000 9.500 43.000 10.500 ;
        RECT 36.000 7.500 40.000 8.500 ;
        RECT 33.000 6.500 35.000 7.500 ;
        RECT 33.000 5.500 38.000 6.500 ;
        RECT 37.000 1.500 38.000 5.500 ;
        RECT 39.000 1.500 40.000 7.500 ;
        RECT 42.000 1.500 43.000 9.500 ;
        RECT 44.000 1.500 45.000 12.000 ;
        RECT 47.000 7.500 48.000 15.500 ;
        RECT 46.000 5.500 48.000 7.500 ;
        RECT 47.000 1.500 48.000 5.500 ;
        RECT 49.000 12.000 50.000 27.500 ;
        RECT 55.500 17.500 56.500 27.500 ;
        RECT 58.500 19.500 59.500 27.500 ;
        RECT 57.500 17.500 59.500 19.500 ;
        RECT 54.500 15.500 56.500 17.500 ;
        RECT 49.000 10.000 51.500 12.000 ;
        RECT 49.000 1.500 50.000 10.000 ;
        RECT 54.500 7.500 56.500 9.500 ;
        RECT 55.500 1.500 56.500 7.500 ;
        RECT 57.500 5.500 59.500 7.500 ;
        RECT 58.500 1.500 59.500 5.500 ;
  END
END sff1_r

#--------EOF---------

MACRO sff1m2
  CLASS CORE ;
  FOREIGN sff1m2 ;
  ORIGIN 0.000 0.000 ;
  SIZE 56.000 BY 29.000 ;
  SYMMETRY X Y R90 ;
  SITE core ;
  PIN VDD
    DIRECTION INOUT ;
    USE POWER ;
    SHAPE ABUTMENT ;
    PORT
      LAYER ML1 ;
        RECT -0.500 28.000 56.500 30.000 ;
        RECT 3.500 20.500 5.500 28.000 ;
        RECT 10.000 20.500 12.000 28.000 ;
        RECT 20.000 20.500 22.000 28.000 ;
        RECT 26.000 20.500 28.000 28.000 ;
        RECT 36.000 20.500 38.000 28.000 ;
        RECT 42.000 20.500 44.000 28.000 ;
        RECT 50.000 20.500 52.000 28.000 ;
    END
  END VDD
  PIN VSS
    DIRECTION INOUT ;
    USE GROUND ;
    SHAPE ABUTMENT ;
    PORT
      LAYER ML1 ;
        RECT 3.500 1.000 5.500 4.800 ;
        RECT 10.000 1.000 12.000 4.800 ;
        RECT 20.000 1.000 22.000 4.800 ;
        RECT 28.500 1.000 30.500 4.800 ;
        RECT 38.500 1.000 40.500 4.800 ;
        RECT 50.000 1.000 52.000 4.800 ;
        RECT -0.500 -1.000 56.500 1.000 ;
    END
  END VSS
  PIN QB
    DIRECTION INPUT ;
    USE SIGNAL ;
    PORT
      LAYER ML1 ;
        RECT 47.000 20.500 49.000 26.500 ;
        RECT 48.000 19.500 49.000 20.500 ;
        RECT 48.000 18.500 53.000 19.500 ;
        RECT 51.000 17.500 53.000 18.500 ;
        RECT 51.500 7.500 52.500 17.500 ;
        RECT 51.000 6.500 53.000 7.500 ;
        RECT 48.000 5.500 53.000 6.500 ;
        RECT 48.000 4.500 49.000 5.500 ;
        RECT 47.000 2.500 49.000 4.500 ;
    END
  END QB
  PIN Q
    DIRECTION INPUT ;
    USE SIGNAL ;
    PORT
      LAYER ML2 ;
        RECT 53.500 10.500 55.500 12.500 ;
    END
  END Q
  PIN S
    DIRECTION INPUT ;
    USE SIGNAL ;
    PORT
      LAYER ML2 ;
        RECT 43.000 10.500 45.000 12.500 ;
    END
  END S
  PIN D
    DIRECTION INPUT ;
    USE SIGNAL ;
    PORT
      LAYER ML2 ;
        RECT 11.000 9.000 13.000 11.000 ;
    END
  END D
  PIN CK
    DIRECTION INPUT ;
    USE SIGNAL ;
    PORT
      LAYER ML2 ;
        RECT 3.500 9.000 5.500 11.000 ;
    END
  END CK
  OBS
      LAYER ML1 ;
        RECT 0.500 20.500 2.500 26.500 ;
        RECT 6.500 20.500 8.500 26.500 ;
        RECT 15.000 20.500 17.000 26.500 ;
        RECT 23.000 20.500 25.000 26.500 ;
        RECT 31.000 20.500 33.000 26.500 ;
        RECT 39.000 20.500 41.000 26.500 ;
        RECT 53.000 20.500 55.000 26.500 ;
        RECT 1.000 19.000 2.000 20.500 ;
        RECT 4.500 19.000 6.500 19.500 ;
        RECT 1.000 18.000 6.500 19.000 ;
        RECT 1.000 13.500 2.000 18.000 ;
        RECT 4.500 17.500 6.500 18.000 ;
        RECT 7.500 16.500 8.500 20.500 ;
        RECT 15.500 19.000 16.500 20.500 ;
        RECT 24.000 19.500 25.000 20.500 ;
        RECT 32.000 19.500 33.000 20.500 ;
        RECT 21.000 19.000 23.000 19.500 ;
        RECT 15.500 18.000 23.000 19.000 ;
        RECT 24.000 18.500 29.000 19.500 ;
        RECT 32.000 18.500 39.000 19.500 ;
        RECT 21.000 17.500 23.000 18.000 ;
        RECT 27.000 17.500 29.000 18.500 ;
        RECT 37.000 17.500 39.000 18.500 ;
        RECT 40.000 17.500 41.000 20.500 ;
        RECT 16.000 16.500 18.000 17.000 ;
        RECT 30.000 16.500 32.000 17.500 ;
        RECT 7.000 15.500 32.000 16.500 ;
        RECT 40.000 16.500 50.000 17.500 ;
        RECT 4.000 13.500 6.000 14.000 ;
        RECT 1.000 12.500 6.000 13.500 ;
        RECT 1.000 6.500 2.000 12.500 ;
        RECT 4.000 12.000 6.000 12.500 ;
        RECT 3.500 9.000 5.500 11.000 ;
        RECT 7.000 10.000 8.000 15.500 ;
        RECT 16.000 15.000 18.000 15.500 ;
        RECT 37.000 14.500 39.000 15.000 ;
        RECT 40.000 14.500 41.000 16.500 ;
        RECT 48.000 15.500 50.000 16.500 ;
        RECT 9.000 13.500 11.000 14.000 ;
        RECT 14.000 13.500 16.000 14.000 ;
        RECT 27.000 13.500 29.000 14.000 ;
        RECT 32.000 13.500 34.000 14.500 ;
        RECT 9.000 12.500 34.000 13.500 ;
        RECT 37.000 13.500 49.000 14.500 ;
        RECT 37.000 13.000 39.000 13.500 ;
        RECT 9.000 12.000 11.000 12.500 ;
        RECT 14.000 12.000 16.000 12.500 ;
        RECT 27.000 12.000 29.000 12.500 ;
        RECT 7.000 9.000 8.500 10.000 ;
        RECT 11.000 9.000 13.000 11.000 ;
        RECT 21.000 10.500 23.000 11.000 ;
        RECT 17.000 9.500 23.000 10.500 ;
        RECT 4.500 6.500 6.500 7.500 ;
        RECT 1.000 5.500 6.500 6.500 ;
        RECT 7.500 6.500 8.500 9.000 ;
        RECT 14.000 6.500 16.000 7.500 ;
        RECT 7.500 5.500 16.000 6.500 ;
        RECT 1.000 4.500 2.000 5.500 ;
        RECT 7.500 4.500 8.500 5.500 ;
        RECT 17.000 4.500 18.000 9.500 ;
        RECT 21.000 9.000 23.000 9.500 ;
        RECT 24.500 10.500 26.500 11.000 ;
        RECT 43.000 10.500 45.000 12.500 ;
        RECT 24.500 9.500 45.000 10.500 ;
        RECT 48.000 9.500 49.000 13.500 ;
        RECT 54.000 12.500 55.000 20.500 ;
        RECT 53.500 10.500 55.500 12.500 ;
        RECT 24.500 9.000 26.500 9.500 ;
        RECT 48.000 8.500 50.000 9.500 ;
        RECT 44.500 7.500 50.000 8.500 ;
        RECT 19.000 6.500 21.000 7.500 ;
        RECT 26.000 6.500 28.000 7.500 ;
        RECT 39.500 6.500 41.500 7.500 ;
        RECT 19.000 5.500 28.000 6.500 ;
        RECT 34.500 5.500 41.500 6.500 ;
        RECT 26.000 4.500 27.000 5.500 ;
        RECT 34.500 4.500 35.500 5.500 ;
        RECT 44.500 4.500 45.500 7.500 ;
        RECT 54.000 4.500 55.000 10.500 ;
        RECT 0.500 2.500 2.500 4.500 ;
        RECT 6.500 2.500 8.500 4.500 ;
        RECT 15.000 3.500 18.000 4.500 ;
        RECT 15.000 2.500 17.000 3.500 ;
        RECT 25.000 2.500 27.000 4.500 ;
        RECT 33.500 2.500 35.500 4.500 ;
        RECT 43.500 2.500 45.500 4.500 ;
        RECT 53.000 2.500 55.000 4.500 ;
      LAYER ML2 ;
        RECT 21.000 17.500 23.000 19.500 ;
        RECT 27.000 17.500 29.000 19.500 ;
        RECT 37.000 17.500 39.000 19.500 ;
        RECT 22.000 11.000 23.000 17.500 ;
        RECT 21.000 9.000 23.000 11.000 ;
        RECT 27.500 7.500 28.500 17.500 ;
        RECT 26.000 5.500 28.500 7.500 ;
        RECT 37.500 7.500 38.500 17.500 ;
        RECT 37.500 6.500 41.500 7.500 ;
        RECT 39.500 5.500 41.500 6.500 ;
      LAYER POL ;
        RECT 2.500 19.000 3.500 27.500 ;
        RECT 5.500 19.500 6.500 27.500 ;
        RECT 2.000 18.000 3.500 19.000 ;
        RECT 2.000 11.000 3.000 18.000 ;
        RECT 4.500 17.500 6.500 19.500 ;
        RECT 4.000 13.500 6.000 14.000 ;
        RECT 9.000 13.500 11.000 14.000 ;
        RECT 4.000 12.500 11.000 13.500 ;
        RECT 4.000 12.000 6.000 12.500 ;
        RECT 9.000 12.000 11.000 12.500 ;
        RECT 12.000 11.000 13.000 27.500 ;
        RECT 14.000 14.000 15.000 27.500 ;
        RECT 17.000 17.000 18.000 27.500 ;
        RECT 16.000 15.000 18.000 17.000 ;
        RECT 14.000 13.000 16.000 14.000 ;
        RECT 14.000 12.000 18.000 13.000 ;
        RECT 2.000 10.000 5.500 11.000 ;
        RECT 2.500 9.000 5.500 10.000 ;
        RECT 11.000 9.000 13.000 11.000 ;
        RECT 2.500 1.500 3.500 9.000 ;
        RECT 4.500 5.500 6.500 7.500 ;
        RECT 5.500 1.500 6.500 5.500 ;
        RECT 12.000 1.500 13.000 9.000 ;
        RECT 14.000 5.500 16.000 7.500 ;
        RECT 14.000 1.500 15.000 5.500 ;
        RECT 17.000 1.500 18.000 12.000 ;
        RECT 19.000 7.500 20.000 27.500 ;
        RECT 22.000 19.500 23.000 27.500 ;
        RECT 21.000 17.500 23.000 19.500 ;
        RECT 25.000 15.000 26.000 27.500 ;
        RECT 28.000 19.500 29.000 27.500 ;
        RECT 27.000 17.500 29.000 19.500 ;
        RECT 30.000 17.500 31.000 27.500 ;
        RECT 24.000 14.000 26.000 15.000 ;
        RECT 30.000 15.500 32.000 17.500 ;
        RECT 24.000 11.000 25.000 14.000 ;
        RECT 27.000 12.000 29.000 14.000 ;
        RECT 21.000 9.000 23.000 11.000 ;
        RECT 19.000 5.500 21.000 7.500 ;
        RECT 19.000 1.500 20.000 5.500 ;
        RECT 22.000 1.500 23.000 9.000 ;
        RECT 24.000 9.000 26.500 11.000 ;
        RECT 28.000 9.500 29.000 12.000 ;
        RECT 30.000 11.500 31.000 15.500 ;
        RECT 33.000 14.500 34.000 27.500 ;
        RECT 32.000 12.500 34.000 14.500 ;
        RECT 35.000 14.500 36.000 27.500 ;
        RECT 38.000 19.500 39.000 27.500 ;
        RECT 37.000 17.500 39.000 19.500 ;
        RECT 37.000 14.500 39.000 15.000 ;
        RECT 35.000 13.500 39.000 14.500 ;
        RECT 37.000 13.000 39.000 13.500 ;
        RECT 30.000 10.500 36.500 11.500 ;
        RECT 24.000 1.500 25.000 9.000 ;
        RECT 28.000 8.500 33.500 9.500 ;
        RECT 26.000 6.500 28.000 7.500 ;
        RECT 26.000 5.500 31.500 6.500 ;
        RECT 30.500 1.500 31.500 5.500 ;
        RECT 32.500 1.500 33.500 8.500 ;
        RECT 35.500 1.500 36.500 10.500 ;
        RECT 37.500 1.500 38.500 13.000 ;
        RECT 41.000 12.500 42.000 27.500 ;
        RECT 49.000 17.500 50.000 27.500 ;
        RECT 52.000 19.500 53.000 27.500 ;
        RECT 51.000 17.500 53.000 19.500 ;
        RECT 48.000 15.500 50.000 17.500 ;
        RECT 41.000 11.500 45.000 12.500 ;
        RECT 42.500 10.500 45.000 11.500 ;
        RECT 39.500 5.500 41.500 7.500 ;
        RECT 40.500 1.500 41.500 5.500 ;
        RECT 42.500 1.500 43.500 10.500 ;
        RECT 48.000 7.500 50.000 9.500 ;
        RECT 49.000 1.500 50.000 7.500 ;
        RECT 51.000 5.500 53.000 7.500 ;
        RECT 52.000 1.500 53.000 5.500 ;
  END
END sff1m2

#--------EOF---------

MACRO sff1m2_r
  CLASS CORE ;
  FOREIGN sff1m2_r ;
  ORIGIN 0.000 0.000 ;
  SIZE 62.500 BY 29.000 ;
  SYMMETRY X Y R90 ;
  SITE core ;
  PIN VSS
    DIRECTION INOUT ;
    USE GROUND ;
    SHAPE ABUTMENT ;
    PORT
      LAYER ML1 ;
        RECT 0.500 1.000 2.500 4.500 ;
        RECT 10.000 1.000 12.000 4.800 ;
        RECT 16.500 1.000 18.500 4.800 ;
        RECT 26.500 1.000 28.500 4.800 ;
        RECT 35.000 1.000 37.000 4.800 ;
        RECT 45.000 1.000 47.000 4.800 ;
        RECT 56.500 1.000 58.500 4.800 ;
        RECT -0.500 -1.000 63.000 1.000 ;
    END
  END VSS
  PIN VDD
    DIRECTION INOUT ;
    USE POWER ;
    SHAPE ABUTMENT ;
    PORT
      LAYER ML1 ;
        RECT -0.500 28.000 63.000 30.000 ;
        RECT 0.500 20.500 2.500 28.000 ;
        RECT 10.000 20.500 12.000 28.000 ;
        RECT 16.500 20.500 18.500 28.000 ;
        RECT 26.500 20.500 28.500 28.000 ;
        RECT 32.500 20.500 34.500 28.000 ;
        RECT 42.500 20.500 44.500 28.000 ;
        RECT 48.500 20.500 50.500 28.000 ;
        RECT 56.500 20.500 58.500 28.000 ;
    END
  END VDD
  PIN QB
    DIRECTION INPUT ;
    USE SIGNAL ;
    PORT
      LAYER ML1 ;
        RECT 53.500 20.500 55.500 26.500 ;
        RECT 54.500 19.500 55.500 20.500 ;
        RECT 54.500 18.500 59.500 19.500 ;
        RECT 57.500 17.500 59.500 18.500 ;
        RECT 58.000 7.500 59.000 17.500 ;
        RECT 57.500 6.500 59.500 7.500 ;
        RECT 54.500 5.500 59.500 6.500 ;
        RECT 54.500 4.500 55.500 5.500 ;
        RECT 53.500 2.500 55.500 4.500 ;
    END
  END QB
  PIN CK
    DIRECTION INPUT ;
    USE SIGNAL ;
    PORT
      LAYER ML2 ;
        RECT 1.000 14.500 3.000 16.500 ;
    END
  END CK
  PIN D
    DIRECTION INPUT ;
    USE SIGNAL ;
    PORT
      LAYER ML2 ;
        RECT 17.500 9.000 19.500 11.000 ;
    END
  END D
  PIN S
    DIRECTION INPUT ;
    USE SIGNAL ;
    PORT
      LAYER ML2 ;
        RECT 49.500 10.500 51.500 12.500 ;
    END
  END S
  PIN Q
    DIRECTION INPUT ;
    USE SIGNAL ;
    PORT
      LAYER ML2 ;
        RECT 60.000 10.500 62.000 12.500 ;
    END
  END Q
  OBS
      LAYER ML1 ;
        RECT 3.500 20.500 5.500 26.500 ;
        RECT 7.000 20.500 9.000 26.500 ;
        RECT 13.000 20.500 15.000 26.500 ;
        RECT 21.500 20.500 23.500 26.500 ;
        RECT 29.500 20.500 31.500 26.500 ;
        RECT 37.500 20.500 39.500 26.500 ;
        RECT 45.500 20.500 47.500 26.500 ;
        RECT 59.500 20.500 61.500 26.500 ;
        RECT 1.000 14.500 3.000 16.500 ;
        RECT 4.000 14.000 5.000 20.500 ;
        RECT 7.500 19.000 8.500 20.500 ;
        RECT 11.000 19.000 13.000 19.500 ;
        RECT 7.500 18.000 13.000 19.000 ;
        RECT 4.000 12.000 6.500 14.000 ;
        RECT 7.500 13.500 8.500 18.000 ;
        RECT 11.000 17.500 13.000 18.000 ;
        RECT 14.000 16.500 15.000 20.500 ;
        RECT 22.000 19.000 23.000 20.500 ;
        RECT 30.500 19.500 31.500 20.500 ;
        RECT 38.500 19.500 39.500 20.500 ;
        RECT 27.500 19.000 29.500 19.500 ;
        RECT 22.000 18.000 29.500 19.000 ;
        RECT 30.500 18.500 35.500 19.500 ;
        RECT 38.500 18.500 45.500 19.500 ;
        RECT 27.500 17.500 29.500 18.000 ;
        RECT 33.500 17.500 35.500 18.500 ;
        RECT 43.500 17.500 45.500 18.500 ;
        RECT 46.500 17.500 47.500 20.500 ;
        RECT 22.500 16.500 24.500 17.000 ;
        RECT 36.500 16.500 38.500 17.500 ;
        RECT 13.500 15.500 38.500 16.500 ;
        RECT 46.500 16.500 56.500 17.500 ;
        RECT 10.500 13.500 12.500 14.000 ;
        RECT 7.500 12.500 12.500 13.500 ;
        RECT 4.000 4.500 5.000 12.000 ;
        RECT 7.500 6.500 8.500 12.500 ;
        RECT 10.500 12.000 12.500 12.500 ;
        RECT 13.500 10.000 14.500 15.500 ;
        RECT 22.500 15.000 24.500 15.500 ;
        RECT 43.500 14.500 45.500 15.000 ;
        RECT 46.500 14.500 47.500 16.500 ;
        RECT 54.500 15.500 56.500 16.500 ;
        RECT 15.500 13.500 17.500 14.000 ;
        RECT 20.500 13.500 22.500 14.000 ;
        RECT 33.500 13.500 35.500 14.000 ;
        RECT 38.500 13.500 40.500 14.500 ;
        RECT 15.500 12.500 40.500 13.500 ;
        RECT 43.500 13.500 55.500 14.500 ;
        RECT 43.500 13.000 45.500 13.500 ;
        RECT 15.500 12.000 17.500 12.500 ;
        RECT 20.500 12.000 22.500 12.500 ;
        RECT 33.500 12.000 35.500 12.500 ;
        RECT 13.500 9.000 15.000 10.000 ;
        RECT 17.500 9.000 19.500 11.000 ;
        RECT 27.500 10.500 29.500 11.000 ;
        RECT 23.500 9.500 29.500 10.500 ;
        RECT 11.000 6.500 13.000 7.500 ;
        RECT 7.500 5.500 13.000 6.500 ;
        RECT 14.000 6.500 15.000 9.000 ;
        RECT 20.500 6.500 22.500 7.500 ;
        RECT 14.000 5.500 22.500 6.500 ;
        RECT 7.500 4.500 8.500 5.500 ;
        RECT 14.000 4.500 15.000 5.500 ;
        RECT 23.500 4.500 24.500 9.500 ;
        RECT 27.500 9.000 29.500 9.500 ;
        RECT 31.000 10.500 33.000 11.000 ;
        RECT 49.500 10.500 51.500 12.500 ;
        RECT 31.000 9.500 51.500 10.500 ;
        RECT 54.500 9.500 55.500 13.500 ;
        RECT 60.500 12.500 61.500 20.500 ;
        RECT 60.000 10.500 62.000 12.500 ;
        RECT 31.000 9.000 33.000 9.500 ;
        RECT 54.500 8.500 56.500 9.500 ;
        RECT 51.000 7.500 56.500 8.500 ;
        RECT 25.500 6.500 27.500 7.500 ;
        RECT 32.500 6.500 34.500 7.500 ;
        RECT 46.000 6.500 48.000 7.500 ;
        RECT 25.500 5.500 34.500 6.500 ;
        RECT 41.000 5.500 48.000 6.500 ;
        RECT 32.500 4.500 33.500 5.500 ;
        RECT 41.000 4.500 42.000 5.500 ;
        RECT 51.000 4.500 52.000 7.500 ;
        RECT 60.500 4.500 61.500 10.500 ;
        RECT 3.500 2.500 5.500 4.500 ;
        RECT 7.000 2.500 9.000 4.500 ;
        RECT 13.000 2.500 15.000 4.500 ;
        RECT 21.500 3.500 24.500 4.500 ;
        RECT 21.500 2.500 23.500 3.500 ;
        RECT 31.500 2.500 33.500 4.500 ;
        RECT 40.000 2.500 42.000 4.500 ;
        RECT 50.000 2.500 52.000 4.500 ;
        RECT 59.500 2.500 61.500 4.500 ;
      LAYER ML2 ;
        RECT 27.500 17.500 29.500 19.500 ;
        RECT 33.500 17.500 35.500 19.500 ;
        RECT 43.500 17.500 45.500 19.500 ;
        RECT 28.500 11.000 29.500 17.500 ;
        RECT 27.500 9.000 29.500 11.000 ;
        RECT 34.000 7.500 35.000 17.500 ;
        RECT 32.500 5.500 35.000 7.500 ;
        RECT 44.000 7.500 45.000 17.500 ;
        RECT 44.000 6.500 48.000 7.500 ;
        RECT 46.000 5.500 48.000 6.500 ;
      LAYER POL ;
        RECT 2.500 16.500 3.500 27.500 ;
        RECT 9.000 19.000 10.000 27.500 ;
        RECT 12.000 19.500 13.000 27.500 ;
        RECT 1.000 14.500 3.500 16.500 ;
        RECT 2.500 1.500 3.500 14.500 ;
        RECT 8.500 18.000 10.000 19.000 ;
        RECT 8.500 14.000 9.500 18.000 ;
        RECT 11.000 17.500 13.000 19.500 ;
        RECT 4.500 12.000 9.500 14.000 ;
        RECT 10.500 13.500 12.500 14.000 ;
        RECT 15.500 13.500 17.500 14.000 ;
        RECT 10.500 12.500 17.500 13.500 ;
        RECT 10.500 12.000 12.500 12.500 ;
        RECT 15.500 12.000 17.500 12.500 ;
        RECT 8.500 11.000 9.500 12.000 ;
        RECT 18.500 11.000 19.500 27.500 ;
        RECT 20.500 14.000 21.500 27.500 ;
        RECT 23.500 17.000 24.500 27.500 ;
        RECT 22.500 15.000 24.500 17.000 ;
        RECT 20.500 13.000 22.500 14.000 ;
        RECT 20.500 12.000 24.500 13.000 ;
        RECT 8.500 10.000 10.000 11.000 ;
        RECT 9.000 1.500 10.000 10.000 ;
        RECT 17.500 9.000 19.500 11.000 ;
        RECT 11.000 5.500 13.000 7.500 ;
        RECT 12.000 1.500 13.000 5.500 ;
        RECT 18.500 1.500 19.500 9.000 ;
        RECT 20.500 5.500 22.500 7.500 ;
        RECT 20.500 1.500 21.500 5.500 ;
        RECT 23.500 1.500 24.500 12.000 ;
        RECT 25.500 7.500 26.500 27.500 ;
        RECT 28.500 19.500 29.500 27.500 ;
        RECT 27.500 17.500 29.500 19.500 ;
        RECT 31.500 15.000 32.500 27.500 ;
        RECT 34.500 19.500 35.500 27.500 ;
        RECT 33.500 17.500 35.500 19.500 ;
        RECT 36.500 17.500 37.500 27.500 ;
        RECT 30.500 14.000 32.500 15.000 ;
        RECT 36.500 15.500 38.500 17.500 ;
        RECT 30.500 11.000 31.500 14.000 ;
        RECT 33.500 12.000 35.500 14.000 ;
        RECT 27.500 9.000 29.500 11.000 ;
        RECT 25.500 5.500 27.500 7.500 ;
        RECT 25.500 1.500 26.500 5.500 ;
        RECT 28.500 1.500 29.500 9.000 ;
        RECT 30.500 9.000 33.000 11.000 ;
        RECT 34.500 9.500 35.500 12.000 ;
        RECT 36.500 11.500 37.500 15.500 ;
        RECT 39.500 14.500 40.500 27.500 ;
        RECT 38.500 12.500 40.500 14.500 ;
        RECT 41.500 14.500 42.500 27.500 ;
        RECT 44.500 19.500 45.500 27.500 ;
        RECT 43.500 17.500 45.500 19.500 ;
        RECT 43.500 14.500 45.500 15.000 ;
        RECT 41.500 13.500 45.500 14.500 ;
        RECT 43.500 13.000 45.500 13.500 ;
        RECT 36.500 10.500 43.000 11.500 ;
        RECT 30.500 1.500 31.500 9.000 ;
        RECT 34.500 8.500 40.000 9.500 ;
        RECT 32.500 6.500 34.500 7.500 ;
        RECT 32.500 5.500 38.000 6.500 ;
        RECT 37.000 1.500 38.000 5.500 ;
        RECT 39.000 1.500 40.000 8.500 ;
        RECT 42.000 1.500 43.000 10.500 ;
        RECT 44.000 1.500 45.000 13.000 ;
        RECT 47.500 12.500 48.500 27.500 ;
        RECT 55.500 17.500 56.500 27.500 ;
        RECT 58.500 19.500 59.500 27.500 ;
        RECT 57.500 17.500 59.500 19.500 ;
        RECT 54.500 15.500 56.500 17.500 ;
        RECT 47.500 11.500 51.500 12.500 ;
        RECT 49.000 10.500 51.500 11.500 ;
        RECT 46.000 5.500 48.000 7.500 ;
        RECT 47.000 1.500 48.000 5.500 ;
        RECT 49.000 1.500 50.000 10.500 ;
        RECT 54.500 7.500 56.500 9.500 ;
        RECT 55.500 1.500 56.500 7.500 ;
        RECT 57.500 5.500 59.500 7.500 ;
        RECT 58.500 1.500 59.500 5.500 ;
  END
END sff1m2_r

#--------EOF---------


END LIBRARY
